VERSION 5.8 ;
BUSBITCHARS "[]" ;
DIVIDERCHAR "/" ;
UNITS
    DATABASE MICRONS 1000 ;
END UNITS

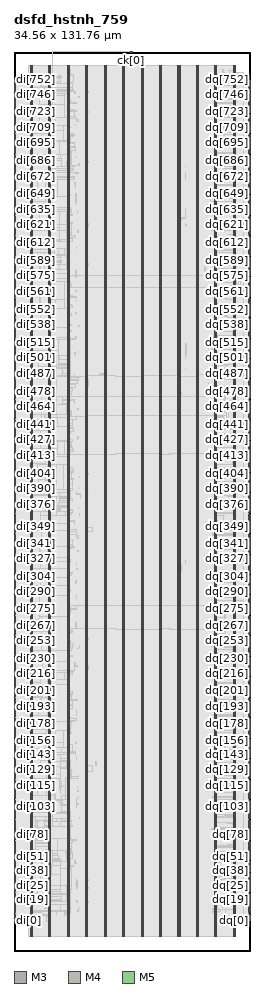
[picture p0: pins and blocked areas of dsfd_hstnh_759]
MACRO dsfd_hstnh_759
  FOREIGN dsfd_hstnh_759 0 0 ;
  CLASS BLOCK ;
  SIZE 34.56 BY 131.76 ;
  PIN ck[0]
    DIRECTION INPUT ;
    USE SIGNAL ;
    PORT
      LAYER M3 ;
        RECT  17.28 131.616 17.298 131.76 ;
    END
    PORT
      LAYER M3 ;
        RECT  17.1 131.515 17.298 131.628 ;
    END
  END ck[0]
  PIN di[0]
    DIRECTION INPUT ;
    USE SIGNAL ;
    PORT
      LAYER M4 ;
        RECT  0 4.416 0.192 4.44 ;
    END
  END di[0]
  PIN di[100]
    DIRECTION INPUT ;
    USE SIGNAL ;
    PORT
      LAYER M4 ;
        RECT  0 20.64 0.192 20.664 ;
    END
  END di[100]
  PIN di[101]
    DIRECTION INPUT ;
    USE SIGNAL ;
    PORT
      LAYER M4 ;
        RECT  0 20.784 0.192 20.808 ;
    END
  END di[101]
  PIN di[102]
    DIRECTION INPUT ;
    USE SIGNAL ;
    PORT
      LAYER M4 ;
        RECT  0 20.976 0.192 21 ;
    END
  END di[102]
  PIN di[103]
    DIRECTION INPUT ;
    USE SIGNAL ;
    PORT
      LAYER M4 ;
        RECT  0 21.12 0.192 21.144 ;
    END
  END di[103]
  PIN di[104]
    DIRECTION INPUT ;
    USE SIGNAL ;
    PORT
      LAYER M4 ;
        RECT  0 21.264 0.192 21.288 ;
    END
  END di[104]
  PIN di[105]
    DIRECTION INPUT ;
    USE SIGNAL ;
    PORT
      LAYER M4 ;
        RECT  0 21.456 0.192 21.48 ;
    END
  END di[105]
  PIN di[106]
    DIRECTION INPUT ;
    USE SIGNAL ;
    PORT
      LAYER M4 ;
        RECT  0 21.6 0.192 21.624 ;
    END
  END di[106]
  PIN di[107]
    DIRECTION INPUT ;
    USE SIGNAL ;
    PORT
      LAYER M4 ;
        RECT  0 21.792 0.192 21.816 ;
    END
  END di[107]
  PIN di[108]
    DIRECTION INPUT ;
    USE SIGNAL ;
    PORT
      LAYER M4 ;
        RECT  0 21.936 0.192 21.96 ;
    END
  END di[108]
  PIN di[109]
    DIRECTION INPUT ;
    USE SIGNAL ;
    PORT
      LAYER M4 ;
        RECT  0 22.08 0.192 22.104 ;
    END
  END di[109]
  PIN di[10]
    DIRECTION INPUT ;
    USE SIGNAL ;
    PORT
      LAYER M4 ;
        RECT  0 6.048 0.192 6.072 ;
    END
  END di[10]
  PIN di[110]
    DIRECTION INPUT ;
    USE SIGNAL ;
    PORT
      LAYER M4 ;
        RECT  0 22.272 0.192 22.296 ;
    END
  END di[110]
  PIN di[111]
    DIRECTION INPUT ;
    USE SIGNAL ;
    PORT
      LAYER M4 ;
        RECT  0 22.416 0.192 22.44 ;
    END
  END di[111]
  PIN di[112]
    DIRECTION INPUT ;
    USE SIGNAL ;
    PORT
      LAYER M4 ;
        RECT  0 22.56 0.192 22.584 ;
    END
  END di[112]
  PIN di[113]
    DIRECTION INPUT ;
    USE SIGNAL ;
    PORT
      LAYER M4 ;
        RECT  0 22.752 0.192 22.776 ;
    END
  END di[113]
  PIN di[114]
    DIRECTION INPUT ;
    USE SIGNAL ;
    PORT
      LAYER M4 ;
        RECT  0 22.896 0.192 22.92 ;
    END
  END di[114]
  PIN di[115]
    DIRECTION INPUT ;
    USE SIGNAL ;
    PORT
      LAYER M4 ;
        RECT  0 23.088 0.192 23.112 ;
    END
  END di[115]
  PIN di[116]
    DIRECTION INPUT ;
    USE SIGNAL ;
    PORT
      LAYER M4 ;
        RECT  0 23.232 0.192 23.256 ;
    END
  END di[116]
  PIN di[117]
    DIRECTION INPUT ;
    USE SIGNAL ;
    PORT
      LAYER M4 ;
        RECT  0 23.376 0.192 23.4 ;
    END
  END di[117]
  PIN di[118]
    DIRECTION INPUT ;
    USE SIGNAL ;
    PORT
      LAYER M4 ;
        RECT  0 23.568 0.192 23.592 ;
    END
  END di[118]
  PIN di[119]
    DIRECTION INPUT ;
    USE SIGNAL ;
    PORT
      LAYER M4 ;
        RECT  0 23.712 0.192 23.736 ;
    END
  END di[119]
  PIN di[11]
    DIRECTION INPUT ;
    USE SIGNAL ;
    PORT
      LAYER M4 ;
        RECT  0 6.192 0.192 6.216 ;
    END
  END di[11]
  PIN di[120]
    DIRECTION INPUT ;
    USE SIGNAL ;
    PORT
      LAYER M4 ;
        RECT  0 23.856 0.192 23.88 ;
    END
  END di[120]
  PIN di[121]
    DIRECTION INPUT ;
    USE SIGNAL ;
    PORT
      LAYER M4 ;
        RECT  0 24.048 0.192 24.072 ;
    END
  END di[121]
  PIN di[122]
    DIRECTION INPUT ;
    USE SIGNAL ;
    PORT
      LAYER M4 ;
        RECT  0 24.192 0.192 24.216 ;
    END
  END di[122]
  PIN di[123]
    DIRECTION INPUT ;
    USE SIGNAL ;
    PORT
      LAYER M4 ;
        RECT  0 24.384 0.192 24.408 ;
    END
  END di[123]
  PIN di[124]
    DIRECTION INPUT ;
    USE SIGNAL ;
    PORT
      LAYER M4 ;
        RECT  0 24.528 0.192 24.552 ;
    END
  END di[124]
  PIN di[125]
    DIRECTION INPUT ;
    USE SIGNAL ;
    PORT
      LAYER M4 ;
        RECT  0 24.672 0.192 24.696 ;
    END
  END di[125]
  PIN di[126]
    DIRECTION INPUT ;
    USE SIGNAL ;
    PORT
      LAYER M4 ;
        RECT  0 24.864 0.192 24.888 ;
    END
  END di[126]
  PIN di[127]
    DIRECTION INPUT ;
    USE SIGNAL ;
    PORT
      LAYER M4 ;
        RECT  0 25.008 0.192 25.032 ;
    END
  END di[127]
  PIN di[128]
    DIRECTION INPUT ;
    USE SIGNAL ;
    PORT
      LAYER M4 ;
        RECT  0 25.2 0.192 25.224 ;
    END
  END di[128]
  PIN di[129]
    DIRECTION INPUT ;
    USE SIGNAL ;
    PORT
      LAYER M4 ;
        RECT  0 25.344 0.192 25.368 ;
    END
  END di[129]
  PIN di[12]
    DIRECTION INPUT ;
    USE SIGNAL ;
    PORT
      LAYER M4 ;
        RECT  0 6.336 0.192 6.36 ;
    END
  END di[12]
  PIN di[130]
    DIRECTION INPUT ;
    USE SIGNAL ;
    PORT
      LAYER M4 ;
        RECT  0 25.488 0.192 25.512 ;
    END
  END di[130]
  PIN di[131]
    DIRECTION INPUT ;
    USE SIGNAL ;
    PORT
      LAYER M4 ;
        RECT  0 25.68 0.192 25.704 ;
    END
  END di[131]
  PIN di[132]
    DIRECTION INPUT ;
    USE SIGNAL ;
    PORT
      LAYER M4 ;
        RECT  0 25.824 0.192 25.848 ;
    END
  END di[132]
  PIN di[133]
    DIRECTION INPUT ;
    USE SIGNAL ;
    PORT
      LAYER M4 ;
        RECT  0 25.968 0.192 25.992 ;
    END
  END di[133]
  PIN di[134]
    DIRECTION INPUT ;
    USE SIGNAL ;
    PORT
      LAYER M4 ;
        RECT  0 26.16 0.192 26.184 ;
    END
  END di[134]
  PIN di[135]
    DIRECTION INPUT ;
    USE SIGNAL ;
    PORT
      LAYER M4 ;
        RECT  0 26.304 0.192 26.328 ;
    END
  END di[135]
  PIN di[136]
    DIRECTION INPUT ;
    USE SIGNAL ;
    PORT
      LAYER M4 ;
        RECT  0 26.496 0.192 26.52 ;
    END
  END di[136]
  PIN di[137]
    DIRECTION INPUT ;
    USE SIGNAL ;
    PORT
      LAYER M4 ;
        RECT  0 26.64 0.192 26.664 ;
    END
  END di[137]
  PIN di[138]
    DIRECTION INPUT ;
    USE SIGNAL ;
    PORT
      LAYER M4 ;
        RECT  0 26.784 0.192 26.808 ;
    END
  END di[138]
  PIN di[139]
    DIRECTION INPUT ;
    USE SIGNAL ;
    PORT
      LAYER M4 ;
        RECT  0 26.976 0.192 27 ;
    END
  END di[139]
  PIN di[13]
    DIRECTION INPUT ;
    USE SIGNAL ;
    PORT
      LAYER M4 ;
        RECT  0 6.528 0.192 6.552 ;
    END
  END di[13]
  PIN di[140]
    DIRECTION INPUT ;
    USE SIGNAL ;
    PORT
      LAYER M4 ;
        RECT  0 27.12 0.192 27.144 ;
    END
  END di[140]
  PIN di[141]
    DIRECTION INPUT ;
    USE SIGNAL ;
    PORT
      LAYER M4 ;
        RECT  0 27.264 0.192 27.288 ;
    END
  END di[141]
  PIN di[142]
    DIRECTION INPUT ;
    USE SIGNAL ;
    PORT
      LAYER M4 ;
        RECT  0 27.456 0.192 27.48 ;
    END
  END di[142]
  PIN di[143]
    DIRECTION INPUT ;
    USE SIGNAL ;
    PORT
      LAYER M4 ;
        RECT  0 27.6 0.192 27.624 ;
    END
  END di[143]
  PIN di[144]
    DIRECTION INPUT ;
    USE SIGNAL ;
    PORT
      LAYER M4 ;
        RECT  0 27.792 0.192 27.816 ;
    END
  END di[144]
  PIN di[145]
    DIRECTION INPUT ;
    USE SIGNAL ;
    PORT
      LAYER M4 ;
        RECT  0 27.936 0.192 27.96 ;
    END
  END di[145]
  PIN di[146]
    DIRECTION INPUT ;
    USE SIGNAL ;
    PORT
      LAYER M4 ;
        RECT  0 28.08 0.192 28.104 ;
    END
  END di[146]
  PIN di[147]
    DIRECTION INPUT ;
    USE SIGNAL ;
    PORT
      LAYER M4 ;
        RECT  0 28.272 0.192 28.296 ;
    END
  END di[147]
  PIN di[148]
    DIRECTION INPUT ;
    USE SIGNAL ;
    PORT
      LAYER M4 ;
        RECT  0 28.416 0.192 28.44 ;
    END
  END di[148]
  PIN di[149]
    DIRECTION INPUT ;
    USE SIGNAL ;
    PORT
      LAYER M4 ;
        RECT  0 28.56 0.192 28.584 ;
    END
  END di[149]
  PIN di[14]
    DIRECTION INPUT ;
    USE SIGNAL ;
    PORT
      LAYER M4 ;
        RECT  0 6.672 0.192 6.696 ;
    END
  END di[14]
  PIN di[150]
    DIRECTION INPUT ;
    USE SIGNAL ;
    PORT
      LAYER M4 ;
        RECT  0 28.752 0.192 28.776 ;
    END
  END di[150]
  PIN di[151]
    DIRECTION INPUT ;
    USE SIGNAL ;
    PORT
      LAYER M4 ;
        RECT  0 28.896 0.192 28.92 ;
    END
  END di[151]
  PIN di[152]
    DIRECTION INPUT ;
    USE SIGNAL ;
    PORT
      LAYER M4 ;
        RECT  0 29.088 0.192 29.112 ;
    END
  END di[152]
  PIN di[153]
    DIRECTION INPUT ;
    USE SIGNAL ;
    PORT
      LAYER M4 ;
        RECT  0 29.232 0.192 29.256 ;
    END
  END di[153]
  PIN di[154]
    DIRECTION INPUT ;
    USE SIGNAL ;
    PORT
      LAYER M4 ;
        RECT  0 29.376 0.192 29.4 ;
    END
  END di[154]
  PIN di[155]
    DIRECTION INPUT ;
    USE SIGNAL ;
    PORT
      LAYER M4 ;
        RECT  0 29.568 0.192 29.592 ;
    END
  END di[155]
  PIN di[156]
    DIRECTION INPUT ;
    USE SIGNAL ;
    PORT
      LAYER M4 ;
        RECT  0 29.712 0.192 29.736 ;
    END
  END di[156]
  PIN di[157]
    DIRECTION INPUT ;
    USE SIGNAL ;
    PORT
      LAYER M4 ;
        RECT  0 29.904 0.192 29.928 ;
    END
  END di[157]
  PIN di[158]
    DIRECTION INPUT ;
    USE SIGNAL ;
    PORT
      LAYER M4 ;
        RECT  0 30.048 0.192 30.072 ;
    END
  END di[158]
  PIN di[159]
    DIRECTION INPUT ;
    USE SIGNAL ;
    PORT
      LAYER M4 ;
        RECT  0 30.192 0.192 30.216 ;
    END
  END di[159]
  PIN di[15]
    DIRECTION INPUT ;
    USE SIGNAL ;
    PORT
      LAYER M4 ;
        RECT  0 6.864 0.192 6.888 ;
    END
  END di[15]
  PIN di[160]
    DIRECTION INPUT ;
    USE SIGNAL ;
    PORT
      LAYER M4 ;
        RECT  0 30.384 0.192 30.408 ;
    END
  END di[160]
  PIN di[161]
    DIRECTION INPUT ;
    USE SIGNAL ;
    PORT
      LAYER M4 ;
        RECT  0 30.528 0.192 30.552 ;
    END
  END di[161]
  PIN di[162]
    DIRECTION INPUT ;
    USE SIGNAL ;
    PORT
      LAYER M4 ;
        RECT  0 30.672 0.192 30.696 ;
    END
  END di[162]
  PIN di[163]
    DIRECTION INPUT ;
    USE SIGNAL ;
    PORT
      LAYER M4 ;
        RECT  0 30.864 0.192 30.888 ;
    END
  END di[163]
  PIN di[164]
    DIRECTION INPUT ;
    USE SIGNAL ;
    PORT
      LAYER M4 ;
        RECT  0 31.008 0.192 31.032 ;
    END
  END di[164]
  PIN di[165]
    DIRECTION INPUT ;
    USE SIGNAL ;
    PORT
      LAYER M4 ;
        RECT  0 31.2 0.192 31.224 ;
    END
  END di[165]
  PIN di[166]
    DIRECTION INPUT ;
    USE SIGNAL ;
    PORT
      LAYER M4 ;
        RECT  0 31.344 0.192 31.368 ;
    END
  END di[166]
  PIN di[167]
    DIRECTION INPUT ;
    USE SIGNAL ;
    PORT
      LAYER M4 ;
        RECT  0 31.488 0.192 31.512 ;
    END
  END di[167]
  PIN di[168]
    DIRECTION INPUT ;
    USE SIGNAL ;
    PORT
      LAYER M4 ;
        RECT  0 31.68 0.192 31.704 ;
    END
  END di[168]
  PIN di[169]
    DIRECTION INPUT ;
    USE SIGNAL ;
    PORT
      LAYER M4 ;
        RECT  0 31.824 0.192 31.848 ;
    END
  END di[169]
  PIN di[16]
    DIRECTION INPUT ;
    USE SIGNAL ;
    PORT
      LAYER M4 ;
        RECT  0 7.008 0.192 7.032 ;
    END
  END di[16]
  PIN di[170]
    DIRECTION INPUT ;
    USE SIGNAL ;
    PORT
      LAYER M4 ;
        RECT  0 31.968 0.192 31.992 ;
    END
  END di[170]
  PIN di[171]
    DIRECTION INPUT ;
    USE SIGNAL ;
    PORT
      LAYER M4 ;
        RECT  0 32.16 0.192 32.184 ;
    END
  END di[171]
  PIN di[172]
    DIRECTION INPUT ;
    USE SIGNAL ;
    PORT
      LAYER M4 ;
        RECT  0 32.304 0.192 32.328 ;
    END
  END di[172]
  PIN di[173]
    DIRECTION INPUT ;
    USE SIGNAL ;
    PORT
      LAYER M4 ;
        RECT  0 32.496 0.192 32.52 ;
    END
  END di[173]
  PIN di[174]
    DIRECTION INPUT ;
    USE SIGNAL ;
    PORT
      LAYER M4 ;
        RECT  0 32.64 0.192 32.664 ;
    END
  END di[174]
  PIN di[175]
    DIRECTION INPUT ;
    USE SIGNAL ;
    PORT
      LAYER M4 ;
        RECT  0 32.784 0.192 32.808 ;
    END
  END di[175]
  PIN di[176]
    DIRECTION INPUT ;
    USE SIGNAL ;
    PORT
      LAYER M4 ;
        RECT  0 32.976 0.192 33 ;
    END
  END di[176]
  PIN di[177]
    DIRECTION INPUT ;
    USE SIGNAL ;
    PORT
      LAYER M4 ;
        RECT  0 33.12 0.192 33.144 ;
    END
  END di[177]
  PIN di[178]
    DIRECTION INPUT ;
    USE SIGNAL ;
    PORT
      LAYER M4 ;
        RECT  0 33.264 0.192 33.288 ;
    END
  END di[178]
  PIN di[179]
    DIRECTION INPUT ;
    USE SIGNAL ;
    PORT
      LAYER M4 ;
        RECT  0 33.456 0.192 33.48 ;
    END
  END di[179]
  PIN di[17]
    DIRECTION INPUT ;
    USE SIGNAL ;
    PORT
      LAYER M4 ;
        RECT  0 7.152 0.192 7.176 ;
    END
  END di[17]
  PIN di[180]
    DIRECTION INPUT ;
    USE SIGNAL ;
    PORT
      LAYER M4 ;
        RECT  0 33.6 0.192 33.624 ;
    END
  END di[180]
  PIN di[181]
    DIRECTION INPUT ;
    USE SIGNAL ;
    PORT
      LAYER M4 ;
        RECT  0 33.792 0.192 33.816 ;
    END
  END di[181]
  PIN di[182]
    DIRECTION INPUT ;
    USE SIGNAL ;
    PORT
      LAYER M4 ;
        RECT  0 33.936 0.192 33.96 ;
    END
  END di[182]
  PIN di[183]
    DIRECTION INPUT ;
    USE SIGNAL ;
    PORT
      LAYER M4 ;
        RECT  0 34.08 0.192 34.104 ;
    END
  END di[183]
  PIN di[184]
    DIRECTION INPUT ;
    USE SIGNAL ;
    PORT
      LAYER M4 ;
        RECT  0 34.272 0.192 34.296 ;
    END
  END di[184]
  PIN di[185]
    DIRECTION INPUT ;
    USE SIGNAL ;
    PORT
      LAYER M4 ;
        RECT  0 34.416 0.192 34.44 ;
    END
  END di[185]
  PIN di[186]
    DIRECTION INPUT ;
    USE SIGNAL ;
    PORT
      LAYER M4 ;
        RECT  0 34.608 0.192 34.632 ;
    END
  END di[186]
  PIN di[187]
    DIRECTION INPUT ;
    USE SIGNAL ;
    PORT
      LAYER M4 ;
        RECT  0 34.752 0.192 34.776 ;
    END
  END di[187]
  PIN di[188]
    DIRECTION INPUT ;
    USE SIGNAL ;
    PORT
      LAYER M4 ;
        RECT  0 34.896 0.192 34.92 ;
    END
  END di[188]
  PIN di[189]
    DIRECTION INPUT ;
    USE SIGNAL ;
    PORT
      LAYER M4 ;
        RECT  0 35.088 0.192 35.112 ;
    END
  END di[189]
  PIN di[18]
    DIRECTION INPUT ;
    USE SIGNAL ;
    PORT
      LAYER M4 ;
        RECT  0 7.344 0.192 7.368 ;
    END
  END di[18]
  PIN di[190]
    DIRECTION INPUT ;
    USE SIGNAL ;
    PORT
      LAYER M4 ;
        RECT  0 35.232 0.192 35.256 ;
    END
  END di[190]
  PIN di[191]
    DIRECTION INPUT ;
    USE SIGNAL ;
    PORT
      LAYER M4 ;
        RECT  0 35.376 0.192 35.4 ;
    END
  END di[191]
  PIN di[192]
    DIRECTION INPUT ;
    USE SIGNAL ;
    PORT
      LAYER M4 ;
        RECT  0 35.568 0.192 35.592 ;
    END
  END di[192]
  PIN di[193]
    DIRECTION INPUT ;
    USE SIGNAL ;
    PORT
      LAYER M4 ;
        RECT  0 35.712 0.192 35.736 ;
    END
  END di[193]
  PIN di[194]
    DIRECTION INPUT ;
    USE SIGNAL ;
    PORT
      LAYER M4 ;
        RECT  0 35.904 0.192 35.928 ;
    END
  END di[194]
  PIN di[195]
    DIRECTION INPUT ;
    USE SIGNAL ;
    PORT
      LAYER M4 ;
        RECT  0 36.048 0.192 36.072 ;
    END
  END di[195]
  PIN di[196]
    DIRECTION INPUT ;
    USE SIGNAL ;
    PORT
      LAYER M4 ;
        RECT  0 36.192 0.192 36.216 ;
    END
  END di[196]
  PIN di[197]
    DIRECTION INPUT ;
    USE SIGNAL ;
    PORT
      LAYER M4 ;
        RECT  0 36.384 0.192 36.408 ;
    END
  END di[197]
  PIN di[198]
    DIRECTION INPUT ;
    USE SIGNAL ;
    PORT
      LAYER M4 ;
        RECT  0 36.528 0.192 36.552 ;
    END
  END di[198]
  PIN di[199]
    DIRECTION INPUT ;
    USE SIGNAL ;
    PORT
      LAYER M4 ;
        RECT  0 36.672 0.192 36.696 ;
    END
  END di[199]
  PIN di[19]
    DIRECTION INPUT ;
    USE SIGNAL ;
    PORT
      LAYER M4 ;
        RECT  0 7.488 0.192 7.512 ;
    END
  END di[19]
  PIN di[1]
    DIRECTION INPUT ;
    USE SIGNAL ;
    PORT
      LAYER M4 ;
        RECT  0 4.56 0.192 4.584 ;
    END
  END di[1]
  PIN di[200]
    DIRECTION INPUT ;
    USE SIGNAL ;
    PORT
      LAYER M4 ;
        RECT  0 36.864 0.192 36.888 ;
    END
  END di[200]
  PIN di[201]
    DIRECTION INPUT ;
    USE SIGNAL ;
    PORT
      LAYER M4 ;
        RECT  0 37.008 0.192 37.032 ;
    END
  END di[201]
  PIN di[202]
    DIRECTION INPUT ;
    USE SIGNAL ;
    PORT
      LAYER M4 ;
        RECT  0 37.2 0.192 37.224 ;
    END
  END di[202]
  PIN di[203]
    DIRECTION INPUT ;
    USE SIGNAL ;
    PORT
      LAYER M4 ;
        RECT  0 37.344 0.192 37.368 ;
    END
  END di[203]
  PIN di[204]
    DIRECTION INPUT ;
    USE SIGNAL ;
    PORT
      LAYER M4 ;
        RECT  0 37.488 0.192 37.512 ;
    END
  END di[204]
  PIN di[205]
    DIRECTION INPUT ;
    USE SIGNAL ;
    PORT
      LAYER M4 ;
        RECT  0 37.68 0.192 37.704 ;
    END
  END di[205]
  PIN di[206]
    DIRECTION INPUT ;
    USE SIGNAL ;
    PORT
      LAYER M4 ;
        RECT  0 37.824 0.192 37.848 ;
    END
  END di[206]
  PIN di[207]
    DIRECTION INPUT ;
    USE SIGNAL ;
    PORT
      LAYER M4 ;
        RECT  0 37.968 0.192 37.992 ;
    END
  END di[207]
  PIN di[208]
    DIRECTION INPUT ;
    USE SIGNAL ;
    PORT
      LAYER M4 ;
        RECT  0 38.16 0.192 38.184 ;
    END
  END di[208]
  PIN di[209]
    DIRECTION INPUT ;
    USE SIGNAL ;
    PORT
      LAYER M4 ;
        RECT  0 38.304 0.192 38.328 ;
    END
  END di[209]
  PIN di[20]
    DIRECTION INPUT ;
    USE SIGNAL ;
    PORT
      LAYER M4 ;
        RECT  0 7.68 0.192 7.704 ;
    END
  END di[20]
  PIN di[210]
    DIRECTION INPUT ;
    USE SIGNAL ;
    PORT
      LAYER M4 ;
        RECT  0 38.496 0.192 38.52 ;
    END
  END di[210]
  PIN di[211]
    DIRECTION INPUT ;
    USE SIGNAL ;
    PORT
      LAYER M4 ;
        RECT  0 38.64 0.192 38.664 ;
    END
  END di[211]
  PIN di[212]
    DIRECTION INPUT ;
    USE SIGNAL ;
    PORT
      LAYER M4 ;
        RECT  0 38.784 0.192 38.808 ;
    END
  END di[212]
  PIN di[213]
    DIRECTION INPUT ;
    USE SIGNAL ;
    PORT
      LAYER M4 ;
        RECT  0 38.976 0.192 39 ;
    END
  END di[213]
  PIN di[214]
    DIRECTION INPUT ;
    USE SIGNAL ;
    PORT
      LAYER M4 ;
        RECT  0 39.12 0.192 39.144 ;
    END
  END di[214]
  PIN di[215]
    DIRECTION INPUT ;
    USE SIGNAL ;
    PORT
      LAYER M4 ;
        RECT  0 39.312 0.192 39.336 ;
    END
  END di[215]
  PIN di[216]
    DIRECTION INPUT ;
    USE SIGNAL ;
    PORT
      LAYER M4 ;
        RECT  0 39.456 0.192 39.48 ;
    END
  END di[216]
  PIN di[217]
    DIRECTION INPUT ;
    USE SIGNAL ;
    PORT
      LAYER M4 ;
        RECT  0 39.6 0.192 39.624 ;
    END
  END di[217]
  PIN di[218]
    DIRECTION INPUT ;
    USE SIGNAL ;
    PORT
      LAYER M4 ;
        RECT  0 39.792 0.192 39.816 ;
    END
  END di[218]
  PIN di[219]
    DIRECTION INPUT ;
    USE SIGNAL ;
    PORT
      LAYER M4 ;
        RECT  0 39.936 0.192 39.96 ;
    END
  END di[219]
  PIN di[21]
    DIRECTION INPUT ;
    USE SIGNAL ;
    PORT
      LAYER M4 ;
        RECT  0 7.824 0.192 7.848 ;
    END
  END di[21]
  PIN di[220]
    DIRECTION INPUT ;
    USE SIGNAL ;
    PORT
      LAYER M4 ;
        RECT  0 40.08 0.192 40.104 ;
    END
  END di[220]
  PIN di[221]
    DIRECTION INPUT ;
    USE SIGNAL ;
    PORT
      LAYER M4 ;
        RECT  0 40.272 0.192 40.296 ;
    END
  END di[221]
  PIN di[222]
    DIRECTION INPUT ;
    USE SIGNAL ;
    PORT
      LAYER M4 ;
        RECT  0 40.416 0.192 40.44 ;
    END
  END di[222]
  PIN di[223]
    DIRECTION INPUT ;
    USE SIGNAL ;
    PORT
      LAYER M4 ;
        RECT  0 40.608 0.192 40.632 ;
    END
  END di[223]
  PIN di[224]
    DIRECTION INPUT ;
    USE SIGNAL ;
    PORT
      LAYER M4 ;
        RECT  0 40.752 0.192 40.776 ;
    END
  END di[224]
  PIN di[225]
    DIRECTION INPUT ;
    USE SIGNAL ;
    PORT
      LAYER M4 ;
        RECT  0 40.896 0.192 40.92 ;
    END
  END di[225]
  PIN di[226]
    DIRECTION INPUT ;
    USE SIGNAL ;
    PORT
      LAYER M4 ;
        RECT  0 41.088 0.192 41.112 ;
    END
  END di[226]
  PIN di[227]
    DIRECTION INPUT ;
    USE SIGNAL ;
    PORT
      LAYER M4 ;
        RECT  0 41.232 0.192 41.256 ;
    END
  END di[227]
  PIN di[228]
    DIRECTION INPUT ;
    USE SIGNAL ;
    PORT
      LAYER M4 ;
        RECT  0 41.376 0.192 41.4 ;
    END
  END di[228]
  PIN di[229]
    DIRECTION INPUT ;
    USE SIGNAL ;
    PORT
      LAYER M4 ;
        RECT  0 41.568 0.192 41.592 ;
    END
  END di[229]
  PIN di[22]
    DIRECTION INPUT ;
    USE SIGNAL ;
    PORT
      LAYER M4 ;
        RECT  0 7.968 0.192 7.992 ;
    END
  END di[22]
  PIN di[230]
    DIRECTION INPUT ;
    USE SIGNAL ;
    PORT
      LAYER M4 ;
        RECT  0 41.712 0.192 41.736 ;
    END
  END di[230]
  PIN di[231]
    DIRECTION INPUT ;
    USE SIGNAL ;
    PORT
      LAYER M4 ;
        RECT  0 41.904 0.192 41.928 ;
    END
  END di[231]
  PIN di[232]
    DIRECTION INPUT ;
    USE SIGNAL ;
    PORT
      LAYER M4 ;
        RECT  0 42.048 0.192 42.072 ;
    END
  END di[232]
  PIN di[233]
    DIRECTION INPUT ;
    USE SIGNAL ;
    PORT
      LAYER M4 ;
        RECT  0 42.192 0.192 42.216 ;
    END
  END di[233]
  PIN di[234]
    DIRECTION INPUT ;
    USE SIGNAL ;
    PORT
      LAYER M4 ;
        RECT  0 42.384 0.192 42.408 ;
    END
  END di[234]
  PIN di[235]
    DIRECTION INPUT ;
    USE SIGNAL ;
    PORT
      LAYER M4 ;
        RECT  0 42.528 0.192 42.552 ;
    END
  END di[235]
  PIN di[236]
    DIRECTION INPUT ;
    USE SIGNAL ;
    PORT
      LAYER M4 ;
        RECT  0 42.672 0.192 42.696 ;
    END
  END di[236]
  PIN di[237]
    DIRECTION INPUT ;
    USE SIGNAL ;
    PORT
      LAYER M4 ;
        RECT  0 42.864 0.192 42.888 ;
    END
  END di[237]
  PIN di[238]
    DIRECTION INPUT ;
    USE SIGNAL ;
    PORT
      LAYER M4 ;
        RECT  0 43.008 0.192 43.032 ;
    END
  END di[238]
  PIN di[239]
    DIRECTION INPUT ;
    USE SIGNAL ;
    PORT
      LAYER M4 ;
        RECT  0 43.2 0.192 43.224 ;
    END
  END di[239]
  PIN di[23]
    DIRECTION INPUT ;
    USE SIGNAL ;
    PORT
      LAYER M4 ;
        RECT  0 8.16 0.192 8.184 ;
    END
  END di[23]
  PIN di[240]
    DIRECTION INPUT ;
    USE SIGNAL ;
    PORT
      LAYER M4 ;
        RECT  0 43.344 0.192 43.368 ;
    END
  END di[240]
  PIN di[241]
    DIRECTION INPUT ;
    USE SIGNAL ;
    PORT
      LAYER M4 ;
        RECT  0 43.488 0.192 43.512 ;
    END
  END di[241]
  PIN di[242]
    DIRECTION INPUT ;
    USE SIGNAL ;
    PORT
      LAYER M4 ;
        RECT  0 43.68 0.192 43.704 ;
    END
  END di[242]
  PIN di[243]
    DIRECTION INPUT ;
    USE SIGNAL ;
    PORT
      LAYER M4 ;
        RECT  0 43.824 0.192 43.848 ;
    END
  END di[243]
  PIN di[244]
    DIRECTION INPUT ;
    USE SIGNAL ;
    PORT
      LAYER M4 ;
        RECT  0 44.016 0.192 44.04 ;
    END
  END di[244]
  PIN di[245]
    DIRECTION INPUT ;
    USE SIGNAL ;
    PORT
      LAYER M4 ;
        RECT  0 44.16 0.192 44.184 ;
    END
  END di[245]
  PIN di[246]
    DIRECTION INPUT ;
    USE SIGNAL ;
    PORT
      LAYER M4 ;
        RECT  0 44.304 0.192 44.328 ;
    END
  END di[246]
  PIN di[247]
    DIRECTION INPUT ;
    USE SIGNAL ;
    PORT
      LAYER M4 ;
        RECT  0 44.496 0.192 44.52 ;
    END
  END di[247]
  PIN di[248]
    DIRECTION INPUT ;
    USE SIGNAL ;
    PORT
      LAYER M4 ;
        RECT  0 44.64 0.192 44.664 ;
    END
  END di[248]
  PIN di[249]
    DIRECTION INPUT ;
    USE SIGNAL ;
    PORT
      LAYER M4 ;
        RECT  0 44.784 0.192 44.808 ;
    END
  END di[249]
  PIN di[24]
    DIRECTION INPUT ;
    USE SIGNAL ;
    PORT
      LAYER M4 ;
        RECT  0 8.304 0.192 8.328 ;
    END
  END di[24]
  PIN di[250]
    DIRECTION INPUT ;
    USE SIGNAL ;
    PORT
      LAYER M4 ;
        RECT  0 44.976 0.192 45 ;
    END
  END di[250]
  PIN di[251]
    DIRECTION INPUT ;
    USE SIGNAL ;
    PORT
      LAYER M4 ;
        RECT  0 45.12 0.192 45.144 ;
    END
  END di[251]
  PIN di[252]
    DIRECTION INPUT ;
    USE SIGNAL ;
    PORT
      LAYER M4 ;
        RECT  0 45.312 0.192 45.336 ;
    END
  END di[252]
  PIN di[253]
    DIRECTION INPUT ;
    USE SIGNAL ;
    PORT
      LAYER M4 ;
        RECT  0 45.456 0.192 45.48 ;
    END
  END di[253]
  PIN di[254]
    DIRECTION INPUT ;
    USE SIGNAL ;
    PORT
      LAYER M4 ;
        RECT  0 45.6 0.192 45.624 ;
    END
  END di[254]
  PIN di[255]
    DIRECTION INPUT ;
    USE SIGNAL ;
    PORT
      LAYER M4 ;
        RECT  0 45.792 0.192 45.816 ;
    END
  END di[255]
  PIN di[256]
    DIRECTION INPUT ;
    USE SIGNAL ;
    PORT
      LAYER M4 ;
        RECT  0 45.936 0.192 45.96 ;
    END
  END di[256]
  PIN di[257]
    DIRECTION INPUT ;
    USE SIGNAL ;
    PORT
      LAYER M4 ;
        RECT  0 46.08 0.192 46.104 ;
    END
  END di[257]
  PIN di[258]
    DIRECTION INPUT ;
    USE SIGNAL ;
    PORT
      LAYER M4 ;
        RECT  0 46.272 0.192 46.296 ;
    END
  END di[258]
  PIN di[259]
    DIRECTION INPUT ;
    USE SIGNAL ;
    PORT
      LAYER M4 ;
        RECT  0 46.416 0.192 46.44 ;
    END
  END di[259]
  PIN di[25]
    DIRECTION INPUT ;
    USE SIGNAL ;
    PORT
      LAYER M4 ;
        RECT  0 8.448 0.192 8.472 ;
    END
  END di[25]
  PIN di[260]
    DIRECTION INPUT ;
    USE SIGNAL ;
    PORT
      LAYER M4 ;
        RECT  0 46.608 0.192 46.632 ;
    END
  END di[260]
  PIN di[261]
    DIRECTION INPUT ;
    USE SIGNAL ;
    PORT
      LAYER M4 ;
        RECT  0 46.752 0.192 46.776 ;
    END
  END di[261]
  PIN di[262]
    DIRECTION INPUT ;
    USE SIGNAL ;
    PORT
      LAYER M4 ;
        RECT  0 46.896 0.192 46.92 ;
    END
  END di[262]
  PIN di[263]
    DIRECTION INPUT ;
    USE SIGNAL ;
    PORT
      LAYER M4 ;
        RECT  0 47.088 0.192 47.112 ;
    END
  END di[263]
  PIN di[264]
    DIRECTION INPUT ;
    USE SIGNAL ;
    PORT
      LAYER M4 ;
        RECT  0 47.232 0.192 47.256 ;
    END
  END di[264]
  PIN di[265]
    DIRECTION INPUT ;
    USE SIGNAL ;
    PORT
      LAYER M4 ;
        RECT  0 47.376 0.192 47.4 ;
    END
  END di[265]
  PIN di[266]
    DIRECTION INPUT ;
    USE SIGNAL ;
    PORT
      LAYER M4 ;
        RECT  0 47.568 0.192 47.592 ;
    END
  END di[266]
  PIN di[267]
    DIRECTION INPUT ;
    USE SIGNAL ;
    PORT
      LAYER M4 ;
        RECT  0 47.712 0.192 47.736 ;
    END
  END di[267]
  PIN di[268]
    DIRECTION INPUT ;
    USE SIGNAL ;
    PORT
      LAYER M4 ;
        RECT  0 47.904 0.192 47.928 ;
    END
  END di[268]
  PIN di[269]
    DIRECTION INPUT ;
    USE SIGNAL ;
    PORT
      LAYER M4 ;
        RECT  0 48.048 0.192 48.072 ;
    END
  END di[269]
  PIN di[26]
    DIRECTION INPUT ;
    USE SIGNAL ;
    PORT
      LAYER M4 ;
        RECT  0 8.64 0.192 8.664 ;
    END
  END di[26]
  PIN di[270]
    DIRECTION INPUT ;
    USE SIGNAL ;
    PORT
      LAYER M4 ;
        RECT  0 48.192 0.192 48.216 ;
    END
  END di[270]
  PIN di[271]
    DIRECTION INPUT ;
    USE SIGNAL ;
    PORT
      LAYER M4 ;
        RECT  0 48.384 0.192 48.408 ;
    END
  END di[271]
  PIN di[272]
    DIRECTION INPUT ;
    USE SIGNAL ;
    PORT
      LAYER M4 ;
        RECT  0 48.528 0.192 48.552 ;
    END
  END di[272]
  PIN di[273]
    DIRECTION INPUT ;
    USE SIGNAL ;
    PORT
      LAYER M4 ;
        RECT  0 48.72 0.192 48.744 ;
    END
  END di[273]
  PIN di[274]
    DIRECTION INPUT ;
    USE SIGNAL ;
    PORT
      LAYER M4 ;
        RECT  0 48.864 0.192 48.888 ;
    END
  END di[274]
  PIN di[275]
    DIRECTION INPUT ;
    USE SIGNAL ;
    PORT
      LAYER M4 ;
        RECT  0 49.008 0.192 49.032 ;
    END
  END di[275]
  PIN di[276]
    DIRECTION INPUT ;
    USE SIGNAL ;
    PORT
      LAYER M4 ;
        RECT  0 49.2 0.192 49.224 ;
    END
  END di[276]
  PIN di[277]
    DIRECTION INPUT ;
    USE SIGNAL ;
    PORT
      LAYER M4 ;
        RECT  0 49.344 0.192 49.368 ;
    END
  END di[277]
  PIN di[278]
    DIRECTION INPUT ;
    USE SIGNAL ;
    PORT
      LAYER M4 ;
        RECT  0 49.488 0.192 49.512 ;
    END
  END di[278]
  PIN di[279]
    DIRECTION INPUT ;
    USE SIGNAL ;
    PORT
      LAYER M4 ;
        RECT  0 49.68 0.192 49.704 ;
    END
  END di[279]
  PIN di[27]
    DIRECTION INPUT ;
    USE SIGNAL ;
    PORT
      LAYER M4 ;
        RECT  0 8.784 0.192 8.808 ;
    END
  END di[27]
  PIN di[280]
    DIRECTION INPUT ;
    USE SIGNAL ;
    PORT
      LAYER M4 ;
        RECT  0 49.824 0.192 49.848 ;
    END
  END di[280]
  PIN di[281]
    DIRECTION INPUT ;
    USE SIGNAL ;
    PORT
      LAYER M4 ;
        RECT  0 50.016 0.192 50.04 ;
    END
  END di[281]
  PIN di[282]
    DIRECTION INPUT ;
    USE SIGNAL ;
    PORT
      LAYER M4 ;
        RECT  0 50.16 0.192 50.184 ;
    END
  END di[282]
  PIN di[283]
    DIRECTION INPUT ;
    USE SIGNAL ;
    PORT
      LAYER M4 ;
        RECT  0 50.304 0.192 50.328 ;
    END
  END di[283]
  PIN di[284]
    DIRECTION INPUT ;
    USE SIGNAL ;
    PORT
      LAYER M4 ;
        RECT  0 50.496 0.192 50.52 ;
    END
  END di[284]
  PIN di[285]
    DIRECTION INPUT ;
    USE SIGNAL ;
    PORT
      LAYER M4 ;
        RECT  0 50.64 0.192 50.664 ;
    END
  END di[285]
  PIN di[286]
    DIRECTION INPUT ;
    USE SIGNAL ;
    PORT
      LAYER M4 ;
        RECT  0 50.784 0.192 50.808 ;
    END
  END di[286]
  PIN di[287]
    DIRECTION INPUT ;
    USE SIGNAL ;
    PORT
      LAYER M4 ;
        RECT  0 50.976 0.192 51 ;
    END
  END di[287]
  PIN di[288]
    DIRECTION INPUT ;
    USE SIGNAL ;
    PORT
      LAYER M4 ;
        RECT  0 51.12 0.192 51.144 ;
    END
  END di[288]
  PIN di[289]
    DIRECTION INPUT ;
    USE SIGNAL ;
    PORT
      LAYER M4 ;
        RECT  0 51.312 0.192 51.336 ;
    END
  END di[289]
  PIN di[28]
    DIRECTION INPUT ;
    USE SIGNAL ;
    PORT
      LAYER M4 ;
        RECT  0 8.976 0.192 9 ;
    END
  END di[28]
  PIN di[290]
    DIRECTION INPUT ;
    USE SIGNAL ;
    PORT
      LAYER M4 ;
        RECT  0 51.456 0.192 51.48 ;
    END
  END di[290]
  PIN di[291]
    DIRECTION INPUT ;
    USE SIGNAL ;
    PORT
      LAYER M4 ;
        RECT  0 51.6 0.192 51.624 ;
    END
  END di[291]
  PIN di[292]
    DIRECTION INPUT ;
    USE SIGNAL ;
    PORT
      LAYER M4 ;
        RECT  0 51.792 0.192 51.816 ;
    END
  END di[292]
  PIN di[293]
    DIRECTION INPUT ;
    USE SIGNAL ;
    PORT
      LAYER M4 ;
        RECT  0 51.936 0.192 51.96 ;
    END
  END di[293]
  PIN di[294]
    DIRECTION INPUT ;
    USE SIGNAL ;
    PORT
      LAYER M4 ;
        RECT  0 52.08 0.192 52.104 ;
    END
  END di[294]
  PIN di[295]
    DIRECTION INPUT ;
    USE SIGNAL ;
    PORT
      LAYER M4 ;
        RECT  0 52.272 0.192 52.296 ;
    END
  END di[295]
  PIN di[296]
    DIRECTION INPUT ;
    USE SIGNAL ;
    PORT
      LAYER M4 ;
        RECT  0 52.416 0.192 52.44 ;
    END
  END di[296]
  PIN di[297]
    DIRECTION INPUT ;
    USE SIGNAL ;
    PORT
      LAYER M4 ;
        RECT  0 52.608 0.192 52.632 ;
    END
  END di[297]
  PIN di[298]
    DIRECTION INPUT ;
    USE SIGNAL ;
    PORT
      LAYER M4 ;
        RECT  0 52.752 0.192 52.776 ;
    END
  END di[298]
  PIN di[299]
    DIRECTION INPUT ;
    USE SIGNAL ;
    PORT
      LAYER M4 ;
        RECT  0 52.896 0.192 52.92 ;
    END
  END di[299]
  PIN di[29]
    DIRECTION INPUT ;
    USE SIGNAL ;
    PORT
      LAYER M4 ;
        RECT  0 9.12 0.192 9.144 ;
    END
  END di[29]
  PIN di[2]
    DIRECTION INPUT ;
    USE SIGNAL ;
    PORT
      LAYER M4 ;
        RECT  0 4.752 0.192 4.776 ;
    END
  END di[2]
  PIN di[300]
    DIRECTION INPUT ;
    USE SIGNAL ;
    PORT
      LAYER M4 ;
        RECT  0 53.088 0.192 53.112 ;
    END
  END di[300]
  PIN di[301]
    DIRECTION INPUT ;
    USE SIGNAL ;
    PORT
      LAYER M4 ;
        RECT  0 53.232 0.192 53.256 ;
    END
  END di[301]
  PIN di[302]
    DIRECTION INPUT ;
    USE SIGNAL ;
    PORT
      LAYER M4 ;
        RECT  0 53.424 0.192 53.448 ;
    END
  END di[302]
  PIN di[303]
    DIRECTION INPUT ;
    USE SIGNAL ;
    PORT
      LAYER M4 ;
        RECT  0 53.568 0.192 53.592 ;
    END
  END di[303]
  PIN di[304]
    DIRECTION INPUT ;
    USE SIGNAL ;
    PORT
      LAYER M4 ;
        RECT  0 53.712 0.192 53.736 ;
    END
  END di[304]
  PIN di[305]
    DIRECTION INPUT ;
    USE SIGNAL ;
    PORT
      LAYER M4 ;
        RECT  0 53.904 0.192 53.928 ;
    END
  END di[305]
  PIN di[306]
    DIRECTION INPUT ;
    USE SIGNAL ;
    PORT
      LAYER M4 ;
        RECT  0 54.048 0.192 54.072 ;
    END
  END di[306]
  PIN di[307]
    DIRECTION INPUT ;
    USE SIGNAL ;
    PORT
      LAYER M4 ;
        RECT  0 54.192 0.192 54.216 ;
    END
  END di[307]
  PIN di[308]
    DIRECTION INPUT ;
    USE SIGNAL ;
    PORT
      LAYER M4 ;
        RECT  0 54.384 0.192 54.408 ;
    END
  END di[308]
  PIN di[309]
    DIRECTION INPUT ;
    USE SIGNAL ;
    PORT
      LAYER M4 ;
        RECT  0 54.528 0.192 54.552 ;
    END
  END di[309]
  PIN di[30]
    DIRECTION INPUT ;
    USE SIGNAL ;
    PORT
      LAYER M4 ;
        RECT  0 9.264 0.192 9.288 ;
    END
  END di[30]
  PIN di[310]
    DIRECTION INPUT ;
    USE SIGNAL ;
    PORT
      LAYER M4 ;
        RECT  0 54.72 0.192 54.744 ;
    END
  END di[310]
  PIN di[311]
    DIRECTION INPUT ;
    USE SIGNAL ;
    PORT
      LAYER M4 ;
        RECT  0 54.864 0.192 54.888 ;
    END
  END di[311]
  PIN di[312]
    DIRECTION INPUT ;
    USE SIGNAL ;
    PORT
      LAYER M4 ;
        RECT  0 55.008 0.192 55.032 ;
    END
  END di[312]
  PIN di[313]
    DIRECTION INPUT ;
    USE SIGNAL ;
    PORT
      LAYER M4 ;
        RECT  0 55.2 0.192 55.224 ;
    END
  END di[313]
  PIN di[314]
    DIRECTION INPUT ;
    USE SIGNAL ;
    PORT
      LAYER M4 ;
        RECT  0 55.344 0.192 55.368 ;
    END
  END di[314]
  PIN di[315]
    DIRECTION INPUT ;
    USE SIGNAL ;
    PORT
      LAYER M4 ;
        RECT  0 55.488 0.192 55.512 ;
    END
  END di[315]
  PIN di[316]
    DIRECTION INPUT ;
    USE SIGNAL ;
    PORT
      LAYER M4 ;
        RECT  0 55.68 0.192 55.704 ;
    END
  END di[316]
  PIN di[317]
    DIRECTION INPUT ;
    USE SIGNAL ;
    PORT
      LAYER M4 ;
        RECT  0 55.824 0.192 55.848 ;
    END
  END di[317]
  PIN di[318]
    DIRECTION INPUT ;
    USE SIGNAL ;
    PORT
      LAYER M4 ;
        RECT  0 56.016 0.192 56.04 ;
    END
  END di[318]
  PIN di[319]
    DIRECTION INPUT ;
    USE SIGNAL ;
    PORT
      LAYER M4 ;
        RECT  0 56.16 0.192 56.184 ;
    END
  END di[319]
  PIN di[31]
    DIRECTION INPUT ;
    USE SIGNAL ;
    PORT
      LAYER M4 ;
        RECT  0 9.456 0.192 9.48 ;
    END
  END di[31]
  PIN di[320]
    DIRECTION INPUT ;
    USE SIGNAL ;
    PORT
      LAYER M4 ;
        RECT  0 56.304 0.192 56.328 ;
    END
  END di[320]
  PIN di[321]
    DIRECTION INPUT ;
    USE SIGNAL ;
    PORT
      LAYER M4 ;
        RECT  0 56.496 0.192 56.52 ;
    END
  END di[321]
  PIN di[322]
    DIRECTION INPUT ;
    USE SIGNAL ;
    PORT
      LAYER M4 ;
        RECT  0 56.64 0.192 56.664 ;
    END
  END di[322]
  PIN di[323]
    DIRECTION INPUT ;
    USE SIGNAL ;
    PORT
      LAYER M4 ;
        RECT  0 56.832 0.192 56.856 ;
    END
  END di[323]
  PIN di[324]
    DIRECTION INPUT ;
    USE SIGNAL ;
    PORT
      LAYER M4 ;
        RECT  0 56.976 0.192 57 ;
    END
  END di[324]
  PIN di[325]
    DIRECTION INPUT ;
    USE SIGNAL ;
    PORT
      LAYER M4 ;
        RECT  0 57.12 0.192 57.144 ;
    END
  END di[325]
  PIN di[326]
    DIRECTION INPUT ;
    USE SIGNAL ;
    PORT
      LAYER M4 ;
        RECT  0 57.312 0.192 57.336 ;
    END
  END di[326]
  PIN di[327]
    DIRECTION INPUT ;
    USE SIGNAL ;
    PORT
      LAYER M4 ;
        RECT  0 57.456 0.192 57.48 ;
    END
  END di[327]
  PIN di[328]
    DIRECTION INPUT ;
    USE SIGNAL ;
    PORT
      LAYER M4 ;
        RECT  0 57.6 0.192 57.624 ;
    END
  END di[328]
  PIN di[329]
    DIRECTION INPUT ;
    USE SIGNAL ;
    PORT
      LAYER M4 ;
        RECT  0 57.792 0.192 57.816 ;
    END
  END di[329]
  PIN di[32]
    DIRECTION INPUT ;
    USE SIGNAL ;
    PORT
      LAYER M4 ;
        RECT  0 9.6 0.192 9.624 ;
    END
  END di[32]
  PIN di[330]
    DIRECTION INPUT ;
    USE SIGNAL ;
    PORT
      LAYER M4 ;
        RECT  0 57.936 0.192 57.96 ;
    END
  END di[330]
  PIN di[331]
    DIRECTION INPUT ;
    USE SIGNAL ;
    PORT
      LAYER M4 ;
        RECT  0 58.128 0.192 58.152 ;
    END
  END di[331]
  PIN di[332]
    DIRECTION INPUT ;
    USE SIGNAL ;
    PORT
      LAYER M4 ;
        RECT  0 58.272 0.192 58.296 ;
    END
  END di[332]
  PIN di[333]
    DIRECTION INPUT ;
    USE SIGNAL ;
    PORT
      LAYER M4 ;
        RECT  0 58.416 0.192 58.44 ;
    END
  END di[333]
  PIN di[334]
    DIRECTION INPUT ;
    USE SIGNAL ;
    PORT
      LAYER M4 ;
        RECT  0 58.608 0.192 58.632 ;
    END
  END di[334]
  PIN di[335]
    DIRECTION INPUT ;
    USE SIGNAL ;
    PORT
      LAYER M4 ;
        RECT  0 58.752 0.192 58.776 ;
    END
  END di[335]
  PIN di[336]
    DIRECTION INPUT ;
    USE SIGNAL ;
    PORT
      LAYER M4 ;
        RECT  0 58.896 0.192 58.92 ;
    END
  END di[336]
  PIN di[337]
    DIRECTION INPUT ;
    USE SIGNAL ;
    PORT
      LAYER M4 ;
        RECT  0 59.088 0.192 59.112 ;
    END
  END di[337]
  PIN di[338]
    DIRECTION INPUT ;
    USE SIGNAL ;
    PORT
      LAYER M4 ;
        RECT  0 59.232 0.192 59.256 ;
    END
  END di[338]
  PIN di[339]
    DIRECTION INPUT ;
    USE SIGNAL ;
    PORT
      LAYER M4 ;
        RECT  0 59.424 0.192 59.448 ;
    END
  END di[339]
  PIN di[33]
    DIRECTION INPUT ;
    USE SIGNAL ;
    PORT
      LAYER M4 ;
        RECT  0 9.744 0.192 9.768 ;
    END
  END di[33]
  PIN di[340]
    DIRECTION INPUT ;
    USE SIGNAL ;
    PORT
      LAYER M4 ;
        RECT  0 59.568 0.192 59.592 ;
    END
  END di[340]
  PIN di[341]
    DIRECTION INPUT ;
    USE SIGNAL ;
    PORT
      LAYER M4 ;
        RECT  0 59.712 0.192 59.736 ;
    END
  END di[341]
  PIN di[342]
    DIRECTION INPUT ;
    USE SIGNAL ;
    PORT
      LAYER M4 ;
        RECT  0 59.904 0.192 59.928 ;
    END
  END di[342]
  PIN di[343]
    DIRECTION INPUT ;
    USE SIGNAL ;
    PORT
      LAYER M4 ;
        RECT  0 60.048 0.192 60.072 ;
    END
  END di[343]
  PIN di[344]
    DIRECTION INPUT ;
    USE SIGNAL ;
    PORT
      LAYER M4 ;
        RECT  0 60.192 0.192 60.216 ;
    END
  END di[344]
  PIN di[345]
    DIRECTION INPUT ;
    USE SIGNAL ;
    PORT
      LAYER M4 ;
        RECT  0 60.384 0.192 60.408 ;
    END
  END di[345]
  PIN di[346]
    DIRECTION INPUT ;
    USE SIGNAL ;
    PORT
      LAYER M4 ;
        RECT  0 60.528 0.192 60.552 ;
    END
  END di[346]
  PIN di[347]
    DIRECTION INPUT ;
    USE SIGNAL ;
    PORT
      LAYER M4 ;
        RECT  0 60.72 0.192 60.744 ;
    END
  END di[347]
  PIN di[348]
    DIRECTION INPUT ;
    USE SIGNAL ;
    PORT
      LAYER M4 ;
        RECT  0 60.864 0.192 60.888 ;
    END
  END di[348]
  PIN di[349]
    DIRECTION INPUT ;
    USE SIGNAL ;
    PORT
      LAYER M4 ;
        RECT  0 61.008 0.192 61.032 ;
    END
  END di[349]
  PIN di[34]
    DIRECTION INPUT ;
    USE SIGNAL ;
    PORT
      LAYER M4 ;
        RECT  0 9.936 0.192 9.96 ;
    END
  END di[34]
  PIN di[350]
    DIRECTION INPUT ;
    USE SIGNAL ;
    PORT
      LAYER M4 ;
        RECT  0 61.2 0.192 61.224 ;
    END
  END di[350]
  PIN di[351]
    DIRECTION INPUT ;
    USE SIGNAL ;
    PORT
      LAYER M4 ;
        RECT  0 61.344 0.192 61.368 ;
    END
  END di[351]
  PIN di[352]
    DIRECTION INPUT ;
    USE SIGNAL ;
    PORT
      LAYER M4 ;
        RECT  0 61.536 0.192 61.56 ;
    END
  END di[352]
  PIN di[353]
    DIRECTION INPUT ;
    USE SIGNAL ;
    PORT
      LAYER M4 ;
        RECT  0 61.68 0.192 61.704 ;
    END
  END di[353]
  PIN di[354]
    DIRECTION INPUT ;
    USE SIGNAL ;
    PORT
      LAYER M4 ;
        RECT  0 61.824 0.192 61.848 ;
    END
  END di[354]
  PIN di[355]
    DIRECTION INPUT ;
    USE SIGNAL ;
    PORT
      LAYER M4 ;
        RECT  0 62.016 0.192 62.04 ;
    END
  END di[355]
  PIN di[356]
    DIRECTION INPUT ;
    USE SIGNAL ;
    PORT
      LAYER M4 ;
        RECT  0 62.16 0.192 62.184 ;
    END
  END di[356]
  PIN di[357]
    DIRECTION INPUT ;
    USE SIGNAL ;
    PORT
      LAYER M4 ;
        RECT  0 62.304 0.192 62.328 ;
    END
  END di[357]
  PIN di[358]
    DIRECTION INPUT ;
    USE SIGNAL ;
    PORT
      LAYER M4 ;
        RECT  0 62.496 0.192 62.52 ;
    END
  END di[358]
  PIN di[359]
    DIRECTION INPUT ;
    USE SIGNAL ;
    PORT
      LAYER M4 ;
        RECT  0 62.64 0.192 62.664 ;
    END
  END di[359]
  PIN di[35]
    DIRECTION INPUT ;
    USE SIGNAL ;
    PORT
      LAYER M4 ;
        RECT  0 10.08 0.192 10.104 ;
    END
  END di[35]
  PIN di[360]
    DIRECTION INPUT ;
    USE SIGNAL ;
    PORT
      LAYER M4 ;
        RECT  0 62.832 0.192 62.856 ;
    END
  END di[360]
  PIN di[361]
    DIRECTION INPUT ;
    USE SIGNAL ;
    PORT
      LAYER M4 ;
        RECT  0 62.976 0.192 63 ;
    END
  END di[361]
  PIN di[362]
    DIRECTION INPUT ;
    USE SIGNAL ;
    PORT
      LAYER M4 ;
        RECT  0 63.12 0.192 63.144 ;
    END
  END di[362]
  PIN di[363]
    DIRECTION INPUT ;
    USE SIGNAL ;
    PORT
      LAYER M4 ;
        RECT  0 63.312 0.192 63.336 ;
    END
  END di[363]
  PIN di[364]
    DIRECTION INPUT ;
    USE SIGNAL ;
    PORT
      LAYER M4 ;
        RECT  0 63.456 0.192 63.48 ;
    END
  END di[364]
  PIN di[365]
    DIRECTION INPUT ;
    USE SIGNAL ;
    PORT
      LAYER M4 ;
        RECT  0 63.6 0.192 63.624 ;
    END
  END di[365]
  PIN di[366]
    DIRECTION INPUT ;
    USE SIGNAL ;
    PORT
      LAYER M4 ;
        RECT  0 63.792 0.192 63.816 ;
    END
  END di[366]
  PIN di[367]
    DIRECTION INPUT ;
    USE SIGNAL ;
    PORT
      LAYER M4 ;
        RECT  0 63.936 0.192 63.96 ;
    END
  END di[367]
  PIN di[368]
    DIRECTION INPUT ;
    USE SIGNAL ;
    PORT
      LAYER M4 ;
        RECT  0 64.128 0.192 64.152 ;
    END
  END di[368]
  PIN di[369]
    DIRECTION INPUT ;
    USE SIGNAL ;
    PORT
      LAYER M4 ;
        RECT  0 64.272 0.192 64.296 ;
    END
  END di[369]
  PIN di[36]
    DIRECTION INPUT ;
    USE SIGNAL ;
    PORT
      LAYER M4 ;
        RECT  0 10.272 0.192 10.296 ;
    END
  END di[36]
  PIN di[370]
    DIRECTION INPUT ;
    USE SIGNAL ;
    PORT
      LAYER M4 ;
        RECT  0 64.416 0.192 64.44 ;
    END
  END di[370]
  PIN di[371]
    DIRECTION INPUT ;
    USE SIGNAL ;
    PORT
      LAYER M4 ;
        RECT  0 64.608 0.192 64.632 ;
    END
  END di[371]
  PIN di[372]
    DIRECTION INPUT ;
    USE SIGNAL ;
    PORT
      LAYER M4 ;
        RECT  0 64.752 0.192 64.776 ;
    END
  END di[372]
  PIN di[373]
    DIRECTION INPUT ;
    USE SIGNAL ;
    PORT
      LAYER M4 ;
        RECT  0 64.896 0.192 64.92 ;
    END
  END di[373]
  PIN di[374]
    DIRECTION INPUT ;
    USE SIGNAL ;
    PORT
      LAYER M4 ;
        RECT  0 65.088 0.192 65.112 ;
    END
  END di[374]
  PIN di[375]
    DIRECTION INPUT ;
    USE SIGNAL ;
    PORT
      LAYER M4 ;
        RECT  0 65.232 0.192 65.256 ;
    END
  END di[375]
  PIN di[376]
    DIRECTION INPUT ;
    USE SIGNAL ;
    PORT
      LAYER M4 ;
        RECT  0 65.424 0.192 65.448 ;
    END
  END di[376]
  PIN di[377]
    DIRECTION INPUT ;
    USE SIGNAL ;
    PORT
      LAYER M4 ;
        RECT  0 65.568 0.192 65.592 ;
    END
  END di[377]
  PIN di[378]
    DIRECTION INPUT ;
    USE SIGNAL ;
    PORT
      LAYER M4 ;
        RECT  0 65.712 0.192 65.736 ;
    END
  END di[378]
  PIN di[379]
    DIRECTION INPUT ;
    USE SIGNAL ;
    PORT
      LAYER M4 ;
        RECT  0 65.904 0.192 65.928 ;
    END
  END di[379]
  PIN di[37]
    DIRECTION INPUT ;
    USE SIGNAL ;
    PORT
      LAYER M4 ;
        RECT  0 10.416 0.192 10.44 ;
    END
  END di[37]
  PIN di[380]
    DIRECTION INPUT ;
    USE SIGNAL ;
    PORT
      LAYER M4 ;
        RECT  0 66.048 0.192 66.072 ;
    END
  END di[380]
  PIN di[381]
    DIRECTION INPUT ;
    USE SIGNAL ;
    PORT
      LAYER M4 ;
        RECT  0 66.24 0.192 66.264 ;
    END
  END di[381]
  PIN di[382]
    DIRECTION INPUT ;
    USE SIGNAL ;
    PORT
      LAYER M4 ;
        RECT  0 66.384 0.192 66.408 ;
    END
  END di[382]
  PIN di[383]
    DIRECTION INPUT ;
    USE SIGNAL ;
    PORT
      LAYER M4 ;
        RECT  0 66.528 0.192 66.552 ;
    END
  END di[383]
  PIN di[384]
    DIRECTION INPUT ;
    USE SIGNAL ;
    PORT
      LAYER M4 ;
        RECT  0 66.72 0.192 66.744 ;
    END
  END di[384]
  PIN di[385]
    DIRECTION INPUT ;
    USE SIGNAL ;
    PORT
      LAYER M4 ;
        RECT  0 66.864 0.192 66.888 ;
    END
  END di[385]
  PIN di[386]
    DIRECTION INPUT ;
    USE SIGNAL ;
    PORT
      LAYER M4 ;
        RECT  0 67.008 0.192 67.032 ;
    END
  END di[386]
  PIN di[387]
    DIRECTION INPUT ;
    USE SIGNAL ;
    PORT
      LAYER M4 ;
        RECT  0 67.2 0.192 67.224 ;
    END
  END di[387]
  PIN di[388]
    DIRECTION INPUT ;
    USE SIGNAL ;
    PORT
      LAYER M4 ;
        RECT  0 67.344 0.192 67.368 ;
    END
  END di[388]
  PIN di[389]
    DIRECTION INPUT ;
    USE SIGNAL ;
    PORT
      LAYER M4 ;
        RECT  0 67.536 0.192 67.56 ;
    END
  END di[389]
  PIN di[38]
    DIRECTION INPUT ;
    USE SIGNAL ;
    PORT
      LAYER M4 ;
        RECT  0 10.56 0.192 10.584 ;
    END
  END di[38]
  PIN di[390]
    DIRECTION INPUT ;
    USE SIGNAL ;
    PORT
      LAYER M4 ;
        RECT  0 67.68 0.192 67.704 ;
    END
  END di[390]
  PIN di[391]
    DIRECTION INPUT ;
    USE SIGNAL ;
    PORT
      LAYER M4 ;
        RECT  0 67.824 0.192 67.848 ;
    END
  END di[391]
  PIN di[392]
    DIRECTION INPUT ;
    USE SIGNAL ;
    PORT
      LAYER M4 ;
        RECT  0 68.016 0.192 68.04 ;
    END
  END di[392]
  PIN di[393]
    DIRECTION INPUT ;
    USE SIGNAL ;
    PORT
      LAYER M4 ;
        RECT  0 68.16 0.192 68.184 ;
    END
  END di[393]
  PIN di[394]
    DIRECTION INPUT ;
    USE SIGNAL ;
    PORT
      LAYER M4 ;
        RECT  0 68.304 0.192 68.328 ;
    END
  END di[394]
  PIN di[395]
    DIRECTION INPUT ;
    USE SIGNAL ;
    PORT
      LAYER M4 ;
        RECT  0 68.496 0.192 68.52 ;
    END
  END di[395]
  PIN di[396]
    DIRECTION INPUT ;
    USE SIGNAL ;
    PORT
      LAYER M4 ;
        RECT  0 68.64 0.192 68.664 ;
    END
  END di[396]
  PIN di[397]
    DIRECTION INPUT ;
    USE SIGNAL ;
    PORT
      LAYER M4 ;
        RECT  0 68.832 0.192 68.856 ;
    END
  END di[397]
  PIN di[398]
    DIRECTION INPUT ;
    USE SIGNAL ;
    PORT
      LAYER M4 ;
        RECT  0 68.976 0.192 69 ;
    END
  END di[398]
  PIN di[399]
    DIRECTION INPUT ;
    USE SIGNAL ;
    PORT
      LAYER M4 ;
        RECT  0 69.12 0.192 69.144 ;
    END
  END di[399]
  PIN di[39]
    DIRECTION INPUT ;
    USE SIGNAL ;
    PORT
      LAYER M4 ;
        RECT  0 10.752 0.192 10.776 ;
    END
  END di[39]
  PIN di[3]
    DIRECTION INPUT ;
    USE SIGNAL ;
    PORT
      LAYER M4 ;
        RECT  0 4.896 0.192 4.92 ;
    END
  END di[3]
  PIN di[400]
    DIRECTION INPUT ;
    USE SIGNAL ;
    PORT
      LAYER M4 ;
        RECT  0 69.312 0.192 69.336 ;
    END
  END di[400]
  PIN di[401]
    DIRECTION INPUT ;
    USE SIGNAL ;
    PORT
      LAYER M4 ;
        RECT  0 69.456 0.192 69.48 ;
    END
  END di[401]
  PIN di[402]
    DIRECTION INPUT ;
    USE SIGNAL ;
    PORT
      LAYER M4 ;
        RECT  0 69.6 0.192 69.624 ;
    END
  END di[402]
  PIN di[403]
    DIRECTION INPUT ;
    USE SIGNAL ;
    PORT
      LAYER M4 ;
        RECT  0 69.792 0.192 69.816 ;
    END
  END di[403]
  PIN di[404]
    DIRECTION INPUT ;
    USE SIGNAL ;
    PORT
      LAYER M4 ;
        RECT  0 69.936 0.192 69.96 ;
    END
  END di[404]
  PIN di[405]
    DIRECTION INPUT ;
    USE SIGNAL ;
    PORT
      LAYER M4 ;
        RECT  0 70.128 0.192 70.152 ;
    END
  END di[405]
  PIN di[406]
    DIRECTION INPUT ;
    USE SIGNAL ;
    PORT
      LAYER M4 ;
        RECT  0 70.272 0.192 70.296 ;
    END
  END di[406]
  PIN di[407]
    DIRECTION INPUT ;
    USE SIGNAL ;
    PORT
      LAYER M4 ;
        RECT  0 70.416 0.192 70.44 ;
    END
  END di[407]
  PIN di[408]
    DIRECTION INPUT ;
    USE SIGNAL ;
    PORT
      LAYER M4 ;
        RECT  0 70.608 0.192 70.632 ;
    END
  END di[408]
  PIN di[409]
    DIRECTION INPUT ;
    USE SIGNAL ;
    PORT
      LAYER M4 ;
        RECT  0 70.752 0.192 70.776 ;
    END
  END di[409]
  PIN di[40]
    DIRECTION INPUT ;
    USE SIGNAL ;
    PORT
      LAYER M4 ;
        RECT  0 10.896 0.192 10.92 ;
    END
  END di[40]
  PIN di[410]
    DIRECTION INPUT ;
    USE SIGNAL ;
    PORT
      LAYER M4 ;
        RECT  0 70.944 0.192 70.968 ;
    END
  END di[410]
  PIN di[411]
    DIRECTION INPUT ;
    USE SIGNAL ;
    PORT
      LAYER M4 ;
        RECT  0 71.088 0.192 71.112 ;
    END
  END di[411]
  PIN di[412]
    DIRECTION INPUT ;
    USE SIGNAL ;
    PORT
      LAYER M4 ;
        RECT  0 71.232 0.192 71.256 ;
    END
  END di[412]
  PIN di[413]
    DIRECTION INPUT ;
    USE SIGNAL ;
    PORT
      LAYER M4 ;
        RECT  0 71.424 0.192 71.448 ;
    END
  END di[413]
  PIN di[414]
    DIRECTION INPUT ;
    USE SIGNAL ;
    PORT
      LAYER M4 ;
        RECT  0 71.568 0.192 71.592 ;
    END
  END di[414]
  PIN di[415]
    DIRECTION INPUT ;
    USE SIGNAL ;
    PORT
      LAYER M4 ;
        RECT  0 71.712 0.192 71.736 ;
    END
  END di[415]
  PIN di[416]
    DIRECTION INPUT ;
    USE SIGNAL ;
    PORT
      LAYER M4 ;
        RECT  0 71.904 0.192 71.928 ;
    END
  END di[416]
  PIN di[417]
    DIRECTION INPUT ;
    USE SIGNAL ;
    PORT
      LAYER M4 ;
        RECT  0 72.048 0.192 72.072 ;
    END
  END di[417]
  PIN di[418]
    DIRECTION INPUT ;
    USE SIGNAL ;
    PORT
      LAYER M4 ;
        RECT  0 72.24 0.192 72.264 ;
    END
  END di[418]
  PIN di[419]
    DIRECTION INPUT ;
    USE SIGNAL ;
    PORT
      LAYER M4 ;
        RECT  0 72.384 0.192 72.408 ;
    END
  END di[419]
  PIN di[41]
    DIRECTION INPUT ;
    USE SIGNAL ;
    PORT
      LAYER M4 ;
        RECT  0 11.04 0.192 11.064 ;
    END
  END di[41]
  PIN di[420]
    DIRECTION INPUT ;
    USE SIGNAL ;
    PORT
      LAYER M4 ;
        RECT  0 72.528 0.192 72.552 ;
    END
  END di[420]
  PIN di[421]
    DIRECTION INPUT ;
    USE SIGNAL ;
    PORT
      LAYER M4 ;
        RECT  0 72.72 0.192 72.744 ;
    END
  END di[421]
  PIN di[422]
    DIRECTION INPUT ;
    USE SIGNAL ;
    PORT
      LAYER M4 ;
        RECT  0 72.864 0.192 72.888 ;
    END
  END di[422]
  PIN di[423]
    DIRECTION INPUT ;
    USE SIGNAL ;
    PORT
      LAYER M4 ;
        RECT  0 73.008 0.192 73.032 ;
    END
  END di[423]
  PIN di[424]
    DIRECTION INPUT ;
    USE SIGNAL ;
    PORT
      LAYER M4 ;
        RECT  0 73.2 0.192 73.224 ;
    END
  END di[424]
  PIN di[425]
    DIRECTION INPUT ;
    USE SIGNAL ;
    PORT
      LAYER M4 ;
        RECT  0 73.344 0.192 73.368 ;
    END
  END di[425]
  PIN di[426]
    DIRECTION INPUT ;
    USE SIGNAL ;
    PORT
      LAYER M4 ;
        RECT  0 73.536 0.192 73.56 ;
    END
  END di[426]
  PIN di[427]
    DIRECTION INPUT ;
    USE SIGNAL ;
    PORT
      LAYER M4 ;
        RECT  0 73.68 0.192 73.704 ;
    END
  END di[427]
  PIN di[428]
    DIRECTION INPUT ;
    USE SIGNAL ;
    PORT
      LAYER M4 ;
        RECT  0 73.824 0.192 73.848 ;
    END
  END di[428]
  PIN di[429]
    DIRECTION INPUT ;
    USE SIGNAL ;
    PORT
      LAYER M4 ;
        RECT  0 74.016 0.192 74.04 ;
    END
  END di[429]
  PIN di[42]
    DIRECTION INPUT ;
    USE SIGNAL ;
    PORT
      LAYER M4 ;
        RECT  0 11.232 0.192 11.256 ;
    END
  END di[42]
  PIN di[430]
    DIRECTION INPUT ;
    USE SIGNAL ;
    PORT
      LAYER M4 ;
        RECT  0 74.16 0.192 74.184 ;
    END
  END di[430]
  PIN di[431]
    DIRECTION INPUT ;
    USE SIGNAL ;
    PORT
      LAYER M4 ;
        RECT  0 74.304 0.192 74.328 ;
    END
  END di[431]
  PIN di[432]
    DIRECTION INPUT ;
    USE SIGNAL ;
    PORT
      LAYER M4 ;
        RECT  0 74.496 0.192 74.52 ;
    END
  END di[432]
  PIN di[433]
    DIRECTION INPUT ;
    USE SIGNAL ;
    PORT
      LAYER M4 ;
        RECT  0 74.64 0.192 74.664 ;
    END
  END di[433]
  PIN di[434]
    DIRECTION INPUT ;
    USE SIGNAL ;
    PORT
      LAYER M4 ;
        RECT  0 74.832 0.192 74.856 ;
    END
  END di[434]
  PIN di[435]
    DIRECTION INPUT ;
    USE SIGNAL ;
    PORT
      LAYER M4 ;
        RECT  0 74.976 0.192 75 ;
    END
  END di[435]
  PIN di[436]
    DIRECTION INPUT ;
    USE SIGNAL ;
    PORT
      LAYER M4 ;
        RECT  0 75.12 0.192 75.144 ;
    END
  END di[436]
  PIN di[437]
    DIRECTION INPUT ;
    USE SIGNAL ;
    PORT
      LAYER M4 ;
        RECT  0 75.312 0.192 75.336 ;
    END
  END di[437]
  PIN di[438]
    DIRECTION INPUT ;
    USE SIGNAL ;
    PORT
      LAYER M4 ;
        RECT  0 75.456 0.192 75.48 ;
    END
  END di[438]
  PIN di[439]
    DIRECTION INPUT ;
    USE SIGNAL ;
    PORT
      LAYER M4 ;
        RECT  0 75.648 0.192 75.672 ;
    END
  END di[439]
  PIN di[43]
    DIRECTION INPUT ;
    USE SIGNAL ;
    PORT
      LAYER M4 ;
        RECT  0 11.376 0.192 11.4 ;
    END
  END di[43]
  PIN di[440]
    DIRECTION INPUT ;
    USE SIGNAL ;
    PORT
      LAYER M4 ;
        RECT  0 75.792 0.192 75.816 ;
    END
  END di[440]
  PIN di[441]
    DIRECTION INPUT ;
    USE SIGNAL ;
    PORT
      LAYER M4 ;
        RECT  0 75.936 0.192 75.96 ;
    END
  END di[441]
  PIN di[442]
    DIRECTION INPUT ;
    USE SIGNAL ;
    PORT
      LAYER M4 ;
        RECT  0 76.128 0.192 76.152 ;
    END
  END di[442]
  PIN di[443]
    DIRECTION INPUT ;
    USE SIGNAL ;
    PORT
      LAYER M4 ;
        RECT  0 76.272 0.192 76.296 ;
    END
  END di[443]
  PIN di[444]
    DIRECTION INPUT ;
    USE SIGNAL ;
    PORT
      LAYER M4 ;
        RECT  0 76.416 0.192 76.44 ;
    END
  END di[444]
  PIN di[445]
    DIRECTION INPUT ;
    USE SIGNAL ;
    PORT
      LAYER M4 ;
        RECT  0 76.608 0.192 76.632 ;
    END
  END di[445]
  PIN di[446]
    DIRECTION INPUT ;
    USE SIGNAL ;
    PORT
      LAYER M4 ;
        RECT  0 76.752 0.192 76.776 ;
    END
  END di[446]
  PIN di[447]
    DIRECTION INPUT ;
    USE SIGNAL ;
    PORT
      LAYER M4 ;
        RECT  0 76.944 0.192 76.968 ;
    END
  END di[447]
  PIN di[448]
    DIRECTION INPUT ;
    USE SIGNAL ;
    PORT
      LAYER M4 ;
        RECT  0 77.088 0.192 77.112 ;
    END
  END di[448]
  PIN di[449]
    DIRECTION INPUT ;
    USE SIGNAL ;
    PORT
      LAYER M4 ;
        RECT  0 77.232 0.192 77.256 ;
    END
  END di[449]
  PIN di[44]
    DIRECTION INPUT ;
    USE SIGNAL ;
    PORT
      LAYER M4 ;
        RECT  0 11.568 0.192 11.592 ;
    END
  END di[44]
  PIN di[450]
    DIRECTION INPUT ;
    USE SIGNAL ;
    PORT
      LAYER M4 ;
        RECT  0 77.424 0.192 77.448 ;
    END
  END di[450]
  PIN di[451]
    DIRECTION INPUT ;
    USE SIGNAL ;
    PORT
      LAYER M4 ;
        RECT  0 77.568 0.192 77.592 ;
    END
  END di[451]
  PIN di[452]
    DIRECTION INPUT ;
    USE SIGNAL ;
    PORT
      LAYER M4 ;
        RECT  0 77.712 0.192 77.736 ;
    END
  END di[452]
  PIN di[453]
    DIRECTION INPUT ;
    USE SIGNAL ;
    PORT
      LAYER M4 ;
        RECT  0 77.904 0.192 77.928 ;
    END
  END di[453]
  PIN di[454]
    DIRECTION INPUT ;
    USE SIGNAL ;
    PORT
      LAYER M4 ;
        RECT  0 78.048 0.192 78.072 ;
    END
  END di[454]
  PIN di[455]
    DIRECTION INPUT ;
    USE SIGNAL ;
    PORT
      LAYER M4 ;
        RECT  0 78.24 0.192 78.264 ;
    END
  END di[455]
  PIN di[456]
    DIRECTION INPUT ;
    USE SIGNAL ;
    PORT
      LAYER M4 ;
        RECT  0 78.384 0.192 78.408 ;
    END
  END di[456]
  PIN di[457]
    DIRECTION INPUT ;
    USE SIGNAL ;
    PORT
      LAYER M4 ;
        RECT  0 78.528 0.192 78.552 ;
    END
  END di[457]
  PIN di[458]
    DIRECTION INPUT ;
    USE SIGNAL ;
    PORT
      LAYER M4 ;
        RECT  0 78.72 0.192 78.744 ;
    END
  END di[458]
  PIN di[459]
    DIRECTION INPUT ;
    USE SIGNAL ;
    PORT
      LAYER M4 ;
        RECT  0 78.864 0.192 78.888 ;
    END
  END di[459]
  PIN di[45]
    DIRECTION INPUT ;
    USE SIGNAL ;
    PORT
      LAYER M4 ;
        RECT  0 11.712 0.192 11.736 ;
    END
  END di[45]
  PIN di[460]
    DIRECTION INPUT ;
    USE SIGNAL ;
    PORT
      LAYER M4 ;
        RECT  0 79.008 0.192 79.032 ;
    END
  END di[460]
  PIN di[461]
    DIRECTION INPUT ;
    USE SIGNAL ;
    PORT
      LAYER M4 ;
        RECT  0 79.2 0.192 79.224 ;
    END
  END di[461]
  PIN di[462]
    DIRECTION INPUT ;
    USE SIGNAL ;
    PORT
      LAYER M4 ;
        RECT  0 79.344 0.192 79.368 ;
    END
  END di[462]
  PIN di[463]
    DIRECTION INPUT ;
    USE SIGNAL ;
    PORT
      LAYER M4 ;
        RECT  0 79.536 0.192 79.56 ;
    END
  END di[463]
  PIN di[464]
    DIRECTION INPUT ;
    USE SIGNAL ;
    PORT
      LAYER M4 ;
        RECT  0 79.68 0.192 79.704 ;
    END
  END di[464]
  PIN di[465]
    DIRECTION INPUT ;
    USE SIGNAL ;
    PORT
      LAYER M4 ;
        RECT  0 79.824 0.192 79.848 ;
    END
  END di[465]
  PIN di[466]
    DIRECTION INPUT ;
    USE SIGNAL ;
    PORT
      LAYER M4 ;
        RECT  0 80.016 0.192 80.04 ;
    END
  END di[466]
  PIN di[467]
    DIRECTION INPUT ;
    USE SIGNAL ;
    PORT
      LAYER M4 ;
        RECT  0 80.16 0.192 80.184 ;
    END
  END di[467]
  PIN di[468]
    DIRECTION INPUT ;
    USE SIGNAL ;
    PORT
      LAYER M4 ;
        RECT  0 80.352 0.192 80.376 ;
    END
  END di[468]
  PIN di[469]
    DIRECTION INPUT ;
    USE SIGNAL ;
    PORT
      LAYER M4 ;
        RECT  0 80.496 0.192 80.52 ;
    END
  END di[469]
  PIN di[46]
    DIRECTION INPUT ;
    USE SIGNAL ;
    PORT
      LAYER M4 ;
        RECT  0 11.856 0.192 11.88 ;
    END
  END di[46]
  PIN di[470]
    DIRECTION INPUT ;
    USE SIGNAL ;
    PORT
      LAYER M4 ;
        RECT  0 80.64 0.192 80.664 ;
    END
  END di[470]
  PIN di[471]
    DIRECTION INPUT ;
    USE SIGNAL ;
    PORT
      LAYER M4 ;
        RECT  0 80.832 0.192 80.856 ;
    END
  END di[471]
  PIN di[472]
    DIRECTION INPUT ;
    USE SIGNAL ;
    PORT
      LAYER M4 ;
        RECT  0 80.976 0.192 81 ;
    END
  END di[472]
  PIN di[473]
    DIRECTION INPUT ;
    USE SIGNAL ;
    PORT
      LAYER M4 ;
        RECT  0 81.12 0.192 81.144 ;
    END
  END di[473]
  PIN di[474]
    DIRECTION INPUT ;
    USE SIGNAL ;
    PORT
      LAYER M4 ;
        RECT  0 81.312 0.192 81.336 ;
    END
  END di[474]
  PIN di[475]
    DIRECTION INPUT ;
    USE SIGNAL ;
    PORT
      LAYER M4 ;
        RECT  0 81.456 0.192 81.48 ;
    END
  END di[475]
  PIN di[476]
    DIRECTION INPUT ;
    USE SIGNAL ;
    PORT
      LAYER M4 ;
        RECT  0 81.648 0.192 81.672 ;
    END
  END di[476]
  PIN di[477]
    DIRECTION INPUT ;
    USE SIGNAL ;
    PORT
      LAYER M4 ;
        RECT  0 81.792 0.192 81.816 ;
    END
  END di[477]
  PIN di[478]
    DIRECTION INPUT ;
    USE SIGNAL ;
    PORT
      LAYER M4 ;
        RECT  0 81.936 0.192 81.96 ;
    END
  END di[478]
  PIN di[479]
    DIRECTION INPUT ;
    USE SIGNAL ;
    PORT
      LAYER M4 ;
        RECT  0 82.128 0.192 82.152 ;
    END
  END di[479]
  PIN di[47]
    DIRECTION INPUT ;
    USE SIGNAL ;
    PORT
      LAYER M4 ;
        RECT  0 12.048 0.192 12.072 ;
    END
  END di[47]
  PIN di[480]
    DIRECTION INPUT ;
    USE SIGNAL ;
    PORT
      LAYER M4 ;
        RECT  0 82.272 0.192 82.296 ;
    END
  END di[480]
  PIN di[481]
    DIRECTION INPUT ;
    USE SIGNAL ;
    PORT
      LAYER M4 ;
        RECT  0 82.416 0.192 82.44 ;
    END
  END di[481]
  PIN di[482]
    DIRECTION INPUT ;
    USE SIGNAL ;
    PORT
      LAYER M4 ;
        RECT  0 82.608 0.192 82.632 ;
    END
  END di[482]
  PIN di[483]
    DIRECTION INPUT ;
    USE SIGNAL ;
    PORT
      LAYER M4 ;
        RECT  0 82.752 0.192 82.776 ;
    END
  END di[483]
  PIN di[484]
    DIRECTION INPUT ;
    USE SIGNAL ;
    PORT
      LAYER M4 ;
        RECT  0 82.944 0.192 82.968 ;
    END
  END di[484]
  PIN di[485]
    DIRECTION INPUT ;
    USE SIGNAL ;
    PORT
      LAYER M4 ;
        RECT  0 83.088 0.192 83.112 ;
    END
  END di[485]
  PIN di[486]
    DIRECTION INPUT ;
    USE SIGNAL ;
    PORT
      LAYER M4 ;
        RECT  0 83.232 0.192 83.256 ;
    END
  END di[486]
  PIN di[487]
    DIRECTION INPUT ;
    USE SIGNAL ;
    PORT
      LAYER M4 ;
        RECT  0 83.424 0.192 83.448 ;
    END
  END di[487]
  PIN di[488]
    DIRECTION INPUT ;
    USE SIGNAL ;
    PORT
      LAYER M4 ;
        RECT  0 83.568 0.192 83.592 ;
    END
  END di[488]
  PIN di[489]
    DIRECTION INPUT ;
    USE SIGNAL ;
    PORT
      LAYER M4 ;
        RECT  0 83.712 0.192 83.736 ;
    END
  END di[489]
  PIN di[48]
    DIRECTION INPUT ;
    USE SIGNAL ;
    PORT
      LAYER M4 ;
        RECT  0 12.192 0.192 12.216 ;
    END
  END di[48]
  PIN di[490]
    DIRECTION INPUT ;
    USE SIGNAL ;
    PORT
      LAYER M4 ;
        RECT  0 83.904 0.192 83.928 ;
    END
  END di[490]
  PIN di[491]
    DIRECTION INPUT ;
    USE SIGNAL ;
    PORT
      LAYER M4 ;
        RECT  0 84.048 0.192 84.072 ;
    END
  END di[491]
  PIN di[492]
    DIRECTION INPUT ;
    USE SIGNAL ;
    PORT
      LAYER M4 ;
        RECT  0 84.24 0.192 84.264 ;
    END
  END di[492]
  PIN di[493]
    DIRECTION INPUT ;
    USE SIGNAL ;
    PORT
      LAYER M4 ;
        RECT  0 84.384 0.192 84.408 ;
    END
  END di[493]
  PIN di[494]
    DIRECTION INPUT ;
    USE SIGNAL ;
    PORT
      LAYER M4 ;
        RECT  0 84.528 0.192 84.552 ;
    END
  END di[494]
  PIN di[495]
    DIRECTION INPUT ;
    USE SIGNAL ;
    PORT
      LAYER M4 ;
        RECT  0 84.72 0.192 84.744 ;
    END
  END di[495]
  PIN di[496]
    DIRECTION INPUT ;
    USE SIGNAL ;
    PORT
      LAYER M4 ;
        RECT  0 84.864 0.192 84.888 ;
    END
  END di[496]
  PIN di[497]
    DIRECTION INPUT ;
    USE SIGNAL ;
    PORT
      LAYER M4 ;
        RECT  0 85.056 0.192 85.08 ;
    END
  END di[497]
  PIN di[498]
    DIRECTION INPUT ;
    USE SIGNAL ;
    PORT
      LAYER M4 ;
        RECT  0 85.2 0.192 85.224 ;
    END
  END di[498]
  PIN di[499]
    DIRECTION INPUT ;
    USE SIGNAL ;
    PORT
      LAYER M4 ;
        RECT  0 85.344 0.192 85.368 ;
    END
  END di[499]
  PIN di[49]
    DIRECTION INPUT ;
    USE SIGNAL ;
    PORT
      LAYER M4 ;
        RECT  0 12.384 0.192 12.408 ;
    END
  END di[49]
  PIN di[4]
    DIRECTION INPUT ;
    USE SIGNAL ;
    PORT
      LAYER M4 ;
        RECT  0 5.04 0.192 5.064 ;
    END
  END di[4]
  PIN di[500]
    DIRECTION INPUT ;
    USE SIGNAL ;
    PORT
      LAYER M4 ;
        RECT  0 85.536 0.192 85.56 ;
    END
  END di[500]
  PIN di[501]
    DIRECTION INPUT ;
    USE SIGNAL ;
    PORT
      LAYER M4 ;
        RECT  0 85.68 0.192 85.704 ;
    END
  END di[501]
  PIN di[502]
    DIRECTION INPUT ;
    USE SIGNAL ;
    PORT
      LAYER M4 ;
        RECT  0 85.824 0.192 85.848 ;
    END
  END di[502]
  PIN di[503]
    DIRECTION INPUT ;
    USE SIGNAL ;
    PORT
      LAYER M4 ;
        RECT  0 86.016 0.192 86.04 ;
    END
  END di[503]
  PIN di[504]
    DIRECTION INPUT ;
    USE SIGNAL ;
    PORT
      LAYER M4 ;
        RECT  0 86.16 0.192 86.184 ;
    END
  END di[504]
  PIN di[505]
    DIRECTION INPUT ;
    USE SIGNAL ;
    PORT
      LAYER M4 ;
        RECT  0 86.352 0.192 86.376 ;
    END
  END di[505]
  PIN di[506]
    DIRECTION INPUT ;
    USE SIGNAL ;
    PORT
      LAYER M4 ;
        RECT  0 86.496 0.192 86.52 ;
    END
  END di[506]
  PIN di[507]
    DIRECTION INPUT ;
    USE SIGNAL ;
    PORT
      LAYER M4 ;
        RECT  0 86.64 0.192 86.664 ;
    END
  END di[507]
  PIN di[508]
    DIRECTION INPUT ;
    USE SIGNAL ;
    PORT
      LAYER M4 ;
        RECT  0 86.832 0.192 86.856 ;
    END
  END di[508]
  PIN di[509]
    DIRECTION INPUT ;
    USE SIGNAL ;
    PORT
      LAYER M4 ;
        RECT  0 86.976 0.192 87 ;
    END
  END di[509]
  PIN di[50]
    DIRECTION INPUT ;
    USE SIGNAL ;
    PORT
      LAYER M4 ;
        RECT  0 12.528 0.192 12.552 ;
    END
  END di[50]
  PIN di[510]
    DIRECTION INPUT ;
    USE SIGNAL ;
    PORT
      LAYER M4 ;
        RECT  0 87.12 0.192 87.144 ;
    END
  END di[510]
  PIN di[511]
    DIRECTION INPUT ;
    USE SIGNAL ;
    PORT
      LAYER M4 ;
        RECT  0 87.312 0.192 87.336 ;
    END
  END di[511]
  PIN di[512]
    DIRECTION INPUT ;
    USE SIGNAL ;
    PORT
      LAYER M4 ;
        RECT  0 87.456 0.192 87.48 ;
    END
  END di[512]
  PIN di[513]
    DIRECTION INPUT ;
    USE SIGNAL ;
    PORT
      LAYER M4 ;
        RECT  0 87.648 0.192 87.672 ;
    END
  END di[513]
  PIN di[514]
    DIRECTION INPUT ;
    USE SIGNAL ;
    PORT
      LAYER M4 ;
        RECT  0 87.792 0.192 87.816 ;
    END
  END di[514]
  PIN di[515]
    DIRECTION INPUT ;
    USE SIGNAL ;
    PORT
      LAYER M4 ;
        RECT  0 87.936 0.192 87.96 ;
    END
  END di[515]
  PIN di[516]
    DIRECTION INPUT ;
    USE SIGNAL ;
    PORT
      LAYER M4 ;
        RECT  0 88.128 0.192 88.152 ;
    END
  END di[516]
  PIN di[517]
    DIRECTION INPUT ;
    USE SIGNAL ;
    PORT
      LAYER M4 ;
        RECT  0 88.272 0.192 88.296 ;
    END
  END di[517]
  PIN di[518]
    DIRECTION INPUT ;
    USE SIGNAL ;
    PORT
      LAYER M4 ;
        RECT  0 88.416 0.192 88.44 ;
    END
  END di[518]
  PIN di[519]
    DIRECTION INPUT ;
    USE SIGNAL ;
    PORT
      LAYER M4 ;
        RECT  0 88.608 0.192 88.632 ;
    END
  END di[519]
  PIN di[51]
    DIRECTION INPUT ;
    USE SIGNAL ;
    PORT
      LAYER M4 ;
        RECT  0 12.672 0.192 12.696 ;
    END
  END di[51]
  PIN di[520]
    DIRECTION INPUT ;
    USE SIGNAL ;
    PORT
      LAYER M4 ;
        RECT  0 88.752 0.192 88.776 ;
    END
  END di[520]
  PIN di[521]
    DIRECTION INPUT ;
    USE SIGNAL ;
    PORT
      LAYER M4 ;
        RECT  0 88.944 0.192 88.968 ;
    END
  END di[521]
  PIN di[522]
    DIRECTION INPUT ;
    USE SIGNAL ;
    PORT
      LAYER M4 ;
        RECT  0 89.088 0.192 89.112 ;
    END
  END di[522]
  PIN di[523]
    DIRECTION INPUT ;
    USE SIGNAL ;
    PORT
      LAYER M4 ;
        RECT  0 89.232 0.192 89.256 ;
    END
  END di[523]
  PIN di[524]
    DIRECTION INPUT ;
    USE SIGNAL ;
    PORT
      LAYER M4 ;
        RECT  0 89.424 0.192 89.448 ;
    END
  END di[524]
  PIN di[525]
    DIRECTION INPUT ;
    USE SIGNAL ;
    PORT
      LAYER M4 ;
        RECT  0 89.568 0.192 89.592 ;
    END
  END di[525]
  PIN di[526]
    DIRECTION INPUT ;
    USE SIGNAL ;
    PORT
      LAYER M4 ;
        RECT  0 89.76 0.192 89.784 ;
    END
  END di[526]
  PIN di[527]
    DIRECTION INPUT ;
    USE SIGNAL ;
    PORT
      LAYER M4 ;
        RECT  0 89.904 0.192 89.928 ;
    END
  END di[527]
  PIN di[528]
    DIRECTION INPUT ;
    USE SIGNAL ;
    PORT
      LAYER M4 ;
        RECT  0 90.048 0.192 90.072 ;
    END
  END di[528]
  PIN di[529]
    DIRECTION INPUT ;
    USE SIGNAL ;
    PORT
      LAYER M4 ;
        RECT  0 90.24 0.192 90.264 ;
    END
  END di[529]
  PIN di[52]
    DIRECTION INPUT ;
    USE SIGNAL ;
    PORT
      LAYER M4 ;
        RECT  0 12.864 0.192 12.888 ;
    END
  END di[52]
  PIN di[530]
    DIRECTION INPUT ;
    USE SIGNAL ;
    PORT
      LAYER M4 ;
        RECT  0 90.384 0.192 90.408 ;
    END
  END di[530]
  PIN di[531]
    DIRECTION INPUT ;
    USE SIGNAL ;
    PORT
      LAYER M4 ;
        RECT  0 90.528 0.192 90.552 ;
    END
  END di[531]
  PIN di[532]
    DIRECTION INPUT ;
    USE SIGNAL ;
    PORT
      LAYER M4 ;
        RECT  0 90.72 0.192 90.744 ;
    END
  END di[532]
  PIN di[533]
    DIRECTION INPUT ;
    USE SIGNAL ;
    PORT
      LAYER M4 ;
        RECT  0 90.864 0.192 90.888 ;
    END
  END di[533]
  PIN di[534]
    DIRECTION INPUT ;
    USE SIGNAL ;
    PORT
      LAYER M4 ;
        RECT  0 91.056 0.192 91.08 ;
    END
  END di[534]
  PIN di[535]
    DIRECTION INPUT ;
    USE SIGNAL ;
    PORT
      LAYER M4 ;
        RECT  0 91.2 0.192 91.224 ;
    END
  END di[535]
  PIN di[536]
    DIRECTION INPUT ;
    USE SIGNAL ;
    PORT
      LAYER M4 ;
        RECT  0 91.344 0.192 91.368 ;
    END
  END di[536]
  PIN di[537]
    DIRECTION INPUT ;
    USE SIGNAL ;
    PORT
      LAYER M4 ;
        RECT  0 91.536 0.192 91.56 ;
    END
  END di[537]
  PIN di[538]
    DIRECTION INPUT ;
    USE SIGNAL ;
    PORT
      LAYER M4 ;
        RECT  0 91.68 0.192 91.704 ;
    END
  END di[538]
  PIN di[539]
    DIRECTION INPUT ;
    USE SIGNAL ;
    PORT
      LAYER M4 ;
        RECT  0 91.824 0.192 91.848 ;
    END
  END di[539]
  PIN di[53]
    DIRECTION INPUT ;
    USE SIGNAL ;
    PORT
      LAYER M4 ;
        RECT  0 13.008 0.192 13.032 ;
    END
  END di[53]
  PIN di[540]
    DIRECTION INPUT ;
    USE SIGNAL ;
    PORT
      LAYER M4 ;
        RECT  0 92.016 0.192 92.04 ;
    END
  END di[540]
  PIN di[541]
    DIRECTION INPUT ;
    USE SIGNAL ;
    PORT
      LAYER M4 ;
        RECT  0 92.16 0.192 92.184 ;
    END
  END di[541]
  PIN di[542]
    DIRECTION INPUT ;
    USE SIGNAL ;
    PORT
      LAYER M4 ;
        RECT  0 92.352 0.192 92.376 ;
    END
  END di[542]
  PIN di[543]
    DIRECTION INPUT ;
    USE SIGNAL ;
    PORT
      LAYER M4 ;
        RECT  0 92.496 0.192 92.52 ;
    END
  END di[543]
  PIN di[544]
    DIRECTION INPUT ;
    USE SIGNAL ;
    PORT
      LAYER M4 ;
        RECT  0 92.64 0.192 92.664 ;
    END
  END di[544]
  PIN di[545]
    DIRECTION INPUT ;
    USE SIGNAL ;
    PORT
      LAYER M4 ;
        RECT  0 92.832 0.192 92.856 ;
    END
  END di[545]
  PIN di[546]
    DIRECTION INPUT ;
    USE SIGNAL ;
    PORT
      LAYER M4 ;
        RECT  0 92.976 0.192 93 ;
    END
  END di[546]
  PIN di[547]
    DIRECTION INPUT ;
    USE SIGNAL ;
    PORT
      LAYER M4 ;
        RECT  0 93.12 0.192 93.144 ;
    END
  END di[547]
  PIN di[548]
    DIRECTION INPUT ;
    USE SIGNAL ;
    PORT
      LAYER M4 ;
        RECT  0 93.312 0.192 93.336 ;
    END
  END di[548]
  PIN di[549]
    DIRECTION INPUT ;
    USE SIGNAL ;
    PORT
      LAYER M4 ;
        RECT  0 93.456 0.192 93.48 ;
    END
  END di[549]
  PIN di[54]
    DIRECTION INPUT ;
    USE SIGNAL ;
    PORT
      LAYER M4 ;
        RECT  0 13.152 0.192 13.176 ;
    END
  END di[54]
  PIN di[550]
    DIRECTION INPUT ;
    USE SIGNAL ;
    PORT
      LAYER M4 ;
        RECT  0 93.648 0.192 93.672 ;
    END
  END di[550]
  PIN di[551]
    DIRECTION INPUT ;
    USE SIGNAL ;
    PORT
      LAYER M4 ;
        RECT  0 93.792 0.192 93.816 ;
    END
  END di[551]
  PIN di[552]
    DIRECTION INPUT ;
    USE SIGNAL ;
    PORT
      LAYER M4 ;
        RECT  0 93.936 0.192 93.96 ;
    END
  END di[552]
  PIN di[553]
    DIRECTION INPUT ;
    USE SIGNAL ;
    PORT
      LAYER M4 ;
        RECT  0 94.128 0.192 94.152 ;
    END
  END di[553]
  PIN di[554]
    DIRECTION INPUT ;
    USE SIGNAL ;
    PORT
      LAYER M4 ;
        RECT  0 94.272 0.192 94.296 ;
    END
  END di[554]
  PIN di[555]
    DIRECTION INPUT ;
    USE SIGNAL ;
    PORT
      LAYER M4 ;
        RECT  0 94.464 0.192 94.488 ;
    END
  END di[555]
  PIN di[556]
    DIRECTION INPUT ;
    USE SIGNAL ;
    PORT
      LAYER M4 ;
        RECT  0 94.608 0.192 94.632 ;
    END
  END di[556]
  PIN di[557]
    DIRECTION INPUT ;
    USE SIGNAL ;
    PORT
      LAYER M4 ;
        RECT  0 94.752 0.192 94.776 ;
    END
  END di[557]
  PIN di[558]
    DIRECTION INPUT ;
    USE SIGNAL ;
    PORT
      LAYER M4 ;
        RECT  0 94.944 0.192 94.968 ;
    END
  END di[558]
  PIN di[559]
    DIRECTION INPUT ;
    USE SIGNAL ;
    PORT
      LAYER M4 ;
        RECT  0 95.088 0.192 95.112 ;
    END
  END di[559]
  PIN di[55]
    DIRECTION INPUT ;
    USE SIGNAL ;
    PORT
      LAYER M4 ;
        RECT  0 13.344 0.192 13.368 ;
    END
  END di[55]
  PIN di[560]
    DIRECTION INPUT ;
    USE SIGNAL ;
    PORT
      LAYER M4 ;
        RECT  0 95.232 0.192 95.256 ;
    END
  END di[560]
  PIN di[561]
    DIRECTION INPUT ;
    USE SIGNAL ;
    PORT
      LAYER M4 ;
        RECT  0 95.424 0.192 95.448 ;
    END
  END di[561]
  PIN di[562]
    DIRECTION INPUT ;
    USE SIGNAL ;
    PORT
      LAYER M4 ;
        RECT  0 95.568 0.192 95.592 ;
    END
  END di[562]
  PIN di[563]
    DIRECTION INPUT ;
    USE SIGNAL ;
    PORT
      LAYER M4 ;
        RECT  0 95.76 0.192 95.784 ;
    END
  END di[563]
  PIN di[564]
    DIRECTION INPUT ;
    USE SIGNAL ;
    PORT
      LAYER M4 ;
        RECT  0 95.904 0.192 95.928 ;
    END
  END di[564]
  PIN di[565]
    DIRECTION INPUT ;
    USE SIGNAL ;
    PORT
      LAYER M4 ;
        RECT  0 96.048 0.192 96.072 ;
    END
  END di[565]
  PIN di[566]
    DIRECTION INPUT ;
    USE SIGNAL ;
    PORT
      LAYER M4 ;
        RECT  0 96.24 0.192 96.264 ;
    END
  END di[566]
  PIN di[567]
    DIRECTION INPUT ;
    USE SIGNAL ;
    PORT
      LAYER M4 ;
        RECT  0 96.384 0.192 96.408 ;
    END
  END di[567]
  PIN di[568]
    DIRECTION INPUT ;
    USE SIGNAL ;
    PORT
      LAYER M4 ;
        RECT  0 96.528 0.192 96.552 ;
    END
  END di[568]
  PIN di[569]
    DIRECTION INPUT ;
    USE SIGNAL ;
    PORT
      LAYER M4 ;
        RECT  0 96.72 0.192 96.744 ;
    END
  END di[569]
  PIN di[56]
    DIRECTION INPUT ;
    USE SIGNAL ;
    PORT
      LAYER M4 ;
        RECT  0 13.488 0.192 13.512 ;
    END
  END di[56]
  PIN di[570]
    DIRECTION INPUT ;
    USE SIGNAL ;
    PORT
      LAYER M4 ;
        RECT  0 96.864 0.192 96.888 ;
    END
  END di[570]
  PIN di[571]
    DIRECTION INPUT ;
    USE SIGNAL ;
    PORT
      LAYER M4 ;
        RECT  0 97.056 0.192 97.08 ;
    END
  END di[571]
  PIN di[572]
    DIRECTION INPUT ;
    USE SIGNAL ;
    PORT
      LAYER M4 ;
        RECT  0 97.2 0.192 97.224 ;
    END
  END di[572]
  PIN di[573]
    DIRECTION INPUT ;
    USE SIGNAL ;
    PORT
      LAYER M4 ;
        RECT  0 97.344 0.192 97.368 ;
    END
  END di[573]
  PIN di[574]
    DIRECTION INPUT ;
    USE SIGNAL ;
    PORT
      LAYER M4 ;
        RECT  0 97.536 0.192 97.56 ;
    END
  END di[574]
  PIN di[575]
    DIRECTION INPUT ;
    USE SIGNAL ;
    PORT
      LAYER M4 ;
        RECT  0 97.68 0.192 97.704 ;
    END
  END di[575]
  PIN di[576]
    DIRECTION INPUT ;
    USE SIGNAL ;
    PORT
      LAYER M4 ;
        RECT  0 97.872 0.192 97.896 ;
    END
  END di[576]
  PIN di[577]
    DIRECTION INPUT ;
    USE SIGNAL ;
    PORT
      LAYER M4 ;
        RECT  0 98.016 0.192 98.04 ;
    END
  END di[577]
  PIN di[578]
    DIRECTION INPUT ;
    USE SIGNAL ;
    PORT
      LAYER M4 ;
        RECT  0 98.16 0.192 98.184 ;
    END
  END di[578]
  PIN di[579]
    DIRECTION INPUT ;
    USE SIGNAL ;
    PORT
      LAYER M4 ;
        RECT  0 98.352 0.192 98.376 ;
    END
  END di[579]
  PIN di[57]
    DIRECTION INPUT ;
    USE SIGNAL ;
    PORT
      LAYER M4 ;
        RECT  0 13.68 0.192 13.704 ;
    END
  END di[57]
  PIN di[580]
    DIRECTION INPUT ;
    USE SIGNAL ;
    PORT
      LAYER M4 ;
        RECT  0 98.496 0.192 98.52 ;
    END
  END di[580]
  PIN di[581]
    DIRECTION INPUT ;
    USE SIGNAL ;
    PORT
      LAYER M4 ;
        RECT  0 98.64 0.192 98.664 ;
    END
  END di[581]
  PIN di[582]
    DIRECTION INPUT ;
    USE SIGNAL ;
    PORT
      LAYER M4 ;
        RECT  0 98.832 0.192 98.856 ;
    END
  END di[582]
  PIN di[583]
    DIRECTION INPUT ;
    USE SIGNAL ;
    PORT
      LAYER M4 ;
        RECT  0 98.976 0.192 99 ;
    END
  END di[583]
  PIN di[584]
    DIRECTION INPUT ;
    USE SIGNAL ;
    PORT
      LAYER M4 ;
        RECT  0 99.168 0.192 99.192 ;
    END
  END di[584]
  PIN di[585]
    DIRECTION INPUT ;
    USE SIGNAL ;
    PORT
      LAYER M4 ;
        RECT  0 99.312 0.192 99.336 ;
    END
  END di[585]
  PIN di[586]
    DIRECTION INPUT ;
    USE SIGNAL ;
    PORT
      LAYER M4 ;
        RECT  0 99.456 0.192 99.48 ;
    END
  END di[586]
  PIN di[587]
    DIRECTION INPUT ;
    USE SIGNAL ;
    PORT
      LAYER M4 ;
        RECT  0 99.648 0.192 99.672 ;
    END
  END di[587]
  PIN di[588]
    DIRECTION INPUT ;
    USE SIGNAL ;
    PORT
      LAYER M4 ;
        RECT  0 99.792 0.192 99.816 ;
    END
  END di[588]
  PIN di[589]
    DIRECTION INPUT ;
    USE SIGNAL ;
    PORT
      LAYER M4 ;
        RECT  0 99.936 0.192 99.96 ;
    END
  END di[589]
  PIN di[58]
    DIRECTION INPUT ;
    USE SIGNAL ;
    PORT
      LAYER M4 ;
        RECT  0 13.824 0.192 13.848 ;
    END
  END di[58]
  PIN di[590]
    DIRECTION INPUT ;
    USE SIGNAL ;
    PORT
      LAYER M4 ;
        RECT  0 100.128 0.192 100.152 ;
    END
  END di[590]
  PIN di[591]
    DIRECTION INPUT ;
    USE SIGNAL ;
    PORT
      LAYER M4 ;
        RECT  0 100.272 0.192 100.296 ;
    END
  END di[591]
  PIN di[592]
    DIRECTION INPUT ;
    USE SIGNAL ;
    PORT
      LAYER M4 ;
        RECT  0 100.464 0.192 100.488 ;
    END
  END di[592]
  PIN di[593]
    DIRECTION INPUT ;
    USE SIGNAL ;
    PORT
      LAYER M4 ;
        RECT  0 100.608 0.192 100.632 ;
    END
  END di[593]
  PIN di[594]
    DIRECTION INPUT ;
    USE SIGNAL ;
    PORT
      LAYER M4 ;
        RECT  0 100.752 0.192 100.776 ;
    END
  END di[594]
  PIN di[595]
    DIRECTION INPUT ;
    USE SIGNAL ;
    PORT
      LAYER M4 ;
        RECT  0 100.944 0.192 100.968 ;
    END
  END di[595]
  PIN di[596]
    DIRECTION INPUT ;
    USE SIGNAL ;
    PORT
      LAYER M4 ;
        RECT  0 101.088 0.192 101.112 ;
    END
  END di[596]
  PIN di[597]
    DIRECTION INPUT ;
    USE SIGNAL ;
    PORT
      LAYER M4 ;
        RECT  0 101.232 0.192 101.256 ;
    END
  END di[597]
  PIN di[598]
    DIRECTION INPUT ;
    USE SIGNAL ;
    PORT
      LAYER M4 ;
        RECT  0 101.424 0.192 101.448 ;
    END
  END di[598]
  PIN di[599]
    DIRECTION INPUT ;
    USE SIGNAL ;
    PORT
      LAYER M4 ;
        RECT  0 101.568 0.192 101.592 ;
    END
  END di[599]
  PIN di[59]
    DIRECTION INPUT ;
    USE SIGNAL ;
    PORT
      LAYER M4 ;
        RECT  0 13.968 0.192 13.992 ;
    END
  END di[59]
  PIN di[5]
    DIRECTION INPUT ;
    USE SIGNAL ;
    PORT
      LAYER M4 ;
        RECT  0 5.232 0.192 5.256 ;
    END
  END di[5]
  PIN di[600]
    DIRECTION INPUT ;
    USE SIGNAL ;
    PORT
      LAYER M4 ;
        RECT  0 101.76 0.192 101.784 ;
    END
  END di[600]
  PIN di[601]
    DIRECTION INPUT ;
    USE SIGNAL ;
    PORT
      LAYER M4 ;
        RECT  0 101.904 0.192 101.928 ;
    END
  END di[601]
  PIN di[602]
    DIRECTION INPUT ;
    USE SIGNAL ;
    PORT
      LAYER M4 ;
        RECT  0 102.048 0.192 102.072 ;
    END
  END di[602]
  PIN di[603]
    DIRECTION INPUT ;
    USE SIGNAL ;
    PORT
      LAYER M4 ;
        RECT  0 102.24 0.192 102.264 ;
    END
  END di[603]
  PIN di[604]
    DIRECTION INPUT ;
    USE SIGNAL ;
    PORT
      LAYER M4 ;
        RECT  0 102.384 0.192 102.408 ;
    END
  END di[604]
  PIN di[605]
    DIRECTION INPUT ;
    USE SIGNAL ;
    PORT
      LAYER M4 ;
        RECT  0 102.576 0.192 102.6 ;
    END
  END di[605]
  PIN di[606]
    DIRECTION INPUT ;
    USE SIGNAL ;
    PORT
      LAYER M4 ;
        RECT  0 102.72 0.192 102.744 ;
    END
  END di[606]
  PIN di[607]
    DIRECTION INPUT ;
    USE SIGNAL ;
    PORT
      LAYER M4 ;
        RECT  0 102.864 0.192 102.888 ;
    END
  END di[607]
  PIN di[608]
    DIRECTION INPUT ;
    USE SIGNAL ;
    PORT
      LAYER M4 ;
        RECT  0 103.056 0.192 103.08 ;
    END
  END di[608]
  PIN di[609]
    DIRECTION INPUT ;
    USE SIGNAL ;
    PORT
      LAYER M4 ;
        RECT  0 103.2 0.192 103.224 ;
    END
  END di[609]
  PIN di[60]
    DIRECTION INPUT ;
    USE SIGNAL ;
    PORT
      LAYER M4 ;
        RECT  0 14.16 0.192 14.184 ;
    END
  END di[60]
  PIN di[610]
    DIRECTION INPUT ;
    USE SIGNAL ;
    PORT
      LAYER M4 ;
        RECT  0 103.344 0.192 103.368 ;
    END
  END di[610]
  PIN di[611]
    DIRECTION INPUT ;
    USE SIGNAL ;
    PORT
      LAYER M4 ;
        RECT  0 103.536 0.192 103.56 ;
    END
  END di[611]
  PIN di[612]
    DIRECTION INPUT ;
    USE SIGNAL ;
    PORT
      LAYER M4 ;
        RECT  0 103.68 0.192 103.704 ;
    END
  END di[612]
  PIN di[613]
    DIRECTION INPUT ;
    USE SIGNAL ;
    PORT
      LAYER M4 ;
        RECT  0 103.872 0.192 103.896 ;
    END
  END di[613]
  PIN di[614]
    DIRECTION INPUT ;
    USE SIGNAL ;
    PORT
      LAYER M4 ;
        RECT  0 104.016 0.192 104.04 ;
    END
  END di[614]
  PIN di[615]
    DIRECTION INPUT ;
    USE SIGNAL ;
    PORT
      LAYER M4 ;
        RECT  0 104.16 0.192 104.184 ;
    END
  END di[615]
  PIN di[616]
    DIRECTION INPUT ;
    USE SIGNAL ;
    PORT
      LAYER M4 ;
        RECT  0 104.352 0.192 104.376 ;
    END
  END di[616]
  PIN di[617]
    DIRECTION INPUT ;
    USE SIGNAL ;
    PORT
      LAYER M4 ;
        RECT  0 104.496 0.192 104.52 ;
    END
  END di[617]
  PIN di[618]
    DIRECTION INPUT ;
    USE SIGNAL ;
    PORT
      LAYER M4 ;
        RECT  0 104.64 0.192 104.664 ;
    END
  END di[618]
  PIN di[619]
    DIRECTION INPUT ;
    USE SIGNAL ;
    PORT
      LAYER M4 ;
        RECT  0 104.832 0.192 104.856 ;
    END
  END di[619]
  PIN di[61]
    DIRECTION INPUT ;
    USE SIGNAL ;
    PORT
      LAYER M4 ;
        RECT  0 14.304 0.192 14.328 ;
    END
  END di[61]
  PIN di[620]
    DIRECTION INPUT ;
    USE SIGNAL ;
    PORT
      LAYER M4 ;
        RECT  0 104.976 0.192 105 ;
    END
  END di[620]
  PIN di[621]
    DIRECTION INPUT ;
    USE SIGNAL ;
    PORT
      LAYER M4 ;
        RECT  0 105.168 0.192 105.192 ;
    END
  END di[621]
  PIN di[622]
    DIRECTION INPUT ;
    USE SIGNAL ;
    PORT
      LAYER M4 ;
        RECT  0 105.312 0.192 105.336 ;
    END
  END di[622]
  PIN di[623]
    DIRECTION INPUT ;
    USE SIGNAL ;
    PORT
      LAYER M4 ;
        RECT  0 105.456 0.192 105.48 ;
    END
  END di[623]
  PIN di[624]
    DIRECTION INPUT ;
    USE SIGNAL ;
    PORT
      LAYER M4 ;
        RECT  0 105.648 0.192 105.672 ;
    END
  END di[624]
  PIN di[625]
    DIRECTION INPUT ;
    USE SIGNAL ;
    PORT
      LAYER M4 ;
        RECT  0 105.792 0.192 105.816 ;
    END
  END di[625]
  PIN di[626]
    DIRECTION INPUT ;
    USE SIGNAL ;
    PORT
      LAYER M4 ;
        RECT  0 105.936 0.192 105.96 ;
    END
  END di[626]
  PIN di[627]
    DIRECTION INPUT ;
    USE SIGNAL ;
    PORT
      LAYER M4 ;
        RECT  0 106.128 0.192 106.152 ;
    END
  END di[627]
  PIN di[628]
    DIRECTION INPUT ;
    USE SIGNAL ;
    PORT
      LAYER M4 ;
        RECT  0 106.272 0.192 106.296 ;
    END
  END di[628]
  PIN di[629]
    DIRECTION INPUT ;
    USE SIGNAL ;
    PORT
      LAYER M4 ;
        RECT  0 106.464 0.192 106.488 ;
    END
  END di[629]
  PIN di[62]
    DIRECTION INPUT ;
    USE SIGNAL ;
    PORT
      LAYER M4 ;
        RECT  0 14.448 0.192 14.472 ;
    END
  END di[62]
  PIN di[630]
    DIRECTION INPUT ;
    USE SIGNAL ;
    PORT
      LAYER M4 ;
        RECT  0 106.608 0.192 106.632 ;
    END
  END di[630]
  PIN di[631]
    DIRECTION INPUT ;
    USE SIGNAL ;
    PORT
      LAYER M4 ;
        RECT  0 106.752 0.192 106.776 ;
    END
  END di[631]
  PIN di[632]
    DIRECTION INPUT ;
    USE SIGNAL ;
    PORT
      LAYER M4 ;
        RECT  0 106.944 0.192 106.968 ;
    END
  END di[632]
  PIN di[633]
    DIRECTION INPUT ;
    USE SIGNAL ;
    PORT
      LAYER M4 ;
        RECT  0 107.088 0.192 107.112 ;
    END
  END di[633]
  PIN di[634]
    DIRECTION INPUT ;
    USE SIGNAL ;
    PORT
      LAYER M4 ;
        RECT  0 107.28 0.192 107.304 ;
    END
  END di[634]
  PIN di[635]
    DIRECTION INPUT ;
    USE SIGNAL ;
    PORT
      LAYER M4 ;
        RECT  0 107.424 0.192 107.448 ;
    END
  END di[635]
  PIN di[636]
    DIRECTION INPUT ;
    USE SIGNAL ;
    PORT
      LAYER M4 ;
        RECT  0 107.568 0.192 107.592 ;
    END
  END di[636]
  PIN di[637]
    DIRECTION INPUT ;
    USE SIGNAL ;
    PORT
      LAYER M4 ;
        RECT  0 107.76 0.192 107.784 ;
    END
  END di[637]
  PIN di[638]
    DIRECTION INPUT ;
    USE SIGNAL ;
    PORT
      LAYER M4 ;
        RECT  0 107.904 0.192 107.928 ;
    END
  END di[638]
  PIN di[639]
    DIRECTION INPUT ;
    USE SIGNAL ;
    PORT
      LAYER M4 ;
        RECT  0 108.048 0.192 108.072 ;
    END
  END di[639]
  PIN di[63]
    DIRECTION INPUT ;
    USE SIGNAL ;
    PORT
      LAYER M4 ;
        RECT  0 14.64 0.192 14.664 ;
    END
  END di[63]
  PIN di[640]
    DIRECTION INPUT ;
    USE SIGNAL ;
    PORT
      LAYER M4 ;
        RECT  0 108.24 0.192 108.264 ;
    END
  END di[640]
  PIN di[641]
    DIRECTION INPUT ;
    USE SIGNAL ;
    PORT
      LAYER M4 ;
        RECT  0 108.384 0.192 108.408 ;
    END
  END di[641]
  PIN di[642]
    DIRECTION INPUT ;
    USE SIGNAL ;
    PORT
      LAYER M4 ;
        RECT  0 108.576 0.192 108.6 ;
    END
  END di[642]
  PIN di[643]
    DIRECTION INPUT ;
    USE SIGNAL ;
    PORT
      LAYER M4 ;
        RECT  0 108.72 0.192 108.744 ;
    END
  END di[643]
  PIN di[644]
    DIRECTION INPUT ;
    USE SIGNAL ;
    PORT
      LAYER M4 ;
        RECT  0 108.864 0.192 108.888 ;
    END
  END di[644]
  PIN di[645]
    DIRECTION INPUT ;
    USE SIGNAL ;
    PORT
      LAYER M4 ;
        RECT  0 109.056 0.192 109.08 ;
    END
  END di[645]
  PIN di[646]
    DIRECTION INPUT ;
    USE SIGNAL ;
    PORT
      LAYER M4 ;
        RECT  0 109.2 0.192 109.224 ;
    END
  END di[646]
  PIN di[647]
    DIRECTION INPUT ;
    USE SIGNAL ;
    PORT
      LAYER M4 ;
        RECT  0 109.344 0.192 109.368 ;
    END
  END di[647]
  PIN di[648]
    DIRECTION INPUT ;
    USE SIGNAL ;
    PORT
      LAYER M4 ;
        RECT  0 109.536 0.192 109.56 ;
    END
  END di[648]
  PIN di[649]
    DIRECTION INPUT ;
    USE SIGNAL ;
    PORT
      LAYER M4 ;
        RECT  0 109.68 0.192 109.704 ;
    END
  END di[649]
  PIN di[64]
    DIRECTION INPUT ;
    USE SIGNAL ;
    PORT
      LAYER M4 ;
        RECT  0 14.784 0.192 14.808 ;
    END
  END di[64]
  PIN di[650]
    DIRECTION INPUT ;
    USE SIGNAL ;
    PORT
      LAYER M4 ;
        RECT  0 109.872 0.192 109.896 ;
    END
  END di[650]
  PIN di[651]
    DIRECTION INPUT ;
    USE SIGNAL ;
    PORT
      LAYER M4 ;
        RECT  0 110.016 0.192 110.04 ;
    END
  END di[651]
  PIN di[652]
    DIRECTION INPUT ;
    USE SIGNAL ;
    PORT
      LAYER M4 ;
        RECT  0 110.16 0.192 110.184 ;
    END
  END di[652]
  PIN di[653]
    DIRECTION INPUT ;
    USE SIGNAL ;
    PORT
      LAYER M4 ;
        RECT  0 110.352 0.192 110.376 ;
    END
  END di[653]
  PIN di[654]
    DIRECTION INPUT ;
    USE SIGNAL ;
    PORT
      LAYER M4 ;
        RECT  0 110.496 0.192 110.52 ;
    END
  END di[654]
  PIN di[655]
    DIRECTION INPUT ;
    USE SIGNAL ;
    PORT
      LAYER M4 ;
        RECT  0 110.64 0.192 110.664 ;
    END
  END di[655]
  PIN di[656]
    DIRECTION INPUT ;
    USE SIGNAL ;
    PORT
      LAYER M4 ;
        RECT  0 110.832 0.192 110.856 ;
    END
  END di[656]
  PIN di[657]
    DIRECTION INPUT ;
    USE SIGNAL ;
    PORT
      LAYER M4 ;
        RECT  0 110.976 0.192 111 ;
    END
  END di[657]
  PIN di[658]
    DIRECTION INPUT ;
    USE SIGNAL ;
    PORT
      LAYER M4 ;
        RECT  0 111.168 0.192 111.192 ;
    END
  END di[658]
  PIN di[659]
    DIRECTION INPUT ;
    USE SIGNAL ;
    PORT
      LAYER M4 ;
        RECT  0 111.312 0.192 111.336 ;
    END
  END di[659]
  PIN di[65]
    DIRECTION INPUT ;
    USE SIGNAL ;
    PORT
      LAYER M4 ;
        RECT  0 14.976 0.192 15 ;
    END
  END di[65]
  PIN di[660]
    DIRECTION INPUT ;
    USE SIGNAL ;
    PORT
      LAYER M4 ;
        RECT  0 111.456 0.192 111.48 ;
    END
  END di[660]
  PIN di[661]
    DIRECTION INPUT ;
    USE SIGNAL ;
    PORT
      LAYER M4 ;
        RECT  0 111.648 0.192 111.672 ;
    END
  END di[661]
  PIN di[662]
    DIRECTION INPUT ;
    USE SIGNAL ;
    PORT
      LAYER M4 ;
        RECT  0 111.792 0.192 111.816 ;
    END
  END di[662]
  PIN di[663]
    DIRECTION INPUT ;
    USE SIGNAL ;
    PORT
      LAYER M4 ;
        RECT  0 111.984 0.192 112.008 ;
    END
  END di[663]
  PIN di[664]
    DIRECTION INPUT ;
    USE SIGNAL ;
    PORT
      LAYER M4 ;
        RECT  0 112.128 0.192 112.152 ;
    END
  END di[664]
  PIN di[665]
    DIRECTION INPUT ;
    USE SIGNAL ;
    PORT
      LAYER M4 ;
        RECT  0 112.272 0.192 112.296 ;
    END
  END di[665]
  PIN di[666]
    DIRECTION INPUT ;
    USE SIGNAL ;
    PORT
      LAYER M4 ;
        RECT  0 112.464 0.192 112.488 ;
    END
  END di[666]
  PIN di[667]
    DIRECTION INPUT ;
    USE SIGNAL ;
    PORT
      LAYER M4 ;
        RECT  0 112.608 0.192 112.632 ;
    END
  END di[667]
  PIN di[668]
    DIRECTION INPUT ;
    USE SIGNAL ;
    PORT
      LAYER M4 ;
        RECT  0 112.752 0.192 112.776 ;
    END
  END di[668]
  PIN di[669]
    DIRECTION INPUT ;
    USE SIGNAL ;
    PORT
      LAYER M4 ;
        RECT  0 112.944 0.192 112.968 ;
    END
  END di[669]
  PIN di[66]
    DIRECTION INPUT ;
    USE SIGNAL ;
    PORT
      LAYER M4 ;
        RECT  0 15.12 0.192 15.144 ;
    END
  END di[66]
  PIN di[670]
    DIRECTION INPUT ;
    USE SIGNAL ;
    PORT
      LAYER M4 ;
        RECT  0 113.088 0.192 113.112 ;
    END
  END di[670]
  PIN di[671]
    DIRECTION INPUT ;
    USE SIGNAL ;
    PORT
      LAYER M4 ;
        RECT  0 113.28 0.192 113.304 ;
    END
  END di[671]
  PIN di[672]
    DIRECTION INPUT ;
    USE SIGNAL ;
    PORT
      LAYER M4 ;
        RECT  0 113.424 0.192 113.448 ;
    END
  END di[672]
  PIN di[673]
    DIRECTION INPUT ;
    USE SIGNAL ;
    PORT
      LAYER M4 ;
        RECT  0 113.568 0.192 113.592 ;
    END
  END di[673]
  PIN di[674]
    DIRECTION INPUT ;
    USE SIGNAL ;
    PORT
      LAYER M4 ;
        RECT  0 113.76 0.192 113.784 ;
    END
  END di[674]
  PIN di[675]
    DIRECTION INPUT ;
    USE SIGNAL ;
    PORT
      LAYER M4 ;
        RECT  0 113.904 0.192 113.928 ;
    END
  END di[675]
  PIN di[676]
    DIRECTION INPUT ;
    USE SIGNAL ;
    PORT
      LAYER M4 ;
        RECT  0 114.048 0.192 114.072 ;
    END
  END di[676]
  PIN di[677]
    DIRECTION INPUT ;
    USE SIGNAL ;
    PORT
      LAYER M4 ;
        RECT  0 114.24 0.192 114.264 ;
    END
  END di[677]
  PIN di[678]
    DIRECTION INPUT ;
    USE SIGNAL ;
    PORT
      LAYER M4 ;
        RECT  0 114.384 0.192 114.408 ;
    END
  END di[678]
  PIN di[679]
    DIRECTION INPUT ;
    USE SIGNAL ;
    PORT
      LAYER M4 ;
        RECT  0 114.576 0.192 114.6 ;
    END
  END di[679]
  PIN di[67]
    DIRECTION INPUT ;
    USE SIGNAL ;
    PORT
      LAYER M4 ;
        RECT  0 15.264 0.192 15.288 ;
    END
  END di[67]
  PIN di[680]
    DIRECTION INPUT ;
    USE SIGNAL ;
    PORT
      LAYER M4 ;
        RECT  0 114.72 0.192 114.744 ;
    END
  END di[680]
  PIN di[681]
    DIRECTION INPUT ;
    USE SIGNAL ;
    PORT
      LAYER M4 ;
        RECT  0 114.864 0.192 114.888 ;
    END
  END di[681]
  PIN di[682]
    DIRECTION INPUT ;
    USE SIGNAL ;
    PORT
      LAYER M4 ;
        RECT  0 115.056 0.192 115.08 ;
    END
  END di[682]
  PIN di[683]
    DIRECTION INPUT ;
    USE SIGNAL ;
    PORT
      LAYER M4 ;
        RECT  0 115.2 0.192 115.224 ;
    END
  END di[683]
  PIN di[684]
    DIRECTION INPUT ;
    USE SIGNAL ;
    PORT
      LAYER M4 ;
        RECT  0 115.344 0.192 115.368 ;
    END
  END di[684]
  PIN di[685]
    DIRECTION INPUT ;
    USE SIGNAL ;
    PORT
      LAYER M4 ;
        RECT  0 115.536 0.192 115.56 ;
    END
  END di[685]
  PIN di[686]
    DIRECTION INPUT ;
    USE SIGNAL ;
    PORT
      LAYER M4 ;
        RECT  0 115.68 0.192 115.704 ;
    END
  END di[686]
  PIN di[687]
    DIRECTION INPUT ;
    USE SIGNAL ;
    PORT
      LAYER M4 ;
        RECT  0 115.872 0.192 115.896 ;
    END
  END di[687]
  PIN di[688]
    DIRECTION INPUT ;
    USE SIGNAL ;
    PORT
      LAYER M4 ;
        RECT  0 116.016 0.192 116.04 ;
    END
  END di[688]
  PIN di[689]
    DIRECTION INPUT ;
    USE SIGNAL ;
    PORT
      LAYER M4 ;
        RECT  0 116.16 0.192 116.184 ;
    END
  END di[689]
  PIN di[68]
    DIRECTION INPUT ;
    USE SIGNAL ;
    PORT
      LAYER M4 ;
        RECT  0 15.456 0.192 15.48 ;
    END
  END di[68]
  PIN di[690]
    DIRECTION INPUT ;
    USE SIGNAL ;
    PORT
      LAYER M4 ;
        RECT  0 116.352 0.192 116.376 ;
    END
  END di[690]
  PIN di[691]
    DIRECTION INPUT ;
    USE SIGNAL ;
    PORT
      LAYER M4 ;
        RECT  0 116.496 0.192 116.52 ;
    END
  END di[691]
  PIN di[692]
    DIRECTION INPUT ;
    USE SIGNAL ;
    PORT
      LAYER M4 ;
        RECT  0 116.688 0.192 116.712 ;
    END
  END di[692]
  PIN di[693]
    DIRECTION INPUT ;
    USE SIGNAL ;
    PORT
      LAYER M4 ;
        RECT  0 116.832 0.192 116.856 ;
    END
  END di[693]
  PIN di[694]
    DIRECTION INPUT ;
    USE SIGNAL ;
    PORT
      LAYER M4 ;
        RECT  0 116.976 0.192 117 ;
    END
  END di[694]
  PIN di[695]
    DIRECTION INPUT ;
    USE SIGNAL ;
    PORT
      LAYER M4 ;
        RECT  0 117.168 0.192 117.192 ;
    END
  END di[695]
  PIN di[696]
    DIRECTION INPUT ;
    USE SIGNAL ;
    PORT
      LAYER M4 ;
        RECT  0 117.312 0.192 117.336 ;
    END
  END di[696]
  PIN di[697]
    DIRECTION INPUT ;
    USE SIGNAL ;
    PORT
      LAYER M4 ;
        RECT  0 117.456 0.192 117.48 ;
    END
  END di[697]
  PIN di[698]
    DIRECTION INPUT ;
    USE SIGNAL ;
    PORT
      LAYER M4 ;
        RECT  0 117.648 0.192 117.672 ;
    END
  END di[698]
  PIN di[699]
    DIRECTION INPUT ;
    USE SIGNAL ;
    PORT
      LAYER M4 ;
        RECT  0 117.792 0.192 117.816 ;
    END
  END di[699]
  PIN di[69]
    DIRECTION INPUT ;
    USE SIGNAL ;
    PORT
      LAYER M4 ;
        RECT  0 15.6 0.192 15.624 ;
    END
  END di[69]
  PIN di[6]
    DIRECTION INPUT ;
    USE SIGNAL ;
    PORT
      LAYER M4 ;
        RECT  0 5.376 0.192 5.4 ;
    END
  END di[6]
  PIN di[700]
    DIRECTION INPUT ;
    USE SIGNAL ;
    PORT
      LAYER M4 ;
        RECT  0 117.984 0.192 118.008 ;
    END
  END di[700]
  PIN di[701]
    DIRECTION INPUT ;
    USE SIGNAL ;
    PORT
      LAYER M4 ;
        RECT  0 118.128 0.192 118.152 ;
    END
  END di[701]
  PIN di[702]
    DIRECTION INPUT ;
    USE SIGNAL ;
    PORT
      LAYER M4 ;
        RECT  0 118.272 0.192 118.296 ;
    END
  END di[702]
  PIN di[703]
    DIRECTION INPUT ;
    USE SIGNAL ;
    PORT
      LAYER M4 ;
        RECT  0 118.464 0.192 118.488 ;
    END
  END di[703]
  PIN di[704]
    DIRECTION INPUT ;
    USE SIGNAL ;
    PORT
      LAYER M4 ;
        RECT  0 118.608 0.192 118.632 ;
    END
  END di[704]
  PIN di[705]
    DIRECTION INPUT ;
    USE SIGNAL ;
    PORT
      LAYER M4 ;
        RECT  0 118.752 0.192 118.776 ;
    END
  END di[705]
  PIN di[706]
    DIRECTION INPUT ;
    USE SIGNAL ;
    PORT
      LAYER M4 ;
        RECT  0 118.944 0.192 118.968 ;
    END
  END di[706]
  PIN di[707]
    DIRECTION INPUT ;
    USE SIGNAL ;
    PORT
      LAYER M4 ;
        RECT  0 119.088 0.192 119.112 ;
    END
  END di[707]
  PIN di[708]
    DIRECTION INPUT ;
    USE SIGNAL ;
    PORT
      LAYER M4 ;
        RECT  0 119.28 0.192 119.304 ;
    END
  END di[708]
  PIN di[709]
    DIRECTION INPUT ;
    USE SIGNAL ;
    PORT
      LAYER M4 ;
        RECT  0 119.424 0.192 119.448 ;
    END
  END di[709]
  PIN di[70]
    DIRECTION INPUT ;
    USE SIGNAL ;
    PORT
      LAYER M4 ;
        RECT  0 15.792 0.192 15.816 ;
    END
  END di[70]
  PIN di[710]
    DIRECTION INPUT ;
    USE SIGNAL ;
    PORT
      LAYER M4 ;
        RECT  0 119.568 0.192 119.592 ;
    END
  END di[710]
  PIN di[711]
    DIRECTION INPUT ;
    USE SIGNAL ;
    PORT
      LAYER M4 ;
        RECT  0 119.76 0.192 119.784 ;
    END
  END di[711]
  PIN di[712]
    DIRECTION INPUT ;
    USE SIGNAL ;
    PORT
      LAYER M4 ;
        RECT  0 119.904 0.192 119.928 ;
    END
  END di[712]
  PIN di[713]
    DIRECTION INPUT ;
    USE SIGNAL ;
    PORT
      LAYER M4 ;
        RECT  0 120.048 0.192 120.072 ;
    END
  END di[713]
  PIN di[714]
    DIRECTION INPUT ;
    USE SIGNAL ;
    PORT
      LAYER M4 ;
        RECT  0 120.24 0.192 120.264 ;
    END
  END di[714]
  PIN di[715]
    DIRECTION INPUT ;
    USE SIGNAL ;
    PORT
      LAYER M4 ;
        RECT  0 120.384 0.192 120.408 ;
    END
  END di[715]
  PIN di[716]
    DIRECTION INPUT ;
    USE SIGNAL ;
    PORT
      LAYER M4 ;
        RECT  0 120.576 0.192 120.6 ;
    END
  END di[716]
  PIN di[717]
    DIRECTION INPUT ;
    USE SIGNAL ;
    PORT
      LAYER M4 ;
        RECT  0 120.72 0.192 120.744 ;
    END
  END di[717]
  PIN di[718]
    DIRECTION INPUT ;
    USE SIGNAL ;
    PORT
      LAYER M4 ;
        RECT  0 120.864 0.192 120.888 ;
    END
  END di[718]
  PIN di[719]
    DIRECTION INPUT ;
    USE SIGNAL ;
    PORT
      LAYER M4 ;
        RECT  0 121.056 0.192 121.08 ;
    END
  END di[719]
  PIN di[71]
    DIRECTION INPUT ;
    USE SIGNAL ;
    PORT
      LAYER M4 ;
        RECT  0 15.936 0.192 15.96 ;
    END
  END di[71]
  PIN di[720]
    DIRECTION INPUT ;
    USE SIGNAL ;
    PORT
      LAYER M4 ;
        RECT  0 121.2 0.192 121.224 ;
    END
  END di[720]
  PIN di[721]
    DIRECTION INPUT ;
    USE SIGNAL ;
    PORT
      LAYER M4 ;
        RECT  0 121.392 0.192 121.416 ;
    END
  END di[721]
  PIN di[722]
    DIRECTION INPUT ;
    USE SIGNAL ;
    PORT
      LAYER M4 ;
        RECT  0 121.536 0.192 121.56 ;
    END
  END di[722]
  PIN di[723]
    DIRECTION INPUT ;
    USE SIGNAL ;
    PORT
      LAYER M4 ;
        RECT  0 121.68 0.192 121.704 ;
    END
  END di[723]
  PIN di[724]
    DIRECTION INPUT ;
    USE SIGNAL ;
    PORT
      LAYER M4 ;
        RECT  0 121.872 0.192 121.896 ;
    END
  END di[724]
  PIN di[725]
    DIRECTION INPUT ;
    USE SIGNAL ;
    PORT
      LAYER M4 ;
        RECT  0 122.016 0.192 122.04 ;
    END
  END di[725]
  PIN di[726]
    DIRECTION INPUT ;
    USE SIGNAL ;
    PORT
      LAYER M4 ;
        RECT  0 122.16 0.192 122.184 ;
    END
  END di[726]
  PIN di[727]
    DIRECTION INPUT ;
    USE SIGNAL ;
    PORT
      LAYER M4 ;
        RECT  0 122.352 0.192 122.376 ;
    END
  END di[727]
  PIN di[728]
    DIRECTION INPUT ;
    USE SIGNAL ;
    PORT
      LAYER M4 ;
        RECT  0 122.496 0.192 122.52 ;
    END
  END di[728]
  PIN di[729]
    DIRECTION INPUT ;
    USE SIGNAL ;
    PORT
      LAYER M4 ;
        RECT  0 122.688 0.192 122.712 ;
    END
  END di[729]
  PIN di[72]
    DIRECTION INPUT ;
    USE SIGNAL ;
    PORT
      LAYER M4 ;
        RECT  0 16.08 0.192 16.104 ;
    END
  END di[72]
  PIN di[730]
    DIRECTION INPUT ;
    USE SIGNAL ;
    PORT
      LAYER M4 ;
        RECT  0 122.832 0.192 122.856 ;
    END
  END di[730]
  PIN di[731]
    DIRECTION INPUT ;
    USE SIGNAL ;
    PORT
      LAYER M4 ;
        RECT  0 122.976 0.192 123 ;
    END
  END di[731]
  PIN di[732]
    DIRECTION INPUT ;
    USE SIGNAL ;
    PORT
      LAYER M4 ;
        RECT  0 123.168 0.192 123.192 ;
    END
  END di[732]
  PIN di[733]
    DIRECTION INPUT ;
    USE SIGNAL ;
    PORT
      LAYER M4 ;
        RECT  0 123.312 0.192 123.336 ;
    END
  END di[733]
  PIN di[734]
    DIRECTION INPUT ;
    USE SIGNAL ;
    PORT
      LAYER M4 ;
        RECT  0 123.456 0.192 123.48 ;
    END
  END di[734]
  PIN di[735]
    DIRECTION INPUT ;
    USE SIGNAL ;
    PORT
      LAYER M4 ;
        RECT  0 123.648 0.192 123.672 ;
    END
  END di[735]
  PIN di[736]
    DIRECTION INPUT ;
    USE SIGNAL ;
    PORT
      LAYER M4 ;
        RECT  0 123.792 0.192 123.816 ;
    END
  END di[736]
  PIN di[737]
    DIRECTION INPUT ;
    USE SIGNAL ;
    PORT
      LAYER M4 ;
        RECT  0 123.984 0.192 124.008 ;
    END
  END di[737]
  PIN di[738]
    DIRECTION INPUT ;
    USE SIGNAL ;
    PORT
      LAYER M4 ;
        RECT  0 124.128 0.192 124.152 ;
    END
  END di[738]
  PIN di[739]
    DIRECTION INPUT ;
    USE SIGNAL ;
    PORT
      LAYER M4 ;
        RECT  0 124.272 0.192 124.296 ;
    END
  END di[739]
  PIN di[73]
    DIRECTION INPUT ;
    USE SIGNAL ;
    PORT
      LAYER M4 ;
        RECT  0 16.272 0.192 16.296 ;
    END
  END di[73]
  PIN di[740]
    DIRECTION INPUT ;
    USE SIGNAL ;
    PORT
      LAYER M4 ;
        RECT  0 124.464 0.192 124.488 ;
    END
  END di[740]
  PIN di[741]
    DIRECTION INPUT ;
    USE SIGNAL ;
    PORT
      LAYER M4 ;
        RECT  0 124.608 0.192 124.632 ;
    END
  END di[741]
  PIN di[742]
    DIRECTION INPUT ;
    USE SIGNAL ;
    PORT
      LAYER M4 ;
        RECT  0 124.752 0.192 124.776 ;
    END
  END di[742]
  PIN di[743]
    DIRECTION INPUT ;
    USE SIGNAL ;
    PORT
      LAYER M4 ;
        RECT  0 124.944 0.192 124.968 ;
    END
  END di[743]
  PIN di[744]
    DIRECTION INPUT ;
    USE SIGNAL ;
    PORT
      LAYER M4 ;
        RECT  0 125.088 0.192 125.112 ;
    END
  END di[744]
  PIN di[745]
    DIRECTION INPUT ;
    USE SIGNAL ;
    PORT
      LAYER M4 ;
        RECT  0 125.28 0.192 125.304 ;
    END
  END di[745]
  PIN di[746]
    DIRECTION INPUT ;
    USE SIGNAL ;
    PORT
      LAYER M4 ;
        RECT  0 125.424 0.192 125.448 ;
    END
  END di[746]
  PIN di[747]
    DIRECTION INPUT ;
    USE SIGNAL ;
    PORT
      LAYER M4 ;
        RECT  0 125.568 0.192 125.592 ;
    END
  END di[747]
  PIN di[748]
    DIRECTION INPUT ;
    USE SIGNAL ;
    PORT
      LAYER M4 ;
        RECT  0 125.76 0.192 125.784 ;
    END
  END di[748]
  PIN di[749]
    DIRECTION INPUT ;
    USE SIGNAL ;
    PORT
      LAYER M4 ;
        RECT  0 125.904 0.192 125.928 ;
    END
  END di[749]
  PIN di[74]
    DIRECTION INPUT ;
    USE SIGNAL ;
    PORT
      LAYER M4 ;
        RECT  0 16.416 0.192 16.44 ;
    END
  END di[74]
  PIN di[750]
    DIRECTION INPUT ;
    USE SIGNAL ;
    PORT
      LAYER M4 ;
        RECT  0 126.096 0.192 126.12 ;
    END
  END di[750]
  PIN di[751]
    DIRECTION INPUT ;
    USE SIGNAL ;
    PORT
      LAYER M4 ;
        RECT  0 126.24 0.192 126.264 ;
    END
  END di[751]
  PIN di[752]
    DIRECTION INPUT ;
    USE SIGNAL ;
    PORT
      LAYER M4 ;
        RECT  0 126.384 0.192 126.408 ;
    END
  END di[752]
  PIN di[753]
    DIRECTION INPUT ;
    USE SIGNAL ;
    PORT
      LAYER M4 ;
        RECT  0 126.576 0.192 126.6 ;
    END
  END di[753]
  PIN di[754]
    DIRECTION INPUT ;
    USE SIGNAL ;
    PORT
      LAYER M4 ;
        RECT  0 126.72 0.192 126.744 ;
    END
  END di[754]
  PIN di[755]
    DIRECTION INPUT ;
    USE SIGNAL ;
    PORT
      LAYER M4 ;
        RECT  0 126.864 0.192 126.888 ;
    END
  END di[755]
  PIN di[756]
    DIRECTION INPUT ;
    USE SIGNAL ;
    PORT
      LAYER M4 ;
        RECT  0 127.056 0.192 127.08 ;
    END
  END di[756]
  PIN di[757]
    DIRECTION INPUT ;
    USE SIGNAL ;
    PORT
      LAYER M4 ;
        RECT  0 127.2 0.192 127.224 ;
    END
  END di[757]
  PIN di[758]
    DIRECTION INPUT ;
    USE SIGNAL ;
    PORT
      LAYER M4 ;
        RECT  0 127.392 0.192 127.416 ;
    END
  END di[758]
  PIN di[75]
    DIRECTION INPUT ;
    USE SIGNAL ;
    PORT
      LAYER M4 ;
        RECT  0 16.56 0.192 16.584 ;
    END
  END di[75]
  PIN di[76]
    DIRECTION INPUT ;
    USE SIGNAL ;
    PORT
      LAYER M4 ;
        RECT  0 16.752 0.192 16.776 ;
    END
  END di[76]
  PIN di[77]
    DIRECTION INPUT ;
    USE SIGNAL ;
    PORT
      LAYER M4 ;
        RECT  0 16.896 0.192 16.92 ;
    END
  END di[77]
  PIN di[78]
    DIRECTION INPUT ;
    USE SIGNAL ;
    PORT
      LAYER M4 ;
        RECT  0 17.088 0.192 17.112 ;
    END
  END di[78]
  PIN di[79]
    DIRECTION INPUT ;
    USE SIGNAL ;
    PORT
      LAYER M4 ;
        RECT  0 17.232 0.192 17.256 ;
    END
  END di[79]
  PIN di[7]
    DIRECTION INPUT ;
    USE SIGNAL ;
    PORT
      LAYER M4 ;
        RECT  0 5.568 0.192 5.592 ;
    END
  END di[7]
  PIN di[80]
    DIRECTION INPUT ;
    USE SIGNAL ;
    PORT
      LAYER M4 ;
        RECT  0 17.376 0.192 17.4 ;
    END
  END di[80]
  PIN di[81]
    DIRECTION INPUT ;
    USE SIGNAL ;
    PORT
      LAYER M4 ;
        RECT  0 17.568 0.192 17.592 ;
    END
  END di[81]
  PIN di[82]
    DIRECTION INPUT ;
    USE SIGNAL ;
    PORT
      LAYER M4 ;
        RECT  0 17.712 0.192 17.736 ;
    END
  END di[82]
  PIN di[83]
    DIRECTION INPUT ;
    USE SIGNAL ;
    PORT
      LAYER M4 ;
        RECT  0 17.856 0.192 17.88 ;
    END
  END di[83]
  PIN di[84]
    DIRECTION INPUT ;
    USE SIGNAL ;
    PORT
      LAYER M4 ;
        RECT  0 18.048 0.192 18.072 ;
    END
  END di[84]
  PIN di[85]
    DIRECTION INPUT ;
    USE SIGNAL ;
    PORT
      LAYER M4 ;
        RECT  0 18.192 0.192 18.216 ;
    END
  END di[85]
  PIN di[86]
    DIRECTION INPUT ;
    USE SIGNAL ;
    PORT
      LAYER M4 ;
        RECT  0 18.384 0.192 18.408 ;
    END
  END di[86]
  PIN di[87]
    DIRECTION INPUT ;
    USE SIGNAL ;
    PORT
      LAYER M4 ;
        RECT  0 18.528 0.192 18.552 ;
    END
  END di[87]
  PIN di[88]
    DIRECTION INPUT ;
    USE SIGNAL ;
    PORT
      LAYER M4 ;
        RECT  0 18.672 0.192 18.696 ;
    END
  END di[88]
  PIN di[89]
    DIRECTION INPUT ;
    USE SIGNAL ;
    PORT
      LAYER M4 ;
        RECT  0 18.864 0.192 18.888 ;
    END
  END di[89]
  PIN di[8]
    DIRECTION INPUT ;
    USE SIGNAL ;
    PORT
      LAYER M4 ;
        RECT  0 5.712 0.192 5.736 ;
    END
  END di[8]
  PIN di[90]
    DIRECTION INPUT ;
    USE SIGNAL ;
    PORT
      LAYER M4 ;
        RECT  0 19.008 0.192 19.032 ;
    END
  END di[90]
  PIN di[91]
    DIRECTION INPUT ;
    USE SIGNAL ;
    PORT
      LAYER M4 ;
        RECT  0 19.152 0.192 19.176 ;
    END
  END di[91]
  PIN di[92]
    DIRECTION INPUT ;
    USE SIGNAL ;
    PORT
      LAYER M4 ;
        RECT  0 19.344 0.192 19.368 ;
    END
  END di[92]
  PIN di[93]
    DIRECTION INPUT ;
    USE SIGNAL ;
    PORT
      LAYER M4 ;
        RECT  0 19.488 0.192 19.512 ;
    END
  END di[93]
  PIN di[94]
    DIRECTION INPUT ;
    USE SIGNAL ;
    PORT
      LAYER M4 ;
        RECT  0 19.68 0.192 19.704 ;
    END
  END di[94]
  PIN di[95]
    DIRECTION INPUT ;
    USE SIGNAL ;
    PORT
      LAYER M4 ;
        RECT  0 19.824 0.192 19.848 ;
    END
  END di[95]
  PIN di[96]
    DIRECTION INPUT ;
    USE SIGNAL ;
    PORT
      LAYER M4 ;
        RECT  0 19.968 0.192 19.992 ;
    END
  END di[96]
  PIN di[97]
    DIRECTION INPUT ;
    USE SIGNAL ;
    PORT
      LAYER M4 ;
        RECT  0 20.16 0.192 20.184 ;
    END
  END di[97]
  PIN di[98]
    DIRECTION INPUT ;
    USE SIGNAL ;
    PORT
      LAYER M4 ;
        RECT  0 20.304 0.192 20.328 ;
    END
  END di[98]
  PIN di[99]
    DIRECTION INPUT ;
    USE SIGNAL ;
    PORT
      LAYER M4 ;
        RECT  0 20.496 0.192 20.52 ;
    END
  END di[99]
  PIN di[9]
    DIRECTION INPUT ;
    USE SIGNAL ;
    PORT
      LAYER M4 ;
        RECT  0 5.856 0.192 5.88 ;
    END
  END di[9]
  PIN dq[0]
    DIRECTION OUTPUT ;
    USE SIGNAL ;
    PORT
      LAYER M4 ;
        RECT  34.368 4.416 34.56 4.44 ;
    END
  END dq[0]
  PIN dq[100]
    DIRECTION OUTPUT ;
    USE SIGNAL ;
    PORT
      LAYER M4 ;
        RECT  34.368 20.64 34.56 20.664 ;
    END
  END dq[100]
  PIN dq[101]
    DIRECTION OUTPUT ;
    USE SIGNAL ;
    PORT
      LAYER M4 ;
        RECT  34.368 20.784 34.56 20.808 ;
    END
  END dq[101]
  PIN dq[102]
    DIRECTION OUTPUT ;
    USE SIGNAL ;
    PORT
      LAYER M4 ;
        RECT  34.368 20.976 34.56 21 ;
    END
  END dq[102]
  PIN dq[103]
    DIRECTION OUTPUT ;
    USE SIGNAL ;
    PORT
      LAYER M4 ;
        RECT  34.368 21.12 34.56 21.144 ;
    END
  END dq[103]
  PIN dq[104]
    DIRECTION OUTPUT ;
    USE SIGNAL ;
    PORT
      LAYER M4 ;
        RECT  34.368 21.264 34.56 21.288 ;
    END
  END dq[104]
  PIN dq[105]
    DIRECTION OUTPUT ;
    USE SIGNAL ;
    PORT
      LAYER M4 ;
        RECT  34.368 21.456 34.56 21.48 ;
    END
  END dq[105]
  PIN dq[106]
    DIRECTION OUTPUT ;
    USE SIGNAL ;
    PORT
      LAYER M4 ;
        RECT  34.368 21.6 34.56 21.624 ;
    END
  END dq[106]
  PIN dq[107]
    DIRECTION OUTPUT ;
    USE SIGNAL ;
    PORT
      LAYER M4 ;
        RECT  34.368 21.792 34.56 21.816 ;
    END
  END dq[107]
  PIN dq[108]
    DIRECTION OUTPUT ;
    USE SIGNAL ;
    PORT
      LAYER M4 ;
        RECT  34.368 21.936 34.56 21.96 ;
    END
  END dq[108]
  PIN dq[109]
    DIRECTION OUTPUT ;
    USE SIGNAL ;
    PORT
      LAYER M4 ;
        RECT  34.368 22.08 34.56 22.104 ;
    END
  END dq[109]
  PIN dq[10]
    DIRECTION OUTPUT ;
    USE SIGNAL ;
    PORT
      LAYER M4 ;
        RECT  34.368 6.048 34.56 6.072 ;
    END
  END dq[10]
  PIN dq[110]
    DIRECTION OUTPUT ;
    USE SIGNAL ;
    PORT
      LAYER M4 ;
        RECT  34.368 22.272 34.56 22.296 ;
    END
  END dq[110]
  PIN dq[111]
    DIRECTION OUTPUT ;
    USE SIGNAL ;
    PORT
      LAYER M4 ;
        RECT  34.368 22.416 34.56 22.44 ;
    END
  END dq[111]
  PIN dq[112]
    DIRECTION OUTPUT ;
    USE SIGNAL ;
    PORT
      LAYER M4 ;
        RECT  34.368 22.56 34.56 22.584 ;
    END
  END dq[112]
  PIN dq[113]
    DIRECTION OUTPUT ;
    USE SIGNAL ;
    PORT
      LAYER M4 ;
        RECT  34.368 22.752 34.56 22.776 ;
    END
  END dq[113]
  PIN dq[114]
    DIRECTION OUTPUT ;
    USE SIGNAL ;
    PORT
      LAYER M4 ;
        RECT  34.368 22.896 34.56 22.92 ;
    END
  END dq[114]
  PIN dq[115]
    DIRECTION OUTPUT ;
    USE SIGNAL ;
    PORT
      LAYER M4 ;
        RECT  34.368 23.088 34.56 23.112 ;
    END
  END dq[115]
  PIN dq[116]
    DIRECTION OUTPUT ;
    USE SIGNAL ;
    PORT
      LAYER M4 ;
        RECT  34.368 23.232 34.56 23.256 ;
    END
  END dq[116]
  PIN dq[117]
    DIRECTION OUTPUT ;
    USE SIGNAL ;
    PORT
      LAYER M4 ;
        RECT  34.368 23.376 34.56 23.4 ;
    END
  END dq[117]
  PIN dq[118]
    DIRECTION OUTPUT ;
    USE SIGNAL ;
    PORT
      LAYER M4 ;
        RECT  34.368 23.568 34.56 23.592 ;
    END
  END dq[118]
  PIN dq[119]
    DIRECTION OUTPUT ;
    USE SIGNAL ;
    PORT
      LAYER M4 ;
        RECT  34.368 23.712 34.56 23.736 ;
    END
  END dq[119]
  PIN dq[11]
    DIRECTION OUTPUT ;
    USE SIGNAL ;
    PORT
      LAYER M4 ;
        RECT  34.368 6.192 34.56 6.216 ;
    END
  END dq[11]
  PIN dq[120]
    DIRECTION OUTPUT ;
    USE SIGNAL ;
    PORT
      LAYER M4 ;
        RECT  34.368 23.856 34.56 23.88 ;
    END
  END dq[120]
  PIN dq[121]
    DIRECTION OUTPUT ;
    USE SIGNAL ;
    PORT
      LAYER M4 ;
        RECT  34.368 24.048 34.56 24.072 ;
    END
  END dq[121]
  PIN dq[122]
    DIRECTION OUTPUT ;
    USE SIGNAL ;
    PORT
      LAYER M4 ;
        RECT  34.368 24.192 34.56 24.216 ;
    END
  END dq[122]
  PIN dq[123]
    DIRECTION OUTPUT ;
    USE SIGNAL ;
    PORT
      LAYER M4 ;
        RECT  34.368 24.384 34.56 24.408 ;
    END
  END dq[123]
  PIN dq[124]
    DIRECTION OUTPUT ;
    USE SIGNAL ;
    PORT
      LAYER M4 ;
        RECT  34.368 24.528 34.56 24.552 ;
    END
  END dq[124]
  PIN dq[125]
    DIRECTION OUTPUT ;
    USE SIGNAL ;
    PORT
      LAYER M4 ;
        RECT  34.368 24.672 34.56 24.696 ;
    END
  END dq[125]
  PIN dq[126]
    DIRECTION OUTPUT ;
    USE SIGNAL ;
    PORT
      LAYER M4 ;
        RECT  34.368 24.864 34.56 24.888 ;
    END
  END dq[126]
  PIN dq[127]
    DIRECTION OUTPUT ;
    USE SIGNAL ;
    PORT
      LAYER M4 ;
        RECT  34.368 25.008 34.56 25.032 ;
    END
  END dq[127]
  PIN dq[128]
    DIRECTION OUTPUT ;
    USE SIGNAL ;
    PORT
      LAYER M4 ;
        RECT  34.368 25.2 34.56 25.224 ;
    END
  END dq[128]
  PIN dq[129]
    DIRECTION OUTPUT ;
    USE SIGNAL ;
    PORT
      LAYER M4 ;
        RECT  34.368 25.344 34.56 25.368 ;
    END
  END dq[129]
  PIN dq[12]
    DIRECTION OUTPUT ;
    USE SIGNAL ;
    PORT
      LAYER M4 ;
        RECT  34.368 6.336 34.56 6.36 ;
    END
  END dq[12]
  PIN dq[130]
    DIRECTION OUTPUT ;
    USE SIGNAL ;
    PORT
      LAYER M4 ;
        RECT  34.368 25.488 34.56 25.512 ;
    END
  END dq[130]
  PIN dq[131]
    DIRECTION OUTPUT ;
    USE SIGNAL ;
    PORT
      LAYER M4 ;
        RECT  34.368 25.68 34.56 25.704 ;
    END
  END dq[131]
  PIN dq[132]
    DIRECTION OUTPUT ;
    USE SIGNAL ;
    PORT
      LAYER M4 ;
        RECT  34.368 25.824 34.56 25.848 ;
    END
  END dq[132]
  PIN dq[133]
    DIRECTION OUTPUT ;
    USE SIGNAL ;
    PORT
      LAYER M4 ;
        RECT  34.368 25.968 34.56 25.992 ;
    END
  END dq[133]
  PIN dq[134]
    DIRECTION OUTPUT ;
    USE SIGNAL ;
    PORT
      LAYER M4 ;
        RECT  34.368 26.16 34.56 26.184 ;
    END
  END dq[134]
  PIN dq[135]
    DIRECTION OUTPUT ;
    USE SIGNAL ;
    PORT
      LAYER M4 ;
        RECT  34.368 26.304 34.56 26.328 ;
    END
  END dq[135]
  PIN dq[136]
    DIRECTION OUTPUT ;
    USE SIGNAL ;
    PORT
      LAYER M4 ;
        RECT  34.368 26.496 34.56 26.52 ;
    END
  END dq[136]
  PIN dq[137]
    DIRECTION OUTPUT ;
    USE SIGNAL ;
    PORT
      LAYER M4 ;
        RECT  34.368 26.64 34.56 26.664 ;
    END
  END dq[137]
  PIN dq[138]
    DIRECTION OUTPUT ;
    USE SIGNAL ;
    PORT
      LAYER M4 ;
        RECT  34.368 26.784 34.56 26.808 ;
    END
  END dq[138]
  PIN dq[139]
    DIRECTION OUTPUT ;
    USE SIGNAL ;
    PORT
      LAYER M4 ;
        RECT  34.368 26.976 34.56 27 ;
    END
  END dq[139]
  PIN dq[13]
    DIRECTION OUTPUT ;
    USE SIGNAL ;
    PORT
      LAYER M4 ;
        RECT  34.368 6.528 34.56 6.552 ;
    END
  END dq[13]
  PIN dq[140]
    DIRECTION OUTPUT ;
    USE SIGNAL ;
    PORT
      LAYER M4 ;
        RECT  34.368 27.12 34.56 27.144 ;
    END
  END dq[140]
  PIN dq[141]
    DIRECTION OUTPUT ;
    USE SIGNAL ;
    PORT
      LAYER M4 ;
        RECT  34.368 27.264 34.56 27.288 ;
    END
  END dq[141]
  PIN dq[142]
    DIRECTION OUTPUT ;
    USE SIGNAL ;
    PORT
      LAYER M4 ;
        RECT  34.368 27.456 34.56 27.48 ;
    END
  END dq[142]
  PIN dq[143]
    DIRECTION OUTPUT ;
    USE SIGNAL ;
    PORT
      LAYER M4 ;
        RECT  34.368 27.6 34.56 27.624 ;
    END
  END dq[143]
  PIN dq[144]
    DIRECTION OUTPUT ;
    USE SIGNAL ;
    PORT
      LAYER M4 ;
        RECT  34.368 27.792 34.56 27.816 ;
    END
  END dq[144]
  PIN dq[145]
    DIRECTION OUTPUT ;
    USE SIGNAL ;
    PORT
      LAYER M4 ;
        RECT  34.368 27.936 34.56 27.96 ;
    END
  END dq[145]
  PIN dq[146]
    DIRECTION OUTPUT ;
    USE SIGNAL ;
    PORT
      LAYER M4 ;
        RECT  34.368 28.08 34.56 28.104 ;
    END
  END dq[146]
  PIN dq[147]
    DIRECTION OUTPUT ;
    USE SIGNAL ;
    PORT
      LAYER M4 ;
        RECT  34.368 28.272 34.56 28.296 ;
    END
  END dq[147]
  PIN dq[148]
    DIRECTION OUTPUT ;
    USE SIGNAL ;
    PORT
      LAYER M4 ;
        RECT  34.368 28.416 34.56 28.44 ;
    END
  END dq[148]
  PIN dq[149]
    DIRECTION OUTPUT ;
    USE SIGNAL ;
    PORT
      LAYER M4 ;
        RECT  34.368 28.56 34.56 28.584 ;
    END
  END dq[149]
  PIN dq[14]
    DIRECTION OUTPUT ;
    USE SIGNAL ;
    PORT
      LAYER M4 ;
        RECT  34.368 6.672 34.56 6.696 ;
    END
  END dq[14]
  PIN dq[150]
    DIRECTION OUTPUT ;
    USE SIGNAL ;
    PORT
      LAYER M4 ;
        RECT  34.368 28.752 34.56 28.776 ;
    END
  END dq[150]
  PIN dq[151]
    DIRECTION OUTPUT ;
    USE SIGNAL ;
    PORT
      LAYER M4 ;
        RECT  34.368 28.896 34.56 28.92 ;
    END
  END dq[151]
  PIN dq[152]
    DIRECTION OUTPUT ;
    USE SIGNAL ;
    PORT
      LAYER M4 ;
        RECT  34.368 29.088 34.56 29.112 ;
    END
  END dq[152]
  PIN dq[153]
    DIRECTION OUTPUT ;
    USE SIGNAL ;
    PORT
      LAYER M4 ;
        RECT  34.368 29.232 34.56 29.256 ;
    END
  END dq[153]
  PIN dq[154]
    DIRECTION OUTPUT ;
    USE SIGNAL ;
    PORT
      LAYER M4 ;
        RECT  34.368 29.376 34.56 29.4 ;
    END
  END dq[154]
  PIN dq[155]
    DIRECTION OUTPUT ;
    USE SIGNAL ;
    PORT
      LAYER M4 ;
        RECT  34.368 29.568 34.56 29.592 ;
    END
  END dq[155]
  PIN dq[156]
    DIRECTION OUTPUT ;
    USE SIGNAL ;
    PORT
      LAYER M4 ;
        RECT  34.368 29.712 34.56 29.736 ;
    END
  END dq[156]
  PIN dq[157]
    DIRECTION OUTPUT ;
    USE SIGNAL ;
    PORT
      LAYER M4 ;
        RECT  34.368 29.904 34.56 29.928 ;
    END
  END dq[157]
  PIN dq[158]
    DIRECTION OUTPUT ;
    USE SIGNAL ;
    PORT
      LAYER M4 ;
        RECT  34.368 30.048 34.56 30.072 ;
    END
  END dq[158]
  PIN dq[159]
    DIRECTION OUTPUT ;
    USE SIGNAL ;
    PORT
      LAYER M4 ;
        RECT  34.368 30.192 34.56 30.216 ;
    END
  END dq[159]
  PIN dq[15]
    DIRECTION OUTPUT ;
    USE SIGNAL ;
    PORT
      LAYER M4 ;
        RECT  34.368 6.864 34.56 6.888 ;
    END
  END dq[15]
  PIN dq[160]
    DIRECTION OUTPUT ;
    USE SIGNAL ;
    PORT
      LAYER M4 ;
        RECT  34.368 30.384 34.56 30.408 ;
    END
  END dq[160]
  PIN dq[161]
    DIRECTION OUTPUT ;
    USE SIGNAL ;
    PORT
      LAYER M4 ;
        RECT  34.368 30.528 34.56 30.552 ;
    END
  END dq[161]
  PIN dq[162]
    DIRECTION OUTPUT ;
    USE SIGNAL ;
    PORT
      LAYER M4 ;
        RECT  34.368 30.672 34.56 30.696 ;
    END
  END dq[162]
  PIN dq[163]
    DIRECTION OUTPUT ;
    USE SIGNAL ;
    PORT
      LAYER M4 ;
        RECT  34.368 30.864 34.56 30.888 ;
    END
  END dq[163]
  PIN dq[164]
    DIRECTION OUTPUT ;
    USE SIGNAL ;
    PORT
      LAYER M4 ;
        RECT  34.368 31.008 34.56 31.032 ;
    END
  END dq[164]
  PIN dq[165]
    DIRECTION OUTPUT ;
    USE SIGNAL ;
    PORT
      LAYER M4 ;
        RECT  34.368 31.2 34.56 31.224 ;
    END
  END dq[165]
  PIN dq[166]
    DIRECTION OUTPUT ;
    USE SIGNAL ;
    PORT
      LAYER M4 ;
        RECT  34.368 31.344 34.56 31.368 ;
    END
  END dq[166]
  PIN dq[167]
    DIRECTION OUTPUT ;
    USE SIGNAL ;
    PORT
      LAYER M4 ;
        RECT  34.368 31.488 34.56 31.512 ;
    END
  END dq[167]
  PIN dq[168]
    DIRECTION OUTPUT ;
    USE SIGNAL ;
    PORT
      LAYER M4 ;
        RECT  34.368 31.68 34.56 31.704 ;
    END
  END dq[168]
  PIN dq[169]
    DIRECTION OUTPUT ;
    USE SIGNAL ;
    PORT
      LAYER M4 ;
        RECT  34.368 31.824 34.56 31.848 ;
    END
  END dq[169]
  PIN dq[16]
    DIRECTION OUTPUT ;
    USE SIGNAL ;
    PORT
      LAYER M4 ;
        RECT  34.368 7.008 34.56 7.032 ;
    END
  END dq[16]
  PIN dq[170]
    DIRECTION OUTPUT ;
    USE SIGNAL ;
    PORT
      LAYER M4 ;
        RECT  34.368 31.968 34.56 31.992 ;
    END
  END dq[170]
  PIN dq[171]
    DIRECTION OUTPUT ;
    USE SIGNAL ;
    PORT
      LAYER M4 ;
        RECT  34.368 32.16 34.56 32.184 ;
    END
  END dq[171]
  PIN dq[172]
    DIRECTION OUTPUT ;
    USE SIGNAL ;
    PORT
      LAYER M4 ;
        RECT  34.368 32.304 34.56 32.328 ;
    END
  END dq[172]
  PIN dq[173]
    DIRECTION OUTPUT ;
    USE SIGNAL ;
    PORT
      LAYER M4 ;
        RECT  34.368 32.496 34.56 32.52 ;
    END
  END dq[173]
  PIN dq[174]
    DIRECTION OUTPUT ;
    USE SIGNAL ;
    PORT
      LAYER M4 ;
        RECT  34.368 32.64 34.56 32.664 ;
    END
  END dq[174]
  PIN dq[175]
    DIRECTION OUTPUT ;
    USE SIGNAL ;
    PORT
      LAYER M4 ;
        RECT  34.368 32.784 34.56 32.808 ;
    END
  END dq[175]
  PIN dq[176]
    DIRECTION OUTPUT ;
    USE SIGNAL ;
    PORT
      LAYER M4 ;
        RECT  34.368 32.976 34.56 33 ;
    END
  END dq[176]
  PIN dq[177]
    DIRECTION OUTPUT ;
    USE SIGNAL ;
    PORT
      LAYER M4 ;
        RECT  34.368 33.12 34.56 33.144 ;
    END
  END dq[177]
  PIN dq[178]
    DIRECTION OUTPUT ;
    USE SIGNAL ;
    PORT
      LAYER M4 ;
        RECT  34.368 33.264 34.56 33.288 ;
    END
  END dq[178]
  PIN dq[179]
    DIRECTION OUTPUT ;
    USE SIGNAL ;
    PORT
      LAYER M4 ;
        RECT  34.368 33.456 34.56 33.48 ;
    END
  END dq[179]
  PIN dq[17]
    DIRECTION OUTPUT ;
    USE SIGNAL ;
    PORT
      LAYER M4 ;
        RECT  34.368 7.152 34.56 7.176 ;
    END
  END dq[17]
  PIN dq[180]
    DIRECTION OUTPUT ;
    USE SIGNAL ;
    PORT
      LAYER M4 ;
        RECT  34.368 33.6 34.56 33.624 ;
    END
  END dq[180]
  PIN dq[181]
    DIRECTION OUTPUT ;
    USE SIGNAL ;
    PORT
      LAYER M4 ;
        RECT  34.368 33.792 34.56 33.816 ;
    END
  END dq[181]
  PIN dq[182]
    DIRECTION OUTPUT ;
    USE SIGNAL ;
    PORT
      LAYER M4 ;
        RECT  34.368 33.936 34.56 33.96 ;
    END
  END dq[182]
  PIN dq[183]
    DIRECTION OUTPUT ;
    USE SIGNAL ;
    PORT
      LAYER M4 ;
        RECT  34.368 34.08 34.56 34.104 ;
    END
  END dq[183]
  PIN dq[184]
    DIRECTION OUTPUT ;
    USE SIGNAL ;
    PORT
      LAYER M4 ;
        RECT  34.368 34.272 34.56 34.296 ;
    END
  END dq[184]
  PIN dq[185]
    DIRECTION OUTPUT ;
    USE SIGNAL ;
    PORT
      LAYER M4 ;
        RECT  34.368 34.416 34.56 34.44 ;
    END
  END dq[185]
  PIN dq[186]
    DIRECTION OUTPUT ;
    USE SIGNAL ;
    PORT
      LAYER M4 ;
        RECT  34.368 34.608 34.56 34.632 ;
    END
  END dq[186]
  PIN dq[187]
    DIRECTION OUTPUT ;
    USE SIGNAL ;
    PORT
      LAYER M4 ;
        RECT  34.368 34.752 34.56 34.776 ;
    END
  END dq[187]
  PIN dq[188]
    DIRECTION OUTPUT ;
    USE SIGNAL ;
    PORT
      LAYER M4 ;
        RECT  34.368 34.896 34.56 34.92 ;
    END
  END dq[188]
  PIN dq[189]
    DIRECTION OUTPUT ;
    USE SIGNAL ;
    PORT
      LAYER M4 ;
        RECT  34.368 35.088 34.56 35.112 ;
    END
  END dq[189]
  PIN dq[18]
    DIRECTION OUTPUT ;
    USE SIGNAL ;
    PORT
      LAYER M4 ;
        RECT  34.368 7.344 34.56 7.368 ;
    END
  END dq[18]
  PIN dq[190]
    DIRECTION OUTPUT ;
    USE SIGNAL ;
    PORT
      LAYER M4 ;
        RECT  34.368 35.232 34.56 35.256 ;
    END
  END dq[190]
  PIN dq[191]
    DIRECTION OUTPUT ;
    USE SIGNAL ;
    PORT
      LAYER M4 ;
        RECT  34.368 35.376 34.56 35.4 ;
    END
  END dq[191]
  PIN dq[192]
    DIRECTION OUTPUT ;
    USE SIGNAL ;
    PORT
      LAYER M4 ;
        RECT  34.368 35.568 34.56 35.592 ;
    END
  END dq[192]
  PIN dq[193]
    DIRECTION OUTPUT ;
    USE SIGNAL ;
    PORT
      LAYER M4 ;
        RECT  34.368 35.712 34.56 35.736 ;
    END
  END dq[193]
  PIN dq[194]
    DIRECTION OUTPUT ;
    USE SIGNAL ;
    PORT
      LAYER M4 ;
        RECT  34.368 35.904 34.56 35.928 ;
    END
  END dq[194]
  PIN dq[195]
    DIRECTION OUTPUT ;
    USE SIGNAL ;
    PORT
      LAYER M4 ;
        RECT  34.368 36.048 34.56 36.072 ;
    END
  END dq[195]
  PIN dq[196]
    DIRECTION OUTPUT ;
    USE SIGNAL ;
    PORT
      LAYER M4 ;
        RECT  34.368 36.192 34.56 36.216 ;
    END
  END dq[196]
  PIN dq[197]
    DIRECTION OUTPUT ;
    USE SIGNAL ;
    PORT
      LAYER M4 ;
        RECT  34.368 36.384 34.56 36.408 ;
    END
  END dq[197]
  PIN dq[198]
    DIRECTION OUTPUT ;
    USE SIGNAL ;
    PORT
      LAYER M4 ;
        RECT  34.368 36.528 34.56 36.552 ;
    END
  END dq[198]
  PIN dq[199]
    DIRECTION OUTPUT ;
    USE SIGNAL ;
    PORT
      LAYER M4 ;
        RECT  34.368 36.672 34.56 36.696 ;
    END
  END dq[199]
  PIN dq[19]
    DIRECTION OUTPUT ;
    USE SIGNAL ;
    PORT
      LAYER M4 ;
        RECT  34.368 7.488 34.56 7.512 ;
    END
  END dq[19]
  PIN dq[1]
    DIRECTION OUTPUT ;
    USE SIGNAL ;
    PORT
      LAYER M4 ;
        RECT  34.368 4.56 34.56 4.584 ;
    END
  END dq[1]
  PIN dq[200]
    DIRECTION OUTPUT ;
    USE SIGNAL ;
    PORT
      LAYER M4 ;
        RECT  34.368 36.864 34.56 36.888 ;
    END
  END dq[200]
  PIN dq[201]
    DIRECTION OUTPUT ;
    USE SIGNAL ;
    PORT
      LAYER M4 ;
        RECT  34.368 37.008 34.56 37.032 ;
    END
  END dq[201]
  PIN dq[202]
    DIRECTION OUTPUT ;
    USE SIGNAL ;
    PORT
      LAYER M4 ;
        RECT  34.368 37.2 34.56 37.224 ;
    END
  END dq[202]
  PIN dq[203]
    DIRECTION OUTPUT ;
    USE SIGNAL ;
    PORT
      LAYER M4 ;
        RECT  34.368 37.344 34.56 37.368 ;
    END
  END dq[203]
  PIN dq[204]
    DIRECTION OUTPUT ;
    USE SIGNAL ;
    PORT
      LAYER M4 ;
        RECT  34.368 37.488 34.56 37.512 ;
    END
  END dq[204]
  PIN dq[205]
    DIRECTION OUTPUT ;
    USE SIGNAL ;
    PORT
      LAYER M4 ;
        RECT  34.368 37.68 34.56 37.704 ;
    END
  END dq[205]
  PIN dq[206]
    DIRECTION OUTPUT ;
    USE SIGNAL ;
    PORT
      LAYER M4 ;
        RECT  34.368 37.824 34.56 37.848 ;
    END
  END dq[206]
  PIN dq[207]
    DIRECTION OUTPUT ;
    USE SIGNAL ;
    PORT
      LAYER M4 ;
        RECT  34.368 37.968 34.56 37.992 ;
    END
  END dq[207]
  PIN dq[208]
    DIRECTION OUTPUT ;
    USE SIGNAL ;
    PORT
      LAYER M4 ;
        RECT  34.368 38.16 34.56 38.184 ;
    END
  END dq[208]
  PIN dq[209]
    DIRECTION OUTPUT ;
    USE SIGNAL ;
    PORT
      LAYER M4 ;
        RECT  34.368 38.304 34.56 38.328 ;
    END
  END dq[209]
  PIN dq[20]
    DIRECTION OUTPUT ;
    USE SIGNAL ;
    PORT
      LAYER M4 ;
        RECT  34.368 7.68 34.56 7.704 ;
    END
  END dq[20]
  PIN dq[210]
    DIRECTION OUTPUT ;
    USE SIGNAL ;
    PORT
      LAYER M4 ;
        RECT  34.368 38.496 34.56 38.52 ;
    END
  END dq[210]
  PIN dq[211]
    DIRECTION OUTPUT ;
    USE SIGNAL ;
    PORT
      LAYER M4 ;
        RECT  34.368 38.64 34.56 38.664 ;
    END
  END dq[211]
  PIN dq[212]
    DIRECTION OUTPUT ;
    USE SIGNAL ;
    PORT
      LAYER M4 ;
        RECT  34.368 38.784 34.56 38.808 ;
    END
  END dq[212]
  PIN dq[213]
    DIRECTION OUTPUT ;
    USE SIGNAL ;
    PORT
      LAYER M4 ;
        RECT  34.368 38.976 34.56 39 ;
    END
  END dq[213]
  PIN dq[214]
    DIRECTION OUTPUT ;
    USE SIGNAL ;
    PORT
      LAYER M4 ;
        RECT  34.368 39.12 34.56 39.144 ;
    END
  END dq[214]
  PIN dq[215]
    DIRECTION OUTPUT ;
    USE SIGNAL ;
    PORT
      LAYER M4 ;
        RECT  34.368 39.312 34.56 39.336 ;
    END
  END dq[215]
  PIN dq[216]
    DIRECTION OUTPUT ;
    USE SIGNAL ;
    PORT
      LAYER M4 ;
        RECT  34.368 39.456 34.56 39.48 ;
    END
  END dq[216]
  PIN dq[217]
    DIRECTION OUTPUT ;
    USE SIGNAL ;
    PORT
      LAYER M4 ;
        RECT  34.368 39.6 34.56 39.624 ;
    END
  END dq[217]
  PIN dq[218]
    DIRECTION OUTPUT ;
    USE SIGNAL ;
    PORT
      LAYER M4 ;
        RECT  34.368 39.792 34.56 39.816 ;
    END
  END dq[218]
  PIN dq[219]
    DIRECTION OUTPUT ;
    USE SIGNAL ;
    PORT
      LAYER M4 ;
        RECT  34.368 39.936 34.56 39.96 ;
    END
  END dq[219]
  PIN dq[21]
    DIRECTION OUTPUT ;
    USE SIGNAL ;
    PORT
      LAYER M4 ;
        RECT  34.368 7.824 34.56 7.848 ;
    END
  END dq[21]
  PIN dq[220]
    DIRECTION OUTPUT ;
    USE SIGNAL ;
    PORT
      LAYER M4 ;
        RECT  34.368 40.08 34.56 40.104 ;
    END
  END dq[220]
  PIN dq[221]
    DIRECTION OUTPUT ;
    USE SIGNAL ;
    PORT
      LAYER M4 ;
        RECT  34.368 40.272 34.56 40.296 ;
    END
  END dq[221]
  PIN dq[222]
    DIRECTION OUTPUT ;
    USE SIGNAL ;
    PORT
      LAYER M4 ;
        RECT  34.368 40.416 34.56 40.44 ;
    END
  END dq[222]
  PIN dq[223]
    DIRECTION OUTPUT ;
    USE SIGNAL ;
    PORT
      LAYER M4 ;
        RECT  34.368 40.608 34.56 40.632 ;
    END
  END dq[223]
  PIN dq[224]
    DIRECTION OUTPUT ;
    USE SIGNAL ;
    PORT
      LAYER M4 ;
        RECT  34.368 40.752 34.56 40.776 ;
    END
  END dq[224]
  PIN dq[225]
    DIRECTION OUTPUT ;
    USE SIGNAL ;
    PORT
      LAYER M4 ;
        RECT  34.368 40.896 34.56 40.92 ;
    END
  END dq[225]
  PIN dq[226]
    DIRECTION OUTPUT ;
    USE SIGNAL ;
    PORT
      LAYER M4 ;
        RECT  34.368 41.088 34.56 41.112 ;
    END
  END dq[226]
  PIN dq[227]
    DIRECTION OUTPUT ;
    USE SIGNAL ;
    PORT
      LAYER M4 ;
        RECT  34.368 41.232 34.56 41.256 ;
    END
  END dq[227]
  PIN dq[228]
    DIRECTION OUTPUT ;
    USE SIGNAL ;
    PORT
      LAYER M4 ;
        RECT  34.368 41.376 34.56 41.4 ;
    END
  END dq[228]
  PIN dq[229]
    DIRECTION OUTPUT ;
    USE SIGNAL ;
    PORT
      LAYER M4 ;
        RECT  34.368 41.568 34.56 41.592 ;
    END
  END dq[229]
  PIN dq[22]
    DIRECTION OUTPUT ;
    USE SIGNAL ;
    PORT
      LAYER M4 ;
        RECT  34.368 7.968 34.56 7.992 ;
    END
  END dq[22]
  PIN dq[230]
    DIRECTION OUTPUT ;
    USE SIGNAL ;
    PORT
      LAYER M4 ;
        RECT  34.368 41.712 34.56 41.736 ;
    END
  END dq[230]
  PIN dq[231]
    DIRECTION OUTPUT ;
    USE SIGNAL ;
    PORT
      LAYER M4 ;
        RECT  34.368 41.904 34.56 41.928 ;
    END
  END dq[231]
  PIN dq[232]
    DIRECTION OUTPUT ;
    USE SIGNAL ;
    PORT
      LAYER M4 ;
        RECT  34.368 42.048 34.56 42.072 ;
    END
  END dq[232]
  PIN dq[233]
    DIRECTION OUTPUT ;
    USE SIGNAL ;
    PORT
      LAYER M4 ;
        RECT  34.368 42.192 34.56 42.216 ;
    END
  END dq[233]
  PIN dq[234]
    DIRECTION OUTPUT ;
    USE SIGNAL ;
    PORT
      LAYER M4 ;
        RECT  34.368 42.384 34.56 42.408 ;
    END
  END dq[234]
  PIN dq[235]
    DIRECTION OUTPUT ;
    USE SIGNAL ;
    PORT
      LAYER M4 ;
        RECT  34.368 42.528 34.56 42.552 ;
    END
  END dq[235]
  PIN dq[236]
    DIRECTION OUTPUT ;
    USE SIGNAL ;
    PORT
      LAYER M4 ;
        RECT  34.368 42.672 34.56 42.696 ;
    END
  END dq[236]
  PIN dq[237]
    DIRECTION OUTPUT ;
    USE SIGNAL ;
    PORT
      LAYER M4 ;
        RECT  34.368 42.864 34.56 42.888 ;
    END
  END dq[237]
  PIN dq[238]
    DIRECTION OUTPUT ;
    USE SIGNAL ;
    PORT
      LAYER M4 ;
        RECT  34.368 43.008 34.56 43.032 ;
    END
  END dq[238]
  PIN dq[239]
    DIRECTION OUTPUT ;
    USE SIGNAL ;
    PORT
      LAYER M4 ;
        RECT  34.368 43.2 34.56 43.224 ;
    END
  END dq[239]
  PIN dq[23]
    DIRECTION OUTPUT ;
    USE SIGNAL ;
    PORT
      LAYER M4 ;
        RECT  34.368 8.16 34.56 8.184 ;
    END
  END dq[23]
  PIN dq[240]
    DIRECTION OUTPUT ;
    USE SIGNAL ;
    PORT
      LAYER M4 ;
        RECT  34.368 43.344 34.56 43.368 ;
    END
  END dq[240]
  PIN dq[241]
    DIRECTION OUTPUT ;
    USE SIGNAL ;
    PORT
      LAYER M4 ;
        RECT  34.368 43.488 34.56 43.512 ;
    END
  END dq[241]
  PIN dq[242]
    DIRECTION OUTPUT ;
    USE SIGNAL ;
    PORT
      LAYER M4 ;
        RECT  34.368 43.68 34.56 43.704 ;
    END
  END dq[242]
  PIN dq[243]
    DIRECTION OUTPUT ;
    USE SIGNAL ;
    PORT
      LAYER M4 ;
        RECT  34.368 43.824 34.56 43.848 ;
    END
  END dq[243]
  PIN dq[244]
    DIRECTION OUTPUT ;
    USE SIGNAL ;
    PORT
      LAYER M4 ;
        RECT  34.368 44.016 34.56 44.04 ;
    END
  END dq[244]
  PIN dq[245]
    DIRECTION OUTPUT ;
    USE SIGNAL ;
    PORT
      LAYER M4 ;
        RECT  34.368 44.16 34.56 44.184 ;
    END
  END dq[245]
  PIN dq[246]
    DIRECTION OUTPUT ;
    USE SIGNAL ;
    PORT
      LAYER M4 ;
        RECT  34.368 44.304 34.56 44.328 ;
    END
  END dq[246]
  PIN dq[247]
    DIRECTION OUTPUT ;
    USE SIGNAL ;
    PORT
      LAYER M4 ;
        RECT  34.368 44.496 34.56 44.52 ;
    END
  END dq[247]
  PIN dq[248]
    DIRECTION OUTPUT ;
    USE SIGNAL ;
    PORT
      LAYER M4 ;
        RECT  34.368 44.64 34.56 44.664 ;
    END
  END dq[248]
  PIN dq[249]
    DIRECTION OUTPUT ;
    USE SIGNAL ;
    PORT
      LAYER M4 ;
        RECT  34.368 44.784 34.56 44.808 ;
    END
  END dq[249]
  PIN dq[24]
    DIRECTION OUTPUT ;
    USE SIGNAL ;
    PORT
      LAYER M4 ;
        RECT  34.368 8.304 34.56 8.328 ;
    END
  END dq[24]
  PIN dq[250]
    DIRECTION OUTPUT ;
    USE SIGNAL ;
    PORT
      LAYER M4 ;
        RECT  34.368 44.976 34.56 45 ;
    END
  END dq[250]
  PIN dq[251]
    DIRECTION OUTPUT ;
    USE SIGNAL ;
    PORT
      LAYER M4 ;
        RECT  34.368 45.12 34.56 45.144 ;
    END
  END dq[251]
  PIN dq[252]
    DIRECTION OUTPUT ;
    USE SIGNAL ;
    PORT
      LAYER M4 ;
        RECT  34.368 45.312 34.56 45.336 ;
    END
  END dq[252]
  PIN dq[253]
    DIRECTION OUTPUT ;
    USE SIGNAL ;
    PORT
      LAYER M4 ;
        RECT  34.368 45.456 34.56 45.48 ;
    END
  END dq[253]
  PIN dq[254]
    DIRECTION OUTPUT ;
    USE SIGNAL ;
    PORT
      LAYER M4 ;
        RECT  34.368 45.6 34.56 45.624 ;
    END
  END dq[254]
  PIN dq[255]
    DIRECTION OUTPUT ;
    USE SIGNAL ;
    PORT
      LAYER M4 ;
        RECT  34.368 45.792 34.56 45.816 ;
    END
  END dq[255]
  PIN dq[256]
    DIRECTION OUTPUT ;
    USE SIGNAL ;
    PORT
      LAYER M4 ;
        RECT  34.368 45.936 34.56 45.96 ;
    END
  END dq[256]
  PIN dq[257]
    DIRECTION OUTPUT ;
    USE SIGNAL ;
    PORT
      LAYER M4 ;
        RECT  34.368 46.08 34.56 46.104 ;
    END
  END dq[257]
  PIN dq[258]
    DIRECTION OUTPUT ;
    USE SIGNAL ;
    PORT
      LAYER M4 ;
        RECT  34.368 46.272 34.56 46.296 ;
    END
  END dq[258]
  PIN dq[259]
    DIRECTION OUTPUT ;
    USE SIGNAL ;
    PORT
      LAYER M4 ;
        RECT  34.368 46.416 34.56 46.44 ;
    END
  END dq[259]
  PIN dq[25]
    DIRECTION OUTPUT ;
    USE SIGNAL ;
    PORT
      LAYER M4 ;
        RECT  34.368 8.448 34.56 8.472 ;
    END
  END dq[25]
  PIN dq[260]
    DIRECTION OUTPUT ;
    USE SIGNAL ;
    PORT
      LAYER M4 ;
        RECT  34.368 46.608 34.56 46.632 ;
    END
  END dq[260]
  PIN dq[261]
    DIRECTION OUTPUT ;
    USE SIGNAL ;
    PORT
      LAYER M4 ;
        RECT  34.368 46.752 34.56 46.776 ;
    END
  END dq[261]
  PIN dq[262]
    DIRECTION OUTPUT ;
    USE SIGNAL ;
    PORT
      LAYER M4 ;
        RECT  34.368 46.896 34.56 46.92 ;
    END
  END dq[262]
  PIN dq[263]
    DIRECTION OUTPUT ;
    USE SIGNAL ;
    PORT
      LAYER M4 ;
        RECT  34.368 47.088 34.56 47.112 ;
    END
  END dq[263]
  PIN dq[264]
    DIRECTION OUTPUT ;
    USE SIGNAL ;
    PORT
      LAYER M4 ;
        RECT  34.368 47.232 34.56 47.256 ;
    END
  END dq[264]
  PIN dq[265]
    DIRECTION OUTPUT ;
    USE SIGNAL ;
    PORT
      LAYER M4 ;
        RECT  34.368 47.376 34.56 47.4 ;
    END
  END dq[265]
  PIN dq[266]
    DIRECTION OUTPUT ;
    USE SIGNAL ;
    PORT
      LAYER M4 ;
        RECT  34.368 47.568 34.56 47.592 ;
    END
  END dq[266]
  PIN dq[267]
    DIRECTION OUTPUT ;
    USE SIGNAL ;
    PORT
      LAYER M4 ;
        RECT  34.368 47.712 34.56 47.736 ;
    END
  END dq[267]
  PIN dq[268]
    DIRECTION OUTPUT ;
    USE SIGNAL ;
    PORT
      LAYER M4 ;
        RECT  34.368 47.904 34.56 47.928 ;
    END
  END dq[268]
  PIN dq[269]
    DIRECTION OUTPUT ;
    USE SIGNAL ;
    PORT
      LAYER M4 ;
        RECT  34.368 48.048 34.56 48.072 ;
    END
  END dq[269]
  PIN dq[26]
    DIRECTION OUTPUT ;
    USE SIGNAL ;
    PORT
      LAYER M4 ;
        RECT  34.368 8.64 34.56 8.664 ;
    END
  END dq[26]
  PIN dq[270]
    DIRECTION OUTPUT ;
    USE SIGNAL ;
    PORT
      LAYER M4 ;
        RECT  34.368 48.192 34.56 48.216 ;
    END
  END dq[270]
  PIN dq[271]
    DIRECTION OUTPUT ;
    USE SIGNAL ;
    PORT
      LAYER M4 ;
        RECT  34.368 48.384 34.56 48.408 ;
    END
  END dq[271]
  PIN dq[272]
    DIRECTION OUTPUT ;
    USE SIGNAL ;
    PORT
      LAYER M4 ;
        RECT  34.368 48.528 34.56 48.552 ;
    END
  END dq[272]
  PIN dq[273]
    DIRECTION OUTPUT ;
    USE SIGNAL ;
    PORT
      LAYER M4 ;
        RECT  34.368 48.72 34.56 48.744 ;
    END
  END dq[273]
  PIN dq[274]
    DIRECTION OUTPUT ;
    USE SIGNAL ;
    PORT
      LAYER M4 ;
        RECT  34.368 48.864 34.56 48.888 ;
    END
  END dq[274]
  PIN dq[275]
    DIRECTION OUTPUT ;
    USE SIGNAL ;
    PORT
      LAYER M4 ;
        RECT  34.368 49.008 34.56 49.032 ;
    END
  END dq[275]
  PIN dq[276]
    DIRECTION OUTPUT ;
    USE SIGNAL ;
    PORT
      LAYER M4 ;
        RECT  34.368 49.2 34.56 49.224 ;
    END
  END dq[276]
  PIN dq[277]
    DIRECTION OUTPUT ;
    USE SIGNAL ;
    PORT
      LAYER M4 ;
        RECT  34.368 49.344 34.56 49.368 ;
    END
  END dq[277]
  PIN dq[278]
    DIRECTION OUTPUT ;
    USE SIGNAL ;
    PORT
      LAYER M4 ;
        RECT  34.368 49.488 34.56 49.512 ;
    END
  END dq[278]
  PIN dq[279]
    DIRECTION OUTPUT ;
    USE SIGNAL ;
    PORT
      LAYER M4 ;
        RECT  34.368 49.68 34.56 49.704 ;
    END
  END dq[279]
  PIN dq[27]
    DIRECTION OUTPUT ;
    USE SIGNAL ;
    PORT
      LAYER M4 ;
        RECT  34.368 8.784 34.56 8.808 ;
    END
  END dq[27]
  PIN dq[280]
    DIRECTION OUTPUT ;
    USE SIGNAL ;
    PORT
      LAYER M4 ;
        RECT  34.368 49.824 34.56 49.848 ;
    END
  END dq[280]
  PIN dq[281]
    DIRECTION OUTPUT ;
    USE SIGNAL ;
    PORT
      LAYER M4 ;
        RECT  34.368 50.016 34.56 50.04 ;
    END
  END dq[281]
  PIN dq[282]
    DIRECTION OUTPUT ;
    USE SIGNAL ;
    PORT
      LAYER M4 ;
        RECT  34.368 50.16 34.56 50.184 ;
    END
  END dq[282]
  PIN dq[283]
    DIRECTION OUTPUT ;
    USE SIGNAL ;
    PORT
      LAYER M4 ;
        RECT  34.368 50.304 34.56 50.328 ;
    END
  END dq[283]
  PIN dq[284]
    DIRECTION OUTPUT ;
    USE SIGNAL ;
    PORT
      LAYER M4 ;
        RECT  34.368 50.496 34.56 50.52 ;
    END
  END dq[284]
  PIN dq[285]
    DIRECTION OUTPUT ;
    USE SIGNAL ;
    PORT
      LAYER M4 ;
        RECT  34.368 50.64 34.56 50.664 ;
    END
  END dq[285]
  PIN dq[286]
    DIRECTION OUTPUT ;
    USE SIGNAL ;
    PORT
      LAYER M4 ;
        RECT  34.368 50.784 34.56 50.808 ;
    END
  END dq[286]
  PIN dq[287]
    DIRECTION OUTPUT ;
    USE SIGNAL ;
    PORT
      LAYER M4 ;
        RECT  34.368 50.976 34.56 51 ;
    END
  END dq[287]
  PIN dq[288]
    DIRECTION OUTPUT ;
    USE SIGNAL ;
    PORT
      LAYER M4 ;
        RECT  34.368 51.12 34.56 51.144 ;
    END
  END dq[288]
  PIN dq[289]
    DIRECTION OUTPUT ;
    USE SIGNAL ;
    PORT
      LAYER M4 ;
        RECT  34.368 51.312 34.56 51.336 ;
    END
  END dq[289]
  PIN dq[28]
    DIRECTION OUTPUT ;
    USE SIGNAL ;
    PORT
      LAYER M4 ;
        RECT  34.368 8.976 34.56 9 ;
    END
  END dq[28]
  PIN dq[290]
    DIRECTION OUTPUT ;
    USE SIGNAL ;
    PORT
      LAYER M4 ;
        RECT  34.368 51.456 34.56 51.48 ;
    END
  END dq[290]
  PIN dq[291]
    DIRECTION OUTPUT ;
    USE SIGNAL ;
    PORT
      LAYER M4 ;
        RECT  34.368 51.6 34.56 51.624 ;
    END
  END dq[291]
  PIN dq[292]
    DIRECTION OUTPUT ;
    USE SIGNAL ;
    PORT
      LAYER M4 ;
        RECT  34.368 51.792 34.56 51.816 ;
    END
  END dq[292]
  PIN dq[293]
    DIRECTION OUTPUT ;
    USE SIGNAL ;
    PORT
      LAYER M4 ;
        RECT  34.368 51.936 34.56 51.96 ;
    END
  END dq[293]
  PIN dq[294]
    DIRECTION OUTPUT ;
    USE SIGNAL ;
    PORT
      LAYER M4 ;
        RECT  34.368 52.08 34.56 52.104 ;
    END
  END dq[294]
  PIN dq[295]
    DIRECTION OUTPUT ;
    USE SIGNAL ;
    PORT
      LAYER M4 ;
        RECT  34.368 52.272 34.56 52.296 ;
    END
  END dq[295]
  PIN dq[296]
    DIRECTION OUTPUT ;
    USE SIGNAL ;
    PORT
      LAYER M4 ;
        RECT  34.368 52.416 34.56 52.44 ;
    END
  END dq[296]
  PIN dq[297]
    DIRECTION OUTPUT ;
    USE SIGNAL ;
    PORT
      LAYER M4 ;
        RECT  34.368 52.608 34.56 52.632 ;
    END
  END dq[297]
  PIN dq[298]
    DIRECTION OUTPUT ;
    USE SIGNAL ;
    PORT
      LAYER M4 ;
        RECT  34.368 52.752 34.56 52.776 ;
    END
  END dq[298]
  PIN dq[299]
    DIRECTION OUTPUT ;
    USE SIGNAL ;
    PORT
      LAYER M4 ;
        RECT  34.368 52.896 34.56 52.92 ;
    END
  END dq[299]
  PIN dq[29]
    DIRECTION OUTPUT ;
    USE SIGNAL ;
    PORT
      LAYER M4 ;
        RECT  34.368 9.12 34.56 9.144 ;
    END
  END dq[29]
  PIN dq[2]
    DIRECTION OUTPUT ;
    USE SIGNAL ;
    PORT
      LAYER M4 ;
        RECT  34.368 4.752 34.56 4.776 ;
    END
  END dq[2]
  PIN dq[300]
    DIRECTION OUTPUT ;
    USE SIGNAL ;
    PORT
      LAYER M4 ;
        RECT  34.368 53.088 34.56 53.112 ;
    END
  END dq[300]
  PIN dq[301]
    DIRECTION OUTPUT ;
    USE SIGNAL ;
    PORT
      LAYER M4 ;
        RECT  34.368 53.232 34.56 53.256 ;
    END
  END dq[301]
  PIN dq[302]
    DIRECTION OUTPUT ;
    USE SIGNAL ;
    PORT
      LAYER M4 ;
        RECT  34.368 53.424 34.56 53.448 ;
    END
  END dq[302]
  PIN dq[303]
    DIRECTION OUTPUT ;
    USE SIGNAL ;
    PORT
      LAYER M4 ;
        RECT  34.368 53.568 34.56 53.592 ;
    END
  END dq[303]
  PIN dq[304]
    DIRECTION OUTPUT ;
    USE SIGNAL ;
    PORT
      LAYER M4 ;
        RECT  34.368 53.712 34.56 53.736 ;
    END
  END dq[304]
  PIN dq[305]
    DIRECTION OUTPUT ;
    USE SIGNAL ;
    PORT
      LAYER M4 ;
        RECT  34.368 53.904 34.56 53.928 ;
    END
  END dq[305]
  PIN dq[306]
    DIRECTION OUTPUT ;
    USE SIGNAL ;
    PORT
      LAYER M4 ;
        RECT  34.368 54.048 34.56 54.072 ;
    END
  END dq[306]
  PIN dq[307]
    DIRECTION OUTPUT ;
    USE SIGNAL ;
    PORT
      LAYER M4 ;
        RECT  34.368 54.192 34.56 54.216 ;
    END
  END dq[307]
  PIN dq[308]
    DIRECTION OUTPUT ;
    USE SIGNAL ;
    PORT
      LAYER M4 ;
        RECT  34.368 54.384 34.56 54.408 ;
    END
  END dq[308]
  PIN dq[309]
    DIRECTION OUTPUT ;
    USE SIGNAL ;
    PORT
      LAYER M4 ;
        RECT  34.368 54.528 34.56 54.552 ;
    END
  END dq[309]
  PIN dq[30]
    DIRECTION OUTPUT ;
    USE SIGNAL ;
    PORT
      LAYER M4 ;
        RECT  34.368 9.264 34.56 9.288 ;
    END
  END dq[30]
  PIN dq[310]
    DIRECTION OUTPUT ;
    USE SIGNAL ;
    PORT
      LAYER M4 ;
        RECT  34.368 54.72 34.56 54.744 ;
    END
  END dq[310]
  PIN dq[311]
    DIRECTION OUTPUT ;
    USE SIGNAL ;
    PORT
      LAYER M4 ;
        RECT  34.368 54.864 34.56 54.888 ;
    END
  END dq[311]
  PIN dq[312]
    DIRECTION OUTPUT ;
    USE SIGNAL ;
    PORT
      LAYER M4 ;
        RECT  34.368 55.008 34.56 55.032 ;
    END
  END dq[312]
  PIN dq[313]
    DIRECTION OUTPUT ;
    USE SIGNAL ;
    PORT
      LAYER M4 ;
        RECT  34.368 55.2 34.56 55.224 ;
    END
  END dq[313]
  PIN dq[314]
    DIRECTION OUTPUT ;
    USE SIGNAL ;
    PORT
      LAYER M4 ;
        RECT  34.368 55.344 34.56 55.368 ;
    END
  END dq[314]
  PIN dq[315]
    DIRECTION OUTPUT ;
    USE SIGNAL ;
    PORT
      LAYER M4 ;
        RECT  34.368 55.488 34.56 55.512 ;
    END
  END dq[315]
  PIN dq[316]
    DIRECTION OUTPUT ;
    USE SIGNAL ;
    PORT
      LAYER M4 ;
        RECT  34.368 55.68 34.56 55.704 ;
    END
  END dq[316]
  PIN dq[317]
    DIRECTION OUTPUT ;
    USE SIGNAL ;
    PORT
      LAYER M4 ;
        RECT  34.368 55.824 34.56 55.848 ;
    END
  END dq[317]
  PIN dq[318]
    DIRECTION OUTPUT ;
    USE SIGNAL ;
    PORT
      LAYER M4 ;
        RECT  34.368 56.016 34.56 56.04 ;
    END
  END dq[318]
  PIN dq[319]
    DIRECTION OUTPUT ;
    USE SIGNAL ;
    PORT
      LAYER M4 ;
        RECT  34.368 56.16 34.56 56.184 ;
    END
  END dq[319]
  PIN dq[31]
    DIRECTION OUTPUT ;
    USE SIGNAL ;
    PORT
      LAYER M4 ;
        RECT  34.368 9.456 34.56 9.48 ;
    END
  END dq[31]
  PIN dq[320]
    DIRECTION OUTPUT ;
    USE SIGNAL ;
    PORT
      LAYER M4 ;
        RECT  34.368 56.304 34.56 56.328 ;
    END
  END dq[320]
  PIN dq[321]
    DIRECTION OUTPUT ;
    USE SIGNAL ;
    PORT
      LAYER M4 ;
        RECT  34.368 56.496 34.56 56.52 ;
    END
  END dq[321]
  PIN dq[322]
    DIRECTION OUTPUT ;
    USE SIGNAL ;
    PORT
      LAYER M4 ;
        RECT  34.368 56.64 34.56 56.664 ;
    END
  END dq[322]
  PIN dq[323]
    DIRECTION OUTPUT ;
    USE SIGNAL ;
    PORT
      LAYER M4 ;
        RECT  34.368 56.832 34.56 56.856 ;
    END
  END dq[323]
  PIN dq[324]
    DIRECTION OUTPUT ;
    USE SIGNAL ;
    PORT
      LAYER M4 ;
        RECT  34.368 56.976 34.56 57 ;
    END
  END dq[324]
  PIN dq[325]
    DIRECTION OUTPUT ;
    USE SIGNAL ;
    PORT
      LAYER M4 ;
        RECT  34.368 57.12 34.56 57.144 ;
    END
  END dq[325]
  PIN dq[326]
    DIRECTION OUTPUT ;
    USE SIGNAL ;
    PORT
      LAYER M4 ;
        RECT  34.368 57.312 34.56 57.336 ;
    END
  END dq[326]
  PIN dq[327]
    DIRECTION OUTPUT ;
    USE SIGNAL ;
    PORT
      LAYER M4 ;
        RECT  34.368 57.456 34.56 57.48 ;
    END
  END dq[327]
  PIN dq[328]
    DIRECTION OUTPUT ;
    USE SIGNAL ;
    PORT
      LAYER M4 ;
        RECT  34.368 57.6 34.56 57.624 ;
    END
  END dq[328]
  PIN dq[329]
    DIRECTION OUTPUT ;
    USE SIGNAL ;
    PORT
      LAYER M4 ;
        RECT  34.368 57.792 34.56 57.816 ;
    END
  END dq[329]
  PIN dq[32]
    DIRECTION OUTPUT ;
    USE SIGNAL ;
    PORT
      LAYER M4 ;
        RECT  34.368 9.6 34.56 9.624 ;
    END
  END dq[32]
  PIN dq[330]
    DIRECTION OUTPUT ;
    USE SIGNAL ;
    PORT
      LAYER M4 ;
        RECT  34.368 57.936 34.56 57.96 ;
    END
  END dq[330]
  PIN dq[331]
    DIRECTION OUTPUT ;
    USE SIGNAL ;
    PORT
      LAYER M4 ;
        RECT  34.368 58.128 34.56 58.152 ;
    END
  END dq[331]
  PIN dq[332]
    DIRECTION OUTPUT ;
    USE SIGNAL ;
    PORT
      LAYER M4 ;
        RECT  34.368 58.272 34.56 58.296 ;
    END
  END dq[332]
  PIN dq[333]
    DIRECTION OUTPUT ;
    USE SIGNAL ;
    PORT
      LAYER M4 ;
        RECT  34.368 58.416 34.56 58.44 ;
    END
  END dq[333]
  PIN dq[334]
    DIRECTION OUTPUT ;
    USE SIGNAL ;
    PORT
      LAYER M4 ;
        RECT  34.368 58.608 34.56 58.632 ;
    END
  END dq[334]
  PIN dq[335]
    DIRECTION OUTPUT ;
    USE SIGNAL ;
    PORT
      LAYER M4 ;
        RECT  34.368 58.752 34.56 58.776 ;
    END
  END dq[335]
  PIN dq[336]
    DIRECTION OUTPUT ;
    USE SIGNAL ;
    PORT
      LAYER M4 ;
        RECT  34.368 58.896 34.56 58.92 ;
    END
  END dq[336]
  PIN dq[337]
    DIRECTION OUTPUT ;
    USE SIGNAL ;
    PORT
      LAYER M4 ;
        RECT  34.368 59.088 34.56 59.112 ;
    END
  END dq[337]
  PIN dq[338]
    DIRECTION OUTPUT ;
    USE SIGNAL ;
    PORT
      LAYER M4 ;
        RECT  34.368 59.232 34.56 59.256 ;
    END
  END dq[338]
  PIN dq[339]
    DIRECTION OUTPUT ;
    USE SIGNAL ;
    PORT
      LAYER M4 ;
        RECT  34.368 59.424 34.56 59.448 ;
    END
  END dq[339]
  PIN dq[33]
    DIRECTION OUTPUT ;
    USE SIGNAL ;
    PORT
      LAYER M4 ;
        RECT  34.368 9.744 34.56 9.768 ;
    END
  END dq[33]
  PIN dq[340]
    DIRECTION OUTPUT ;
    USE SIGNAL ;
    PORT
      LAYER M4 ;
        RECT  34.368 59.568 34.56 59.592 ;
    END
  END dq[340]
  PIN dq[341]
    DIRECTION OUTPUT ;
    USE SIGNAL ;
    PORT
      LAYER M4 ;
        RECT  34.368 59.712 34.56 59.736 ;
    END
  END dq[341]
  PIN dq[342]
    DIRECTION OUTPUT ;
    USE SIGNAL ;
    PORT
      LAYER M4 ;
        RECT  34.368 59.904 34.56 59.928 ;
    END
  END dq[342]
  PIN dq[343]
    DIRECTION OUTPUT ;
    USE SIGNAL ;
    PORT
      LAYER M4 ;
        RECT  34.368 60.048 34.56 60.072 ;
    END
  END dq[343]
  PIN dq[344]
    DIRECTION OUTPUT ;
    USE SIGNAL ;
    PORT
      LAYER M4 ;
        RECT  34.368 60.192 34.56 60.216 ;
    END
  END dq[344]
  PIN dq[345]
    DIRECTION OUTPUT ;
    USE SIGNAL ;
    PORT
      LAYER M4 ;
        RECT  34.368 60.384 34.56 60.408 ;
    END
  END dq[345]
  PIN dq[346]
    DIRECTION OUTPUT ;
    USE SIGNAL ;
    PORT
      LAYER M4 ;
        RECT  34.368 60.528 34.56 60.552 ;
    END
  END dq[346]
  PIN dq[347]
    DIRECTION OUTPUT ;
    USE SIGNAL ;
    PORT
      LAYER M4 ;
        RECT  34.368 60.72 34.56 60.744 ;
    END
  END dq[347]
  PIN dq[348]
    DIRECTION OUTPUT ;
    USE SIGNAL ;
    PORT
      LAYER M4 ;
        RECT  34.368 60.864 34.56 60.888 ;
    END
  END dq[348]
  PIN dq[349]
    DIRECTION OUTPUT ;
    USE SIGNAL ;
    PORT
      LAYER M4 ;
        RECT  34.368 61.008 34.56 61.032 ;
    END
  END dq[349]
  PIN dq[34]
    DIRECTION OUTPUT ;
    USE SIGNAL ;
    PORT
      LAYER M4 ;
        RECT  34.368 9.936 34.56 9.96 ;
    END
  END dq[34]
  PIN dq[350]
    DIRECTION OUTPUT ;
    USE SIGNAL ;
    PORT
      LAYER M4 ;
        RECT  34.368 61.2 34.56 61.224 ;
    END
  END dq[350]
  PIN dq[351]
    DIRECTION OUTPUT ;
    USE SIGNAL ;
    PORT
      LAYER M4 ;
        RECT  34.368 61.344 34.56 61.368 ;
    END
  END dq[351]
  PIN dq[352]
    DIRECTION OUTPUT ;
    USE SIGNAL ;
    PORT
      LAYER M4 ;
        RECT  34.368 61.536 34.56 61.56 ;
    END
  END dq[352]
  PIN dq[353]
    DIRECTION OUTPUT ;
    USE SIGNAL ;
    PORT
      LAYER M4 ;
        RECT  34.368 61.68 34.56 61.704 ;
    END
  END dq[353]
  PIN dq[354]
    DIRECTION OUTPUT ;
    USE SIGNAL ;
    PORT
      LAYER M4 ;
        RECT  34.368 61.824 34.56 61.848 ;
    END
  END dq[354]
  PIN dq[355]
    DIRECTION OUTPUT ;
    USE SIGNAL ;
    PORT
      LAYER M4 ;
        RECT  34.368 62.016 34.56 62.04 ;
    END
  END dq[355]
  PIN dq[356]
    DIRECTION OUTPUT ;
    USE SIGNAL ;
    PORT
      LAYER M4 ;
        RECT  34.368 62.16 34.56 62.184 ;
    END
  END dq[356]
  PIN dq[357]
    DIRECTION OUTPUT ;
    USE SIGNAL ;
    PORT
      LAYER M4 ;
        RECT  34.368 62.304 34.56 62.328 ;
    END
  END dq[357]
  PIN dq[358]
    DIRECTION OUTPUT ;
    USE SIGNAL ;
    PORT
      LAYER M4 ;
        RECT  34.368 62.496 34.56 62.52 ;
    END
  END dq[358]
  PIN dq[359]
    DIRECTION OUTPUT ;
    USE SIGNAL ;
    PORT
      LAYER M4 ;
        RECT  34.368 62.64 34.56 62.664 ;
    END
  END dq[359]
  PIN dq[35]
    DIRECTION OUTPUT ;
    USE SIGNAL ;
    PORT
      LAYER M4 ;
        RECT  34.368 10.08 34.56 10.104 ;
    END
  END dq[35]
  PIN dq[360]
    DIRECTION OUTPUT ;
    USE SIGNAL ;
    PORT
      LAYER M4 ;
        RECT  34.368 62.832 34.56 62.856 ;
    END
  END dq[360]
  PIN dq[361]
    DIRECTION OUTPUT ;
    USE SIGNAL ;
    PORT
      LAYER M4 ;
        RECT  34.368 62.976 34.56 63 ;
    END
  END dq[361]
  PIN dq[362]
    DIRECTION OUTPUT ;
    USE SIGNAL ;
    PORT
      LAYER M4 ;
        RECT  34.368 63.12 34.56 63.144 ;
    END
  END dq[362]
  PIN dq[363]
    DIRECTION OUTPUT ;
    USE SIGNAL ;
    PORT
      LAYER M4 ;
        RECT  34.368 63.312 34.56 63.336 ;
    END
  END dq[363]
  PIN dq[364]
    DIRECTION OUTPUT ;
    USE SIGNAL ;
    PORT
      LAYER M4 ;
        RECT  34.368 63.456 34.56 63.48 ;
    END
  END dq[364]
  PIN dq[365]
    DIRECTION OUTPUT ;
    USE SIGNAL ;
    PORT
      LAYER M4 ;
        RECT  34.368 63.6 34.56 63.624 ;
    END
  END dq[365]
  PIN dq[366]
    DIRECTION OUTPUT ;
    USE SIGNAL ;
    PORT
      LAYER M4 ;
        RECT  34.368 63.792 34.56 63.816 ;
    END
  END dq[366]
  PIN dq[367]
    DIRECTION OUTPUT ;
    USE SIGNAL ;
    PORT
      LAYER M4 ;
        RECT  34.368 63.936 34.56 63.96 ;
    END
  END dq[367]
  PIN dq[368]
    DIRECTION OUTPUT ;
    USE SIGNAL ;
    PORT
      LAYER M4 ;
        RECT  34.368 64.128 34.56 64.152 ;
    END
  END dq[368]
  PIN dq[369]
    DIRECTION OUTPUT ;
    USE SIGNAL ;
    PORT
      LAYER M4 ;
        RECT  34.368 64.272 34.56 64.296 ;
    END
  END dq[369]
  PIN dq[36]
    DIRECTION OUTPUT ;
    USE SIGNAL ;
    PORT
      LAYER M4 ;
        RECT  34.368 10.272 34.56 10.296 ;
    END
  END dq[36]
  PIN dq[370]
    DIRECTION OUTPUT ;
    USE SIGNAL ;
    PORT
      LAYER M4 ;
        RECT  34.368 64.416 34.56 64.44 ;
    END
  END dq[370]
  PIN dq[371]
    DIRECTION OUTPUT ;
    USE SIGNAL ;
    PORT
      LAYER M4 ;
        RECT  34.368 64.608 34.56 64.632 ;
    END
  END dq[371]
  PIN dq[372]
    DIRECTION OUTPUT ;
    USE SIGNAL ;
    PORT
      LAYER M4 ;
        RECT  34.368 64.752 34.56 64.776 ;
    END
  END dq[372]
  PIN dq[373]
    DIRECTION OUTPUT ;
    USE SIGNAL ;
    PORT
      LAYER M4 ;
        RECT  34.368 64.896 34.56 64.92 ;
    END
  END dq[373]
  PIN dq[374]
    DIRECTION OUTPUT ;
    USE SIGNAL ;
    PORT
      LAYER M4 ;
        RECT  34.368 65.088 34.56 65.112 ;
    END
  END dq[374]
  PIN dq[375]
    DIRECTION OUTPUT ;
    USE SIGNAL ;
    PORT
      LAYER M4 ;
        RECT  34.368 65.232 34.56 65.256 ;
    END
  END dq[375]
  PIN dq[376]
    DIRECTION OUTPUT ;
    USE SIGNAL ;
    PORT
      LAYER M4 ;
        RECT  34.368 65.424 34.56 65.448 ;
    END
  END dq[376]
  PIN dq[377]
    DIRECTION OUTPUT ;
    USE SIGNAL ;
    PORT
      LAYER M4 ;
        RECT  34.368 65.568 34.56 65.592 ;
    END
  END dq[377]
  PIN dq[378]
    DIRECTION OUTPUT ;
    USE SIGNAL ;
    PORT
      LAYER M4 ;
        RECT  34.368 65.712 34.56 65.736 ;
    END
  END dq[378]
  PIN dq[379]
    DIRECTION OUTPUT ;
    USE SIGNAL ;
    PORT
      LAYER M4 ;
        RECT  34.368 65.904 34.56 65.928 ;
    END
  END dq[379]
  PIN dq[37]
    DIRECTION OUTPUT ;
    USE SIGNAL ;
    PORT
      LAYER M4 ;
        RECT  34.368 10.416 34.56 10.44 ;
    END
  END dq[37]
  PIN dq[380]
    DIRECTION OUTPUT ;
    USE SIGNAL ;
    PORT
      LAYER M4 ;
        RECT  34.368 66.048 34.56 66.072 ;
    END
  END dq[380]
  PIN dq[381]
    DIRECTION OUTPUT ;
    USE SIGNAL ;
    PORT
      LAYER M4 ;
        RECT  34.368 66.24 34.56 66.264 ;
    END
  END dq[381]
  PIN dq[382]
    DIRECTION OUTPUT ;
    USE SIGNAL ;
    PORT
      LAYER M4 ;
        RECT  34.368 66.384 34.56 66.408 ;
    END
  END dq[382]
  PIN dq[383]
    DIRECTION OUTPUT ;
    USE SIGNAL ;
    PORT
      LAYER M4 ;
        RECT  34.368 66.528 34.56 66.552 ;
    END
  END dq[383]
  PIN dq[384]
    DIRECTION OUTPUT ;
    USE SIGNAL ;
    PORT
      LAYER M4 ;
        RECT  34.368 66.72 34.56 66.744 ;
    END
  END dq[384]
  PIN dq[385]
    DIRECTION OUTPUT ;
    USE SIGNAL ;
    PORT
      LAYER M4 ;
        RECT  34.368 66.864 34.56 66.888 ;
    END
  END dq[385]
  PIN dq[386]
    DIRECTION OUTPUT ;
    USE SIGNAL ;
    PORT
      LAYER M4 ;
        RECT  34.368 67.008 34.56 67.032 ;
    END
  END dq[386]
  PIN dq[387]
    DIRECTION OUTPUT ;
    USE SIGNAL ;
    PORT
      LAYER M4 ;
        RECT  34.368 67.2 34.56 67.224 ;
    END
  END dq[387]
  PIN dq[388]
    DIRECTION OUTPUT ;
    USE SIGNAL ;
    PORT
      LAYER M4 ;
        RECT  34.368 67.344 34.56 67.368 ;
    END
  END dq[388]
  PIN dq[389]
    DIRECTION OUTPUT ;
    USE SIGNAL ;
    PORT
      LAYER M4 ;
        RECT  34.368 67.536 34.56 67.56 ;
    END
  END dq[389]
  PIN dq[38]
    DIRECTION OUTPUT ;
    USE SIGNAL ;
    PORT
      LAYER M4 ;
        RECT  34.368 10.56 34.56 10.584 ;
    END
  END dq[38]
  PIN dq[390]
    DIRECTION OUTPUT ;
    USE SIGNAL ;
    PORT
      LAYER M4 ;
        RECT  34.368 67.68 34.56 67.704 ;
    END
  END dq[390]
  PIN dq[391]
    DIRECTION OUTPUT ;
    USE SIGNAL ;
    PORT
      LAYER M4 ;
        RECT  34.368 67.824 34.56 67.848 ;
    END
  END dq[391]
  PIN dq[392]
    DIRECTION OUTPUT ;
    USE SIGNAL ;
    PORT
      LAYER M4 ;
        RECT  34.368 68.016 34.56 68.04 ;
    END
  END dq[392]
  PIN dq[393]
    DIRECTION OUTPUT ;
    USE SIGNAL ;
    PORT
      LAYER M4 ;
        RECT  34.368 68.16 34.56 68.184 ;
    END
  END dq[393]
  PIN dq[394]
    DIRECTION OUTPUT ;
    USE SIGNAL ;
    PORT
      LAYER M4 ;
        RECT  34.368 68.304 34.56 68.328 ;
    END
  END dq[394]
  PIN dq[395]
    DIRECTION OUTPUT ;
    USE SIGNAL ;
    PORT
      LAYER M4 ;
        RECT  34.368 68.496 34.56 68.52 ;
    END
  END dq[395]
  PIN dq[396]
    DIRECTION OUTPUT ;
    USE SIGNAL ;
    PORT
      LAYER M4 ;
        RECT  34.368 68.64 34.56 68.664 ;
    END
  END dq[396]
  PIN dq[397]
    DIRECTION OUTPUT ;
    USE SIGNAL ;
    PORT
      LAYER M4 ;
        RECT  34.368 68.832 34.56 68.856 ;
    END
  END dq[397]
  PIN dq[398]
    DIRECTION OUTPUT ;
    USE SIGNAL ;
    PORT
      LAYER M4 ;
        RECT  34.368 68.976 34.56 69 ;
    END
  END dq[398]
  PIN dq[399]
    DIRECTION OUTPUT ;
    USE SIGNAL ;
    PORT
      LAYER M4 ;
        RECT  34.368 69.12 34.56 69.144 ;
    END
  END dq[399]
  PIN dq[39]
    DIRECTION OUTPUT ;
    USE SIGNAL ;
    PORT
      LAYER M4 ;
        RECT  34.368 10.752 34.56 10.776 ;
    END
  END dq[39]
  PIN dq[3]
    DIRECTION OUTPUT ;
    USE SIGNAL ;
    PORT
      LAYER M4 ;
        RECT  34.368 4.896 34.56 4.92 ;
    END
  END dq[3]
  PIN dq[400]
    DIRECTION OUTPUT ;
    USE SIGNAL ;
    PORT
      LAYER M4 ;
        RECT  34.368 69.312 34.56 69.336 ;
    END
  END dq[400]
  PIN dq[401]
    DIRECTION OUTPUT ;
    USE SIGNAL ;
    PORT
      LAYER M4 ;
        RECT  34.368 69.456 34.56 69.48 ;
    END
  END dq[401]
  PIN dq[402]
    DIRECTION OUTPUT ;
    USE SIGNAL ;
    PORT
      LAYER M4 ;
        RECT  34.368 69.6 34.56 69.624 ;
    END
  END dq[402]
  PIN dq[403]
    DIRECTION OUTPUT ;
    USE SIGNAL ;
    PORT
      LAYER M4 ;
        RECT  34.368 69.792 34.56 69.816 ;
    END
  END dq[403]
  PIN dq[404]
    DIRECTION OUTPUT ;
    USE SIGNAL ;
    PORT
      LAYER M4 ;
        RECT  34.368 69.936 34.56 69.96 ;
    END
  END dq[404]
  PIN dq[405]
    DIRECTION OUTPUT ;
    USE SIGNAL ;
    PORT
      LAYER M4 ;
        RECT  34.368 70.128 34.56 70.152 ;
    END
  END dq[405]
  PIN dq[406]
    DIRECTION OUTPUT ;
    USE SIGNAL ;
    PORT
      LAYER M4 ;
        RECT  34.368 70.272 34.56 70.296 ;
    END
  END dq[406]
  PIN dq[407]
    DIRECTION OUTPUT ;
    USE SIGNAL ;
    PORT
      LAYER M4 ;
        RECT  34.368 70.416 34.56 70.44 ;
    END
  END dq[407]
  PIN dq[408]
    DIRECTION OUTPUT ;
    USE SIGNAL ;
    PORT
      LAYER M4 ;
        RECT  34.368 70.608 34.56 70.632 ;
    END
  END dq[408]
  PIN dq[409]
    DIRECTION OUTPUT ;
    USE SIGNAL ;
    PORT
      LAYER M4 ;
        RECT  34.368 70.752 34.56 70.776 ;
    END
  END dq[409]
  PIN dq[40]
    DIRECTION OUTPUT ;
    USE SIGNAL ;
    PORT
      LAYER M4 ;
        RECT  34.368 10.896 34.56 10.92 ;
    END
  END dq[40]
  PIN dq[410]
    DIRECTION OUTPUT ;
    USE SIGNAL ;
    PORT
      LAYER M4 ;
        RECT  34.368 70.944 34.56 70.968 ;
    END
  END dq[410]
  PIN dq[411]
    DIRECTION OUTPUT ;
    USE SIGNAL ;
    PORT
      LAYER M4 ;
        RECT  34.368 71.088 34.56 71.112 ;
    END
  END dq[411]
  PIN dq[412]
    DIRECTION OUTPUT ;
    USE SIGNAL ;
    PORT
      LAYER M4 ;
        RECT  34.368 71.232 34.56 71.256 ;
    END
  END dq[412]
  PIN dq[413]
    DIRECTION OUTPUT ;
    USE SIGNAL ;
    PORT
      LAYER M4 ;
        RECT  34.368 71.424 34.56 71.448 ;
    END
  END dq[413]
  PIN dq[414]
    DIRECTION OUTPUT ;
    USE SIGNAL ;
    PORT
      LAYER M4 ;
        RECT  34.368 71.568 34.56 71.592 ;
    END
  END dq[414]
  PIN dq[415]
    DIRECTION OUTPUT ;
    USE SIGNAL ;
    PORT
      LAYER M4 ;
        RECT  34.368 71.712 34.56 71.736 ;
    END
  END dq[415]
  PIN dq[416]
    DIRECTION OUTPUT ;
    USE SIGNAL ;
    PORT
      LAYER M4 ;
        RECT  34.368 71.904 34.56 71.928 ;
    END
  END dq[416]
  PIN dq[417]
    DIRECTION OUTPUT ;
    USE SIGNAL ;
    PORT
      LAYER M4 ;
        RECT  34.368 72.048 34.56 72.072 ;
    END
  END dq[417]
  PIN dq[418]
    DIRECTION OUTPUT ;
    USE SIGNAL ;
    PORT
      LAYER M4 ;
        RECT  34.368 72.24 34.56 72.264 ;
    END
  END dq[418]
  PIN dq[419]
    DIRECTION OUTPUT ;
    USE SIGNAL ;
    PORT
      LAYER M4 ;
        RECT  34.368 72.384 34.56 72.408 ;
    END
  END dq[419]
  PIN dq[41]
    DIRECTION OUTPUT ;
    USE SIGNAL ;
    PORT
      LAYER M4 ;
        RECT  34.368 11.04 34.56 11.064 ;
    END
  END dq[41]
  PIN dq[420]
    DIRECTION OUTPUT ;
    USE SIGNAL ;
    PORT
      LAYER M4 ;
        RECT  34.368 72.528 34.56 72.552 ;
    END
  END dq[420]
  PIN dq[421]
    DIRECTION OUTPUT ;
    USE SIGNAL ;
    PORT
      LAYER M4 ;
        RECT  34.368 72.72 34.56 72.744 ;
    END
  END dq[421]
  PIN dq[422]
    DIRECTION OUTPUT ;
    USE SIGNAL ;
    PORT
      LAYER M4 ;
        RECT  34.368 72.864 34.56 72.888 ;
    END
  END dq[422]
  PIN dq[423]
    DIRECTION OUTPUT ;
    USE SIGNAL ;
    PORT
      LAYER M4 ;
        RECT  34.368 73.008 34.56 73.032 ;
    END
  END dq[423]
  PIN dq[424]
    DIRECTION OUTPUT ;
    USE SIGNAL ;
    PORT
      LAYER M4 ;
        RECT  34.368 73.2 34.56 73.224 ;
    END
  END dq[424]
  PIN dq[425]
    DIRECTION OUTPUT ;
    USE SIGNAL ;
    PORT
      LAYER M4 ;
        RECT  34.368 73.344 34.56 73.368 ;
    END
  END dq[425]
  PIN dq[426]
    DIRECTION OUTPUT ;
    USE SIGNAL ;
    PORT
      LAYER M4 ;
        RECT  34.368 73.536 34.56 73.56 ;
    END
  END dq[426]
  PIN dq[427]
    DIRECTION OUTPUT ;
    USE SIGNAL ;
    PORT
      LAYER M4 ;
        RECT  34.368 73.68 34.56 73.704 ;
    END
  END dq[427]
  PIN dq[428]
    DIRECTION OUTPUT ;
    USE SIGNAL ;
    PORT
      LAYER M4 ;
        RECT  34.368 73.824 34.56 73.848 ;
    END
  END dq[428]
  PIN dq[429]
    DIRECTION OUTPUT ;
    USE SIGNAL ;
    PORT
      LAYER M4 ;
        RECT  34.368 74.016 34.56 74.04 ;
    END
  END dq[429]
  PIN dq[42]
    DIRECTION OUTPUT ;
    USE SIGNAL ;
    PORT
      LAYER M4 ;
        RECT  34.368 11.232 34.56 11.256 ;
    END
  END dq[42]
  PIN dq[430]
    DIRECTION OUTPUT ;
    USE SIGNAL ;
    PORT
      LAYER M4 ;
        RECT  34.368 74.16 34.56 74.184 ;
    END
  END dq[430]
  PIN dq[431]
    DIRECTION OUTPUT ;
    USE SIGNAL ;
    PORT
      LAYER M4 ;
        RECT  34.368 74.304 34.56 74.328 ;
    END
  END dq[431]
  PIN dq[432]
    DIRECTION OUTPUT ;
    USE SIGNAL ;
    PORT
      LAYER M4 ;
        RECT  34.368 74.496 34.56 74.52 ;
    END
  END dq[432]
  PIN dq[433]
    DIRECTION OUTPUT ;
    USE SIGNAL ;
    PORT
      LAYER M4 ;
        RECT  34.368 74.64 34.56 74.664 ;
    END
  END dq[433]
  PIN dq[434]
    DIRECTION OUTPUT ;
    USE SIGNAL ;
    PORT
      LAYER M4 ;
        RECT  34.368 74.832 34.56 74.856 ;
    END
  END dq[434]
  PIN dq[435]
    DIRECTION OUTPUT ;
    USE SIGNAL ;
    PORT
      LAYER M4 ;
        RECT  34.368 74.976 34.56 75 ;
    END
  END dq[435]
  PIN dq[436]
    DIRECTION OUTPUT ;
    USE SIGNAL ;
    PORT
      LAYER M4 ;
        RECT  34.368 75.12 34.56 75.144 ;
    END
  END dq[436]
  PIN dq[437]
    DIRECTION OUTPUT ;
    USE SIGNAL ;
    PORT
      LAYER M4 ;
        RECT  34.368 75.312 34.56 75.336 ;
    END
  END dq[437]
  PIN dq[438]
    DIRECTION OUTPUT ;
    USE SIGNAL ;
    PORT
      LAYER M4 ;
        RECT  34.368 75.456 34.56 75.48 ;
    END
  END dq[438]
  PIN dq[439]
    DIRECTION OUTPUT ;
    USE SIGNAL ;
    PORT
      LAYER M4 ;
        RECT  34.368 75.648 34.56 75.672 ;
    END
  END dq[439]
  PIN dq[43]
    DIRECTION OUTPUT ;
    USE SIGNAL ;
    PORT
      LAYER M4 ;
        RECT  34.368 11.376 34.56 11.4 ;
    END
  END dq[43]
  PIN dq[440]
    DIRECTION OUTPUT ;
    USE SIGNAL ;
    PORT
      LAYER M4 ;
        RECT  34.368 75.792 34.56 75.816 ;
    END
  END dq[440]
  PIN dq[441]
    DIRECTION OUTPUT ;
    USE SIGNAL ;
    PORT
      LAYER M4 ;
        RECT  34.368 75.936 34.56 75.96 ;
    END
  END dq[441]
  PIN dq[442]
    DIRECTION OUTPUT ;
    USE SIGNAL ;
    PORT
      LAYER M4 ;
        RECT  34.368 76.128 34.56 76.152 ;
    END
  END dq[442]
  PIN dq[443]
    DIRECTION OUTPUT ;
    USE SIGNAL ;
    PORT
      LAYER M4 ;
        RECT  34.368 76.272 34.56 76.296 ;
    END
  END dq[443]
  PIN dq[444]
    DIRECTION OUTPUT ;
    USE SIGNAL ;
    PORT
      LAYER M4 ;
        RECT  34.368 76.416 34.56 76.44 ;
    END
  END dq[444]
  PIN dq[445]
    DIRECTION OUTPUT ;
    USE SIGNAL ;
    PORT
      LAYER M4 ;
        RECT  34.368 76.608 34.56 76.632 ;
    END
  END dq[445]
  PIN dq[446]
    DIRECTION OUTPUT ;
    USE SIGNAL ;
    PORT
      LAYER M4 ;
        RECT  34.368 76.752 34.56 76.776 ;
    END
  END dq[446]
  PIN dq[447]
    DIRECTION OUTPUT ;
    USE SIGNAL ;
    PORT
      LAYER M4 ;
        RECT  34.368 76.944 34.56 76.968 ;
    END
  END dq[447]
  PIN dq[448]
    DIRECTION OUTPUT ;
    USE SIGNAL ;
    PORT
      LAYER M4 ;
        RECT  34.368 77.088 34.56 77.112 ;
    END
  END dq[448]
  PIN dq[449]
    DIRECTION OUTPUT ;
    USE SIGNAL ;
    PORT
      LAYER M4 ;
        RECT  34.368 77.232 34.56 77.256 ;
    END
  END dq[449]
  PIN dq[44]
    DIRECTION OUTPUT ;
    USE SIGNAL ;
    PORT
      LAYER M4 ;
        RECT  34.368 11.568 34.56 11.592 ;
    END
  END dq[44]
  PIN dq[450]
    DIRECTION OUTPUT ;
    USE SIGNAL ;
    PORT
      LAYER M4 ;
        RECT  34.368 77.424 34.56 77.448 ;
    END
  END dq[450]
  PIN dq[451]
    DIRECTION OUTPUT ;
    USE SIGNAL ;
    PORT
      LAYER M4 ;
        RECT  34.368 77.568 34.56 77.592 ;
    END
  END dq[451]
  PIN dq[452]
    DIRECTION OUTPUT ;
    USE SIGNAL ;
    PORT
      LAYER M4 ;
        RECT  34.368 77.712 34.56 77.736 ;
    END
  END dq[452]
  PIN dq[453]
    DIRECTION OUTPUT ;
    USE SIGNAL ;
    PORT
      LAYER M4 ;
        RECT  34.368 77.904 34.56 77.928 ;
    END
  END dq[453]
  PIN dq[454]
    DIRECTION OUTPUT ;
    USE SIGNAL ;
    PORT
      LAYER M4 ;
        RECT  34.368 78.048 34.56 78.072 ;
    END
  END dq[454]
  PIN dq[455]
    DIRECTION OUTPUT ;
    USE SIGNAL ;
    PORT
      LAYER M4 ;
        RECT  34.368 78.24 34.56 78.264 ;
    END
  END dq[455]
  PIN dq[456]
    DIRECTION OUTPUT ;
    USE SIGNAL ;
    PORT
      LAYER M4 ;
        RECT  34.368 78.384 34.56 78.408 ;
    END
  END dq[456]
  PIN dq[457]
    DIRECTION OUTPUT ;
    USE SIGNAL ;
    PORT
      LAYER M4 ;
        RECT  34.368 78.528 34.56 78.552 ;
    END
  END dq[457]
  PIN dq[458]
    DIRECTION OUTPUT ;
    USE SIGNAL ;
    PORT
      LAYER M4 ;
        RECT  34.368 78.72 34.56 78.744 ;
    END
  END dq[458]
  PIN dq[459]
    DIRECTION OUTPUT ;
    USE SIGNAL ;
    PORT
      LAYER M4 ;
        RECT  34.368 78.864 34.56 78.888 ;
    END
  END dq[459]
  PIN dq[45]
    DIRECTION OUTPUT ;
    USE SIGNAL ;
    PORT
      LAYER M4 ;
        RECT  34.368 11.712 34.56 11.736 ;
    END
  END dq[45]
  PIN dq[460]
    DIRECTION OUTPUT ;
    USE SIGNAL ;
    PORT
      LAYER M4 ;
        RECT  34.368 79.008 34.56 79.032 ;
    END
  END dq[460]
  PIN dq[461]
    DIRECTION OUTPUT ;
    USE SIGNAL ;
    PORT
      LAYER M4 ;
        RECT  34.368 79.2 34.56 79.224 ;
    END
  END dq[461]
  PIN dq[462]
    DIRECTION OUTPUT ;
    USE SIGNAL ;
    PORT
      LAYER M4 ;
        RECT  34.368 79.344 34.56 79.368 ;
    END
  END dq[462]
  PIN dq[463]
    DIRECTION OUTPUT ;
    USE SIGNAL ;
    PORT
      LAYER M4 ;
        RECT  34.368 79.536 34.56 79.56 ;
    END
  END dq[463]
  PIN dq[464]
    DIRECTION OUTPUT ;
    USE SIGNAL ;
    PORT
      LAYER M4 ;
        RECT  34.368 79.68 34.56 79.704 ;
    END
  END dq[464]
  PIN dq[465]
    DIRECTION OUTPUT ;
    USE SIGNAL ;
    PORT
      LAYER M4 ;
        RECT  34.368 79.824 34.56 79.848 ;
    END
  END dq[465]
  PIN dq[466]
    DIRECTION OUTPUT ;
    USE SIGNAL ;
    PORT
      LAYER M4 ;
        RECT  34.368 80.016 34.56 80.04 ;
    END
  END dq[466]
  PIN dq[467]
    DIRECTION OUTPUT ;
    USE SIGNAL ;
    PORT
      LAYER M4 ;
        RECT  34.368 80.16 34.56 80.184 ;
    END
  END dq[467]
  PIN dq[468]
    DIRECTION OUTPUT ;
    USE SIGNAL ;
    PORT
      LAYER M4 ;
        RECT  34.368 80.352 34.56 80.376 ;
    END
  END dq[468]
  PIN dq[469]
    DIRECTION OUTPUT ;
    USE SIGNAL ;
    PORT
      LAYER M4 ;
        RECT  34.368 80.496 34.56 80.52 ;
    END
  END dq[469]
  PIN dq[46]
    DIRECTION OUTPUT ;
    USE SIGNAL ;
    PORT
      LAYER M4 ;
        RECT  34.368 11.856 34.56 11.88 ;
    END
  END dq[46]
  PIN dq[470]
    DIRECTION OUTPUT ;
    USE SIGNAL ;
    PORT
      LAYER M4 ;
        RECT  34.368 80.64 34.56 80.664 ;
    END
  END dq[470]
  PIN dq[471]
    DIRECTION OUTPUT ;
    USE SIGNAL ;
    PORT
      LAYER M4 ;
        RECT  34.368 80.832 34.56 80.856 ;
    END
  END dq[471]
  PIN dq[472]
    DIRECTION OUTPUT ;
    USE SIGNAL ;
    PORT
      LAYER M4 ;
        RECT  34.368 80.976 34.56 81 ;
    END
  END dq[472]
  PIN dq[473]
    DIRECTION OUTPUT ;
    USE SIGNAL ;
    PORT
      LAYER M4 ;
        RECT  34.368 81.12 34.56 81.144 ;
    END
  END dq[473]
  PIN dq[474]
    DIRECTION OUTPUT ;
    USE SIGNAL ;
    PORT
      LAYER M4 ;
        RECT  34.368 81.312 34.56 81.336 ;
    END
  END dq[474]
  PIN dq[475]
    DIRECTION OUTPUT ;
    USE SIGNAL ;
    PORT
      LAYER M4 ;
        RECT  34.368 81.456 34.56 81.48 ;
    END
  END dq[475]
  PIN dq[476]
    DIRECTION OUTPUT ;
    USE SIGNAL ;
    PORT
      LAYER M4 ;
        RECT  34.368 81.648 34.56 81.672 ;
    END
  END dq[476]
  PIN dq[477]
    DIRECTION OUTPUT ;
    USE SIGNAL ;
    PORT
      LAYER M4 ;
        RECT  34.368 81.792 34.56 81.816 ;
    END
  END dq[477]
  PIN dq[478]
    DIRECTION OUTPUT ;
    USE SIGNAL ;
    PORT
      LAYER M4 ;
        RECT  34.368 81.936 34.56 81.96 ;
    END
  END dq[478]
  PIN dq[479]
    DIRECTION OUTPUT ;
    USE SIGNAL ;
    PORT
      LAYER M4 ;
        RECT  34.368 82.128 34.56 82.152 ;
    END
  END dq[479]
  PIN dq[47]
    DIRECTION OUTPUT ;
    USE SIGNAL ;
    PORT
      LAYER M4 ;
        RECT  34.368 12.048 34.56 12.072 ;
    END
  END dq[47]
  PIN dq[480]
    DIRECTION OUTPUT ;
    USE SIGNAL ;
    PORT
      LAYER M4 ;
        RECT  34.368 82.272 34.56 82.296 ;
    END
  END dq[480]
  PIN dq[481]
    DIRECTION OUTPUT ;
    USE SIGNAL ;
    PORT
      LAYER M4 ;
        RECT  34.368 82.416 34.56 82.44 ;
    END
  END dq[481]
  PIN dq[482]
    DIRECTION OUTPUT ;
    USE SIGNAL ;
    PORT
      LAYER M4 ;
        RECT  34.368 82.608 34.56 82.632 ;
    END
  END dq[482]
  PIN dq[483]
    DIRECTION OUTPUT ;
    USE SIGNAL ;
    PORT
      LAYER M4 ;
        RECT  34.368 82.752 34.56 82.776 ;
    END
  END dq[483]
  PIN dq[484]
    DIRECTION OUTPUT ;
    USE SIGNAL ;
    PORT
      LAYER M4 ;
        RECT  34.368 82.944 34.56 82.968 ;
    END
  END dq[484]
  PIN dq[485]
    DIRECTION OUTPUT ;
    USE SIGNAL ;
    PORT
      LAYER M4 ;
        RECT  34.368 83.088 34.56 83.112 ;
    END
  END dq[485]
  PIN dq[486]
    DIRECTION OUTPUT ;
    USE SIGNAL ;
    PORT
      LAYER M4 ;
        RECT  34.368 83.232 34.56 83.256 ;
    END
  END dq[486]
  PIN dq[487]
    DIRECTION OUTPUT ;
    USE SIGNAL ;
    PORT
      LAYER M4 ;
        RECT  34.368 83.424 34.56 83.448 ;
    END
  END dq[487]
  PIN dq[488]
    DIRECTION OUTPUT ;
    USE SIGNAL ;
    PORT
      LAYER M4 ;
        RECT  34.368 83.568 34.56 83.592 ;
    END
  END dq[488]
  PIN dq[489]
    DIRECTION OUTPUT ;
    USE SIGNAL ;
    PORT
      LAYER M4 ;
        RECT  34.368 83.712 34.56 83.736 ;
    END
  END dq[489]
  PIN dq[48]
    DIRECTION OUTPUT ;
    USE SIGNAL ;
    PORT
      LAYER M4 ;
        RECT  34.368 12.192 34.56 12.216 ;
    END
  END dq[48]
  PIN dq[490]
    DIRECTION OUTPUT ;
    USE SIGNAL ;
    PORT
      LAYER M4 ;
        RECT  34.368 83.904 34.56 83.928 ;
    END
  END dq[490]
  PIN dq[491]
    DIRECTION OUTPUT ;
    USE SIGNAL ;
    PORT
      LAYER M4 ;
        RECT  34.368 84.048 34.56 84.072 ;
    END
  END dq[491]
  PIN dq[492]
    DIRECTION OUTPUT ;
    USE SIGNAL ;
    PORT
      LAYER M4 ;
        RECT  34.368 84.24 34.56 84.264 ;
    END
  END dq[492]
  PIN dq[493]
    DIRECTION OUTPUT ;
    USE SIGNAL ;
    PORT
      LAYER M4 ;
        RECT  34.368 84.384 34.56 84.408 ;
    END
  END dq[493]
  PIN dq[494]
    DIRECTION OUTPUT ;
    USE SIGNAL ;
    PORT
      LAYER M4 ;
        RECT  34.368 84.528 34.56 84.552 ;
    END
  END dq[494]
  PIN dq[495]
    DIRECTION OUTPUT ;
    USE SIGNAL ;
    PORT
      LAYER M4 ;
        RECT  34.368 84.72 34.56 84.744 ;
    END
  END dq[495]
  PIN dq[496]
    DIRECTION OUTPUT ;
    USE SIGNAL ;
    PORT
      LAYER M4 ;
        RECT  34.368 84.864 34.56 84.888 ;
    END
  END dq[496]
  PIN dq[497]
    DIRECTION OUTPUT ;
    USE SIGNAL ;
    PORT
      LAYER M4 ;
        RECT  34.368 85.056 34.56 85.08 ;
    END
  END dq[497]
  PIN dq[498]
    DIRECTION OUTPUT ;
    USE SIGNAL ;
    PORT
      LAYER M4 ;
        RECT  34.368 85.2 34.56 85.224 ;
    END
  END dq[498]
  PIN dq[499]
    DIRECTION OUTPUT ;
    USE SIGNAL ;
    PORT
      LAYER M4 ;
        RECT  34.368 85.344 34.56 85.368 ;
    END
  END dq[499]
  PIN dq[49]
    DIRECTION OUTPUT ;
    USE SIGNAL ;
    PORT
      LAYER M4 ;
        RECT  34.368 12.384 34.56 12.408 ;
    END
  END dq[49]
  PIN dq[4]
    DIRECTION OUTPUT ;
    USE SIGNAL ;
    PORT
      LAYER M4 ;
        RECT  34.368 5.04 34.56 5.064 ;
    END
  END dq[4]
  PIN dq[500]
    DIRECTION OUTPUT ;
    USE SIGNAL ;
    PORT
      LAYER M4 ;
        RECT  34.368 85.536 34.56 85.56 ;
    END
  END dq[500]
  PIN dq[501]
    DIRECTION OUTPUT ;
    USE SIGNAL ;
    PORT
      LAYER M4 ;
        RECT  34.368 85.68 34.56 85.704 ;
    END
  END dq[501]
  PIN dq[502]
    DIRECTION OUTPUT ;
    USE SIGNAL ;
    PORT
      LAYER M4 ;
        RECT  34.368 85.824 34.56 85.848 ;
    END
  END dq[502]
  PIN dq[503]
    DIRECTION OUTPUT ;
    USE SIGNAL ;
    PORT
      LAYER M4 ;
        RECT  34.368 86.016 34.56 86.04 ;
    END
  END dq[503]
  PIN dq[504]
    DIRECTION OUTPUT ;
    USE SIGNAL ;
    PORT
      LAYER M4 ;
        RECT  34.368 86.16 34.56 86.184 ;
    END
  END dq[504]
  PIN dq[505]
    DIRECTION OUTPUT ;
    USE SIGNAL ;
    PORT
      LAYER M4 ;
        RECT  34.368 86.352 34.56 86.376 ;
    END
  END dq[505]
  PIN dq[506]
    DIRECTION OUTPUT ;
    USE SIGNAL ;
    PORT
      LAYER M4 ;
        RECT  34.368 86.496 34.56 86.52 ;
    END
  END dq[506]
  PIN dq[507]
    DIRECTION OUTPUT ;
    USE SIGNAL ;
    PORT
      LAYER M4 ;
        RECT  34.368 86.64 34.56 86.664 ;
    END
  END dq[507]
  PIN dq[508]
    DIRECTION OUTPUT ;
    USE SIGNAL ;
    PORT
      LAYER M4 ;
        RECT  34.368 86.832 34.56 86.856 ;
    END
  END dq[508]
  PIN dq[509]
    DIRECTION OUTPUT ;
    USE SIGNAL ;
    PORT
      LAYER M4 ;
        RECT  34.368 86.976 34.56 87 ;
    END
  END dq[509]
  PIN dq[50]
    DIRECTION OUTPUT ;
    USE SIGNAL ;
    PORT
      LAYER M4 ;
        RECT  34.368 12.528 34.56 12.552 ;
    END
  END dq[50]
  PIN dq[510]
    DIRECTION OUTPUT ;
    USE SIGNAL ;
    PORT
      LAYER M4 ;
        RECT  34.368 87.12 34.56 87.144 ;
    END
  END dq[510]
  PIN dq[511]
    DIRECTION OUTPUT ;
    USE SIGNAL ;
    PORT
      LAYER M4 ;
        RECT  34.368 87.312 34.56 87.336 ;
    END
  END dq[511]
  PIN dq[512]
    DIRECTION OUTPUT ;
    USE SIGNAL ;
    PORT
      LAYER M4 ;
        RECT  34.368 87.456 34.56 87.48 ;
    END
  END dq[512]
  PIN dq[513]
    DIRECTION OUTPUT ;
    USE SIGNAL ;
    PORT
      LAYER M4 ;
        RECT  34.368 87.648 34.56 87.672 ;
    END
  END dq[513]
  PIN dq[514]
    DIRECTION OUTPUT ;
    USE SIGNAL ;
    PORT
      LAYER M4 ;
        RECT  34.368 87.792 34.56 87.816 ;
    END
  END dq[514]
  PIN dq[515]
    DIRECTION OUTPUT ;
    USE SIGNAL ;
    PORT
      LAYER M4 ;
        RECT  34.368 87.936 34.56 87.96 ;
    END
  END dq[515]
  PIN dq[516]
    DIRECTION OUTPUT ;
    USE SIGNAL ;
    PORT
      LAYER M4 ;
        RECT  34.368 88.128 34.56 88.152 ;
    END
  END dq[516]
  PIN dq[517]
    DIRECTION OUTPUT ;
    USE SIGNAL ;
    PORT
      LAYER M4 ;
        RECT  34.368 88.272 34.56 88.296 ;
    END
  END dq[517]
  PIN dq[518]
    DIRECTION OUTPUT ;
    USE SIGNAL ;
    PORT
      LAYER M4 ;
        RECT  34.368 88.416 34.56 88.44 ;
    END
  END dq[518]
  PIN dq[519]
    DIRECTION OUTPUT ;
    USE SIGNAL ;
    PORT
      LAYER M4 ;
        RECT  34.368 88.608 34.56 88.632 ;
    END
  END dq[519]
  PIN dq[51]
    DIRECTION OUTPUT ;
    USE SIGNAL ;
    PORT
      LAYER M4 ;
        RECT  34.368 12.672 34.56 12.696 ;
    END
  END dq[51]
  PIN dq[520]
    DIRECTION OUTPUT ;
    USE SIGNAL ;
    PORT
      LAYER M4 ;
        RECT  34.368 88.752 34.56 88.776 ;
    END
  END dq[520]
  PIN dq[521]
    DIRECTION OUTPUT ;
    USE SIGNAL ;
    PORT
      LAYER M4 ;
        RECT  34.368 88.944 34.56 88.968 ;
    END
  END dq[521]
  PIN dq[522]
    DIRECTION OUTPUT ;
    USE SIGNAL ;
    PORT
      LAYER M4 ;
        RECT  34.368 89.088 34.56 89.112 ;
    END
  END dq[522]
  PIN dq[523]
    DIRECTION OUTPUT ;
    USE SIGNAL ;
    PORT
      LAYER M4 ;
        RECT  34.368 89.232 34.56 89.256 ;
    END
  END dq[523]
  PIN dq[524]
    DIRECTION OUTPUT ;
    USE SIGNAL ;
    PORT
      LAYER M4 ;
        RECT  34.368 89.424 34.56 89.448 ;
    END
  END dq[524]
  PIN dq[525]
    DIRECTION OUTPUT ;
    USE SIGNAL ;
    PORT
      LAYER M4 ;
        RECT  34.368 89.568 34.56 89.592 ;
    END
  END dq[525]
  PIN dq[526]
    DIRECTION OUTPUT ;
    USE SIGNAL ;
    PORT
      LAYER M4 ;
        RECT  34.368 89.76 34.56 89.784 ;
    END
  END dq[526]
  PIN dq[527]
    DIRECTION OUTPUT ;
    USE SIGNAL ;
    PORT
      LAYER M4 ;
        RECT  34.368 89.904 34.56 89.928 ;
    END
  END dq[527]
  PIN dq[528]
    DIRECTION OUTPUT ;
    USE SIGNAL ;
    PORT
      LAYER M4 ;
        RECT  34.368 90.048 34.56 90.072 ;
    END
  END dq[528]
  PIN dq[529]
    DIRECTION OUTPUT ;
    USE SIGNAL ;
    PORT
      LAYER M4 ;
        RECT  34.368 90.24 34.56 90.264 ;
    END
  END dq[529]
  PIN dq[52]
    DIRECTION OUTPUT ;
    USE SIGNAL ;
    PORT
      LAYER M4 ;
        RECT  34.368 12.864 34.56 12.888 ;
    END
  END dq[52]
  PIN dq[530]
    DIRECTION OUTPUT ;
    USE SIGNAL ;
    PORT
      LAYER M4 ;
        RECT  34.368 90.384 34.56 90.408 ;
    END
  END dq[530]
  PIN dq[531]
    DIRECTION OUTPUT ;
    USE SIGNAL ;
    PORT
      LAYER M4 ;
        RECT  34.368 90.528 34.56 90.552 ;
    END
  END dq[531]
  PIN dq[532]
    DIRECTION OUTPUT ;
    USE SIGNAL ;
    PORT
      LAYER M4 ;
        RECT  34.368 90.72 34.56 90.744 ;
    END
  END dq[532]
  PIN dq[533]
    DIRECTION OUTPUT ;
    USE SIGNAL ;
    PORT
      LAYER M4 ;
        RECT  34.368 90.864 34.56 90.888 ;
    END
  END dq[533]
  PIN dq[534]
    DIRECTION OUTPUT ;
    USE SIGNAL ;
    PORT
      LAYER M4 ;
        RECT  34.368 91.056 34.56 91.08 ;
    END
  END dq[534]
  PIN dq[535]
    DIRECTION OUTPUT ;
    USE SIGNAL ;
    PORT
      LAYER M4 ;
        RECT  34.368 91.2 34.56 91.224 ;
    END
  END dq[535]
  PIN dq[536]
    DIRECTION OUTPUT ;
    USE SIGNAL ;
    PORT
      LAYER M4 ;
        RECT  34.368 91.344 34.56 91.368 ;
    END
  END dq[536]
  PIN dq[537]
    DIRECTION OUTPUT ;
    USE SIGNAL ;
    PORT
      LAYER M4 ;
        RECT  34.368 91.536 34.56 91.56 ;
    END
  END dq[537]
  PIN dq[538]
    DIRECTION OUTPUT ;
    USE SIGNAL ;
    PORT
      LAYER M4 ;
        RECT  34.368 91.68 34.56 91.704 ;
    END
  END dq[538]
  PIN dq[539]
    DIRECTION OUTPUT ;
    USE SIGNAL ;
    PORT
      LAYER M4 ;
        RECT  34.368 91.824 34.56 91.848 ;
    END
  END dq[539]
  PIN dq[53]
    DIRECTION OUTPUT ;
    USE SIGNAL ;
    PORT
      LAYER M4 ;
        RECT  34.368 13.008 34.56 13.032 ;
    END
  END dq[53]
  PIN dq[540]
    DIRECTION OUTPUT ;
    USE SIGNAL ;
    PORT
      LAYER M4 ;
        RECT  34.368 92.016 34.56 92.04 ;
    END
  END dq[540]
  PIN dq[541]
    DIRECTION OUTPUT ;
    USE SIGNAL ;
    PORT
      LAYER M4 ;
        RECT  34.368 92.16 34.56 92.184 ;
    END
  END dq[541]
  PIN dq[542]
    DIRECTION OUTPUT ;
    USE SIGNAL ;
    PORT
      LAYER M4 ;
        RECT  34.368 92.352 34.56 92.376 ;
    END
  END dq[542]
  PIN dq[543]
    DIRECTION OUTPUT ;
    USE SIGNAL ;
    PORT
      LAYER M4 ;
        RECT  34.368 92.496 34.56 92.52 ;
    END
  END dq[543]
  PIN dq[544]
    DIRECTION OUTPUT ;
    USE SIGNAL ;
    PORT
      LAYER M4 ;
        RECT  34.368 92.64 34.56 92.664 ;
    END
  END dq[544]
  PIN dq[545]
    DIRECTION OUTPUT ;
    USE SIGNAL ;
    PORT
      LAYER M4 ;
        RECT  34.368 92.832 34.56 92.856 ;
    END
  END dq[545]
  PIN dq[546]
    DIRECTION OUTPUT ;
    USE SIGNAL ;
    PORT
      LAYER M4 ;
        RECT  34.368 92.976 34.56 93 ;
    END
  END dq[546]
  PIN dq[547]
    DIRECTION OUTPUT ;
    USE SIGNAL ;
    PORT
      LAYER M4 ;
        RECT  34.368 93.12 34.56 93.144 ;
    END
  END dq[547]
  PIN dq[548]
    DIRECTION OUTPUT ;
    USE SIGNAL ;
    PORT
      LAYER M4 ;
        RECT  34.368 93.312 34.56 93.336 ;
    END
  END dq[548]
  PIN dq[549]
    DIRECTION OUTPUT ;
    USE SIGNAL ;
    PORT
      LAYER M4 ;
        RECT  34.368 93.456 34.56 93.48 ;
    END
  END dq[549]
  PIN dq[54]
    DIRECTION OUTPUT ;
    USE SIGNAL ;
    PORT
      LAYER M4 ;
        RECT  34.368 13.152 34.56 13.176 ;
    END
  END dq[54]
  PIN dq[550]
    DIRECTION OUTPUT ;
    USE SIGNAL ;
    PORT
      LAYER M4 ;
        RECT  34.368 93.648 34.56 93.672 ;
    END
  END dq[550]
  PIN dq[551]
    DIRECTION OUTPUT ;
    USE SIGNAL ;
    PORT
      LAYER M4 ;
        RECT  34.368 93.792 34.56 93.816 ;
    END
  END dq[551]
  PIN dq[552]
    DIRECTION OUTPUT ;
    USE SIGNAL ;
    PORT
      LAYER M4 ;
        RECT  34.368 93.936 34.56 93.96 ;
    END
  END dq[552]
  PIN dq[553]
    DIRECTION OUTPUT ;
    USE SIGNAL ;
    PORT
      LAYER M4 ;
        RECT  34.368 94.128 34.56 94.152 ;
    END
  END dq[553]
  PIN dq[554]
    DIRECTION OUTPUT ;
    USE SIGNAL ;
    PORT
      LAYER M4 ;
        RECT  34.368 94.272 34.56 94.296 ;
    END
  END dq[554]
  PIN dq[555]
    DIRECTION OUTPUT ;
    USE SIGNAL ;
    PORT
      LAYER M4 ;
        RECT  34.368 94.464 34.56 94.488 ;
    END
  END dq[555]
  PIN dq[556]
    DIRECTION OUTPUT ;
    USE SIGNAL ;
    PORT
      LAYER M4 ;
        RECT  34.368 94.608 34.56 94.632 ;
    END
  END dq[556]
  PIN dq[557]
    DIRECTION OUTPUT ;
    USE SIGNAL ;
    PORT
      LAYER M4 ;
        RECT  34.368 94.752 34.56 94.776 ;
    END
  END dq[557]
  PIN dq[558]
    DIRECTION OUTPUT ;
    USE SIGNAL ;
    PORT
      LAYER M4 ;
        RECT  34.368 94.944 34.56 94.968 ;
    END
  END dq[558]
  PIN dq[559]
    DIRECTION OUTPUT ;
    USE SIGNAL ;
    PORT
      LAYER M4 ;
        RECT  34.368 95.088 34.56 95.112 ;
    END
  END dq[559]
  PIN dq[55]
    DIRECTION OUTPUT ;
    USE SIGNAL ;
    PORT
      LAYER M4 ;
        RECT  34.368 13.344 34.56 13.368 ;
    END
  END dq[55]
  PIN dq[560]
    DIRECTION OUTPUT ;
    USE SIGNAL ;
    PORT
      LAYER M4 ;
        RECT  34.368 95.232 34.56 95.256 ;
    END
  END dq[560]
  PIN dq[561]
    DIRECTION OUTPUT ;
    USE SIGNAL ;
    PORT
      LAYER M4 ;
        RECT  34.368 95.424 34.56 95.448 ;
    END
  END dq[561]
  PIN dq[562]
    DIRECTION OUTPUT ;
    USE SIGNAL ;
    PORT
      LAYER M4 ;
        RECT  34.368 95.568 34.56 95.592 ;
    END
  END dq[562]
  PIN dq[563]
    DIRECTION OUTPUT ;
    USE SIGNAL ;
    PORT
      LAYER M4 ;
        RECT  34.368 95.76 34.56 95.784 ;
    END
  END dq[563]
  PIN dq[564]
    DIRECTION OUTPUT ;
    USE SIGNAL ;
    PORT
      LAYER M4 ;
        RECT  34.368 95.904 34.56 95.928 ;
    END
  END dq[564]
  PIN dq[565]
    DIRECTION OUTPUT ;
    USE SIGNAL ;
    PORT
      LAYER M4 ;
        RECT  34.368 96.048 34.56 96.072 ;
    END
  END dq[565]
  PIN dq[566]
    DIRECTION OUTPUT ;
    USE SIGNAL ;
    PORT
      LAYER M4 ;
        RECT  34.368 96.24 34.56 96.264 ;
    END
  END dq[566]
  PIN dq[567]
    DIRECTION OUTPUT ;
    USE SIGNAL ;
    PORT
      LAYER M4 ;
        RECT  34.368 96.384 34.56 96.408 ;
    END
  END dq[567]
  PIN dq[568]
    DIRECTION OUTPUT ;
    USE SIGNAL ;
    PORT
      LAYER M4 ;
        RECT  34.368 96.528 34.56 96.552 ;
    END
  END dq[568]
  PIN dq[569]
    DIRECTION OUTPUT ;
    USE SIGNAL ;
    PORT
      LAYER M4 ;
        RECT  34.368 96.72 34.56 96.744 ;
    END
  END dq[569]
  PIN dq[56]
    DIRECTION OUTPUT ;
    USE SIGNAL ;
    PORT
      LAYER M4 ;
        RECT  34.368 13.488 34.56 13.512 ;
    END
  END dq[56]
  PIN dq[570]
    DIRECTION OUTPUT ;
    USE SIGNAL ;
    PORT
      LAYER M4 ;
        RECT  34.368 96.864 34.56 96.888 ;
    END
  END dq[570]
  PIN dq[571]
    DIRECTION OUTPUT ;
    USE SIGNAL ;
    PORT
      LAYER M4 ;
        RECT  34.368 97.056 34.56 97.08 ;
    END
  END dq[571]
  PIN dq[572]
    DIRECTION OUTPUT ;
    USE SIGNAL ;
    PORT
      LAYER M4 ;
        RECT  34.368 97.2 34.56 97.224 ;
    END
  END dq[572]
  PIN dq[573]
    DIRECTION OUTPUT ;
    USE SIGNAL ;
    PORT
      LAYER M4 ;
        RECT  34.368 97.344 34.56 97.368 ;
    END
  END dq[573]
  PIN dq[574]
    DIRECTION OUTPUT ;
    USE SIGNAL ;
    PORT
      LAYER M4 ;
        RECT  34.368 97.536 34.56 97.56 ;
    END
  END dq[574]
  PIN dq[575]
    DIRECTION OUTPUT ;
    USE SIGNAL ;
    PORT
      LAYER M4 ;
        RECT  34.368 97.68 34.56 97.704 ;
    END
  END dq[575]
  PIN dq[576]
    DIRECTION OUTPUT ;
    USE SIGNAL ;
    PORT
      LAYER M4 ;
        RECT  34.368 97.872 34.56 97.896 ;
    END
  END dq[576]
  PIN dq[577]
    DIRECTION OUTPUT ;
    USE SIGNAL ;
    PORT
      LAYER M4 ;
        RECT  34.368 98.016 34.56 98.04 ;
    END
  END dq[577]
  PIN dq[578]
    DIRECTION OUTPUT ;
    USE SIGNAL ;
    PORT
      LAYER M4 ;
        RECT  34.368 98.16 34.56 98.184 ;
    END
  END dq[578]
  PIN dq[579]
    DIRECTION OUTPUT ;
    USE SIGNAL ;
    PORT
      LAYER M4 ;
        RECT  34.368 98.352 34.56 98.376 ;
    END
  END dq[579]
  PIN dq[57]
    DIRECTION OUTPUT ;
    USE SIGNAL ;
    PORT
      LAYER M4 ;
        RECT  34.368 13.68 34.56 13.704 ;
    END
  END dq[57]
  PIN dq[580]
    DIRECTION OUTPUT ;
    USE SIGNAL ;
    PORT
      LAYER M4 ;
        RECT  34.368 98.496 34.56 98.52 ;
    END
  END dq[580]
  PIN dq[581]
    DIRECTION OUTPUT ;
    USE SIGNAL ;
    PORT
      LAYER M4 ;
        RECT  34.368 98.64 34.56 98.664 ;
    END
  END dq[581]
  PIN dq[582]
    DIRECTION OUTPUT ;
    USE SIGNAL ;
    PORT
      LAYER M4 ;
        RECT  34.368 98.832 34.56 98.856 ;
    END
  END dq[582]
  PIN dq[583]
    DIRECTION OUTPUT ;
    USE SIGNAL ;
    PORT
      LAYER M4 ;
        RECT  34.368 98.976 34.56 99 ;
    END
  END dq[583]
  PIN dq[584]
    DIRECTION OUTPUT ;
    USE SIGNAL ;
    PORT
      LAYER M4 ;
        RECT  34.368 99.168 34.56 99.192 ;
    END
  END dq[584]
  PIN dq[585]
    DIRECTION OUTPUT ;
    USE SIGNAL ;
    PORT
      LAYER M4 ;
        RECT  34.368 99.312 34.56 99.336 ;
    END
  END dq[585]
  PIN dq[586]
    DIRECTION OUTPUT ;
    USE SIGNAL ;
    PORT
      LAYER M4 ;
        RECT  34.368 99.456 34.56 99.48 ;
    END
  END dq[586]
  PIN dq[587]
    DIRECTION OUTPUT ;
    USE SIGNAL ;
    PORT
      LAYER M4 ;
        RECT  34.368 99.648 34.56 99.672 ;
    END
  END dq[587]
  PIN dq[588]
    DIRECTION OUTPUT ;
    USE SIGNAL ;
    PORT
      LAYER M4 ;
        RECT  34.368 99.792 34.56 99.816 ;
    END
  END dq[588]
  PIN dq[589]
    DIRECTION OUTPUT ;
    USE SIGNAL ;
    PORT
      LAYER M4 ;
        RECT  34.368 99.936 34.56 99.96 ;
    END
  END dq[589]
  PIN dq[58]
    DIRECTION OUTPUT ;
    USE SIGNAL ;
    PORT
      LAYER M4 ;
        RECT  34.368 13.824 34.56 13.848 ;
    END
  END dq[58]
  PIN dq[590]
    DIRECTION OUTPUT ;
    USE SIGNAL ;
    PORT
      LAYER M4 ;
        RECT  34.368 100.128 34.56 100.152 ;
    END
  END dq[590]
  PIN dq[591]
    DIRECTION OUTPUT ;
    USE SIGNAL ;
    PORT
      LAYER M4 ;
        RECT  34.368 100.272 34.56 100.296 ;
    END
  END dq[591]
  PIN dq[592]
    DIRECTION OUTPUT ;
    USE SIGNAL ;
    PORT
      LAYER M4 ;
        RECT  34.368 100.464 34.56 100.488 ;
    END
  END dq[592]
  PIN dq[593]
    DIRECTION OUTPUT ;
    USE SIGNAL ;
    PORT
      LAYER M4 ;
        RECT  34.368 100.608 34.56 100.632 ;
    END
  END dq[593]
  PIN dq[594]
    DIRECTION OUTPUT ;
    USE SIGNAL ;
    PORT
      LAYER M4 ;
        RECT  34.368 100.752 34.56 100.776 ;
    END
  END dq[594]
  PIN dq[595]
    DIRECTION OUTPUT ;
    USE SIGNAL ;
    PORT
      LAYER M4 ;
        RECT  34.368 100.944 34.56 100.968 ;
    END
  END dq[595]
  PIN dq[596]
    DIRECTION OUTPUT ;
    USE SIGNAL ;
    PORT
      LAYER M4 ;
        RECT  34.368 101.088 34.56 101.112 ;
    END
  END dq[596]
  PIN dq[597]
    DIRECTION OUTPUT ;
    USE SIGNAL ;
    PORT
      LAYER M4 ;
        RECT  34.368 101.232 34.56 101.256 ;
    END
  END dq[597]
  PIN dq[598]
    DIRECTION OUTPUT ;
    USE SIGNAL ;
    PORT
      LAYER M4 ;
        RECT  34.368 101.424 34.56 101.448 ;
    END
  END dq[598]
  PIN dq[599]
    DIRECTION OUTPUT ;
    USE SIGNAL ;
    PORT
      LAYER M4 ;
        RECT  34.368 101.568 34.56 101.592 ;
    END
  END dq[599]
  PIN dq[59]
    DIRECTION OUTPUT ;
    USE SIGNAL ;
    PORT
      LAYER M4 ;
        RECT  34.368 13.968 34.56 13.992 ;
    END
  END dq[59]
  PIN dq[5]
    DIRECTION OUTPUT ;
    USE SIGNAL ;
    PORT
      LAYER M4 ;
        RECT  34.368 5.232 34.56 5.256 ;
    END
  END dq[5]
  PIN dq[600]
    DIRECTION OUTPUT ;
    USE SIGNAL ;
    PORT
      LAYER M4 ;
        RECT  34.368 101.76 34.56 101.784 ;
    END
  END dq[600]
  PIN dq[601]
    DIRECTION OUTPUT ;
    USE SIGNAL ;
    PORT
      LAYER M4 ;
        RECT  34.368 101.904 34.56 101.928 ;
    END
  END dq[601]
  PIN dq[602]
    DIRECTION OUTPUT ;
    USE SIGNAL ;
    PORT
      LAYER M4 ;
        RECT  34.368 102.048 34.56 102.072 ;
    END
  END dq[602]
  PIN dq[603]
    DIRECTION OUTPUT ;
    USE SIGNAL ;
    PORT
      LAYER M4 ;
        RECT  34.368 102.24 34.56 102.264 ;
    END
  END dq[603]
  PIN dq[604]
    DIRECTION OUTPUT ;
    USE SIGNAL ;
    PORT
      LAYER M4 ;
        RECT  34.368 102.384 34.56 102.408 ;
    END
  END dq[604]
  PIN dq[605]
    DIRECTION OUTPUT ;
    USE SIGNAL ;
    PORT
      LAYER M4 ;
        RECT  34.368 102.576 34.56 102.6 ;
    END
  END dq[605]
  PIN dq[606]
    DIRECTION OUTPUT ;
    USE SIGNAL ;
    PORT
      LAYER M4 ;
        RECT  34.368 102.72 34.56 102.744 ;
    END
  END dq[606]
  PIN dq[607]
    DIRECTION OUTPUT ;
    USE SIGNAL ;
    PORT
      LAYER M4 ;
        RECT  34.368 102.864 34.56 102.888 ;
    END
  END dq[607]
  PIN dq[608]
    DIRECTION OUTPUT ;
    USE SIGNAL ;
    PORT
      LAYER M4 ;
        RECT  34.368 103.056 34.56 103.08 ;
    END
  END dq[608]
  PIN dq[609]
    DIRECTION OUTPUT ;
    USE SIGNAL ;
    PORT
      LAYER M4 ;
        RECT  34.368 103.2 34.56 103.224 ;
    END
  END dq[609]
  PIN dq[60]
    DIRECTION OUTPUT ;
    USE SIGNAL ;
    PORT
      LAYER M4 ;
        RECT  34.368 14.16 34.56 14.184 ;
    END
  END dq[60]
  PIN dq[610]
    DIRECTION OUTPUT ;
    USE SIGNAL ;
    PORT
      LAYER M4 ;
        RECT  34.368 103.344 34.56 103.368 ;
    END
  END dq[610]
  PIN dq[611]
    DIRECTION OUTPUT ;
    USE SIGNAL ;
    PORT
      LAYER M4 ;
        RECT  34.368 103.536 34.56 103.56 ;
    END
  END dq[611]
  PIN dq[612]
    DIRECTION OUTPUT ;
    USE SIGNAL ;
    PORT
      LAYER M4 ;
        RECT  34.368 103.68 34.56 103.704 ;
    END
  END dq[612]
  PIN dq[613]
    DIRECTION OUTPUT ;
    USE SIGNAL ;
    PORT
      LAYER M4 ;
        RECT  34.368 103.872 34.56 103.896 ;
    END
  END dq[613]
  PIN dq[614]
    DIRECTION OUTPUT ;
    USE SIGNAL ;
    PORT
      LAYER M4 ;
        RECT  34.368 104.016 34.56 104.04 ;
    END
  END dq[614]
  PIN dq[615]
    DIRECTION OUTPUT ;
    USE SIGNAL ;
    PORT
      LAYER M4 ;
        RECT  34.368 104.16 34.56 104.184 ;
    END
  END dq[615]
  PIN dq[616]
    DIRECTION OUTPUT ;
    USE SIGNAL ;
    PORT
      LAYER M4 ;
        RECT  34.368 104.352 34.56 104.376 ;
    END
  END dq[616]
  PIN dq[617]
    DIRECTION OUTPUT ;
    USE SIGNAL ;
    PORT
      LAYER M4 ;
        RECT  34.368 104.496 34.56 104.52 ;
    END
  END dq[617]
  PIN dq[618]
    DIRECTION OUTPUT ;
    USE SIGNAL ;
    PORT
      LAYER M4 ;
        RECT  34.368 104.64 34.56 104.664 ;
    END
  END dq[618]
  PIN dq[619]
    DIRECTION OUTPUT ;
    USE SIGNAL ;
    PORT
      LAYER M4 ;
        RECT  34.368 104.832 34.56 104.856 ;
    END
  END dq[619]
  PIN dq[61]
    DIRECTION OUTPUT ;
    USE SIGNAL ;
    PORT
      LAYER M4 ;
        RECT  34.368 14.304 34.56 14.328 ;
    END
  END dq[61]
  PIN dq[620]
    DIRECTION OUTPUT ;
    USE SIGNAL ;
    PORT
      LAYER M4 ;
        RECT  34.368 104.976 34.56 105 ;
    END
  END dq[620]
  PIN dq[621]
    DIRECTION OUTPUT ;
    USE SIGNAL ;
    PORT
      LAYER M4 ;
        RECT  34.368 105.168 34.56 105.192 ;
    END
  END dq[621]
  PIN dq[622]
    DIRECTION OUTPUT ;
    USE SIGNAL ;
    PORT
      LAYER M4 ;
        RECT  34.368 105.312 34.56 105.336 ;
    END
  END dq[622]
  PIN dq[623]
    DIRECTION OUTPUT ;
    USE SIGNAL ;
    PORT
      LAYER M4 ;
        RECT  34.368 105.456 34.56 105.48 ;
    END
  END dq[623]
  PIN dq[624]
    DIRECTION OUTPUT ;
    USE SIGNAL ;
    PORT
      LAYER M4 ;
        RECT  34.368 105.648 34.56 105.672 ;
    END
  END dq[624]
  PIN dq[625]
    DIRECTION OUTPUT ;
    USE SIGNAL ;
    PORT
      LAYER M4 ;
        RECT  34.368 105.792 34.56 105.816 ;
    END
  END dq[625]
  PIN dq[626]
    DIRECTION OUTPUT ;
    USE SIGNAL ;
    PORT
      LAYER M4 ;
        RECT  34.368 105.936 34.56 105.96 ;
    END
  END dq[626]
  PIN dq[627]
    DIRECTION OUTPUT ;
    USE SIGNAL ;
    PORT
      LAYER M4 ;
        RECT  34.368 106.128 34.56 106.152 ;
    END
  END dq[627]
  PIN dq[628]
    DIRECTION OUTPUT ;
    USE SIGNAL ;
    PORT
      LAYER M4 ;
        RECT  34.368 106.272 34.56 106.296 ;
    END
  END dq[628]
  PIN dq[629]
    DIRECTION OUTPUT ;
    USE SIGNAL ;
    PORT
      LAYER M4 ;
        RECT  34.368 106.464 34.56 106.488 ;
    END
  END dq[629]
  PIN dq[62]
    DIRECTION OUTPUT ;
    USE SIGNAL ;
    PORT
      LAYER M4 ;
        RECT  34.368 14.448 34.56 14.472 ;
    END
  END dq[62]
  PIN dq[630]
    DIRECTION OUTPUT ;
    USE SIGNAL ;
    PORT
      LAYER M4 ;
        RECT  34.368 106.608 34.56 106.632 ;
    END
  END dq[630]
  PIN dq[631]
    DIRECTION OUTPUT ;
    USE SIGNAL ;
    PORT
      LAYER M4 ;
        RECT  34.368 106.752 34.56 106.776 ;
    END
  END dq[631]
  PIN dq[632]
    DIRECTION OUTPUT ;
    USE SIGNAL ;
    PORT
      LAYER M4 ;
        RECT  34.368 106.944 34.56 106.968 ;
    END
  END dq[632]
  PIN dq[633]
    DIRECTION OUTPUT ;
    USE SIGNAL ;
    PORT
      LAYER M4 ;
        RECT  34.368 107.088 34.56 107.112 ;
    END
  END dq[633]
  PIN dq[634]
    DIRECTION OUTPUT ;
    USE SIGNAL ;
    PORT
      LAYER M4 ;
        RECT  34.368 107.28 34.56 107.304 ;
    END
  END dq[634]
  PIN dq[635]
    DIRECTION OUTPUT ;
    USE SIGNAL ;
    PORT
      LAYER M4 ;
        RECT  34.368 107.424 34.56 107.448 ;
    END
  END dq[635]
  PIN dq[636]
    DIRECTION OUTPUT ;
    USE SIGNAL ;
    PORT
      LAYER M4 ;
        RECT  34.368 107.568 34.56 107.592 ;
    END
  END dq[636]
  PIN dq[637]
    DIRECTION OUTPUT ;
    USE SIGNAL ;
    PORT
      LAYER M4 ;
        RECT  34.368 107.76 34.56 107.784 ;
    END
  END dq[637]
  PIN dq[638]
    DIRECTION OUTPUT ;
    USE SIGNAL ;
    PORT
      LAYER M4 ;
        RECT  34.368 107.904 34.56 107.928 ;
    END
  END dq[638]
  PIN dq[639]
    DIRECTION OUTPUT ;
    USE SIGNAL ;
    PORT
      LAYER M4 ;
        RECT  34.368 108.048 34.56 108.072 ;
    END
  END dq[639]
  PIN dq[63]
    DIRECTION OUTPUT ;
    USE SIGNAL ;
    PORT
      LAYER M4 ;
        RECT  34.368 14.64 34.56 14.664 ;
    END
  END dq[63]
  PIN dq[640]
    DIRECTION OUTPUT ;
    USE SIGNAL ;
    PORT
      LAYER M4 ;
        RECT  34.368 108.24 34.56 108.264 ;
    END
  END dq[640]
  PIN dq[641]
    DIRECTION OUTPUT ;
    USE SIGNAL ;
    PORT
      LAYER M4 ;
        RECT  34.368 108.384 34.56 108.408 ;
    END
  END dq[641]
  PIN dq[642]
    DIRECTION OUTPUT ;
    USE SIGNAL ;
    PORT
      LAYER M4 ;
        RECT  34.368 108.576 34.56 108.6 ;
    END
  END dq[642]
  PIN dq[643]
    DIRECTION OUTPUT ;
    USE SIGNAL ;
    PORT
      LAYER M4 ;
        RECT  34.368 108.72 34.56 108.744 ;
    END
  END dq[643]
  PIN dq[644]
    DIRECTION OUTPUT ;
    USE SIGNAL ;
    PORT
      LAYER M4 ;
        RECT  34.368 108.864 34.56 108.888 ;
    END
  END dq[644]
  PIN dq[645]
    DIRECTION OUTPUT ;
    USE SIGNAL ;
    PORT
      LAYER M4 ;
        RECT  34.368 109.056 34.56 109.08 ;
    END
  END dq[645]
  PIN dq[646]
    DIRECTION OUTPUT ;
    USE SIGNAL ;
    PORT
      LAYER M4 ;
        RECT  34.368 109.2 34.56 109.224 ;
    END
  END dq[646]
  PIN dq[647]
    DIRECTION OUTPUT ;
    USE SIGNAL ;
    PORT
      LAYER M4 ;
        RECT  34.368 109.344 34.56 109.368 ;
    END
  END dq[647]
  PIN dq[648]
    DIRECTION OUTPUT ;
    USE SIGNAL ;
    PORT
      LAYER M4 ;
        RECT  34.368 109.536 34.56 109.56 ;
    END
  END dq[648]
  PIN dq[649]
    DIRECTION OUTPUT ;
    USE SIGNAL ;
    PORT
      LAYER M4 ;
        RECT  34.368 109.68 34.56 109.704 ;
    END
  END dq[649]
  PIN dq[64]
    DIRECTION OUTPUT ;
    USE SIGNAL ;
    PORT
      LAYER M4 ;
        RECT  34.368 14.784 34.56 14.808 ;
    END
  END dq[64]
  PIN dq[650]
    DIRECTION OUTPUT ;
    USE SIGNAL ;
    PORT
      LAYER M4 ;
        RECT  34.368 109.872 34.56 109.896 ;
    END
  END dq[650]
  PIN dq[651]
    DIRECTION OUTPUT ;
    USE SIGNAL ;
    PORT
      LAYER M4 ;
        RECT  34.368 110.016 34.56 110.04 ;
    END
  END dq[651]
  PIN dq[652]
    DIRECTION OUTPUT ;
    USE SIGNAL ;
    PORT
      LAYER M4 ;
        RECT  34.368 110.16 34.56 110.184 ;
    END
  END dq[652]
  PIN dq[653]
    DIRECTION OUTPUT ;
    USE SIGNAL ;
    PORT
      LAYER M4 ;
        RECT  34.368 110.352 34.56 110.376 ;
    END
  END dq[653]
  PIN dq[654]
    DIRECTION OUTPUT ;
    USE SIGNAL ;
    PORT
      LAYER M4 ;
        RECT  34.368 110.496 34.56 110.52 ;
    END
  END dq[654]
  PIN dq[655]
    DIRECTION OUTPUT ;
    USE SIGNAL ;
    PORT
      LAYER M4 ;
        RECT  34.368 110.64 34.56 110.664 ;
    END
  END dq[655]
  PIN dq[656]
    DIRECTION OUTPUT ;
    USE SIGNAL ;
    PORT
      LAYER M4 ;
        RECT  34.368 110.832 34.56 110.856 ;
    END
  END dq[656]
  PIN dq[657]
    DIRECTION OUTPUT ;
    USE SIGNAL ;
    PORT
      LAYER M4 ;
        RECT  34.368 110.976 34.56 111 ;
    END
  END dq[657]
  PIN dq[658]
    DIRECTION OUTPUT ;
    USE SIGNAL ;
    PORT
      LAYER M4 ;
        RECT  34.368 111.168 34.56 111.192 ;
    END
  END dq[658]
  PIN dq[659]
    DIRECTION OUTPUT ;
    USE SIGNAL ;
    PORT
      LAYER M4 ;
        RECT  34.368 111.312 34.56 111.336 ;
    END
  END dq[659]
  PIN dq[65]
    DIRECTION OUTPUT ;
    USE SIGNAL ;
    PORT
      LAYER M4 ;
        RECT  34.368 14.976 34.56 15 ;
    END
  END dq[65]
  PIN dq[660]
    DIRECTION OUTPUT ;
    USE SIGNAL ;
    PORT
      LAYER M4 ;
        RECT  34.368 111.456 34.56 111.48 ;
    END
  END dq[660]
  PIN dq[661]
    DIRECTION OUTPUT ;
    USE SIGNAL ;
    PORT
      LAYER M4 ;
        RECT  34.368 111.648 34.56 111.672 ;
    END
  END dq[661]
  PIN dq[662]
    DIRECTION OUTPUT ;
    USE SIGNAL ;
    PORT
      LAYER M4 ;
        RECT  34.368 111.792 34.56 111.816 ;
    END
  END dq[662]
  PIN dq[663]
    DIRECTION OUTPUT ;
    USE SIGNAL ;
    PORT
      LAYER M4 ;
        RECT  34.368 111.984 34.56 112.008 ;
    END
  END dq[663]
  PIN dq[664]
    DIRECTION OUTPUT ;
    USE SIGNAL ;
    PORT
      LAYER M4 ;
        RECT  34.368 112.128 34.56 112.152 ;
    END
  END dq[664]
  PIN dq[665]
    DIRECTION OUTPUT ;
    USE SIGNAL ;
    PORT
      LAYER M4 ;
        RECT  34.368 112.272 34.56 112.296 ;
    END
  END dq[665]
  PIN dq[666]
    DIRECTION OUTPUT ;
    USE SIGNAL ;
    PORT
      LAYER M4 ;
        RECT  34.368 112.464 34.56 112.488 ;
    END
  END dq[666]
  PIN dq[667]
    DIRECTION OUTPUT ;
    USE SIGNAL ;
    PORT
      LAYER M4 ;
        RECT  34.368 112.608 34.56 112.632 ;
    END
  END dq[667]
  PIN dq[668]
    DIRECTION OUTPUT ;
    USE SIGNAL ;
    PORT
      LAYER M4 ;
        RECT  34.368 112.752 34.56 112.776 ;
    END
  END dq[668]
  PIN dq[669]
    DIRECTION OUTPUT ;
    USE SIGNAL ;
    PORT
      LAYER M4 ;
        RECT  34.368 112.944 34.56 112.968 ;
    END
  END dq[669]
  PIN dq[66]
    DIRECTION OUTPUT ;
    USE SIGNAL ;
    PORT
      LAYER M4 ;
        RECT  34.368 15.12 34.56 15.144 ;
    END
  END dq[66]
  PIN dq[670]
    DIRECTION OUTPUT ;
    USE SIGNAL ;
    PORT
      LAYER M4 ;
        RECT  34.368 113.088 34.56 113.112 ;
    END
  END dq[670]
  PIN dq[671]
    DIRECTION OUTPUT ;
    USE SIGNAL ;
    PORT
      LAYER M4 ;
        RECT  34.368 113.28 34.56 113.304 ;
    END
  END dq[671]
  PIN dq[672]
    DIRECTION OUTPUT ;
    USE SIGNAL ;
    PORT
      LAYER M4 ;
        RECT  34.368 113.424 34.56 113.448 ;
    END
  END dq[672]
  PIN dq[673]
    DIRECTION OUTPUT ;
    USE SIGNAL ;
    PORT
      LAYER M4 ;
        RECT  34.368 113.568 34.56 113.592 ;
    END
  END dq[673]
  PIN dq[674]
    DIRECTION OUTPUT ;
    USE SIGNAL ;
    PORT
      LAYER M4 ;
        RECT  34.368 113.76 34.56 113.784 ;
    END
  END dq[674]
  PIN dq[675]
    DIRECTION OUTPUT ;
    USE SIGNAL ;
    PORT
      LAYER M4 ;
        RECT  34.368 113.904 34.56 113.928 ;
    END
  END dq[675]
  PIN dq[676]
    DIRECTION OUTPUT ;
    USE SIGNAL ;
    PORT
      LAYER M4 ;
        RECT  34.368 114.048 34.56 114.072 ;
    END
  END dq[676]
  PIN dq[677]
    DIRECTION OUTPUT ;
    USE SIGNAL ;
    PORT
      LAYER M4 ;
        RECT  34.368 114.24 34.56 114.264 ;
    END
  END dq[677]
  PIN dq[678]
    DIRECTION OUTPUT ;
    USE SIGNAL ;
    PORT
      LAYER M4 ;
        RECT  34.368 114.384 34.56 114.408 ;
    END
  END dq[678]
  PIN dq[679]
    DIRECTION OUTPUT ;
    USE SIGNAL ;
    PORT
      LAYER M4 ;
        RECT  34.368 114.576 34.56 114.6 ;
    END
  END dq[679]
  PIN dq[67]
    DIRECTION OUTPUT ;
    USE SIGNAL ;
    PORT
      LAYER M4 ;
        RECT  34.368 15.264 34.56 15.288 ;
    END
  END dq[67]
  PIN dq[680]
    DIRECTION OUTPUT ;
    USE SIGNAL ;
    PORT
      LAYER M4 ;
        RECT  34.368 114.72 34.56 114.744 ;
    END
  END dq[680]
  PIN dq[681]
    DIRECTION OUTPUT ;
    USE SIGNAL ;
    PORT
      LAYER M4 ;
        RECT  34.368 114.864 34.56 114.888 ;
    END
  END dq[681]
  PIN dq[682]
    DIRECTION OUTPUT ;
    USE SIGNAL ;
    PORT
      LAYER M4 ;
        RECT  34.368 115.056 34.56 115.08 ;
    END
  END dq[682]
  PIN dq[683]
    DIRECTION OUTPUT ;
    USE SIGNAL ;
    PORT
      LAYER M4 ;
        RECT  34.368 115.2 34.56 115.224 ;
    END
  END dq[683]
  PIN dq[684]
    DIRECTION OUTPUT ;
    USE SIGNAL ;
    PORT
      LAYER M4 ;
        RECT  34.368 115.344 34.56 115.368 ;
    END
  END dq[684]
  PIN dq[685]
    DIRECTION OUTPUT ;
    USE SIGNAL ;
    PORT
      LAYER M4 ;
        RECT  34.368 115.536 34.56 115.56 ;
    END
  END dq[685]
  PIN dq[686]
    DIRECTION OUTPUT ;
    USE SIGNAL ;
    PORT
      LAYER M4 ;
        RECT  34.368 115.68 34.56 115.704 ;
    END
  END dq[686]
  PIN dq[687]
    DIRECTION OUTPUT ;
    USE SIGNAL ;
    PORT
      LAYER M4 ;
        RECT  34.368 115.872 34.56 115.896 ;
    END
  END dq[687]
  PIN dq[688]
    DIRECTION OUTPUT ;
    USE SIGNAL ;
    PORT
      LAYER M4 ;
        RECT  34.368 116.016 34.56 116.04 ;
    END
  END dq[688]
  PIN dq[689]
    DIRECTION OUTPUT ;
    USE SIGNAL ;
    PORT
      LAYER M4 ;
        RECT  34.368 116.16 34.56 116.184 ;
    END
  END dq[689]
  PIN dq[68]
    DIRECTION OUTPUT ;
    USE SIGNAL ;
    PORT
      LAYER M4 ;
        RECT  34.368 15.456 34.56 15.48 ;
    END
  END dq[68]
  PIN dq[690]
    DIRECTION OUTPUT ;
    USE SIGNAL ;
    PORT
      LAYER M4 ;
        RECT  34.368 116.352 34.56 116.376 ;
    END
  END dq[690]
  PIN dq[691]
    DIRECTION OUTPUT ;
    USE SIGNAL ;
    PORT
      LAYER M4 ;
        RECT  34.368 116.496 34.56 116.52 ;
    END
  END dq[691]
  PIN dq[692]
    DIRECTION OUTPUT ;
    USE SIGNAL ;
    PORT
      LAYER M4 ;
        RECT  34.368 116.688 34.56 116.712 ;
    END
  END dq[692]
  PIN dq[693]
    DIRECTION OUTPUT ;
    USE SIGNAL ;
    PORT
      LAYER M4 ;
        RECT  34.368 116.832 34.56 116.856 ;
    END
  END dq[693]
  PIN dq[694]
    DIRECTION OUTPUT ;
    USE SIGNAL ;
    PORT
      LAYER M4 ;
        RECT  34.368 116.976 34.56 117 ;
    END
  END dq[694]
  PIN dq[695]
    DIRECTION OUTPUT ;
    USE SIGNAL ;
    PORT
      LAYER M4 ;
        RECT  34.368 117.168 34.56 117.192 ;
    END
  END dq[695]
  PIN dq[696]
    DIRECTION OUTPUT ;
    USE SIGNAL ;
    PORT
      LAYER M4 ;
        RECT  34.368 117.312 34.56 117.336 ;
    END
  END dq[696]
  PIN dq[697]
    DIRECTION OUTPUT ;
    USE SIGNAL ;
    PORT
      LAYER M4 ;
        RECT  34.368 117.456 34.56 117.48 ;
    END
  END dq[697]
  PIN dq[698]
    DIRECTION OUTPUT ;
    USE SIGNAL ;
    PORT
      LAYER M4 ;
        RECT  34.368 117.648 34.56 117.672 ;
    END
  END dq[698]
  PIN dq[699]
    DIRECTION OUTPUT ;
    USE SIGNAL ;
    PORT
      LAYER M4 ;
        RECT  34.368 117.792 34.56 117.816 ;
    END
  END dq[699]
  PIN dq[69]
    DIRECTION OUTPUT ;
    USE SIGNAL ;
    PORT
      LAYER M4 ;
        RECT  34.368 15.6 34.56 15.624 ;
    END
  END dq[69]
  PIN dq[6]
    DIRECTION OUTPUT ;
    USE SIGNAL ;
    PORT
      LAYER M4 ;
        RECT  34.368 5.376 34.56 5.4 ;
    END
  END dq[6]
  PIN dq[700]
    DIRECTION OUTPUT ;
    USE SIGNAL ;
    PORT
      LAYER M4 ;
        RECT  34.368 117.984 34.56 118.008 ;
    END
  END dq[700]
  PIN dq[701]
    DIRECTION OUTPUT ;
    USE SIGNAL ;
    PORT
      LAYER M4 ;
        RECT  34.368 118.128 34.56 118.152 ;
    END
  END dq[701]
  PIN dq[702]
    DIRECTION OUTPUT ;
    USE SIGNAL ;
    PORT
      LAYER M4 ;
        RECT  34.368 118.272 34.56 118.296 ;
    END
  END dq[702]
  PIN dq[703]
    DIRECTION OUTPUT ;
    USE SIGNAL ;
    PORT
      LAYER M4 ;
        RECT  34.368 118.464 34.56 118.488 ;
    END
  END dq[703]
  PIN dq[704]
    DIRECTION OUTPUT ;
    USE SIGNAL ;
    PORT
      LAYER M4 ;
        RECT  34.368 118.608 34.56 118.632 ;
    END
  END dq[704]
  PIN dq[705]
    DIRECTION OUTPUT ;
    USE SIGNAL ;
    PORT
      LAYER M4 ;
        RECT  34.368 118.752 34.56 118.776 ;
    END
  END dq[705]
  PIN dq[706]
    DIRECTION OUTPUT ;
    USE SIGNAL ;
    PORT
      LAYER M4 ;
        RECT  34.368 118.944 34.56 118.968 ;
    END
  END dq[706]
  PIN dq[707]
    DIRECTION OUTPUT ;
    USE SIGNAL ;
    PORT
      LAYER M4 ;
        RECT  34.368 119.088 34.56 119.112 ;
    END
  END dq[707]
  PIN dq[708]
    DIRECTION OUTPUT ;
    USE SIGNAL ;
    PORT
      LAYER M4 ;
        RECT  34.368 119.28 34.56 119.304 ;
    END
  END dq[708]
  PIN dq[709]
    DIRECTION OUTPUT ;
    USE SIGNAL ;
    PORT
      LAYER M4 ;
        RECT  34.368 119.424 34.56 119.448 ;
    END
  END dq[709]
  PIN dq[70]
    DIRECTION OUTPUT ;
    USE SIGNAL ;
    PORT
      LAYER M4 ;
        RECT  34.368 15.792 34.56 15.816 ;
    END
  END dq[70]
  PIN dq[710]
    DIRECTION OUTPUT ;
    USE SIGNAL ;
    PORT
      LAYER M4 ;
        RECT  34.368 119.568 34.56 119.592 ;
    END
  END dq[710]
  PIN dq[711]
    DIRECTION OUTPUT ;
    USE SIGNAL ;
    PORT
      LAYER M4 ;
        RECT  34.368 119.76 34.56 119.784 ;
    END
  END dq[711]
  PIN dq[712]
    DIRECTION OUTPUT ;
    USE SIGNAL ;
    PORT
      LAYER M4 ;
        RECT  34.368 119.904 34.56 119.928 ;
    END
  END dq[712]
  PIN dq[713]
    DIRECTION OUTPUT ;
    USE SIGNAL ;
    PORT
      LAYER M4 ;
        RECT  34.368 120.048 34.56 120.072 ;
    END
  END dq[713]
  PIN dq[714]
    DIRECTION OUTPUT ;
    USE SIGNAL ;
    PORT
      LAYER M4 ;
        RECT  34.368 120.24 34.56 120.264 ;
    END
  END dq[714]
  PIN dq[715]
    DIRECTION OUTPUT ;
    USE SIGNAL ;
    PORT
      LAYER M4 ;
        RECT  34.368 120.384 34.56 120.408 ;
    END
  END dq[715]
  PIN dq[716]
    DIRECTION OUTPUT ;
    USE SIGNAL ;
    PORT
      LAYER M4 ;
        RECT  34.368 120.576 34.56 120.6 ;
    END
  END dq[716]
  PIN dq[717]
    DIRECTION OUTPUT ;
    USE SIGNAL ;
    PORT
      LAYER M4 ;
        RECT  34.368 120.72 34.56 120.744 ;
    END
  END dq[717]
  PIN dq[718]
    DIRECTION OUTPUT ;
    USE SIGNAL ;
    PORT
      LAYER M4 ;
        RECT  34.368 120.864 34.56 120.888 ;
    END
  END dq[718]
  PIN dq[719]
    DIRECTION OUTPUT ;
    USE SIGNAL ;
    PORT
      LAYER M4 ;
        RECT  34.368 121.056 34.56 121.08 ;
    END
  END dq[719]
  PIN dq[71]
    DIRECTION OUTPUT ;
    USE SIGNAL ;
    PORT
      LAYER M4 ;
        RECT  34.368 15.936 34.56 15.96 ;
    END
  END dq[71]
  PIN dq[720]
    DIRECTION OUTPUT ;
    USE SIGNAL ;
    PORT
      LAYER M4 ;
        RECT  34.368 121.2 34.56 121.224 ;
    END
  END dq[720]
  PIN dq[721]
    DIRECTION OUTPUT ;
    USE SIGNAL ;
    PORT
      LAYER M4 ;
        RECT  34.368 121.392 34.56 121.416 ;
    END
  END dq[721]
  PIN dq[722]
    DIRECTION OUTPUT ;
    USE SIGNAL ;
    PORT
      LAYER M4 ;
        RECT  34.368 121.536 34.56 121.56 ;
    END
  END dq[722]
  PIN dq[723]
    DIRECTION OUTPUT ;
    USE SIGNAL ;
    PORT
      LAYER M4 ;
        RECT  34.368 121.68 34.56 121.704 ;
    END
  END dq[723]
  PIN dq[724]
    DIRECTION OUTPUT ;
    USE SIGNAL ;
    PORT
      LAYER M4 ;
        RECT  34.368 121.872 34.56 121.896 ;
    END
  END dq[724]
  PIN dq[725]
    DIRECTION OUTPUT ;
    USE SIGNAL ;
    PORT
      LAYER M4 ;
        RECT  34.368 122.016 34.56 122.04 ;
    END
  END dq[725]
  PIN dq[726]
    DIRECTION OUTPUT ;
    USE SIGNAL ;
    PORT
      LAYER M4 ;
        RECT  34.368 122.16 34.56 122.184 ;
    END
  END dq[726]
  PIN dq[727]
    DIRECTION OUTPUT ;
    USE SIGNAL ;
    PORT
      LAYER M4 ;
        RECT  34.368 122.352 34.56 122.376 ;
    END
  END dq[727]
  PIN dq[728]
    DIRECTION OUTPUT ;
    USE SIGNAL ;
    PORT
      LAYER M4 ;
        RECT  34.368 122.496 34.56 122.52 ;
    END
  END dq[728]
  PIN dq[729]
    DIRECTION OUTPUT ;
    USE SIGNAL ;
    PORT
      LAYER M4 ;
        RECT  34.368 122.688 34.56 122.712 ;
    END
  END dq[729]
  PIN dq[72]
    DIRECTION OUTPUT ;
    USE SIGNAL ;
    PORT
      LAYER M4 ;
        RECT  34.368 16.08 34.56 16.104 ;
    END
  END dq[72]
  PIN dq[730]
    DIRECTION OUTPUT ;
    USE SIGNAL ;
    PORT
      LAYER M4 ;
        RECT  34.368 122.832 34.56 122.856 ;
    END
  END dq[730]
  PIN dq[731]
    DIRECTION OUTPUT ;
    USE SIGNAL ;
    PORT
      LAYER M4 ;
        RECT  34.368 122.976 34.56 123 ;
    END
  END dq[731]
  PIN dq[732]
    DIRECTION OUTPUT ;
    USE SIGNAL ;
    PORT
      LAYER M4 ;
        RECT  34.368 123.168 34.56 123.192 ;
    END
  END dq[732]
  PIN dq[733]
    DIRECTION OUTPUT ;
    USE SIGNAL ;
    PORT
      LAYER M4 ;
        RECT  34.368 123.312 34.56 123.336 ;
    END
  END dq[733]
  PIN dq[734]
    DIRECTION OUTPUT ;
    USE SIGNAL ;
    PORT
      LAYER M4 ;
        RECT  34.368 123.456 34.56 123.48 ;
    END
  END dq[734]
  PIN dq[735]
    DIRECTION OUTPUT ;
    USE SIGNAL ;
    PORT
      LAYER M4 ;
        RECT  34.368 123.648 34.56 123.672 ;
    END
  END dq[735]
  PIN dq[736]
    DIRECTION OUTPUT ;
    USE SIGNAL ;
    PORT
      LAYER M4 ;
        RECT  34.368 123.792 34.56 123.816 ;
    END
  END dq[736]
  PIN dq[737]
    DIRECTION OUTPUT ;
    USE SIGNAL ;
    PORT
      LAYER M4 ;
        RECT  34.368 123.984 34.56 124.008 ;
    END
  END dq[737]
  PIN dq[738]
    DIRECTION OUTPUT ;
    USE SIGNAL ;
    PORT
      LAYER M4 ;
        RECT  34.368 124.128 34.56 124.152 ;
    END
  END dq[738]
  PIN dq[739]
    DIRECTION OUTPUT ;
    USE SIGNAL ;
    PORT
      LAYER M4 ;
        RECT  34.368 124.272 34.56 124.296 ;
    END
  END dq[739]
  PIN dq[73]
    DIRECTION OUTPUT ;
    USE SIGNAL ;
    PORT
      LAYER M4 ;
        RECT  34.368 16.272 34.56 16.296 ;
    END
  END dq[73]
  PIN dq[740]
    DIRECTION OUTPUT ;
    USE SIGNAL ;
    PORT
      LAYER M4 ;
        RECT  34.368 124.464 34.56 124.488 ;
    END
  END dq[740]
  PIN dq[741]
    DIRECTION OUTPUT ;
    USE SIGNAL ;
    PORT
      LAYER M4 ;
        RECT  34.368 124.608 34.56 124.632 ;
    END
  END dq[741]
  PIN dq[742]
    DIRECTION OUTPUT ;
    USE SIGNAL ;
    PORT
      LAYER M4 ;
        RECT  34.368 124.752 34.56 124.776 ;
    END
  END dq[742]
  PIN dq[743]
    DIRECTION OUTPUT ;
    USE SIGNAL ;
    PORT
      LAYER M4 ;
        RECT  34.368 124.944 34.56 124.968 ;
    END
  END dq[743]
  PIN dq[744]
    DIRECTION OUTPUT ;
    USE SIGNAL ;
    PORT
      LAYER M4 ;
        RECT  34.368 125.088 34.56 125.112 ;
    END
  END dq[744]
  PIN dq[745]
    DIRECTION OUTPUT ;
    USE SIGNAL ;
    PORT
      LAYER M4 ;
        RECT  34.368 125.28 34.56 125.304 ;
    END
  END dq[745]
  PIN dq[746]
    DIRECTION OUTPUT ;
    USE SIGNAL ;
    PORT
      LAYER M4 ;
        RECT  34.368 125.424 34.56 125.448 ;
    END
  END dq[746]
  PIN dq[747]
    DIRECTION OUTPUT ;
    USE SIGNAL ;
    PORT
      LAYER M4 ;
        RECT  34.368 125.568 34.56 125.592 ;
    END
  END dq[747]
  PIN dq[748]
    DIRECTION OUTPUT ;
    USE SIGNAL ;
    PORT
      LAYER M4 ;
        RECT  34.368 125.76 34.56 125.784 ;
    END
  END dq[748]
  PIN dq[749]
    DIRECTION OUTPUT ;
    USE SIGNAL ;
    PORT
      LAYER M4 ;
        RECT  34.368 125.904 34.56 125.928 ;
    END
  END dq[749]
  PIN dq[74]
    DIRECTION OUTPUT ;
    USE SIGNAL ;
    PORT
      LAYER M4 ;
        RECT  34.368 16.416 34.56 16.44 ;
    END
  END dq[74]
  PIN dq[750]
    DIRECTION OUTPUT ;
    USE SIGNAL ;
    PORT
      LAYER M4 ;
        RECT  34.368 126.096 34.56 126.12 ;
    END
  END dq[750]
  PIN dq[751]
    DIRECTION OUTPUT ;
    USE SIGNAL ;
    PORT
      LAYER M4 ;
        RECT  34.368 126.24 34.56 126.264 ;
    END
  END dq[751]
  PIN dq[752]
    DIRECTION OUTPUT ;
    USE SIGNAL ;
    PORT
      LAYER M4 ;
        RECT  34.368 126.384 34.56 126.408 ;
    END
  END dq[752]
  PIN dq[753]
    DIRECTION OUTPUT ;
    USE SIGNAL ;
    PORT
      LAYER M4 ;
        RECT  34.368 126.576 34.56 126.6 ;
    END
  END dq[753]
  PIN dq[754]
    DIRECTION OUTPUT ;
    USE SIGNAL ;
    PORT
      LAYER M4 ;
        RECT  34.368 126.72 34.56 126.744 ;
    END
  END dq[754]
  PIN dq[755]
    DIRECTION OUTPUT ;
    USE SIGNAL ;
    PORT
      LAYER M4 ;
        RECT  34.368 126.864 34.56 126.888 ;
    END
  END dq[755]
  PIN dq[756]
    DIRECTION OUTPUT ;
    USE SIGNAL ;
    PORT
      LAYER M4 ;
        RECT  34.368 127.056 34.56 127.08 ;
    END
  END dq[756]
  PIN dq[757]
    DIRECTION OUTPUT ;
    USE SIGNAL ;
    PORT
      LAYER M4 ;
        RECT  34.368 127.2 34.56 127.224 ;
    END
  END dq[757]
  PIN dq[758]
    DIRECTION OUTPUT ;
    USE SIGNAL ;
    PORT
      LAYER M4 ;
        RECT  34.368 127.392 34.56 127.416 ;
    END
  END dq[758]
  PIN dq[75]
    DIRECTION OUTPUT ;
    USE SIGNAL ;
    PORT
      LAYER M4 ;
        RECT  34.368 16.56 34.56 16.584 ;
    END
  END dq[75]
  PIN dq[76]
    DIRECTION OUTPUT ;
    USE SIGNAL ;
    PORT
      LAYER M4 ;
        RECT  34.368 16.752 34.56 16.776 ;
    END
  END dq[76]
  PIN dq[77]
    DIRECTION OUTPUT ;
    USE SIGNAL ;
    PORT
      LAYER M4 ;
        RECT  34.368 16.896 34.56 16.92 ;
    END
  END dq[77]
  PIN dq[78]
    DIRECTION OUTPUT ;
    USE SIGNAL ;
    PORT
      LAYER M4 ;
        RECT  34.368 17.088 34.56 17.112 ;
    END
  END dq[78]
  PIN dq[79]
    DIRECTION OUTPUT ;
    USE SIGNAL ;
    PORT
      LAYER M4 ;
        RECT  34.368 17.232 34.56 17.256 ;
    END
  END dq[79]
  PIN dq[7]
    DIRECTION OUTPUT ;
    USE SIGNAL ;
    PORT
      LAYER M4 ;
        RECT  34.368 5.568 34.56 5.592 ;
    END
  END dq[7]
  PIN dq[80]
    DIRECTION OUTPUT ;
    USE SIGNAL ;
    PORT
      LAYER M4 ;
        RECT  34.368 17.376 34.56 17.4 ;
    END
  END dq[80]
  PIN dq[81]
    DIRECTION OUTPUT ;
    USE SIGNAL ;
    PORT
      LAYER M4 ;
        RECT  34.368 17.568 34.56 17.592 ;
    END
  END dq[81]
  PIN dq[82]
    DIRECTION OUTPUT ;
    USE SIGNAL ;
    PORT
      LAYER M4 ;
        RECT  34.368 17.712 34.56 17.736 ;
    END
  END dq[82]
  PIN dq[83]
    DIRECTION OUTPUT ;
    USE SIGNAL ;
    PORT
      LAYER M4 ;
        RECT  34.368 17.856 34.56 17.88 ;
    END
  END dq[83]
  PIN dq[84]
    DIRECTION OUTPUT ;
    USE SIGNAL ;
    PORT
      LAYER M4 ;
        RECT  34.368 18.048 34.56 18.072 ;
    END
  END dq[84]
  PIN dq[85]
    DIRECTION OUTPUT ;
    USE SIGNAL ;
    PORT
      LAYER M4 ;
        RECT  34.368 18.192 34.56 18.216 ;
    END
  END dq[85]
  PIN dq[86]
    DIRECTION OUTPUT ;
    USE SIGNAL ;
    PORT
      LAYER M4 ;
        RECT  34.368 18.384 34.56 18.408 ;
    END
  END dq[86]
  PIN dq[87]
    DIRECTION OUTPUT ;
    USE SIGNAL ;
    PORT
      LAYER M4 ;
        RECT  34.368 18.528 34.56 18.552 ;
    END
  END dq[87]
  PIN dq[88]
    DIRECTION OUTPUT ;
    USE SIGNAL ;
    PORT
      LAYER M4 ;
        RECT  34.368 18.672 34.56 18.696 ;
    END
  END dq[88]
  PIN dq[89]
    DIRECTION OUTPUT ;
    USE SIGNAL ;
    PORT
      LAYER M4 ;
        RECT  34.368 18.864 34.56 18.888 ;
    END
  END dq[89]
  PIN dq[8]
    DIRECTION OUTPUT ;
    USE SIGNAL ;
    PORT
      LAYER M4 ;
        RECT  34.368 5.712 34.56 5.736 ;
    END
  END dq[8]
  PIN dq[90]
    DIRECTION OUTPUT ;
    USE SIGNAL ;
    PORT
      LAYER M4 ;
        RECT  34.368 19.008 34.56 19.032 ;
    END
  END dq[90]
  PIN dq[91]
    DIRECTION OUTPUT ;
    USE SIGNAL ;
    PORT
      LAYER M4 ;
        RECT  34.368 19.152 34.56 19.176 ;
    END
  END dq[91]
  PIN dq[92]
    DIRECTION OUTPUT ;
    USE SIGNAL ;
    PORT
      LAYER M4 ;
        RECT  34.368 19.344 34.56 19.368 ;
    END
  END dq[92]
  PIN dq[93]
    DIRECTION OUTPUT ;
    USE SIGNAL ;
    PORT
      LAYER M4 ;
        RECT  34.368 19.488 34.56 19.512 ;
    END
  END dq[93]
  PIN dq[94]
    DIRECTION OUTPUT ;
    USE SIGNAL ;
    PORT
      LAYER M4 ;
        RECT  34.368 19.68 34.56 19.704 ;
    END
  END dq[94]
  PIN dq[95]
    DIRECTION OUTPUT ;
    USE SIGNAL ;
    PORT
      LAYER M4 ;
        RECT  34.368 19.824 34.56 19.848 ;
    END
  END dq[95]
  PIN dq[96]
    DIRECTION OUTPUT ;
    USE SIGNAL ;
    PORT
      LAYER M4 ;
        RECT  34.368 19.968 34.56 19.992 ;
    END
  END dq[96]
  PIN dq[97]
    DIRECTION OUTPUT ;
    USE SIGNAL ;
    PORT
      LAYER M4 ;
        RECT  34.368 20.16 34.56 20.184 ;
    END
  END dq[97]
  PIN dq[98]
    DIRECTION OUTPUT ;
    USE SIGNAL ;
    PORT
      LAYER M4 ;
        RECT  34.368 20.304 34.56 20.328 ;
    END
  END dq[98]
  PIN dq[99]
    DIRECTION OUTPUT ;
    USE SIGNAL ;
    PORT
      LAYER M4 ;
        RECT  34.368 20.496 34.56 20.52 ;
    END
  END dq[99]
  PIN dq[9]
    DIRECTION OUTPUT ;
    USE SIGNAL ;
    PORT
      LAYER M4 ;
        RECT  34.368 5.856 34.56 5.88 ;
    END
  END dq[9]
  PIN VDD
    DIRECTION INOUT ;
    USE POWER ;
    PORT
      LAYER M5 ;
        RECT  32.292 2.151 32.412 129.609 ;
        RECT  29.592 2.151 29.712 129.609 ;
        RECT  26.892 2.151 27.012 129.609 ;
        RECT  24.192 2.151 24.312 129.609 ;
        RECT  21.492 2.151 21.612 129.609 ;
        RECT  18.792 2.151 18.912 129.609 ;
        RECT  16.092 2.151 16.212 129.609 ;
        RECT  13.392 2.151 13.512 129.609 ;
        RECT  10.692 2.151 10.812 129.609 ;
        RECT  7.992 2.151 8.112 129.609 ;
        RECT  5.292 2.151 5.412 129.609 ;
        RECT  2.592 2.151 2.712 129.609 ;
    END
  END VDD
  PIN VSS
    DIRECTION INOUT ;
    USE GROUND ;
    PORT
      LAYER M5 ;
        RECT  32.1 2.137 32.22 129.623 ;
        RECT  29.4 2.137 29.52 129.623 ;
        RECT  26.7 2.137 26.82 129.623 ;
        RECT  24 2.137 24.12 129.623 ;
        RECT  21.3 2.137 21.42 129.623 ;
        RECT  18.6 2.137 18.72 129.623 ;
        RECT  15.9 2.137 16.02 129.623 ;
        RECT  13.2 2.137 13.32 129.623 ;
        RECT  10.5 2.137 10.62 129.623 ;
        RECT  7.8 2.137 7.92 129.623 ;
        RECT  5.1 2.137 5.22 129.623 ;
        RECT  2.4 2.137 2.52 129.623 ;
    END
  END VSS
  # OT_OBS_CLOSED layer=M5 d_um=1.536 added=116
  OBS
    LAYER RVTN ;
     RECT  2.16 2.16 32.4 2.295 ;
     RECT  2.16 2.565 32.4 2.835 ;
     RECT  2.16 3.105 32.4 3.375 ;
     RECT  2.16 3.645 32.4 3.915 ;
     RECT  2.16 4.185 32.4 4.455 ;
     RECT  2.16 4.725 32.4 4.995 ;
     RECT  2.16 5.265 32.4 5.535 ;
     RECT  2.16 5.805 32.4 6.075 ;
     RECT  2.16 6.345 32.4 6.615 ;
     RECT  2.16 6.885 32.4 7.155 ;
     RECT  2.16 7.425 32.4 7.695 ;
     RECT  2.16 7.965 32.4 8.235 ;
     RECT  2.16 8.505 32.4 8.775 ;
     RECT  2.16 9.045 32.4 9.315 ;
     RECT  2.16 9.585 32.4 9.855 ;
     RECT  2.16 10.125 32.4 10.395 ;
     RECT  2.16 10.665 32.4 10.935 ;
     RECT  2.16 11.205 32.4 11.475 ;
     RECT  2.16 11.745 32.4 12.015 ;
     RECT  2.16 12.285 32.4 12.555 ;
     RECT  2.16 12.825 32.4 13.095 ;
     RECT  2.16 13.365 32.4 13.635 ;
     RECT  2.16 13.905 32.4 14.175 ;
     RECT  2.16 14.445 32.4 14.715 ;
     RECT  2.16 14.985 32.4 15.255 ;
     RECT  2.16 15.525 32.4 15.795 ;
     RECT  2.16 16.065 32.4 16.335 ;
     RECT  2.16 16.605 32.4 16.875 ;
     RECT  2.16 17.145 32.4 17.415 ;
     RECT  2.16 17.685 32.4 17.955 ;
     RECT  2.16 18.225 32.4 18.495 ;
     RECT  2.16 18.765 32.4 19.035 ;
     RECT  2.16 19.305 32.4 19.575 ;
     RECT  2.16 19.845 32.4 20.115 ;
     RECT  2.16 20.385 32.4 20.655 ;
     RECT  2.16 20.925 32.4 21.195 ;
     RECT  2.16 21.465 32.4 21.735 ;
     RECT  2.16 22.005 32.4 22.275 ;
     RECT  2.16 22.545 32.4 22.815 ;
     RECT  2.16 23.085 32.4 23.355 ;
     RECT  2.16 23.625 32.4 23.895 ;
     RECT  2.16 24.165 32.4 24.435 ;
     RECT  2.16 24.705 32.4 24.975 ;
     RECT  2.16 25.245 32.4 25.515 ;
     RECT  2.16 25.785 32.4 26.055 ;
     RECT  2.16 26.325 32.4 26.595 ;
     RECT  2.16 26.865 32.4 27.135 ;
     RECT  2.16 27.405 32.4 27.675 ;
     RECT  2.16 27.945 32.4 28.215 ;
     RECT  2.16 28.485 32.4 28.755 ;
     RECT  2.16 29.025 32.4 29.295 ;
     RECT  2.16 29.565 32.4 29.835 ;
     RECT  2.16 30.105 32.4 30.375 ;
     RECT  2.16 30.645 32.4 30.915 ;
     RECT  2.16 31.185 32.4 31.455 ;
     RECT  2.16 31.725 32.4 31.995 ;
     RECT  2.16 32.265 32.4 32.535 ;
     RECT  2.16 32.805 32.4 33.075 ;
     RECT  2.16 33.345 32.4 33.615 ;
     RECT  2.16 33.885 32.4 34.155 ;
     RECT  2.16 34.425 32.4 34.695 ;
     RECT  2.16 34.965 32.4 35.235 ;
     RECT  2.16 35.505 32.4 35.775 ;
     RECT  2.16 36.045 32.4 36.315 ;
     RECT  2.16 36.585 32.4 36.855 ;
     RECT  2.16 37.125 32.4 37.395 ;
     RECT  2.16 37.665 32.4 37.935 ;
     RECT  2.16 38.205 32.4 38.475 ;
     RECT  2.16 38.745 32.4 39.015 ;
     RECT  2.16 39.285 32.4 39.555 ;
     RECT  2.16 39.825 32.4 40.095 ;
     RECT  2.16 40.365 32.4 40.635 ;
     RECT  2.16 40.905 32.4 41.175 ;
     RECT  2.16 41.445 32.4 41.715 ;
     RECT  2.16 41.985 32.4 42.255 ;
     RECT  2.16 42.525 32.4 42.795 ;
     RECT  2.16 43.065 32.4 43.335 ;
     RECT  2.16 43.605 32.4 43.875 ;
     RECT  2.16 44.145 32.4 44.415 ;
     RECT  2.16 44.685 32.4 44.955 ;
     RECT  2.16 45.225 32.4 45.495 ;
     RECT  2.16 45.765 32.4 46.035 ;
     RECT  2.16 46.305 32.4 46.575 ;
     RECT  2.16 46.845 32.4 47.115 ;
     RECT  2.16 47.385 32.4 47.655 ;
     RECT  2.16 47.925 32.4 48.195 ;
     RECT  2.16 48.465 32.4 48.735 ;
     RECT  2.16 49.005 32.4 49.275 ;
     RECT  2.16 49.545 32.4 49.815 ;
     RECT  2.16 50.085 32.4 50.355 ;
     RECT  2.16 50.625 32.4 50.895 ;
     RECT  2.16 51.165 32.4 51.435 ;
     RECT  2.16 51.705 32.4 51.975 ;
     RECT  2.16 52.245 32.4 52.515 ;
     RECT  2.16 52.785 32.4 53.055 ;
     RECT  2.16 53.325 32.4 53.595 ;
     RECT  2.16 53.865 32.4 54.135 ;
     RECT  2.16 54.405 32.4 54.675 ;
     RECT  2.16 54.945 32.4 55.215 ;
     RECT  2.16 55.485 32.4 55.755 ;
     RECT  2.16 56.025 32.4 56.295 ;
     RECT  2.16 56.565 32.4 56.835 ;
     RECT  2.16 57.105 32.4 57.375 ;
     RECT  2.16 57.645 32.4 57.915 ;
     RECT  2.16 58.185 32.4 58.455 ;
     RECT  2.16 58.725 32.4 58.995 ;
     RECT  2.16 59.265 32.4 59.535 ;
     RECT  2.16 59.805 32.4 60.075 ;
     RECT  2.16 60.345 32.4 60.615 ;
     RECT  2.16 60.885 32.4 61.155 ;
     RECT  2.16 61.425 32.4 61.695 ;
     RECT  2.16 61.965 32.4 62.235 ;
     RECT  2.16 62.505 32.4 62.775 ;
     RECT  2.16 63.045 32.4 63.315 ;
     RECT  2.16 63.585 32.4 63.855 ;
     RECT  2.16 64.125 32.4 64.395 ;
     RECT  2.16 64.665 32.4 64.935 ;
     RECT  2.16 65.205 32.4 65.475 ;
     RECT  2.16 65.745 32.4 66.015 ;
     RECT  2.16 66.285 32.4 66.555 ;
     RECT  2.16 66.825 32.4 67.095 ;
     RECT  2.16 67.365 32.4 67.635 ;
     RECT  2.16 67.905 32.4 68.175 ;
     RECT  2.16 68.445 32.4 68.715 ;
     RECT  2.16 68.985 32.4 69.255 ;
     RECT  2.16 69.525 32.4 69.795 ;
     RECT  2.16 70.065 32.4 70.335 ;
     RECT  2.16 70.605 32.4 70.875 ;
     RECT  2.16 71.145 32.4 71.415 ;
     RECT  2.16 71.685 32.4 71.955 ;
     RECT  2.16 72.225 32.4 72.495 ;
     RECT  2.16 72.765 32.4 73.035 ;
     RECT  2.16 73.305 32.4 73.575 ;
     RECT  2.16 73.845 32.4 74.115 ;
     RECT  2.16 74.385 32.4 74.655 ;
     RECT  2.16 74.925 32.4 75.195 ;
     RECT  2.16 75.465 32.4 75.735 ;
     RECT  2.16 76.005 32.4 76.275 ;
     RECT  2.16 76.545 32.4 76.815 ;
     RECT  2.16 77.085 32.4 77.355 ;
     RECT  2.16 77.625 32.4 77.895 ;
     RECT  2.16 78.165 32.4 78.435 ;
     RECT  2.16 78.705 32.4 78.975 ;
     RECT  2.16 79.245 32.4 79.515 ;
     RECT  2.16 79.785 32.4 80.055 ;
     RECT  2.16 80.325 32.4 80.595 ;
     RECT  2.16 80.865 32.4 81.135 ;
     RECT  2.16 81.405 32.4 81.675 ;
     RECT  2.16 81.945 32.4 82.215 ;
     RECT  2.16 82.485 32.4 82.755 ;
     RECT  2.16 83.025 32.4 83.295 ;
     RECT  2.16 83.565 32.4 83.835 ;
     RECT  2.16 84.105 32.4 84.375 ;
     RECT  2.16 84.645 32.4 84.915 ;
     RECT  2.16 85.185 32.4 85.455 ;
     RECT  2.16 85.725 32.4 85.995 ;
     RECT  2.16 86.265 32.4 86.535 ;
     RECT  2.16 86.805 32.4 87.075 ;
     RECT  2.16 87.345 32.4 87.615 ;
     RECT  2.16 87.885 32.4 88.155 ;
     RECT  2.16 88.425 32.4 88.695 ;
     RECT  2.16 88.965 32.4 89.235 ;
     RECT  2.16 89.505 32.4 89.775 ;
     RECT  2.16 90.045 32.4 90.315 ;
     RECT  2.16 90.585 32.4 90.855 ;
     RECT  2.16 91.125 32.4 91.395 ;
     RECT  2.16 91.665 32.4 91.935 ;
     RECT  2.16 92.205 32.4 92.475 ;
     RECT  2.16 92.745 32.4 93.015 ;
     RECT  2.16 93.285 32.4 93.555 ;
     RECT  2.16 93.825 32.4 94.095 ;
     RECT  2.16 94.365 32.4 94.635 ;
     RECT  2.16 94.905 32.4 95.175 ;
     RECT  2.16 95.445 32.4 95.715 ;
     RECT  2.16 95.985 32.4 96.255 ;
     RECT  2.16 96.525 32.4 96.795 ;
     RECT  2.16 97.065 32.4 97.335 ;
     RECT  2.16 97.605 32.4 97.875 ;
     RECT  2.16 98.145 32.4 98.415 ;
     RECT  2.16 98.685 32.4 98.955 ;
     RECT  2.16 99.225 32.4 99.495 ;
     RECT  2.16 99.765 32.4 100.035 ;
     RECT  2.16 100.305 32.4 100.575 ;
     RECT  2.16 100.845 32.4 101.115 ;
     RECT  2.16 101.385 32.4 101.655 ;
     RECT  2.16 101.925 32.4 102.195 ;
     RECT  2.16 102.465 32.4 102.735 ;
     RECT  2.16 103.005 32.4 103.275 ;
     RECT  2.16 103.545 32.4 103.815 ;
     RECT  2.16 104.085 32.4 104.355 ;
     RECT  2.16 104.625 32.4 104.895 ;
     RECT  2.16 105.165 32.4 105.435 ;
     RECT  2.16 105.705 32.4 105.975 ;
     RECT  2.16 106.245 32.4 106.515 ;
     RECT  2.16 106.785 32.4 107.055 ;
     RECT  2.16 107.325 32.4 107.595 ;
     RECT  2.16 107.865 32.4 108.135 ;
     RECT  2.16 108.405 32.4 108.675 ;
     RECT  2.16 108.945 32.4 109.215 ;
     RECT  2.16 109.485 32.4 109.755 ;
     RECT  2.16 110.025 32.4 110.295 ;
     RECT  2.16 110.565 32.4 110.835 ;
     RECT  2.16 111.105 32.4 111.375 ;
     RECT  2.16 111.645 32.4 111.915 ;
     RECT  2.16 112.185 32.4 112.455 ;
     RECT  2.16 112.725 32.4 112.995 ;
     RECT  2.16 113.265 32.4 113.535 ;
     RECT  2.16 113.805 32.4 114.075 ;
     RECT  2.16 114.345 32.4 114.615 ;
     RECT  2.16 114.885 32.4 115.155 ;
     RECT  2.16 115.425 32.4 115.695 ;
     RECT  2.16 115.965 32.4 116.235 ;
     RECT  2.16 116.505 32.4 116.775 ;
     RECT  2.16 117.045 32.4 117.315 ;
     RECT  2.16 117.585 32.4 117.855 ;
     RECT  2.16 118.125 32.4 118.395 ;
     RECT  2.16 118.665 32.4 118.935 ;
     RECT  2.16 119.205 32.4 119.475 ;
     RECT  2.16 119.745 32.4 120.015 ;
     RECT  2.16 120.285 32.4 120.555 ;
     RECT  2.16 120.825 32.4 121.095 ;
     RECT  2.16 121.365 32.4 121.635 ;
     RECT  2.16 121.905 32.4 122.175 ;
     RECT  2.16 122.445 32.4 122.715 ;
     RECT  2.16 122.985 32.4 123.255 ;
     RECT  2.16 123.525 32.4 123.795 ;
     RECT  2.16 124.065 32.4 124.335 ;
     RECT  2.16 124.605 32.4 124.875 ;
     RECT  2.16 125.145 32.4 125.415 ;
     RECT  2.16 125.685 32.4 125.955 ;
     RECT  2.16 126.225 32.4 126.495 ;
     RECT  2.16 126.765 32.4 127.035 ;
     RECT  2.16 127.305 32.4 127.575 ;
     RECT  2.16 127.845 32.4 128.115 ;
     RECT  2.16 128.385 32.4 128.655 ;
     RECT  2.16 128.925 32.4 129.195 ;
     RECT  2.16 129.465 32.4 129.6 ;
    LAYER RVTP ;
     RECT  2.16 2.295 32.4 2.565 ;
     RECT  2.16 2.835 32.4 3.105 ;
     RECT  2.16 3.375 32.4 3.645 ;
     RECT  2.16 3.915 32.4 4.185 ;
     RECT  2.16 4.455 32.4 4.725 ;
     RECT  2.16 4.995 32.4 5.265 ;
     RECT  2.16 5.535 32.4 5.805 ;
     RECT  2.16 6.075 32.4 6.345 ;
     RECT  2.16 6.615 32.4 6.885 ;
     RECT  2.16 7.155 32.4 7.425 ;
     RECT  2.16 7.695 32.4 7.965 ;
     RECT  2.16 8.235 32.4 8.505 ;
     RECT  2.16 8.775 32.4 9.045 ;
     RECT  2.16 9.315 32.4 9.585 ;
     RECT  2.16 9.855 32.4 10.125 ;
     RECT  2.16 10.395 32.4 10.665 ;
     RECT  2.16 10.935 32.4 11.205 ;
     RECT  2.16 11.475 32.4 11.745 ;
     RECT  2.16 12.015 32.4 12.285 ;
     RECT  2.16 12.555 32.4 12.825 ;
     RECT  2.16 13.095 32.4 13.365 ;
     RECT  2.16 13.635 32.4 13.905 ;
     RECT  2.16 14.175 32.4 14.445 ;
     RECT  2.16 14.715 32.4 14.985 ;
     RECT  2.16 15.255 32.4 15.525 ;
     RECT  2.16 15.795 32.4 16.065 ;
     RECT  2.16 16.335 32.4 16.605 ;
     RECT  2.16 16.875 32.4 17.145 ;
     RECT  2.16 17.415 32.4 17.685 ;
     RECT  2.16 17.955 32.4 18.225 ;
     RECT  2.16 18.495 32.4 18.765 ;
     RECT  2.16 19.035 32.4 19.305 ;
     RECT  2.16 19.575 32.4 19.845 ;
     RECT  2.16 20.115 32.4 20.385 ;
     RECT  2.16 20.655 32.4 20.925 ;
     RECT  2.16 21.195 32.4 21.465 ;
     RECT  2.16 21.735 32.4 22.005 ;
     RECT  2.16 22.275 32.4 22.545 ;
     RECT  2.16 22.815 32.4 23.085 ;
     RECT  2.16 23.355 32.4 23.625 ;
     RECT  2.16 23.895 32.4 24.165 ;
     RECT  2.16 24.435 32.4 24.705 ;
     RECT  2.16 24.975 32.4 25.245 ;
     RECT  2.16 25.515 32.4 25.785 ;
     RECT  2.16 26.055 32.4 26.325 ;
     RECT  2.16 26.595 32.4 26.865 ;
     RECT  2.16 27.135 32.4 27.405 ;
     RECT  2.16 27.675 32.4 27.945 ;
     RECT  2.16 28.215 32.4 28.485 ;
     RECT  2.16 28.755 32.4 29.025 ;
     RECT  2.16 29.295 32.4 29.565 ;
     RECT  2.16 29.835 32.4 30.105 ;
     RECT  2.16 30.375 32.4 30.645 ;
     RECT  2.16 30.915 32.4 31.185 ;
     RECT  2.16 31.455 32.4 31.725 ;
     RECT  2.16 31.995 32.4 32.265 ;
     RECT  2.16 32.535 32.4 32.805 ;
     RECT  2.16 33.075 32.4 33.345 ;
     RECT  2.16 33.615 32.4 33.885 ;
     RECT  2.16 34.155 32.4 34.425 ;
     RECT  2.16 34.695 32.4 34.965 ;
     RECT  2.16 35.235 32.4 35.505 ;
     RECT  2.16 35.775 32.4 36.045 ;
     RECT  2.16 36.315 32.4 36.585 ;
     RECT  2.16 36.855 32.4 37.125 ;
     RECT  2.16 37.395 32.4 37.665 ;
     RECT  2.16 37.935 32.4 38.205 ;
     RECT  2.16 38.475 32.4 38.745 ;
     RECT  2.16 39.015 32.4 39.285 ;
     RECT  2.16 39.555 32.4 39.825 ;
     RECT  2.16 40.095 32.4 40.365 ;
     RECT  2.16 40.635 32.4 40.905 ;
     RECT  2.16 41.175 32.4 41.445 ;
     RECT  2.16 41.715 32.4 41.985 ;
     RECT  2.16 42.255 32.4 42.525 ;
     RECT  2.16 42.795 32.4 43.065 ;
     RECT  2.16 43.335 32.4 43.605 ;
     RECT  2.16 43.875 32.4 44.145 ;
     RECT  2.16 44.415 32.4 44.685 ;
     RECT  2.16 44.955 32.4 45.225 ;
     RECT  2.16 45.495 32.4 45.765 ;
     RECT  2.16 46.035 32.4 46.305 ;
     RECT  2.16 46.575 32.4 46.845 ;
     RECT  2.16 47.115 32.4 47.385 ;
     RECT  2.16 47.655 32.4 47.925 ;
     RECT  2.16 48.195 32.4 48.465 ;
     RECT  2.16 48.735 32.4 49.005 ;
     RECT  2.16 49.275 32.4 49.545 ;
     RECT  2.16 49.815 32.4 50.085 ;
     RECT  2.16 50.355 32.4 50.625 ;
     RECT  2.16 50.895 32.4 51.165 ;
     RECT  2.16 51.435 32.4 51.705 ;
     RECT  2.16 51.975 32.4 52.245 ;
     RECT  2.16 52.515 32.4 52.785 ;
     RECT  2.16 53.055 32.4 53.325 ;
     RECT  2.16 53.595 32.4 53.865 ;
     RECT  2.16 54.135 32.4 54.405 ;
     RECT  2.16 54.675 32.4 54.945 ;
     RECT  2.16 55.215 32.4 55.485 ;
     RECT  2.16 55.755 32.4 56.025 ;
     RECT  2.16 56.295 32.4 56.565 ;
     RECT  2.16 56.835 32.4 57.105 ;
     RECT  2.16 57.375 32.4 57.645 ;
     RECT  2.16 57.915 32.4 58.185 ;
     RECT  2.16 58.455 32.4 58.725 ;
     RECT  2.16 58.995 32.4 59.265 ;
     RECT  2.16 59.535 32.4 59.805 ;
     RECT  2.16 60.075 32.4 60.345 ;
     RECT  2.16 60.615 32.4 60.885 ;
     RECT  2.16 61.155 32.4 61.425 ;
     RECT  2.16 61.695 32.4 61.965 ;
     RECT  2.16 62.235 32.4 62.505 ;
     RECT  2.16 62.775 32.4 63.045 ;
     RECT  2.16 63.315 32.4 63.585 ;
     RECT  2.16 63.855 32.4 64.125 ;
     RECT  2.16 64.395 32.4 64.665 ;
     RECT  2.16 64.935 32.4 65.205 ;
     RECT  2.16 65.475 32.4 65.745 ;
     RECT  2.16 66.015 32.4 66.285 ;
     RECT  2.16 66.555 32.4 66.825 ;
     RECT  2.16 67.095 32.4 67.365 ;
     RECT  2.16 67.635 32.4 67.905 ;
     RECT  2.16 68.175 32.4 68.445 ;
     RECT  2.16 68.715 32.4 68.985 ;
     RECT  2.16 69.255 32.4 69.525 ;
     RECT  2.16 69.795 32.4 70.065 ;
     RECT  2.16 70.335 32.4 70.605 ;
     RECT  2.16 70.875 32.4 71.145 ;
     RECT  2.16 71.415 32.4 71.685 ;
     RECT  2.16 71.955 32.4 72.225 ;
     RECT  2.16 72.495 32.4 72.765 ;
     RECT  2.16 73.035 32.4 73.305 ;
     RECT  2.16 73.575 32.4 73.845 ;
     RECT  2.16 74.115 32.4 74.385 ;
     RECT  2.16 74.655 32.4 74.925 ;
     RECT  2.16 75.195 32.4 75.465 ;
     RECT  2.16 75.735 32.4 76.005 ;
     RECT  2.16 76.275 32.4 76.545 ;
     RECT  2.16 76.815 32.4 77.085 ;
     RECT  2.16 77.355 32.4 77.625 ;
     RECT  2.16 77.895 32.4 78.165 ;
     RECT  2.16 78.435 32.4 78.705 ;
     RECT  2.16 78.975 32.4 79.245 ;
     RECT  2.16 79.515 32.4 79.785 ;
     RECT  2.16 80.055 32.4 80.325 ;
     RECT  2.16 80.595 32.4 80.865 ;
     RECT  2.16 81.135 32.4 81.405 ;
     RECT  2.16 81.675 32.4 81.945 ;
     RECT  2.16 82.215 32.4 82.485 ;
     RECT  2.16 82.755 32.4 83.025 ;
     RECT  2.16 83.295 32.4 83.565 ;
     RECT  2.16 83.835 32.4 84.105 ;
     RECT  2.16 84.375 32.4 84.645 ;
     RECT  2.16 84.915 32.4 85.185 ;
     RECT  2.16 85.455 32.4 85.725 ;
     RECT  2.16 85.995 32.4 86.265 ;
     RECT  2.16 86.535 32.4 86.805 ;
     RECT  2.16 87.075 32.4 87.345 ;
     RECT  2.16 87.615 32.4 87.885 ;
     RECT  2.16 88.155 32.4 88.425 ;
     RECT  2.16 88.695 32.4 88.965 ;
     RECT  2.16 89.235 32.4 89.505 ;
     RECT  2.16 89.775 32.4 90.045 ;
     RECT  2.16 90.315 32.4 90.585 ;
     RECT  2.16 90.855 32.4 91.125 ;
     RECT  2.16 91.395 32.4 91.665 ;
     RECT  2.16 91.935 32.4 92.205 ;
     RECT  2.16 92.475 32.4 92.745 ;
     RECT  2.16 93.015 32.4 93.285 ;
     RECT  2.16 93.555 32.4 93.825 ;
     RECT  2.16 94.095 32.4 94.365 ;
     RECT  2.16 94.635 32.4 94.905 ;
     RECT  2.16 95.175 32.4 95.445 ;
     RECT  2.16 95.715 32.4 95.985 ;
     RECT  2.16 96.255 32.4 96.525 ;
     RECT  2.16 96.795 32.4 97.065 ;
     RECT  2.16 97.335 32.4 97.605 ;
     RECT  2.16 97.875 32.4 98.145 ;
     RECT  2.16 98.415 32.4 98.685 ;
     RECT  2.16 98.955 32.4 99.225 ;
     RECT  2.16 99.495 32.4 99.765 ;
     RECT  2.16 100.035 32.4 100.305 ;
     RECT  2.16 100.575 32.4 100.845 ;
     RECT  2.16 101.115 32.4 101.385 ;
     RECT  2.16 101.655 32.4 101.925 ;
     RECT  2.16 102.195 32.4 102.465 ;
     RECT  2.16 102.735 32.4 103.005 ;
     RECT  2.16 103.275 32.4 103.545 ;
     RECT  2.16 103.815 32.4 104.085 ;
     RECT  2.16 104.355 32.4 104.625 ;
     RECT  2.16 104.895 32.4 105.165 ;
     RECT  2.16 105.435 32.4 105.705 ;
     RECT  2.16 105.975 32.4 106.245 ;
     RECT  2.16 106.515 32.4 106.785 ;
     RECT  2.16 107.055 32.4 107.325 ;
     RECT  2.16 107.595 32.4 107.865 ;
     RECT  2.16 108.135 32.4 108.405 ;
     RECT  2.16 108.675 32.4 108.945 ;
     RECT  2.16 109.215 32.4 109.485 ;
     RECT  2.16 109.755 32.4 110.025 ;
     RECT  2.16 110.295 32.4 110.565 ;
     RECT  2.16 110.835 32.4 111.105 ;
     RECT  2.16 111.375 32.4 111.645 ;
     RECT  2.16 111.915 32.4 112.185 ;
     RECT  2.16 112.455 32.4 112.725 ;
     RECT  2.16 112.995 32.4 113.265 ;
     RECT  2.16 113.535 32.4 113.805 ;
     RECT  2.16 114.075 32.4 114.345 ;
     RECT  2.16 114.615 32.4 114.885 ;
     RECT  2.16 115.155 32.4 115.425 ;
     RECT  2.16 115.695 32.4 115.965 ;
     RECT  2.16 116.235 32.4 116.505 ;
     RECT  2.16 116.775 32.4 117.045 ;
     RECT  2.16 117.315 32.4 117.585 ;
     RECT  2.16 117.855 32.4 118.125 ;
     RECT  2.16 118.395 32.4 118.665 ;
     RECT  2.16 118.935 32.4 119.205 ;
     RECT  2.16 119.475 32.4 119.745 ;
     RECT  2.16 120.015 32.4 120.285 ;
     RECT  2.16 120.555 32.4 120.825 ;
     RECT  2.16 121.095 32.4 121.365 ;
     RECT  2.16 121.635 32.4 121.905 ;
     RECT  2.16 122.175 32.4 122.445 ;
     RECT  2.16 122.715 32.4 122.985 ;
     RECT  2.16 123.255 32.4 123.525 ;
     RECT  2.16 123.795 32.4 124.065 ;
     RECT  2.16 124.335 32.4 124.605 ;
     RECT  2.16 124.875 32.4 125.145 ;
     RECT  2.16 125.415 32.4 125.685 ;
     RECT  2.16 125.955 32.4 126.225 ;
     RECT  2.16 126.495 32.4 126.765 ;
     RECT  2.16 127.035 32.4 127.305 ;
     RECT  2.16 127.575 32.4 127.845 ;
     RECT  2.16 128.115 32.4 128.385 ;
     RECT  2.16 128.655 32.4 128.925 ;
     RECT  2.16 129.195 32.4 129.465 ;
    LAYER M1 ;
     RECT  2.16 2.151 32.4 129.609 ;
    LAYER M2 ;
     RECT  0.535 12.906 2.16 12.924 ;
     RECT  0.535 16.956 2.16 16.974 ;
     RECT  0.247 52.992 2.16 53.01 ;
     RECT  0.535 54.99 2.16 55.008 ;
     RECT  0.535 70.074 2.16 70.092 ;
     RECT  0.211 94.032 2.16 94.05 ;
     RECT  0.535 109.836 2.16 109.854 ;
     RECT  0.211 114.12 2.16 114.138 ;
     RECT  2.16 2.151 32.4 129.609 ;
     RECT  32.4 2.421 32.412 129.339 ;
     RECT  32.412 54.756 32.459 128.844 ;
     RECT  32.412 3.816 32.495 53.964 ;
     RECT  32.459 110.844 32.495 128.574 ;
     RECT  32.459 54.756 32.531 110.016 ;
     RECT  32.495 110.916 32.531 117.918 ;
     RECT  32.531 73.656 32.567 81.432 ;
     RECT  32.495 118.674 32.567 128.574 ;
     RECT  32.567 127.278 32.783 128.574 ;
     RECT  32.531 82.224 32.891 110.016 ;
     RECT  32.567 118.674 32.891 126.252 ;
     RECT  32.891 125.766 32.927 126.054 ;
     RECT  32.495 23.094 33.035 47.574 ;
     RECT  32.495 4.266 33.071 22.104 ;
     RECT  33.035 23.166 33.071 47.574 ;
     RECT  32.531 67.716 33.071 72.864 ;
     RECT  32.891 82.224 33.071 91.224 ;
     RECT  32.783 127.278 33.071 127.494 ;
     RECT  33.071 4.266 33.107 5.634 ;
     RECT  33.071 6.426 33.107 22.104 ;
     RECT  33.071 23.526 33.107 47.574 ;
     RECT  32.495 48.546 33.107 49.734 ;
     RECT  32.495 50.706 33.107 53.964 ;
     RECT  32.531 54.756 33.107 66.888 ;
     RECT  33.071 70.344 33.107 72.558 ;
     RECT  32.567 73.656 33.107 81.324 ;
     RECT  33.071 89.28 33.107 91.224 ;
     RECT  32.891 92.016 33.107 96.246 ;
     RECT  32.891 97.074 33.107 110.016 ;
     RECT  32.891 120.186 33.107 124.794 ;
     RECT  33.107 4.428 33.143 5.634 ;
     RECT  33.107 23.526 33.143 27.324 ;
     RECT  33.107 40.716 33.143 47.574 ;
     RECT  33.107 97.074 33.143 107.424 ;
     RECT  33.107 28.224 33.179 39.744 ;
     RECT  33.107 15.3 33.575 21.294 ;
     RECT  33.143 47.16 33.575 47.574 ;
     RECT  33.071 82.224 33.575 88.524 ;
     RECT  32.531 111.384 33.575 117.918 ;
     RECT  33.107 121.644 33.575 124.794 ;
     RECT  32.783 128.286 33.575 128.574 ;
     RECT  33.107 7.632 33.611 8.964 ;
     RECT  33.107 10.296 33.611 14.436 ;
     RECT  33.143 23.526 33.611 24.534 ;
     RECT  33.143 25.416 33.611 27.324 ;
     RECT  33.179 28.224 33.611 38.736 ;
     RECT  33.179 39.528 33.611 39.744 ;
     RECT  33.143 40.716 33.611 46.224 ;
     RECT  33.575 47.196 33.611 47.574 ;
     RECT  33.107 49.284 33.611 49.734 ;
     RECT  33.107 53.766 33.611 53.964 ;
     RECT  33.107 58.266 33.611 66.888 ;
     RECT  33.071 67.716 33.611 69.444 ;
     RECT  33.107 76.554 33.611 76.734 ;
     RECT  33.107 79.056 33.611 81.324 ;
     RECT  33.575 82.224 33.611 87.444 ;
     RECT  33.107 89.28 33.611 91.044 ;
     RECT  33.107 92.016 33.611 94.122 ;
     RECT  33.143 97.074 33.611 105.804 ;
     RECT  33.143 106.956 33.611 107.424 ;
     RECT  33.107 108.306 33.611 110.016 ;
     RECT  33.107 120.186 33.611 120.816 ;
     RECT  32.927 125.856 33.611 126.054 ;
     RECT  33.071 127.476 33.611 127.494 ;
     RECT  33.143 5.004 33.647 5.634 ;
     RECT  33.107 6.426 33.647 6.444 ;
     RECT  33.611 7.938 33.647 8.964 ;
     RECT  33.611 10.476 33.647 11.772 ;
     RECT  33.611 12.564 33.647 12.852 ;
     RECT  33.611 13.716 33.647 14.436 ;
     RECT  33.575 17.766 33.647 21.294 ;
     RECT  33.107 22.086 33.647 22.104 ;
     RECT  33.611 23.634 33.647 24.534 ;
     RECT  33.611 25.866 33.647 26.586 ;
     RECT  33.611 28.224 33.647 30.744 ;
     RECT  33.611 31.536 33.647 32.904 ;
     RECT  33.611 33.696 33.647 34.686 ;
     RECT  33.611 35.586 33.647 38.736 ;
     RECT  33.611 39.528 33.647 39.546 ;
     RECT  33.611 40.716 33.647 44.172 ;
     RECT  33.611 45.036 33.647 46.224 ;
     RECT  33.611 47.196 33.647 47.484 ;
     RECT  33.611 49.284 33.647 49.302 ;
     RECT  33.107 50.706 33.647 52.614 ;
     RECT  33.611 53.91 33.647 53.928 ;
     RECT  33.107 54.756 33.647 57.168 ;
     RECT  33.611 58.266 33.647 58.518 ;
     RECT  33.611 59.346 33.647 66.888 ;
     RECT  33.611 67.716 33.647 69.246 ;
     RECT  33.107 70.344 33.647 70.398 ;
     RECT  33.107 71.226 33.647 72.558 ;
     RECT  33.107 73.926 33.647 75.762 ;
     RECT  33.611 76.554 33.647 76.572 ;
     RECT  33.107 77.598 33.647 77.994 ;
     RECT  33.611 79.056 33.647 81.198 ;
     RECT  33.611 82.224 33.647 83.358 ;
     RECT  33.611 84.186 33.647 86.292 ;
     RECT  33.611 87.426 33.647 87.444 ;
     RECT  33.575 88.506 33.647 88.524 ;
     RECT  33.611 89.28 33.647 89.298 ;
     RECT  33.611 90.126 33.647 90.954 ;
     RECT  33.611 92.016 33.647 93.078 ;
     RECT  33.611 94.104 33.647 94.122 ;
     RECT  33.107 94.914 33.647 95.814 ;
     RECT  33.611 97.074 33.647 103.266 ;
     RECT  33.611 104.058 33.647 104.616 ;
     RECT  33.611 105.75 33.647 105.804 ;
     RECT  33.611 107.406 33.647 107.424 ;
     RECT  33.611 108.486 33.647 109.782 ;
     RECT  33.575 111.384 33.647 116.874 ;
     RECT  33.575 117.828 33.647 117.918 ;
     RECT  32.891 118.674 33.647 119.304 ;
     RECT  33.611 120.636 33.647 120.816 ;
     RECT  33.575 121.644 33.647 124.704 ;
     RECT  33.647 10.908 33.683 11.034 ;
     RECT  33.647 12.564 33.683 12.582 ;
     RECT  33.647 13.716 33.683 14.274 ;
     RECT  33.575 15.3 33.683 16.938 ;
     RECT  33.647 19.548 33.683 19.566 ;
     RECT  33.647 20.664 33.683 21.186 ;
     RECT  33.647 26.334 33.683 26.352 ;
     RECT  33.647 29.376 33.683 30.744 ;
     RECT  33.647 31.536 33.683 31.554 ;
     RECT  33.647 32.886 33.683 32.904 ;
     RECT  33.647 33.696 33.683 33.714 ;
     RECT  33.647 35.586 33.683 36.882 ;
     RECT  33.647 41.454 33.683 43.632 ;
     RECT  33.647 45.036 33.683 45.324 ;
     RECT  33.647 47.466 33.683 47.484 ;
     RECT  33.647 50.706 33.683 52.272 ;
     RECT  33.647 55.566 33.683 55.584 ;
     RECT  33.647 56.844 33.683 57.168 ;
     RECT  33.647 59.346 33.683 59.904 ;
     RECT  33.647 62.316 33.683 62.604 ;
     RECT  33.647 64.206 33.683 64.494 ;
     RECT  33.647 65.484 33.683 65.502 ;
     RECT  33.647 66.294 33.683 66.312 ;
     RECT  33.647 71.766 33.683 71.784 ;
     RECT  33.647 72.54 33.683 72.558 ;
     RECT  33.647 75.204 33.683 75.492 ;
     RECT  33.647 77.634 33.683 77.688 ;
     RECT  33.647 79.056 33.683 79.074 ;
     RECT  33.647 79.866 33.683 80.964 ;
     RECT  33.647 82.494 33.683 82.512 ;
     RECT  33.647 84.186 33.683 86.094 ;
     RECT  33.647 90.666 33.683 90.954 ;
     RECT  33.647 92.556 33.683 93.078 ;
     RECT  33.647 95.526 33.683 95.814 ;
     RECT  33.647 97.686 33.683 98.514 ;
     RECT  33.647 99.504 33.683 102.222 ;
     RECT  33.647 104.058 33.683 104.076 ;
     RECT  33.647 111.996 33.683 114.408 ;
     RECT  33.647 116.856 33.683 116.874 ;
     RECT  33.647 117.9 33.683 117.918 ;
     RECT  33.647 118.674 33.683 119.034 ;
     RECT  33.647 120.798 33.683 120.816 ;
     RECT  33.647 121.986 33.683 122.004 ;
     RECT  33.647 123.534 33.683 124.704 ;
     RECT  33.683 10.908 33.719 10.926 ;
     RECT  33.683 16.92 33.719 16.938 ;
     RECT  33.683 20.664 33.719 20.682 ;
     RECT  33.683 30.726 33.719 30.744 ;
     RECT  33.683 42.066 33.719 42.084 ;
     RECT  33.683 45.306 33.719 45.324 ;
     RECT  33.683 50.976 33.719 52.074 ;
     RECT  33.647 54.756 33.719 54.774 ;
     RECT  33.683 56.916 33.719 57.168 ;
     RECT  33.647 60.894 33.719 61.146 ;
     RECT  33.683 62.586 33.719 62.604 ;
     RECT  33.647 70.38 33.719 70.398 ;
     RECT  33.683 75.474 33.719 75.492 ;
     RECT  33.683 77.634 33.719 77.652 ;
     RECT  33.683 80.568 33.719 80.586 ;
     RECT  33.683 85.194 33.719 85.212 ;
     RECT  33.683 90.666 33.719 90.684 ;
     RECT  33.683 95.796 33.719 95.814 ;
     RECT  33.683 98.226 33.719 98.514 ;
     RECT  33.647 105.75 33.719 105.768 ;
     RECT  33.683 112.158 33.719 112.212 ;
     RECT  33.683 112.968 33.719 112.986 ;
     RECT  33.683 118.674 33.719 118.692 ;
     RECT  33.683 123.606 33.719 124.704 ;
     RECT  33.719 50.976 33.755 50.994 ;
     RECT  33.719 60.894 33.755 60.912 ;
     RECT  33.719 98.424 33.755 98.514 ;
     RECT  33.755 98.496 33.791 98.514 ;
     RECT  33.719 112.194 33.791 112.212 ;
     RECT  33.683 15.462 34.259 15.48 ;
     RECT  33.719 124.074 34.331 124.704 ;
     RECT  33.683 14.256 34.367 14.274 ;
     RECT  33.647 17.766 34.367 17.784 ;
     RECT  33.647 28.224 34.367 28.242 ;
     RECT  33.647 38.286 34.367 38.304 ;
     RECT  33.647 46.206 34.367 46.224 ;
     RECT  33.719 52.056 34.367 52.074 ;
     RECT  33.683 64.206 34.367 64.224 ;
     RECT  33.683 84.186 34.367 84.204 ;
     RECT  33.683 86.076 34.367 86.094 ;
     RECT  33.683 93.06 34.367 93.078 ;
     RECT  33.647 109.026 34.367 109.044 ;
     RECT  33.647 115.506 34.367 115.524 ;
     RECT  34.331 124.074 34.367 124.092 ;
     RECT  33.611 126.036 34.367 126.054 ;
     RECT  33.575 128.286 34.403 128.304 ;
    LAYER M3 ;
     RECT  2.415 2.143 2.505 2.413 ;
     RECT  5.115 2.143 5.205 2.413 ;
     RECT  7.815 2.143 7.905 2.413 ;
     RECT  10.515 2.143 10.605 2.413 ;
     RECT  13.215 2.143 13.305 2.413 ;
     RECT  15.915 2.143 16.005 2.413 ;
     RECT  18.615 2.143 18.705 2.413 ;
     RECT  21.315 2.143 21.405 2.413 ;
     RECT  24.015 2.143 24.105 2.413 ;
     RECT  26.715 2.143 26.805 2.413 ;
     RECT  29.415 2.143 29.505 2.413 ;
     RECT  32.115 2.143 32.205 2.413 ;
     RECT  32.115 2.413 32.397 3.811 ;
     RECT  32.115 3.811 32.49 3.847 ;
     RECT  31.716 3.847 32.49 3.955 ;
     RECT  2.415 2.413 2.697 4.261 ;
     RECT  3.816 4.225 3.834 4.261 ;
     RECT  5.115 2.413 5.397 4.261 ;
     RECT  30.996 3.955 32.49 4.261 ;
     RECT  3.816 4.261 3.978 4.379 ;
     RECT  30.996 4.261 33.102 4.423 ;
     RECT  30.996 4.423 33.138 4.495 ;
     RECT  30.816 4.495 33.138 4.649 ;
     RECT  2.415 4.261 2.79 4.747 ;
     RECT  3.816 4.379 3.87 4.765 ;
     RECT  2.304 4.747 2.79 4.801 ;
     RECT  3.528 4.765 3.87 4.801 ;
     RECT  2.304 4.801 3.87 4.891 ;
     RECT  30.996 4.649 33.138 4.999 ;
     RECT  4.788 4.261 5.397 5.071 ;
     RECT  2.268 4.891 3.87 5.197 ;
     RECT  4.752 5.071 5.397 5.197 ;
     RECT  7.815 2.413 8.097 5.197 ;
     RECT  2.268 5.197 5.397 5.405 ;
     RECT  7.38 5.197 8.097 5.563 ;
     RECT  29.415 2.413 29.697 5.575 ;
     RECT  29.415 5.575 29.79 5.611 ;
     RECT  6.156 5.341 6.174 5.701 ;
     RECT  29.088 5.611 29.79 5.773 ;
     RECT  2.304 5.405 5.397 5.845 ;
     RECT  6.156 5.701 6.246 5.845 ;
     RECT  7.38 5.563 8.226 5.845 ;
     RECT  9.36 5.845 9.378 5.971 ;
     RECT  2.304 5.845 8.226 5.999 ;
     RECT  9.36 5.971 9.486 5.999 ;
     RECT  29.088 5.773 30.186 6.035 ;
     RECT  9.468 5.999 9.486 6.071 ;
     RECT  30.996 4.999 33.642 6.115 ;
     RECT  7.815 5.999 8.226 6.151 ;
     RECT  29.088 6.035 29.79 6.179 ;
     RECT  7.815 6.151 8.37 6.269 ;
     RECT  9.504 6.151 9.522 6.269 ;
     RECT  2.304 5.999 6.822 6.817 ;
     RECT  7.815 6.269 8.097 6.817 ;
     RECT  2.304 6.817 8.097 6.845 ;
     RECT  29.415 6.179 29.79 6.961 ;
     RECT  30.564 6.115 33.642 6.961 ;
     RECT  2.304 6.845 4.302 7.003 ;
     RECT  29.415 6.961 33.642 7.037 ;
     RECT  10.515 2.413 10.797 7.123 ;
     RECT  10.515 7.123 10.854 7.223 ;
     RECT  5.076 6.845 8.097 7.259 ;
     RECT  5.076 7.259 6.93 7.349 ;
     RECT  7.668 7.259 8.097 7.349 ;
     RECT  9.216 7.087 9.234 7.349 ;
     RECT  2.268 7.003 4.302 7.421 ;
     RECT  2.268 7.421 3.402 7.529 ;
     RECT  5.076 7.349 6.894 7.579 ;
     RECT  29.415 7.037 33.606 7.819 ;
     RECT  4.356 7.579 6.894 7.925 ;
     RECT  7.704 7.349 8.097 8.005 ;
     RECT  4.5 7.925 6.894 8.275 ;
     RECT  7.704 8.005 8.118 8.275 ;
     RECT  4.5 8.275 8.118 8.429 ;
     RECT  2.304 7.529 3.402 8.581 ;
     RECT  7.704 8.429 8.118 8.581 ;
     RECT  2.304 8.581 3.474 8.635 ;
     RECT  7.704 8.581 8.298 8.699 ;
     RECT  4.5 8.429 6.858 8.743 ;
     RECT  2.268 8.635 3.474 8.851 ;
     RECT  4.284 8.743 6.858 8.969 ;
     RECT  4.356 8.969 6.858 9.005 ;
     RECT  29.415 7.819 33.642 9.149 ;
     RECT  10.515 7.223 10.797 9.211 ;
     RECT  9.216 9.121 9.234 9.247 ;
     RECT  10.515 9.211 10.926 9.311 ;
     RECT  4.536 9.005 6.858 9.545 ;
     RECT  0.252 9.451 0.27 9.581 ;
     RECT  5.076 9.545 6.858 9.625 ;
     RECT  5.076 9.625 6.966 9.661 ;
     RECT  7.704 8.699 8.19 9.661 ;
     RECT  9.108 9.247 9.234 9.751 ;
     RECT  5.076 9.661 8.334 9.779 ;
     RECT  2.268 8.851 3.546 9.787 ;
     RECT  2.268 9.787 4.338 9.815 ;
     RECT  5.076 9.779 8.262 9.815 ;
     RECT  9.072 9.751 9.234 9.851 ;
     RECT  9.144 9.851 9.234 9.931 ;
     RECT  29.415 9.149 33.606 10.075 ;
     RECT  5.115 9.815 8.262 10.085 ;
     RECT  29.415 10.075 33.642 10.165 ;
     RECT  26.715 2.413 26.997 10.291 ;
     RECT  9.144 9.931 9.342 10.319 ;
     RECT  10.515 9.311 10.797 10.327 ;
     RECT  29.376 10.165 33.642 10.411 ;
     RECT  10.515 10.327 10.926 10.463 ;
     RECT  26.715 10.291 27.054 10.499 ;
     RECT  2.304 9.815 4.338 10.555 ;
     RECT  5.115 10.085 8.097 10.555 ;
     RECT  9.144 10.319 9.162 10.661 ;
     RECT  29.376 10.411 33.678 10.903 ;
     RECT  29.376 10.903 33.714 11.011 ;
     RECT  2.304 10.555 8.097 11.039 ;
     RECT  6.696 11.039 8.097 11.083 ;
     RECT  6.696 11.083 8.334 11.129 ;
     RECT  29.016 11.011 33.714 11.129 ;
     RECT  0.216 11.035 0.234 11.165 ;
     RECT  29.415 11.129 33.714 11.237 ;
     RECT  33.624 11.237 33.714 11.261 ;
     RECT  6.696 11.129 8.19 11.309 ;
     RECT  2.304 11.039 5.922 11.435 ;
     RECT  26.715 10.499 26.997 11.443 ;
     RECT  3.996 11.435 5.922 11.821 ;
     RECT  6.696 11.309 8.097 11.821 ;
     RECT  26.715 11.443 27.054 11.849 ;
     RECT  29.415 11.237 32.562 12.043 ;
     RECT  3.996 11.821 8.097 12.119 ;
     RECT  29.415 12.043 32.886 12.181 ;
     RECT  33.624 11.261 33.642 12.181 ;
     RECT  29.415 12.181 33.642 12.221 ;
     RECT  2.304 11.435 3.078 12.253 ;
     RECT  3.996 12.119 5.742 12.253 ;
     RECT  2.304 12.253 5.742 12.353 ;
     RECT  6.732 12.119 8.097 12.353 ;
     RECT  7.815 12.353 8.097 12.361 ;
     RECT  7.815 12.361 8.766 12.479 ;
     RECT  33.624 12.221 33.642 12.559 ;
     RECT  33.624 12.559 33.678 12.701 ;
     RECT  6.732 12.353 7.038 12.901 ;
     RECT  3.456 12.353 5.742 12.991 ;
     RECT  6.588 12.901 7.038 12.991 ;
     RECT  29.415 12.221 32.886 13.003 ;
     RECT  33.624 12.701 33.642 13.003 ;
     RECT  8.928 12.829 9.126 13.019 ;
     RECT  3.456 12.991 7.038 13.055 ;
     RECT  2.304 12.353 2.697 13.171 ;
     RECT  3.456 13.055 6.894 13.171 ;
     RECT  0.54 12.901 0.558 13.181 ;
     RECT  2.304 13.171 6.894 13.289 ;
     RECT  8.928 13.019 9.054 13.289 ;
     RECT  10.515 10.463 10.797 13.297 ;
     RECT  2.304 13.289 6.858 13.361 ;
     RECT  2.304 13.361 2.862 13.405 ;
     RECT  7.815 12.479 8.097 13.441 ;
     RECT  3.636 13.361 6.858 13.469 ;
     RECT  29.415 13.003 33.642 13.483 ;
     RECT  2.268 13.405 2.862 13.517 ;
     RECT  3.636 13.469 6.678 13.595 ;
     RECT  7.704 13.441 8.097 13.603 ;
     RECT  10.515 13.297 10.818 13.667 ;
     RECT  29.415 13.483 33.678 13.819 ;
     RECT  3.636 13.595 6.57 14.009 ;
     RECT  29.415 13.819 34.362 14.071 ;
     RECT  2.304 13.517 2.862 14.215 ;
     RECT  3.636 14.009 6.426 14.215 ;
     RECT  7.704 13.603 8.586 14.251 ;
     RECT  29.376 14.071 34.362 14.279 ;
     RECT  29.376 14.279 33.678 14.333 ;
     RECT  7.56 14.251 8.586 14.369 ;
     RECT  7.74 14.369 8.586 14.441 ;
     RECT  29.376 14.333 33.642 14.639 ;
     RECT  26.715 11.849 26.997 14.683 ;
     RECT  26.715 14.683 27.054 14.819 ;
     RECT  29.415 14.639 33.642 15.115 ;
     RECT  29.415 15.115 33.678 15.259 ;
     RECT  2.304 14.215 6.426 15.331 ;
     RECT  29.415 15.259 34.254 15.485 ;
     RECT  2.304 15.331 6.858 15.763 ;
     RECT  7.74 14.441 8.37 15.763 ;
     RECT  0.252 15.595 0.27 15.773 ;
     RECT  2.304 15.763 8.37 15.871 ;
     RECT  2.304 15.871 8.586 16.105 ;
     RECT  26.715 14.819 26.997 16.231 ;
     RECT  2.304 16.105 9.126 16.331 ;
     RECT  26.715 16.231 27.054 16.439 ;
     RECT  2.304 16.331 8.406 16.529 ;
     RECT  2.304 16.529 8.334 16.637 ;
     RECT  2.304 16.637 7.074 16.747 ;
     RECT  29.415 15.485 33.678 16.747 ;
     RECT  2.268 16.747 7.074 16.835 ;
     RECT  2.268 16.835 3.546 16.907 ;
     RECT  29.415 16.747 33.714 16.943 ;
     RECT  7.815 16.637 8.334 16.979 ;
     RECT  4.32 16.835 7.074 17.069 ;
     RECT  4.392 17.069 7.074 17.105 ;
     RECT  0.54 16.951 0.558 17.117 ;
     RECT  0.216 17.467 0.234 17.597 ;
     RECT  29.415 16.943 33.606 17.707 ;
     RECT  34.344 17.083 34.362 17.707 ;
     RECT  29.415 17.707 34.362 17.761 ;
     RECT  28.872 17.761 34.362 17.789 ;
     RECT  2.304 16.907 3.546 17.851 ;
     RECT  4.392 17.105 6.858 17.851 ;
     RECT  28.872 17.789 33.642 17.879 ;
     RECT  2.304 17.851 6.858 17.959 ;
     RECT  7.815 16.979 8.262 17.959 ;
     RECT  29.304 17.879 33.642 18.077 ;
     RECT  2.304 17.959 8.262 18.149 ;
     RECT  4.392 18.149 8.262 18.193 ;
     RECT  2.304 18.149 3.402 18.379 ;
     RECT  4.392 18.193 8.586 18.419 ;
     RECT  0.216 18.667 0.234 18.797 ;
     RECT  10.515 13.667 10.797 18.841 ;
     RECT  29.304 18.077 32.397 18.859 ;
     RECT  2.268 18.379 3.402 18.893 ;
     RECT  4.392 18.419 6.174 18.967 ;
     RECT  10.515 18.841 10.818 19.103 ;
     RECT  6.984 18.419 8.37 19.139 ;
     RECT  2.304 18.893 3.402 19.345 ;
     RECT  4.284 18.967 6.174 19.345 ;
     RECT  2.304 19.345 6.174 19.471 ;
     RECT  6.984 19.139 8.298 19.471 ;
     RECT  9.54 19.381 9.63 19.499 ;
     RECT  33.552 18.077 33.642 19.543 ;
     RECT  9.612 19.499 9.63 19.571 ;
     RECT  29.304 18.859 32.49 19.615 ;
     RECT  33.552 19.543 33.678 19.615 ;
     RECT  29.304 19.615 33.678 19.709 ;
     RECT  33.552 19.709 33.678 19.769 ;
     RECT  29.304 19.709 32.49 19.949 ;
     RECT  2.304 19.471 8.298 20.075 ;
     RECT  2.34 20.075 8.298 20.309 ;
     RECT  6.84 20.309 8.298 20.429 ;
     RECT  6.84 20.429 8.097 20.489 ;
     RECT  33.624 19.769 33.678 20.491 ;
     RECT  0.216 20.395 0.234 20.525 ;
     RECT  33.624 20.491 33.714 20.623 ;
     RECT  33.588 20.623 33.714 20.687 ;
     RECT  2.34 20.309 6.03 20.765 ;
     RECT  29.304 19.949 32.397 20.779 ;
     RECT  2.34 20.765 5.886 20.885 ;
     RECT  2.34 20.885 5.742 20.971 ;
     RECT  29.304 20.779 32.526 21.115 ;
     RECT  33.588 20.687 33.678 21.115 ;
     RECT  29.304 21.115 33.678 21.191 ;
     RECT  6.984 20.489 8.097 21.235 ;
     RECT  6.948 21.235 8.097 21.271 ;
     RECT  9.144 21.001 9.162 21.271 ;
     RECT  29.304 21.191 33.642 21.271 ;
     RECT  6.948 21.271 8.154 21.361 ;
     RECT  29.124 21.271 33.642 21.389 ;
     RECT  9.144 21.271 9.342 21.469 ;
     RECT  6.804 21.361 8.154 21.505 ;
     RECT  6.768 21.505 8.154 21.569 ;
     RECT  9.144 21.469 9.45 21.569 ;
     RECT  2.304 20.971 5.742 21.811 ;
     RECT  6.768 21.569 8.097 21.811 ;
     RECT  2.304 21.811 5.814 22.009 ;
     RECT  2.304 22.009 5.922 22.072 ;
     RECT  2.268 22.072 5.922 22.081 ;
     RECT  6.66 21.811 8.097 22.081 ;
     RECT  2.268 22.081 8.097 22.109 ;
     RECT  29.415 21.389 33.642 22.109 ;
     RECT  2.304 22.109 8.097 22.199 ;
     RECT  9.144 21.569 9.162 22.243 ;
     RECT  9.108 22.243 9.162 22.315 ;
     RECT  9.108 22.315 9.486 22.379 ;
     RECT  29.415 22.109 33.066 22.441 ;
     RECT  9.396 22.379 9.486 22.469 ;
     RECT  9.432 22.469 9.45 22.649 ;
     RECT  29.088 22.441 33.066 22.649 ;
     RECT  6.984 22.199 8.097 22.739 ;
     RECT  2.304 22.199 6.102 23.009 ;
     RECT  29.415 22.649 33.066 23.189 ;
     RECT  33.588 23.227 33.606 23.371 ;
     RECT  9.36 23.323 9.378 23.549 ;
     RECT  6.84 23.125 6.858 23.701 ;
     RECT  0.396 23.707 0.414 23.885 ;
     RECT  2.304 23.009 5.886 23.899 ;
     RECT  6.732 23.701 6.858 23.971 ;
     RECT  6.732 23.971 6.93 24.061 ;
     RECT  2.304 23.899 5.958 24.089 ;
     RECT  9.288 23.971 9.306 24.089 ;
     RECT  6.732 24.061 6.966 24.091 ;
     RECT  7.815 22.739 8.097 24.091 ;
     RECT  6.732 24.091 8.097 24.131 ;
     RECT  29.415 23.189 32.526 24.187 ;
     RECT  33.588 23.371 33.642 24.187 ;
     RECT  6.732 24.131 6.966 24.233 ;
     RECT  6.732 24.233 6.93 24.269 ;
     RECT  6.732 24.269 6.894 24.511 ;
     RECT  29.415 24.187 33.642 24.557 ;
     RECT  6.624 24.511 6.894 24.809 ;
     RECT  2.304 24.089 5.886 24.859 ;
     RECT  2.268 24.859 5.886 24.935 ;
     RECT  6.624 24.809 6.858 25.079 ;
     RECT  29.415 24.557 33.606 25.205 ;
     RECT  2.304 24.935 5.886 25.285 ;
     RECT  6.624 25.079 6.75 25.285 ;
     RECT  7.815 24.131 8.097 25.291 ;
     RECT  8.964 25.249 8.982 25.291 ;
     RECT  7.815 25.291 8.982 25.321 ;
     RECT  0.252 25.339 0.27 25.469 ;
     RECT  7.815 25.321 9.486 25.547 ;
     RECT  30.528 25.205 33.606 25.675 ;
     RECT  9.468 25.547 9.486 25.709 ;
     RECT  30.528 25.675 33.642 25.819 ;
     RECT  2.304 25.285 6.75 25.861 ;
     RECT  29.415 25.205 29.697 25.861 ;
     RECT  2.304 25.861 6.858 25.889 ;
     RECT  29.124 25.861 29.697 25.951 ;
     RECT  30.528 25.819 33.678 25.951 ;
     RECT  2.304 25.889 5.526 25.963 ;
     RECT  29.124 25.951 33.678 25.979 ;
     RECT  2.268 25.963 5.526 26.087 ;
     RECT  10.515 19.103 10.797 26.221 ;
     RECT  29.268 25.979 33.678 26.357 ;
     RECT  7.815 25.547 8.37 26.401 ;
     RECT  7.815 26.401 8.442 26.519 ;
     RECT  29.268 26.357 33.642 26.591 ;
     RECT  2.268 26.087 5.397 26.825 ;
     RECT  7.815 26.519 8.154 26.905 ;
     RECT  2.304 26.825 5.397 26.941 ;
     RECT  6.264 25.889 6.858 26.941 ;
     RECT  29.268 26.591 33.606 27.103 ;
     RECT  10.515 26.221 11.43 27.131 ;
     RECT  0.252 27.163 0.27 27.293 ;
     RECT  28.908 27.103 33.606 27.329 ;
     RECT  7.668 26.905 8.154 27.598 ;
     RECT  28.908 27.329 33.102 27.599 ;
     RECT  2.304 26.941 6.858 27.679 ;
     RECT  7.668 27.598 8.19 27.679 ;
     RECT  2.304 27.679 8.19 27.743 ;
     RECT  11.988 27.211 12.006 27.743 ;
     RECT  2.304 27.743 6.03 27.869 ;
     RECT  6.804 27.743 8.19 27.869 ;
     RECT  29.415 27.599 33.102 28.049 ;
     RECT  6.804 27.869 8.097 28.139 ;
     RECT  34.344 27.595 34.362 28.247 ;
     RECT  9.144 27.841 9.162 28.409 ;
     RECT  6.876 28.139 8.097 28.829 ;
     RECT  3.852 27.869 5.886 28.831 ;
     RECT  29.415 28.049 32.49 28.891 ;
     RECT  33.588 28.267 33.678 28.891 ;
     RECT  2.304 27.869 2.79 28.921 ;
     RECT  3.852 28.831 6.138 28.921 ;
     RECT  7.815 28.829 8.097 28.921 ;
     RECT  9 28.831 9.018 28.921 ;
     RECT  2.304 28.921 6.138 28.993 ;
     RECT  2.304 28.993 6.858 29.083 ;
     RECT  7.815 28.921 9.018 29.129 ;
     RECT  10.515 27.131 10.797 29.191 ;
     RECT  7.815 29.129 8.946 29.219 ;
     RECT  2.268 29.083 6.858 29.255 ;
     RECT  10.515 29.191 10.818 29.291 ;
     RECT  4.464 29.255 6.858 29.363 ;
     RECT  4.464 29.363 6.066 29.525 ;
     RECT  6.84 29.363 6.858 29.731 ;
     RECT  29.415 28.891 33.678 30.043 ;
     RECT  2.268 29.255 3.546 30.065 ;
     RECT  2.304 30.065 3.546 30.145 ;
     RECT  4.464 29.525 5.886 30.145 ;
     RECT  2.304 30.145 5.886 30.173 ;
     RECT  0.252 30.091 0.27 30.221 ;
     RECT  7.815 29.219 8.586 30.299 ;
     RECT  3.816 30.173 5.886 30.343 ;
     RECT  6.84 29.731 6.966 30.343 ;
     RECT  9.072 30.451 9.09 30.569 ;
     RECT  29.415 30.043 33.714 30.749 ;
     RECT  3.816 30.343 6.966 30.839 ;
     RECT  29.415 30.749 33.642 30.883 ;
     RECT  2.304 30.173 2.97 30.991 ;
     RECT  3.816 30.839 6.03 30.991 ;
     RECT  6.804 30.839 6.966 31.225 ;
     RECT  7.815 30.299 8.097 31.225 ;
     RECT  6.804 31.225 8.097 31.261 ;
     RECT  2.304 30.991 6.03 31.339 ;
     RECT  6.804 31.261 8.154 31.379 ;
     RECT  28.692 30.883 33.642 31.483 ;
     RECT  2.268 31.339 6.03 31.487 ;
     RECT  28.692 31.483 33.678 31.559 ;
     RECT  2.304 31.487 6.03 31.765 ;
     RECT  7.092 31.379 8.154 31.801 ;
     RECT  7.092 31.801 8.406 31.919 ;
     RECT  29.376 31.559 33.642 31.919 ;
     RECT  29.415 31.919 33.642 32.299 ;
     RECT  2.304 31.765 6.102 32.341 ;
     RECT  7.092 31.919 8.334 32.341 ;
     RECT  2.304 32.341 8.334 32.381 ;
     RECT  2.304 32.381 6.894 32.459 ;
     RECT  2.304 32.459 5.85 32.495 ;
     RECT  2.304 32.495 5.814 32.603 ;
     RECT  29.415 32.299 33.678 32.701 ;
     RECT  2.304 32.603 5.706 32.765 ;
     RECT  29.304 32.701 33.678 32.909 ;
     RECT  29.304 32.909 33.642 32.999 ;
     RECT  7.668 32.381 8.334 33.043 ;
     RECT  6.588 32.459 6.894 33.053 ;
     RECT  3.672 32.765 5.706 33.421 ;
     RECT  6.912 33.421 6.93 33.499 ;
     RECT  7.668 33.043 8.406 33.499 ;
     RECT  2.304 32.765 2.862 33.511 ;
     RECT  3.672 33.421 6.138 33.511 ;
     RECT  6.912 33.499 8.406 33.539 ;
     RECT  29.376 32.999 33.642 33.575 ;
     RECT  7.056 33.539 8.406 33.655 ;
     RECT  7.056 33.655 8.658 33.691 ;
     RECT  29.415 33.575 33.642 33.691 ;
     RECT  2.304 33.511 6.138 33.781 ;
     RECT  10.515 29.291 10.797 33.961 ;
     RECT  7.056 33.691 9.09 34.079 ;
     RECT  10.515 33.961 10.818 34.151 ;
     RECT  7.056 34.079 8.334 34.223 ;
     RECT  29.415 33.691 33.678 34.301 ;
     RECT  7.056 34.223 8.097 34.385 ;
     RECT  29.415 34.301 33.642 34.501 ;
     RECT  29.196 34.501 33.642 34.619 ;
     RECT  2.304 33.781 6.246 34.889 ;
     RECT  9.108 34.501 9.126 35.041 ;
     RECT  9.108 35.041 9.198 35.159 ;
     RECT  0.252 35.083 0.27 35.213 ;
     RECT  7.524 34.385 8.097 35.311 ;
     RECT  29.415 34.619 33.642 35.371 ;
     RECT  29.415 35.371 33.678 35.429 ;
     RECT  6.876 35.311 8.097 35.473 ;
     RECT  6.876 35.473 8.622 35.879 ;
     RECT  29.415 35.429 32.49 35.977 ;
     RECT  28.98 35.977 32.49 36.077 ;
     RECT  2.304 34.889 6.138 36.085 ;
     RECT  7.704 35.879 8.622 36.149 ;
     RECT  2.304 36.085 6.858 36.187 ;
     RECT  29.415 36.077 32.49 36.523 ;
     RECT  33.588 35.429 33.678 36.523 ;
     RECT  2.268 36.187 6.858 36.661 ;
     RECT  7.815 36.149 8.622 36.661 ;
     RECT  7.815 36.661 9.306 36.779 ;
     RECT  29.415 36.523 33.678 36.887 ;
     RECT  2.268 36.661 7.074 37.201 ;
     RECT  7.815 36.779 8.37 37.201 ;
     RECT  2.268 37.201 8.37 37.355 ;
     RECT  2.304 37.355 8.37 37.597 ;
     RECT  0.216 36.667 0.234 37.613 ;
     RECT  2.304 37.597 8.586 37.733 ;
     RECT  6.732 37.733 8.586 37.931 ;
     RECT  29.415 36.887 33.642 38.101 ;
     RECT  2.304 37.733 5.886 38.129 ;
     RECT  6.732 37.931 8.19 38.129 ;
     RECT  29.34 38.101 33.642 38.155 ;
     RECT  2.304 38.129 5.706 38.189 ;
     RECT  6.804 38.129 7.002 38.189 ;
     RECT  6.804 38.189 6.858 38.237 ;
     RECT  29.34 38.155 34.362 38.281 ;
     RECT  29.016 38.281 34.362 38.309 ;
     RECT  7.815 38.129 8.19 38.399 ;
     RECT  29.016 38.309 33.642 38.399 ;
     RECT  4.896 38.189 5.706 38.435 ;
     RECT  2.304 38.189 3.942 38.983 ;
     RECT  6.84 38.237 6.858 38.983 ;
     RECT  6.84 38.983 7.002 39.053 ;
     RECT  2.304 38.983 4.014 39.091 ;
     RECT  4.896 38.435 5.454 39.091 ;
     RECT  2.304 39.091 5.454 39.181 ;
     RECT  0.216 39.115 0.234 39.245 ;
     RECT  2.304 39.181 5.634 39.253 ;
     RECT  6.84 39.053 6.894 39.253 ;
     RECT  29.415 38.399 33.642 39.353 ;
     RECT  7.815 38.399 8.097 39.631 ;
     RECT  7.815 39.631 8.19 39.901 ;
     RECT  9.144 39.829 9.162 39.929 ;
     RECT  29.415 39.353 32.49 40.075 ;
     RECT  33.552 39.353 33.642 40.075 ;
     RECT  2.304 39.253 6.894 40.171 ;
     RECT  7.776 39.901 8.19 40.171 ;
     RECT  0.252 40.267 0.27 40.397 ;
     RECT  2.304 40.171 6.966 40.405 ;
     RECT  7.74 40.171 8.19 40.405 ;
     RECT  2.304 40.405 8.19 40.441 ;
     RECT  29.415 40.075 33.642 40.441 ;
     RECT  29.376 40.441 33.642 40.567 ;
     RECT  29.196 40.567 33.642 40.603 ;
     RECT  2.304 40.441 8.586 40.739 ;
     RECT  29.196 40.603 33.678 40.739 ;
     RECT  2.304 40.739 7.074 40.829 ;
     RECT  7.815 40.739 8.586 40.981 ;
     RECT  2.304 40.829 6.93 41.099 ;
     RECT  7.815 40.981 8.73 41.099 ;
     RECT  10.515 34.151 10.797 41.179 ;
     RECT  6.768 41.099 6.93 41.207 ;
     RECT  29.415 40.739 33.678 41.371 ;
     RECT  6.84 41.207 6.93 41.611 ;
     RECT  7.815 41.099 8.097 41.611 ;
     RECT  8.82 41.107 8.91 41.647 ;
     RECT  8.82 41.647 9.27 41.747 ;
     RECT  10.515 41.179 10.926 41.819 ;
     RECT  26.715 16.439 26.997 41.881 ;
     RECT  6.84 41.611 8.097 41.909 ;
     RECT  26.715 41.881 27.054 41.981 ;
     RECT  29.415 41.371 33.714 42.089 ;
     RECT  2.304 41.099 5.922 42.151 ;
     RECT  8.928 41.747 8.946 42.179 ;
     RECT  2.304 42.151 6.282 42.251 ;
     RECT  2.304 42.251 3.51 42.601 ;
     RECT  4.284 42.251 6.282 42.763 ;
     RECT  7.272 41.909 8.097 42.763 ;
     RECT  4.284 42.763 8.097 43.141 ;
     RECT  2.268 42.601 3.51 43.231 ;
     RECT  4.284 43.141 8.514 43.231 ;
     RECT  2.268 43.231 8.514 43.259 ;
     RECT  29.415 42.089 33.678 43.373 ;
     RECT  2.268 43.259 8.097 43.529 ;
     RECT  2.268 43.529 6.066 43.565 ;
     RECT  6.84 43.529 8.097 43.907 ;
     RECT  33.588 43.373 33.678 44.045 ;
     RECT  7.815 43.907 8.097 44.059 ;
     RECT  29.415 43.373 32.397 44.155 ;
     RECT  7.815 44.059 8.406 44.221 ;
     RECT  2.304 43.565 6.066 44.311 ;
     RECT  6.84 43.907 6.858 44.311 ;
     RECT  9.36 44.221 9.378 44.339 ;
     RECT  2.304 44.311 6.858 44.381 ;
     RECT  29.415 44.155 32.49 44.491 ;
     RECT  33.588 44.045 33.642 44.609 ;
     RECT  29.376 44.491 32.49 44.617 ;
     RECT  7.815 44.221 8.586 44.761 ;
     RECT  33.624 44.609 33.642 44.779 ;
     RECT  9.576 44.419 9.594 44.789 ;
     RECT  6.912 44.761 6.93 44.879 ;
     RECT  28.98 44.617 32.49 44.879 ;
     RECT  0.216 44.779 0.234 44.909 ;
     RECT  2.304 44.381 5.922 44.915 ;
     RECT  7.815 44.761 8.694 44.951 ;
     RECT  7.815 44.951 8.226 44.971 ;
     RECT  33.624 44.779 33.678 44.971 ;
     RECT  3.96 44.915 5.922 45.121 ;
     RECT  3.96 45.121 6.354 45.257 ;
     RECT  4.14 45.257 6.354 45.419 ;
     RECT  7.128 44.971 8.226 45.419 ;
     RECT  29.088 44.879 32.49 45.491 ;
     RECT  2.304 44.915 3.186 45.643 ;
     RECT  10.515 41.819 10.797 45.661 ;
     RECT  4.14 45.419 6.21 45.689 ;
     RECT  7.128 45.419 8.154 45.761 ;
     RECT  10.515 45.661 10.926 45.761 ;
     RECT  2.304 45.643 3.402 45.841 ;
     RECT  33.624 44.971 33.714 45.869 ;
     RECT  2.268 45.841 3.402 45.965 ;
     RECT  29.415 45.491 32.49 46.075 ;
     RECT  2.304 45.965 3.402 46.111 ;
     RECT  4.14 45.689 6.066 46.111 ;
     RECT  34.344 45.931 34.362 46.229 ;
     RECT  29.415 46.075 33.138 46.273 ;
     RECT  28.764 46.273 33.138 46.499 ;
     RECT  7.128 45.761 8.118 46.507 ;
     RECT  7.128 46.507 8.298 46.579 ;
     RECT  29.304 46.499 33.138 46.747 ;
     RECT  7.128 46.579 8.586 46.781 ;
     RECT  29.304 46.747 33.606 46.841 ;
     RECT  29.304 46.841 32.526 46.877 ;
     RECT  33.552 46.841 33.606 46.891 ;
     RECT  7.74 46.781 8.586 46.949 ;
     RECT  29.304 46.877 32.49 47.039 ;
     RECT  21.315 2.413 21.597 47.083 ;
     RECT  33.552 46.891 33.642 47.083 ;
     RECT  2.304 46.111 6.066 47.191 ;
     RECT  6.84 47.155 6.858 47.191 ;
     RECT  14.832 47.083 14.85 47.213 ;
     RECT  21.315 47.083 21.69 47.213 ;
     RECT  22.824 47.083 22.842 47.213 ;
     RECT  33.552 47.083 33.678 47.261 ;
     RECT  33.588 47.261 33.678 47.489 ;
     RECT  2.304 47.191 6.858 47.563 ;
     RECT  33.588 47.489 33.642 47.579 ;
     RECT  2.268 47.563 6.858 47.731 ;
     RECT  7.74 46.949 8.097 47.731 ;
     RECT  29.415 47.039 32.49 47.857 ;
     RECT  2.268 47.731 8.097 47.885 ;
     RECT  29.376 47.857 32.49 47.957 ;
     RECT  9.072 47.281 9.09 48.029 ;
     RECT  33.624 47.579 33.642 48.077 ;
     RECT  29.415 47.957 32.49 48.523 ;
     RECT  29.415 48.523 32.886 48.541 ;
     RECT  2.304 47.885 8.097 48.845 ;
     RECT  29.415 48.541 33.102 48.859 ;
     RECT  2.304 48.845 6.102 48.929 ;
     RECT  4.356 48.929 6.102 49.073 ;
     RECT  29.415 48.859 33.642 49.109 ;
     RECT  33.588 49.109 33.642 49.307 ;
     RECT  7.056 48.845 8.097 49.441 ;
     RECT  4.392 49.073 6.102 49.579 ;
     RECT  7.056 49.441 8.262 49.579 ;
     RECT  2.304 48.929 3.618 49.891 ;
     RECT  4.392 49.579 8.262 49.891 ;
     RECT  2.304 49.891 8.442 49.981 ;
     RECT  2.304 49.981 9.162 50.081 ;
     RECT  2.304 50.081 6.462 50.152 ;
     RECT  9.036 50.081 9.162 50.153 ;
     RECT  33.588 49.307 33.606 50.155 ;
     RECT  7.416 50.081 8.262 50.279 ;
     RECT  9.108 50.153 9.162 50.279 ;
     RECT  9.144 50.279 9.162 50.459 ;
     RECT  0.252 50.491 0.27 50.621 ;
     RECT  33.588 50.155 33.678 50.635 ;
     RECT  2.268 50.152 6.462 50.827 ;
     RECT  7.416 50.279 8.154 50.827 ;
     RECT  28.512 50.701 28.53 50.855 ;
     RECT  2.268 50.827 8.154 50.963 ;
     RECT  33.588 50.635 33.75 50.999 ;
     RECT  29.415 49.109 32.49 51.307 ;
     RECT  33.588 50.999 33.714 51.307 ;
     RECT  2.304 50.963 8.154 51.431 ;
     RECT  29.415 51.307 33.714 51.787 ;
     RECT  26.715 41.981 26.997 51.943 ;
     RECT  9.144 51.601 9.162 52.079 ;
     RECT  29.415 51.787 34.362 52.079 ;
     RECT  29.415 52.079 33.678 52.277 ;
     RECT  26.715 51.943 27.054 52.349 ;
     RECT  2.304 51.431 8.097 52.411 ;
     RECT  2.268 52.411 8.097 52.583 ;
     RECT  2.304 52.583 8.097 52.591 ;
     RECT  28.512 52.249 28.53 52.619 ;
     RECT  2.304 52.591 8.334 52.853 ;
     RECT  0.216 52.075 0.234 52.987 ;
     RECT  0.216 52.987 0.27 53.021 ;
     RECT  2.304 52.853 8.19 53.051 ;
     RECT  0.252 53.021 0.27 53.117 ;
     RECT  2.304 53.051 6.03 53.519 ;
     RECT  6.768 53.051 8.19 53.519 ;
     RECT  6.768 53.519 8.097 53.789 ;
     RECT  29.415 52.277 33.642 53.933 ;
     RECT  9 53.869 9.018 53.941 ;
     RECT  2.304 53.519 5.922 54.043 ;
     RECT  6.948 53.789 8.097 54.059 ;
     RECT  9 53.941 9.126 54.059 ;
     RECT  33.588 53.933 33.642 54.077 ;
     RECT  9.072 54.059 9.126 54.131 ;
     RECT  9.108 54.131 9.126 54.175 ;
     RECT  9.108 54.175 9.198 54.329 ;
     RECT  2.268 54.043 5.922 54.365 ;
     RECT  33.624 54.077 33.642 54.379 ;
     RECT  2.304 54.365 5.922 54.409 ;
     RECT  2.304 54.409 6.03 54.571 ;
     RECT  2.304 54.571 6.102 54.643 ;
     RECT  29.415 53.933 32.397 54.715 ;
     RECT  33.624 54.379 33.714 54.779 ;
     RECT  29.415 54.715 32.526 54.859 ;
     RECT  33.624 54.779 33.678 54.859 ;
     RECT  7.128 54.059 8.097 54.949 ;
     RECT  29.415 54.859 33.678 55.013 ;
     RECT  28.512 54.877 28.53 55.183 ;
     RECT  7.128 54.949 8.478 55.255 ;
     RECT  28.512 55.183 28.566 55.283 ;
     RECT  28.512 55.283 28.53 55.319 ;
     RECT  0.54 54.985 0.558 55.373 ;
     RECT  7.128 55.255 8.622 55.445 ;
     RECT  7.128 55.445 8.19 55.489 ;
     RECT  24.015 2.413 24.297 55.489 ;
     RECT  7.056 55.489 8.19 55.613 ;
     RECT  2.304 54.643 6.138 55.751 ;
     RECT  3.636 55.751 6.138 55.831 ;
     RECT  6.948 55.675 6.966 55.831 ;
     RECT  9.216 55.831 9.234 55.949 ;
     RECT  7.815 55.613 8.19 56.057 ;
     RECT  2.304 55.751 2.862 56.155 ;
     RECT  2.268 56.155 2.862 56.255 ;
     RECT  3.636 55.831 6.966 56.371 ;
     RECT  7.815 56.057 8.097 56.371 ;
     RECT  33.624 55.013 33.678 56.491 ;
     RECT  24.015 55.489 24.534 56.561 ;
     RECT  33.588 56.491 33.678 56.635 ;
     RECT  2.304 56.255 2.862 56.641 ;
     RECT  3.636 56.371 8.097 56.641 ;
     RECT  9.108 56.641 9.126 56.831 ;
     RECT  2.304 56.641 8.097 56.911 ;
     RECT  29.415 55.013 32.49 57.115 ;
     RECT  33.588 56.635 33.714 57.115 ;
     RECT  29.415 57.115 33.714 57.173 ;
     RECT  25.092 56.803 25.11 57.209 ;
     RECT  2.304 56.911 8.298 57.299 ;
     RECT  0.252 57.355 0.27 57.485 ;
     RECT  2.304 57.299 8.097 57.485 ;
     RECT  29.415 57.173 33.102 57.685 ;
     RECT  29.268 57.685 33.102 57.983 ;
     RECT  27.936 57.307 27.954 58.109 ;
     RECT  29.268 57.983 32.562 58.109 ;
     RECT  2.304 57.485 6.678 58.217 ;
     RECT  6.156 58.217 6.678 58.225 ;
     RECT  6.156 58.225 6.93 58.423 ;
     RECT  7.815 57.485 8.097 58.423 ;
     RECT  9.36 58.459 9.378 58.649 ;
     RECT  29.415 58.109 32.562 58.747 ;
     RECT  33.588 58.261 33.642 58.747 ;
     RECT  2.304 58.217 5.397 58.891 ;
     RECT  2.268 58.891 5.397 58.963 ;
     RECT  6.156 58.423 8.097 58.963 ;
     RECT  2.268 58.963 8.586 59.071 ;
     RECT  2.268 59.071 8.838 59.099 ;
     RECT  2.304 59.099 8.838 59.189 ;
     RECT  29.415 58.747 33.642 59.227 ;
     RECT  2.304 59.189 8.586 59.567 ;
     RECT  29.415 59.227 33.678 59.567 ;
     RECT  29.415 59.567 32.49 59.809 ;
     RECT  33.588 59.567 33.678 59.999 ;
     RECT  2.304 59.567 8.514 60.179 ;
     RECT  2.304 60.179 8.154 60.413 ;
     RECT  2.304 60.413 3.042 60.523 ;
     RECT  9.36 60.385 9.378 60.583 ;
     RECT  2.268 60.523 3.042 60.683 ;
     RECT  2.304 60.683 3.042 60.809 ;
     RECT  29.376 59.809 32.49 60.853 ;
     RECT  33.624 59.999 33.678 60.859 ;
     RECT  9.144 60.583 9.378 60.881 ;
     RECT  33.624 60.859 33.714 60.889 ;
     RECT  29.088 60.853 32.49 60.925 ;
     RECT  3.996 60.413 8.154 60.961 ;
     RECT  9.144 60.881 9.198 60.961 ;
     RECT  3.996 60.961 9.198 60.989 ;
     RECT  33.624 60.889 33.75 61.037 ;
     RECT  29.016 60.925 32.49 61.079 ;
     RECT  33.624 61.037 33.714 61.151 ;
     RECT  3.996 60.989 7.038 61.231 ;
     RECT  3.816 61.231 7.038 61.259 ;
     RECT  7.815 60.989 9.198 61.349 ;
     RECT  10.515 45.761 10.797 61.357 ;
     RECT  3.816 61.259 5.958 61.531 ;
     RECT  29.415 61.079 32.49 61.531 ;
     RECT  33.624 61.151 33.678 61.531 ;
     RECT  7.815 61.349 9.162 61.691 ;
     RECT  7.815 61.691 8.586 61.727 ;
     RECT  6.804 61.259 7.038 61.735 ;
     RECT  7.815 61.727 8.19 61.735 ;
     RECT  2.304 60.809 2.697 61.771 ;
     RECT  3.492 61.531 5.958 61.771 ;
     RECT  6.804 61.735 8.19 61.889 ;
     RECT  10.515 61.357 11.43 61.961 ;
     RECT  29.415 61.531 33.678 62.011 ;
     RECT  26.715 52.349 26.997 62.131 ;
     RECT  6.804 61.889 7.002 62.311 ;
     RECT  29.415 62.011 33.714 62.401 ;
     RECT  2.304 61.771 5.958 62.509 ;
     RECT  6.768 62.311 7.002 62.509 ;
     RECT  26.715 62.131 27.054 62.609 ;
     RECT  29.232 62.401 33.714 62.609 ;
     RECT  0.252 62.539 0.27 62.669 ;
     RECT  29.232 62.609 33.642 62.671 ;
     RECT  2.304 62.509 7.002 62.699 ;
     RECT  29.16 62.671 33.642 62.807 ;
     RECT  7.815 61.889 8.097 62.851 ;
     RECT  8.82 62.509 8.838 62.851 ;
     RECT  27.972 62.437 27.99 62.879 ;
     RECT  7.2 62.851 8.838 62.969 ;
     RECT  2.304 62.699 6.21 63.112 ;
     RECT  2.268 63.112 6.21 63.239 ;
     RECT  2.304 63.239 6.21 63.739 ;
     RECT  7.2 62.969 8.097 63.739 ;
     RECT  2.304 63.739 8.097 63.931 ;
     RECT  9.54 63.751 9.558 64.049 ;
     RECT  29.415 62.807 33.642 64.123 ;
     RECT  2.304 63.931 8.406 64.201 ;
     RECT  29.415 64.123 34.362 64.229 ;
     RECT  2.304 64.201 8.586 64.267 ;
     RECT  2.268 64.267 8.586 64.427 ;
     RECT  2.304 64.427 8.586 64.697 ;
     RECT  2.304 64.697 8.097 64.859 ;
     RECT  9.432 64.741 9.45 64.931 ;
     RECT  29.415 64.229 33.678 64.967 ;
     RECT  6.228 64.859 8.097 65.129 ;
     RECT  33.588 64.967 33.678 65.129 ;
     RECT  6.264 65.129 8.097 65.237 ;
     RECT  10.515 61.961 10.797 65.281 ;
     RECT  10.515 65.281 10.818 65.399 ;
     RECT  6.444 65.237 8.097 65.669 ;
     RECT  6.624 65.669 8.097 65.911 ;
     RECT  2.304 64.859 5.49 66.055 ;
     RECT  29.415 64.967 32.526 66.235 ;
     RECT  33.624 65.129 33.678 66.235 ;
     RECT  6.624 65.911 8.586 66.281 ;
     RECT  29.415 66.235 33.678 66.317 ;
     RECT  0.252 66.379 0.27 66.509 ;
     RECT  6.624 66.281 8.334 66.515 ;
     RECT  2.304 66.055 5.742 66.631 ;
     RECT  29.415 66.317 33.642 66.659 ;
     RECT  33.588 66.659 33.642 66.749 ;
     RECT  2.304 66.631 5.85 66.901 ;
     RECT  9.684 66.289 9.702 66.901 ;
     RECT  9.108 66.901 9.702 66.929 ;
     RECT  0.216 67.003 0.234 67.133 ;
     RECT  2.304 66.901 5.886 67.135 ;
     RECT  6.624 66.515 6.966 67.135 ;
     RECT  9.108 66.929 9.126 67.289 ;
     RECT  10.515 65.399 10.797 67.369 ;
     RECT  7.74 66.515 8.298 67.441 ;
     RECT  10.515 67.369 10.926 67.469 ;
     RECT  2.304 67.135 6.966 67.531 ;
     RECT  33.624 66.749 33.642 67.531 ;
     RECT  2.268 67.531 6.966 67.703 ;
     RECT  2.304 67.703 6.966 67.711 ;
     RECT  7.74 67.441 8.586 67.711 ;
     RECT  9.468 67.675 9.486 67.829 ;
     RECT  33.588 67.531 33.642 67.829 ;
     RECT  2.304 67.711 8.586 68.405 ;
     RECT  33.624 67.829 33.642 68.635 ;
     RECT  29.415 66.659 32.526 68.719 ;
     RECT  33.588 68.635 33.642 68.719 ;
     RECT  3.528 68.405 8.586 69.061 ;
     RECT  3.528 69.061 8.73 69.089 ;
     RECT  7.815 69.089 8.73 69.179 ;
     RECT  2.304 68.405 2.697 69.211 ;
     RECT  3.528 69.089 7.074 69.421 ;
     RECT  9.612 69.295 9.63 69.449 ;
     RECT  2.304 69.211 2.754 69.565 ;
     RECT  3.492 69.421 7.074 69.565 ;
     RECT  10.515 67.469 10.797 69.727 ;
     RECT  29.415 68.719 33.642 69.787 ;
     RECT  10.515 69.727 10.854 69.899 ;
     RECT  29.415 69.787 33.714 69.899 ;
     RECT  2.304 69.565 7.074 70.025 ;
     RECT  7.815 69.179 8.406 70.033 ;
     RECT  0.54 70.069 0.558 70.157 ;
     RECT  2.34 70.025 7.074 70.219 ;
     RECT  7.815 70.033 8.694 70.219 ;
     RECT  2.34 70.219 8.694 70.259 ;
     RECT  33.624 69.899 33.714 70.403 ;
     RECT  7.815 70.259 8.694 70.439 ;
     RECT  0.252 70.411 0.27 70.589 ;
     RECT  2.34 70.259 6.93 70.747 ;
     RECT  29.415 69.899 32.562 70.747 ;
     RECT  33.624 70.403 33.642 70.747 ;
     RECT  7.815 70.439 8.622 70.799 ;
     RECT  10.515 69.899 10.797 70.807 ;
     RECT  10.515 70.807 10.818 70.907 ;
     RECT  2.304 70.747 6.93 71.185 ;
     RECT  29.415 70.747 33.642 71.227 ;
     RECT  2.304 71.185 7.002 71.323 ;
     RECT  7.815 70.799 8.097 71.323 ;
     RECT  2.304 71.323 8.097 71.717 ;
     RECT  2.304 71.717 3.654 71.789 ;
     RECT  4.392 71.717 8.097 71.789 ;
     RECT  6.768 71.789 8.097 71.879 ;
     RECT  4.392 71.789 5.562 71.915 ;
     RECT  2.304 71.789 2.697 72.379 ;
     RECT  26.715 62.609 26.997 72.427 ;
     RECT  2.268 72.379 2.697 72.527 ;
     RECT  29.415 71.227 33.678 72.563 ;
     RECT  7.272 71.879 8.097 72.571 ;
     RECT  4.428 71.915 5.562 72.667 ;
     RECT  7.272 72.571 8.154 72.667 ;
     RECT  21.315 47.213 21.597 72.667 ;
     RECT  6.948 72.667 8.19 72.725 ;
     RECT  26.715 72.427 27.054 72.761 ;
     RECT  14.832 72.667 14.85 72.797 ;
     RECT  21.315 72.667 21.69 72.797 ;
     RECT  22.824 72.667 22.842 72.797 ;
     RECT  3.42 71.789 3.654 72.841 ;
     RECT  4.428 72.667 5.886 72.841 ;
     RECT  29.415 72.563 33.606 72.893 ;
     RECT  7.092 72.725 8.19 72.959 ;
     RECT  3.42 72.841 5.886 72.995 ;
     RECT  2.304 72.527 2.697 73.003 ;
     RECT  3.42 72.995 4.05 73.003 ;
     RECT  5.076 72.995 5.886 73.031 ;
     RECT  7.2 72.959 8.19 73.111 ;
     RECT  5.115 73.031 5.886 73.201 ;
     RECT  33.588 72.893 33.606 73.339 ;
     RECT  7.2 73.111 8.694 73.373 ;
     RECT  29.415 72.893 32.526 73.651 ;
     RECT  33.588 73.339 33.642 73.651 ;
     RECT  7.2 73.373 8.622 73.769 ;
     RECT  2.304 73.003 4.05 73.771 ;
     RECT  5.115 73.201 6.102 73.771 ;
     RECT  7.2 73.769 8.406 73.885 ;
     RECT  6.912 73.885 8.406 74.011 ;
     RECT  2.304 73.771 6.102 74.083 ;
     RECT  6.84 74.011 8.406 74.083 ;
     RECT  29.415 73.651 33.642 74.299 ;
     RECT  2.304 74.083 8.406 74.417 ;
     RECT  28.512 74.083 28.53 74.489 ;
     RECT  7.815 74.417 8.406 74.551 ;
     RECT  0.252 74.491 0.27 74.621 ;
     RECT  2.304 74.417 6.93 74.669 ;
     RECT  7.815 74.551 8.586 74.849 ;
     RECT  9.324 74.857 9.342 74.957 ;
     RECT  29.415 74.299 33.678 75.115 ;
     RECT  2.304 74.669 6.786 75.227 ;
     RECT  9.36 75.001 9.378 75.299 ;
     RECT  29.415 75.115 33.714 75.497 ;
     RECT  3.708 75.227 6.786 75.541 ;
     RECT  3.708 75.541 6.966 75.811 ;
     RECT  7.815 74.849 8.097 75.811 ;
     RECT  3.708 75.811 8.298 76.045 ;
     RECT  3.708 76.045 8.73 76.109 ;
     RECT  3.708 76.109 6.03 76.199 ;
     RECT  2.304 75.227 2.934 76.219 ;
     RECT  3.708 76.199 5.958 76.219 ;
     RECT  0.252 76.123 0.27 76.253 ;
     RECT  29.415 75.497 33.642 76.379 ;
     RECT  2.304 76.219 5.958 76.397 ;
     RECT  29.415 76.379 32.49 76.441 ;
     RECT  6.948 76.109 8.73 76.541 ;
     RECT  2.304 76.397 5.922 76.603 ;
     RECT  6.948 76.541 8.622 76.649 ;
     RECT  29.304 76.441 32.49 76.739 ;
     RECT  2.268 76.603 5.922 76.775 ;
     RECT  6.948 76.649 8.586 76.981 ;
     RECT  33.588 76.379 33.642 77.083 ;
     RECT  2.304 76.775 5.922 77.125 ;
     RECT  2.304 77.125 6.03 77.161 ;
     RECT  6.84 76.981 8.586 77.161 ;
     RECT  29.415 76.739 32.49 77.161 ;
     RECT  33.588 77.083 33.714 77.161 ;
     RECT  29.415 77.161 33.714 77.261 ;
     RECT  33.624 77.261 33.714 77.657 ;
     RECT  33.624 77.657 33.678 77.693 ;
     RECT  2.304 77.161 8.586 77.819 ;
     RECT  7.164 77.819 8.586 77.827 ;
     RECT  33.624 77.693 33.642 77.999 ;
     RECT  29.415 77.261 32.49 78.043 ;
     RECT  7.164 77.827 9.198 78.221 ;
     RECT  29.415 78.043 32.526 78.235 ;
     RECT  13.215 2.413 13.497 78.331 ;
     RECT  21.315 72.797 21.597 78.331 ;
     RECT  26.715 72.761 26.997 78.331 ;
     RECT  9.108 78.221 9.198 78.359 ;
     RECT  13.104 78.331 13.497 78.368 ;
     RECT  21.204 78.331 21.597 78.368 ;
     RECT  29.415 78.235 32.886 78.379 ;
     RECT  14.832 78.331 14.85 78.461 ;
     RECT  26.676 78.331 26.997 78.461 ;
     RECT  2.304 77.819 6.39 78.629 ;
     RECT  7.164 78.221 8.37 78.637 ;
     RECT  0.216 78.523 0.234 78.653 ;
     RECT  29.415 78.379 33.102 78.859 ;
     RECT  0.252 78.859 0.27 78.989 ;
     RECT  29.415 78.859 33.642 79.003 ;
     RECT  6.768 78.637 8.37 79.079 ;
     RECT  2.304 78.629 5.958 79.169 ;
     RECT  7.74 79.079 8.37 79.169 ;
     RECT  7.74 79.169 8.19 79.205 ;
     RECT  29.415 79.003 33.678 79.241 ;
     RECT  2.304 79.169 5.922 79.325 ;
     RECT  29.415 79.241 32.526 79.373 ;
     RECT  9.324 79.321 9.414 79.439 ;
     RECT  29.415 79.373 32.397 79.555 ;
     RECT  6.768 79.079 7.002 79.619 ;
     RECT  29.34 79.555 32.397 79.709 ;
     RECT  6.876 79.619 7.002 79.852 ;
     RECT  7.74 79.205 8.097 79.852 ;
     RECT  6.876 79.852 8.097 79.979 ;
     RECT  7.02 79.979 8.097 80.123 ;
     RECT  29.415 79.709 32.397 80.155 ;
     RECT  33.588 79.241 33.678 80.155 ;
     RECT  0.216 80.155 0.234 80.285 ;
     RECT  2.304 79.325 5.814 80.347 ;
     RECT  29.415 80.155 33.678 80.347 ;
     RECT  29.415 80.347 33.714 80.357 ;
     RECT  2.304 80.347 6.03 80.491 ;
     RECT  2.268 80.491 6.03 80.555 ;
     RECT  7.056 80.123 8.097 80.563 ;
     RECT  8.82 80.131 8.838 80.563 ;
     RECT  33.588 80.357 33.714 80.591 ;
     RECT  7.056 80.563 8.838 80.699 ;
     RECT  2.268 80.555 2.697 80.825 ;
     RECT  3.528 80.555 6.03 80.869 ;
     RECT  33.588 80.591 33.678 81.005 ;
     RECT  33.588 81.005 33.642 81.203 ;
     RECT  3.528 80.869 6.282 81.211 ;
     RECT  7.056 80.699 8.19 81.211 ;
     RECT  29.415 80.357 32.397 81.307 ;
     RECT  33.588 81.203 33.606 81.329 ;
     RECT  2.304 80.825 2.697 81.373 ;
     RECT  3.528 81.211 8.19 81.373 ;
     RECT  24.015 56.561 24.297 81.409 ;
     RECT  29.415 81.307 32.49 81.409 ;
     RECT  2.304 81.373 8.19 81.481 ;
     RECT  2.304 81.481 8.37 81.485 ;
     RECT  29.415 81.409 32.562 81.485 ;
     RECT  6.876 81.485 8.37 81.509 ;
     RECT  24.015 81.409 24.534 81.779 ;
     RECT  2.304 81.485 5.922 81.821 ;
     RECT  7.815 81.509 8.37 82.021 ;
     RECT  6.876 81.509 6.966 82.139 ;
     RECT  6.948 82.139 6.966 82.291 ;
     RECT  7.815 82.021 8.586 82.291 ;
     RECT  29.415 81.485 32.526 82.489 ;
     RECT  33.624 81.931 33.642 82.489 ;
     RECT  6.948 82.291 8.586 82.553 ;
     RECT  7.815 82.553 8.586 82.561 ;
     RECT  0.216 82.507 0.234 82.637 ;
     RECT  10.515 70.907 10.797 82.687 ;
     RECT  28.764 82.489 32.526 82.759 ;
     RECT  28.512 82.759 32.526 82.787 ;
     RECT  2.304 81.821 5.814 82.831 ;
     RECT  7.815 82.561 8.946 82.921 ;
     RECT  33.624 82.489 33.678 82.939 ;
     RECT  33.588 82.939 33.678 83.083 ;
     RECT  7.815 82.921 8.982 83.101 ;
     RECT  28.512 82.787 28.53 83.291 ;
     RECT  7.815 83.101 9.27 83.497 ;
     RECT  29.415 82.787 32.526 83.605 ;
     RECT  33.588 83.083 34.362 83.605 ;
     RECT  2.304 82.831 6.03 83.611 ;
     RECT  6.84 82.987 6.858 83.611 ;
     RECT  7.815 83.497 9.45 83.641 ;
     RECT  10.515 82.687 10.854 83.669 ;
     RECT  7.632 83.641 9.45 83.911 ;
     RECT  29.415 83.605 34.362 83.939 ;
     RECT  7.632 83.911 9.522 84.029 ;
     RECT  7.632 84.029 8.91 84.101 ;
     RECT  2.304 83.611 6.858 84.139 ;
     RECT  7.632 84.101 8.097 84.139 ;
     RECT  26.715 78.461 26.997 84.139 ;
     RECT  33.624 83.939 34.362 84.209 ;
     RECT  13.215 78.368 13.497 84.271 ;
     RECT  21.315 78.368 21.597 84.271 ;
     RECT  2.304 84.139 8.097 84.299 ;
     RECT  26.676 84.139 26.997 84.299 ;
     RECT  14.832 84.139 14.85 84.317 ;
     RECT  21.204 84.271 21.597 84.317 ;
     RECT  13.104 84.271 13.497 84.343 ;
     RECT  8.892 84.101 8.91 84.371 ;
     RECT  6.912 84.299 8.097 84.479 ;
     RECT  12.564 84.343 13.497 84.479 ;
     RECT  29.415 83.939 32.49 84.541 ;
     RECT  29.196 84.541 32.49 84.713 ;
     RECT  29.376 84.713 32.49 84.839 ;
     RECT  33.624 84.209 33.678 85.051 ;
     RECT  33.624 85.051 33.714 85.217 ;
     RECT  2.304 84.299 5.922 85.225 ;
     RECT  25.128 85.153 25.146 85.289 ;
     RECT  2.304 85.225 6.354 85.339 ;
     RECT  2.268 85.339 6.354 85.351 ;
     RECT  7.092 84.479 8.097 85.351 ;
     RECT  2.268 85.351 8.097 85.421 ;
     RECT  29.415 84.839 32.49 85.675 ;
     RECT  33.624 85.217 33.678 85.675 ;
     RECT  2.268 85.421 3.222 85.685 ;
     RECT  3.996 85.421 8.097 85.729 ;
     RECT  29.415 85.675 33.678 85.793 ;
     RECT  3.996 85.729 8.19 85.801 ;
     RECT  3.996 85.801 8.334 85.919 ;
     RECT  0.216 85.819 0.234 85.949 ;
     RECT  10.515 83.669 10.797 85.963 ;
     RECT  33.588 85.793 33.678 86.011 ;
     RECT  10.515 85.963 10.818 86.063 ;
     RECT  33.588 86.011 34.362 86.099 ;
     RECT  33.588 86.099 33.642 86.297 ;
     RECT  2.304 85.685 3.222 86.305 ;
     RECT  3.996 85.919 8.154 86.305 ;
     RECT  2.304 86.305 8.154 86.459 ;
     RECT  7.704 86.459 8.154 86.477 ;
     RECT  3.888 86.459 6.966 86.639 ;
     RECT  7.815 86.477 8.154 86.971 ;
     RECT  33.588 86.297 33.606 86.971 ;
     RECT  0.252 86.971 0.27 87.101 ;
     RECT  33.552 86.971 33.606 87.115 ;
     RECT  7.815 86.971 8.262 87.269 ;
     RECT  25.092 86.737 25.11 87.277 ;
     RECT  25.092 87.277 25.146 87.376 ;
     RECT  2.304 86.459 3.114 87.421 ;
     RECT  3.888 86.639 6.642 87.421 ;
     RECT  29.415 85.793 32.526 87.451 ;
     RECT  33.552 87.115 33.642 87.451 ;
     RECT  2.304 87.421 7.002 87.511 ;
     RECT  7.815 87.269 8.154 87.511 ;
     RECT  2.304 87.511 8.154 87.581 ;
     RECT  3.636 87.581 8.154 87.611 ;
     RECT  8.892 87.385 8.982 87.611 ;
     RECT  3.636 87.611 6.822 87.809 ;
     RECT  9.432 87.691 9.45 87.809 ;
     RECT  28.512 87.151 28.53 87.989 ;
     RECT  29.415 87.451 33.642 88.051 ;
     RECT  7.632 87.611 8.154 88.079 ;
     RECT  3.636 87.809 6.462 88.115 ;
     RECT  7.668 88.079 8.154 88.195 ;
     RECT  3.636 88.115 6.282 88.321 ;
     RECT  7.668 88.195 8.298 88.349 ;
     RECT  28.908 88.051 33.642 88.349 ;
     RECT  7.668 88.349 8.154 88.397 ;
     RECT  2.304 87.581 2.697 88.735 ;
     RECT  3.42 88.321 6.282 88.735 ;
     RECT  7.668 88.397 8.097 88.861 ;
     RECT  25.092 87.376 25.182 88.889 ;
     RECT  7.524 88.861 8.097 88.897 ;
     RECT  25.164 88.889 25.182 88.925 ;
     RECT  10.515 86.063 10.797 89.005 ;
     RECT  10.515 89.005 10.818 89.159 ;
     RECT  29.415 88.349 33.642 89.159 ;
     RECT  2.304 88.735 6.282 89.203 ;
     RECT  7.488 88.897 8.097 89.203 ;
     RECT  33.588 89.159 33.642 89.303 ;
     RECT  29.415 89.159 32.526 89.311 ;
     RECT  2.304 89.203 8.097 89.509 ;
     RECT  2.304 89.509 8.802 89.581 ;
     RECT  2.304 89.581 9.054 89.699 ;
     RECT  28.512 89.401 28.53 89.707 ;
     RECT  29.34 89.311 32.526 89.707 ;
     RECT  2.304 89.699 8.097 89.741 ;
     RECT  9.036 89.699 9.054 89.851 ;
     RECT  28.512 89.707 32.526 89.879 ;
     RECT  28.908 89.879 32.526 89.899 ;
     RECT  33.588 89.303 33.606 89.899 ;
     RECT  4.392 89.741 8.097 89.969 ;
     RECT  9.036 89.851 9.162 89.969 ;
     RECT  28.908 89.899 33.606 89.969 ;
     RECT  29.415 89.969 33.606 90.043 ;
     RECT  4.392 89.969 7.038 90.557 ;
     RECT  2.304 89.741 3.546 90.589 ;
     RECT  4.392 90.557 6.426 90.589 ;
     RECT  2.304 90.589 6.426 90.617 ;
     RECT  7.815 89.969 8.097 90.661 ;
     RECT  29.415 90.043 33.642 90.661 ;
     RECT  2.304 90.617 6.354 90.715 ;
     RECT  7.815 90.661 8.406 90.779 ;
     RECT  2.268 90.715 6.354 90.923 ;
     RECT  7.815 90.779 8.097 90.931 ;
     RECT  2.304 90.923 6.354 91.049 ;
     RECT  29.415 90.661 33.714 91.085 ;
     RECT  6.336 91.049 6.354 91.121 ;
     RECT  6.588 91.435 6.606 91.471 ;
     RECT  7.416 90.931 8.097 91.471 ;
     RECT  6.588 91.471 8.097 91.561 ;
     RECT  9.504 91.471 9.522 91.589 ;
     RECT  2.304 91.049 5.598 91.625 ;
     RECT  6.588 91.561 8.478 91.661 ;
     RECT  10.515 89.159 10.797 91.669 ;
     RECT  6.588 91.661 8.298 91.709 ;
     RECT  10.515 91.669 10.818 91.769 ;
     RECT  29.415 91.085 33.642 91.819 ;
     RECT  6.588 91.709 8.097 91.867 ;
     RECT  4.14 91.625 5.598 91.975 ;
     RECT  6.408 91.867 8.097 91.975 ;
     RECT  4.14 91.975 8.097 92.039 ;
     RECT  4.14 92.039 6.93 92.273 ;
     RECT  2.304 91.625 3.366 92.347 ;
     RECT  4.14 92.273 5.922 92.347 ;
     RECT  0.252 91.531 0.27 92.477 ;
     RECT  2.304 92.347 5.922 92.477 ;
     RECT  2.304 92.477 5.85 92.827 ;
     RECT  29.415 91.819 33.678 92.827 ;
     RECT  29.415 92.827 34.362 92.849 ;
     RECT  6.84 92.273 6.93 92.923 ;
     RECT  7.776 92.039 8.097 92.923 ;
     RECT  26.715 84.299 26.997 93.019 ;
     RECT  34.344 92.849 34.362 93.083 ;
     RECT  6.84 92.923 8.097 93.091 ;
     RECT  2.268 92.827 5.85 93.211 ;
     RECT  0.216 93.115 0.234 93.245 ;
     RECT  6.84 93.091 8.37 93.281 ;
     RECT  26.715 93.019 27.054 93.389 ;
     RECT  9.072 93.361 9.09 93.479 ;
     RECT  2.268 93.211 6.03 93.515 ;
     RECT  6.84 93.281 8.097 93.523 ;
     RECT  2.304 93.515 6.03 93.533 ;
     RECT  2.304 93.533 4.086 93.785 ;
     RECT  4.932 93.533 6.03 93.829 ;
     RECT  6.804 93.523 8.097 93.829 ;
     RECT  2.304 93.785 3.978 94.055 ;
     RECT  29.415 92.849 33.606 94.099 ;
     RECT  0.216 94.027 0.234 94.157 ;
     RECT  4.932 93.829 8.097 94.171 ;
     RECT  4.932 94.171 8.514 94.267 ;
     RECT  29.415 94.099 33.642 94.459 ;
     RECT  4.824 94.267 8.514 94.469 ;
     RECT  4.824 94.469 8.442 94.531 ;
     RECT  4.716 94.531 8.442 94.631 ;
     RECT  0.252 94.603 0.27 94.733 ;
     RECT  29.415 94.459 33.678 94.781 ;
     RECT  2.304 94.055 3.942 94.945 ;
     RECT  4.716 94.631 8.097 94.945 ;
     RECT  2.304 94.945 8.097 95.083 ;
     RECT  2.268 95.083 8.097 95.171 ;
     RECT  2.268 95.171 3.186 95.207 ;
     RECT  33.588 94.781 33.678 95.227 ;
     RECT  9.18 95.215 9.198 95.369 ;
     RECT  4.212 95.171 8.097 95.611 ;
     RECT  4.212 95.611 9.126 95.747 ;
     RECT  33.588 95.227 33.714 95.819 ;
     RECT  26.715 93.389 26.997 95.881 ;
     RECT  7.74 95.747 8.586 95.909 ;
     RECT  33.588 95.819 33.642 95.933 ;
     RECT  29.415 94.781 32.49 96.025 ;
     RECT  2.304 95.207 3.186 96.043 ;
     RECT  2.268 96.043 3.186 96.061 ;
     RECT  26.715 95.881 27.054 96.089 ;
     RECT  4.212 95.747 6.966 96.179 ;
     RECT  7.74 95.909 8.118 96.179 ;
     RECT  2.268 96.061 3.366 96.187 ;
     RECT  4.212 96.179 6.498 96.187 ;
     RECT  2.268 96.187 6.498 96.269 ;
     RECT  7.815 96.179 8.118 96.323 ;
     RECT  3.564 96.269 6.498 96.449 ;
     RECT  2.268 96.269 2.826 96.461 ;
     RECT  2.268 96.461 2.697 96.485 ;
     RECT  9.036 96.529 9.054 96.601 ;
     RECT  9.036 96.601 9.126 96.629 ;
     RECT  29.415 96.025 33.102 96.715 ;
     RECT  9.108 96.629 9.126 96.719 ;
     RECT  29.415 96.715 33.606 96.859 ;
     RECT  29.415 96.859 33.642 97.051 ;
     RECT  3.708 96.449 6.498 97.141 ;
     RECT  7.815 96.323 8.097 97.141 ;
     RECT  3.708 97.141 6.93 97.195 ;
     RECT  7.815 97.141 8.37 97.195 ;
     RECT  3.708 97.195 8.37 97.259 ;
     RECT  2.304 96.485 2.697 97.291 ;
     RECT  0.252 97.195 0.27 97.325 ;
     RECT  29.415 97.051 33.678 97.439 ;
     RECT  6.804 97.259 8.37 97.529 ;
     RECT  33.624 97.439 33.678 97.531 ;
     RECT  33.624 97.531 33.714 97.867 ;
     RECT  6.804 97.529 8.298 98.045 ;
     RECT  2.304 97.291 2.97 98.059 ;
     RECT  3.708 97.259 5.814 98.059 ;
     RECT  7.815 98.045 8.298 98.069 ;
     RECT  33.624 97.867 33.75 98.155 ;
     RECT  2.304 98.059 5.814 98.221 ;
     RECT  6.804 98.045 7.074 98.221 ;
     RECT  29.415 97.439 32.397 98.347 ;
     RECT  33.624 98.155 33.786 98.347 ;
     RECT  29.415 98.347 33.786 98.519 ;
     RECT  2.304 98.221 7.074 98.609 ;
     RECT  29.415 98.519 33.678 98.609 ;
     RECT  9.108 98.653 9.126 98.761 ;
     RECT  6.804 98.609 7.074 98.765 ;
     RECT  2.304 98.609 6.066 98.827 ;
     RECT  8.928 98.761 9.126 98.879 ;
     RECT  6.912 98.765 7.074 99.031 ;
     RECT  7.815 98.069 8.097 99.031 ;
     RECT  2.268 98.827 6.066 99.391 ;
     RECT  2.268 99.391 6.138 99.535 ;
     RECT  6.912 99.031 8.097 99.535 ;
     RECT  9.036 98.879 9.126 99.599 ;
     RECT  29.415 98.609 32.526 99.643 ;
     RECT  33.588 98.609 33.678 99.643 ;
     RECT  2.268 99.535 8.097 99.689 ;
     RECT  9.036 99.599 9.054 99.689 ;
     RECT  28.008 99.463 28.026 99.697 ;
     RECT  6.552 99.689 8.097 99.761 ;
     RECT  27.936 99.697 28.026 99.761 ;
     RECT  6.768 99.761 8.097 99.773 ;
     RECT  29.415 99.643 33.678 99.967 ;
     RECT  2.268 99.689 5.742 100.103 ;
     RECT  27.936 99.761 27.99 100.103 ;
     RECT  27.936 100.103 27.954 100.139 ;
     RECT  10.515 91.769 10.797 100.345 ;
     RECT  29.34 99.967 33.678 100.499 ;
     RECT  2.304 100.103 5.742 100.507 ;
     RECT  10.515 100.345 10.854 100.607 ;
     RECT  7.668 99.773 8.097 100.679 ;
     RECT  2.304 100.507 5.85 100.741 ;
     RECT  6.768 99.773 6.786 100.741 ;
     RECT  7.776 100.679 8.097 100.769 ;
     RECT  29.415 100.499 33.678 100.781 ;
     RECT  29.415 100.781 32.49 100.877 ;
     RECT  2.304 100.741 6.93 100.921 ;
     RECT  2.304 100.921 6.966 101.039 ;
     RECT  7.815 100.769 8.097 101.047 ;
     RECT  7.815 101.047 8.154 101.219 ;
     RECT  2.304 101.039 6.822 101.563 ;
     RECT  7.815 101.219 8.097 101.695 ;
     RECT  29.415 100.877 32.454 101.755 ;
     RECT  33.588 100.781 33.678 101.755 ;
     RECT  2.268 101.563 6.822 101.885 ;
     RECT  2.304 101.885 6.822 101.893 ;
     RECT  7.596 101.695 8.097 101.893 ;
     RECT  2.304 101.893 8.097 102.029 ;
     RECT  0.216 102.043 0.234 102.173 ;
     RECT  29.415 101.755 33.678 102.227 ;
     RECT  29.415 102.227 33.642 102.541 ;
     RECT  29.376 102.541 33.642 102.659 ;
     RECT  2.304 102.029 6.534 102.811 ;
     RECT  7.38 102.029 8.097 102.811 ;
     RECT  9.108 102.811 9.198 102.929 ;
     RECT  10.515 100.607 10.797 103.009 ;
     RECT  29.415 102.659 33.642 103.195 ;
     RECT  10.515 103.009 10.818 103.739 ;
     RECT  2.304 102.811 8.097 103.819 ;
     RECT  29.415 103.195 33.678 103.883 ;
     RECT  33.588 103.883 33.678 104.081 ;
     RECT  2.304 103.819 8.622 104.279 ;
     RECT  6.804 104.279 8.622 104.431 ;
     RECT  6.804 104.431 8.982 104.521 ;
     RECT  29.415 103.883 32.49 104.635 ;
     RECT  33.588 104.081 33.642 104.635 ;
     RECT  6.804 104.521 9.054 104.819 ;
     RECT  2.304 104.279 6.066 105.125 ;
     RECT  4.356 105.125 6.066 105.241 ;
     RECT  6.804 104.819 8.37 105.241 ;
     RECT  9.288 105.241 9.378 105.359 ;
     RECT  9.36 105.359 9.378 105.431 ;
     RECT  0.252 105.307 0.27 105.437 ;
     RECT  29.415 104.635 33.642 105.451 ;
     RECT  29.415 105.451 33.714 105.511 ;
     RECT  28.872 105.511 33.714 105.629 ;
     RECT  4.356 105.241 8.37 105.737 ;
     RECT  29.415 105.629 33.714 105.773 ;
     RECT  29.415 105.773 33.642 105.809 ;
     RECT  2.304 105.125 3.366 105.907 ;
     RECT  4.356 105.737 6.93 105.907 ;
     RECT  10.515 103.739 10.797 106.051 ;
     RECT  10.515 106.051 10.854 106.321 ;
     RECT  25.164 106.177 25.182 106.321 ;
     RECT  25.092 106.321 25.182 106.349 ;
     RECT  10.515 106.321 10.926 106.439 ;
     RECT  25.092 106.349 25.11 106.511 ;
     RECT  7.668 105.737 8.37 106.519 ;
     RECT  2.304 105.907 6.93 106.603 ;
     RECT  7.668 106.519 8.586 106.603 ;
     RECT  2.304 106.603 8.586 106.619 ;
     RECT  2.304 106.619 8.154 106.637 ;
     RECT  6.804 106.637 8.154 106.709 ;
     RECT  2.304 106.637 5.994 106.939 ;
     RECT  29.415 105.809 33.138 106.939 ;
     RECT  2.268 106.939 5.994 106.979 ;
     RECT  6.84 106.709 8.154 106.979 ;
     RECT  24.015 81.779 24.297 106.987 ;
     RECT  7.056 106.979 8.154 107.015 ;
     RECT  29.415 106.939 33.606 107.083 ;
     RECT  2.268 106.979 5.85 107.285 ;
     RECT  24.015 106.987 24.534 107.293 ;
     RECT  24.015 107.293 25.146 107.321 ;
     RECT  0.252 107.419 0.27 107.549 ;
     RECT  7.128 107.015 8.154 107.671 ;
     RECT  2.304 107.285 5.85 107.761 ;
     RECT  7.128 107.671 8.622 107.761 ;
     RECT  2.304 107.761 8.622 107.825 ;
     RECT  7.668 107.825 8.622 107.861 ;
     RECT  2.304 107.825 6.858 107.933 ;
     RECT  2.304 107.933 6.678 108.043 ;
     RECT  9.252 108.031 9.27 108.139 ;
     RECT  9.252 108.139 9.306 108.203 ;
     RECT  0.216 108.139 0.234 108.269 ;
     RECT  2.268 108.043 6.678 108.365 ;
     RECT  9.288 108.203 9.306 108.437 ;
     RECT  7.668 107.861 8.478 108.599 ;
     RECT  25.092 107.321 25.146 108.671 ;
     RECT  29.415 107.083 33.642 108.671 ;
     RECT  7.668 108.599 8.298 108.715 ;
     RECT  33.552 108.671 33.642 108.715 ;
     RECT  25.128 108.671 25.146 108.743 ;
     RECT  7.596 108.715 8.298 108.841 ;
     RECT  7.416 108.841 8.298 108.869 ;
     RECT  2.304 108.365 6.678 108.985 ;
     RECT  7.416 108.869 8.097 108.985 ;
     RECT  33.552 108.715 34.362 109.049 ;
     RECT  29.415 108.671 32.526 109.147 ;
     RECT  33.552 109.049 33.642 109.319 ;
     RECT  2.304 108.985 8.097 109.409 ;
     RECT  9.144 109.291 9.162 109.525 ;
     RECT  29.124 109.147 32.526 109.723 ;
     RECT  2.304 109.409 6.822 109.751 ;
     RECT  9.036 109.525 9.162 109.751 ;
     RECT  0.54 109.831 0.558 109.867 ;
     RECT  33.588 109.319 33.642 109.901 ;
     RECT  0.252 109.867 0.558 109.997 ;
     RECT  0.54 109.997 0.558 110.045 ;
     RECT  33.588 109.901 33.606 110.045 ;
     RECT  9.036 109.751 9.126 110.093 ;
     RECT  28.764 109.723 32.526 110.219 ;
     RECT  2.304 109.751 6.786 110.291 ;
     RECT  6.516 110.291 6.786 110.491 ;
     RECT  7.815 109.409 8.097 110.491 ;
     RECT  6.516 110.491 8.097 110.641 ;
     RECT  6.516 110.641 8.262 110.759 ;
     RECT  9.072 110.093 9.126 110.767 ;
     RECT  9.072 110.767 9.198 110.831 ;
     RECT  9.18 110.831 9.198 110.903 ;
     RECT  6.516 110.759 8.097 110.939 ;
     RECT  29.415 110.219 32.526 110.971 ;
     RECT  2.304 110.291 5.67 111.163 ;
     RECT  6.768 110.939 8.097 111.299 ;
     RECT  33.624 110.827 33.642 111.307 ;
     RECT  0.252 111.451 0.27 111.629 ;
     RECT  33.624 111.307 33.678 111.643 ;
     RECT  33.624 111.643 33.714 111.979 ;
     RECT  29.415 110.971 32.886 112.123 ;
     RECT  33.624 111.979 33.786 112.123 ;
     RECT  29.415 112.123 33.786 112.217 ;
     RECT  2.268 111.163 5.67 112.261 ;
     RECT  6.804 111.299 8.097 112.261 ;
     RECT  9.036 111.685 9.054 112.261 ;
     RECT  8.928 112.261 9.054 112.523 ;
     RECT  2.268 112.261 8.097 112.685 ;
     RECT  2.304 112.685 8.097 112.793 ;
     RECT  2.304 112.793 3.006 112.955 ;
     RECT  3.744 112.793 8.097 112.963 ;
     RECT  29.415 112.217 33.714 112.991 ;
     RECT  3.744 112.963 8.838 113.225 ;
     RECT  3.924 113.225 8.838 113.333 ;
     RECT  2.304 112.955 2.826 113.419 ;
     RECT  2.268 113.419 2.826 113.567 ;
     RECT  25.092 112.963 25.11 113.909 ;
     RECT  29.415 112.991 33.678 113.909 ;
     RECT  9 113.881 9.414 113.947 ;
     RECT  3.924 113.333 8.154 113.971 ;
     RECT  9 113.947 9.486 113.999 ;
     RECT  3.672 113.971 8.154 114.241 ;
     RECT  2.304 113.567 2.826 114.571 ;
     RECT  3.672 114.241 8.694 114.571 ;
     RECT  2.304 114.571 8.694 114.781 ;
     RECT  2.304 114.781 8.73 114.809 ;
     RECT  29.415 113.909 32.49 114.859 ;
     RECT  33.588 113.909 33.678 114.859 ;
     RECT  7.704 114.809 8.73 114.889 ;
     RECT  2.304 114.809 6.966 114.917 ;
     RECT  29.415 114.859 33.678 114.917 ;
     RECT  7.704 114.889 8.802 114.961 ;
     RECT  9.54 114.925 9.558 114.961 ;
     RECT  7.704 114.961 9.558 114.989 ;
     RECT  25.128 114.889 25.146 114.989 ;
     RECT  0.216 114.115 0.234 115.085 ;
     RECT  9.468 114.989 9.558 115.195 ;
     RECT  9.468 115.195 9.594 115.349 ;
     RECT  10.515 106.439 10.797 115.465 ;
     RECT  34.344 115.051 34.362 115.529 ;
     RECT  7.704 114.989 8.478 115.619 ;
     RECT  10.515 115.465 10.854 115.619 ;
     RECT  0.252 115.531 0.27 115.661 ;
     RECT  29.415 114.917 33.606 115.675 ;
     RECT  29.415 115.675 33.642 115.691 ;
     RECT  2.304 114.917 6.93 115.771 ;
     RECT  2.304 115.771 7.002 115.997 ;
     RECT  7.815 115.619 8.478 116.069 ;
     RECT  9.108 116.131 9.126 116.303 ;
     RECT  33.588 115.691 33.642 116.338 ;
     RECT  2.304 115.997 6.858 116.683 ;
     RECT  33.588 116.338 33.678 116.683 ;
     RECT  2.268 116.683 6.858 116.717 ;
     RECT  7.815 116.069 8.37 116.743 ;
     RECT  2.268 116.717 6.534 116.771 ;
     RECT  2.268 116.771 6.354 116.813 ;
     RECT  7.38 116.743 8.37 116.815 ;
     RECT  29.415 115.691 32.49 116.827 ;
     RECT  33.552 116.683 33.678 116.827 ;
     RECT  29.415 116.827 33.678 116.879 ;
     RECT  2.268 116.813 6.282 116.969 ;
     RECT  10.515 115.619 10.797 117.013 ;
     RECT  7.38 116.815 8.406 117.121 ;
     RECT  10.515 117.013 10.818 117.149 ;
     RECT  29.415 116.879 33.642 117.643 ;
     RECT  7.38 117.121 9.018 117.661 ;
     RECT  29.415 117.643 33.678 117.689 ;
     RECT  7.056 117.661 9.018 117.779 ;
     RECT  2.268 116.969 5.886 117.815 ;
     RECT  33.624 117.689 33.678 118.123 ;
     RECT  2.304 117.815 5.886 118.165 ;
     RECT  7.056 117.779 8.874 118.165 ;
     RECT  29.415 117.689 32.49 118.165 ;
     RECT  2.304 118.165 8.874 118.319 ;
     RECT  2.304 118.319 8.262 118.427 ;
     RECT  29.16 118.165 32.49 118.589 ;
     RECT  33.624 118.123 33.714 118.603 ;
     RECT  2.304 118.427 8.226 118.661 ;
     RECT  33.588 118.603 33.714 118.697 ;
     RECT  33.588 118.697 33.678 118.859 ;
     RECT  0.252 118.747 0.27 118.925 ;
     RECT  29.415 118.589 32.49 118.987 ;
     RECT  33.624 118.859 33.678 119.039 ;
     RECT  7.815 118.661 8.226 119.209 ;
     RECT  7.815 119.209 8.73 119.443 ;
     RECT  29.415 118.987 32.526 119.515 ;
     RECT  7.815 119.443 8.802 119.579 ;
     RECT  7.815 119.579 8.766 119.669 ;
     RECT  2.304 118.661 7.038 119.677 ;
     RECT  29.415 119.515 32.886 119.899 ;
     RECT  33.624 119.039 33.642 119.899 ;
     RECT  2.304 119.677 7.074 119.983 ;
     RECT  7.815 119.669 8.097 119.983 ;
     RECT  0.396 119.899 0.414 120.043 ;
     RECT  0.216 120.043 0.414 120.077 ;
     RECT  0.216 120.077 0.234 120.173 ;
     RECT  2.304 119.983 8.097 120.245 ;
     RECT  2.304 120.245 3.546 120.361 ;
     RECT  2.268 120.361 3.546 120.413 ;
     RECT  29.415 119.899 33.642 120.571 ;
     RECT  4.392 120.245 8.097 120.631 ;
     RECT  4.392 120.631 8.262 120.749 ;
     RECT  29.415 120.571 33.678 120.821 ;
     RECT  10.515 117.149 10.797 120.991 ;
     RECT  9.036 120.901 9.054 121.019 ;
     RECT  4.392 120.749 8.097 121.027 ;
     RECT  10.515 120.991 10.818 121.091 ;
     RECT  2.304 120.413 3.546 121.171 ;
     RECT  4.32 121.027 8.097 121.171 ;
     RECT  0.216 121.195 0.234 121.325 ;
     RECT  2.304 121.171 8.097 121.531 ;
     RECT  2.268 121.531 8.097 121.595 ;
     RECT  2.268 121.595 2.754 121.703 ;
     RECT  9.108 121.369 9.378 121.703 ;
     RECT  3.636 121.595 8.097 121.739 ;
     RECT  3.708 121.739 8.097 121.865 ;
     RECT  9.108 121.703 9.126 121.937 ;
     RECT  3.78 121.865 8.097 121.945 ;
     RECT  29.415 120.821 33.642 121.981 ;
     RECT  3.78 121.945 9.054 122.099 ;
     RECT  29.415 121.981 33.678 122.107 ;
     RECT  3.78 122.099 6.03 122.135 ;
     RECT  7.344 122.099 9.054 122.171 ;
     RECT  29.412 122.107 33.678 122.279 ;
     RECT  2.304 121.703 2.754 122.521 ;
     RECT  10.515 121.091 10.797 122.755 ;
     RECT  29.415 122.279 33.678 122.861 ;
     RECT  10.515 122.755 10.854 122.909 ;
     RECT  7.344 122.171 8.802 122.953 ;
     RECT  33.588 122.861 33.678 122.971 ;
     RECT  7.344 122.953 9.126 123.053 ;
     RECT  2.304 122.521 2.862 123.163 ;
     RECT  7.344 123.053 8.802 123.179 ;
     RECT  3.996 122.135 6.03 123.187 ;
     RECT  2.268 123.163 2.862 123.215 ;
     RECT  2.304 123.215 2.862 123.331 ;
     RECT  3.996 123.187 6.282 123.331 ;
     RECT  2.304 123.331 6.282 123.449 ;
     RECT  33.588 122.971 33.714 123.451 ;
     RECT  3.78 123.449 6.282 123.521 ;
     RECT  3.996 123.521 6.282 123.565 ;
     RECT  7.344 123.179 8.097 123.565 ;
     RECT  3.996 123.565 8.097 123.719 ;
     RECT  26.715 96.089 26.997 123.763 ;
     RECT  29.415 122.861 32.526 123.787 ;
     RECT  33.588 123.451 34.362 123.787 ;
     RECT  3.996 123.719 6.93 123.899 ;
     RECT  3.996 123.899 6.858 123.989 ;
     RECT  29.415 123.787 34.362 124.097 ;
     RECT  7.815 123.719 8.097 124.105 ;
     RECT  9.108 124.033 9.126 124.105 ;
     RECT  7.815 124.105 9.126 124.169 ;
     RECT  26.715 123.763 27.054 124.169 ;
     RECT  7.815 124.169 8.406 124.259 ;
     RECT  29.415 124.097 34.326 124.259 ;
     RECT  2.304 123.449 2.97 124.411 ;
     RECT  3.996 123.989 6.786 124.411 ;
     RECT  29.415 124.259 33.57 124.645 ;
     RECT  7.815 124.259 8.226 124.709 ;
     RECT  34.308 124.259 34.326 124.709 ;
     RECT  0.252 124.651 0.27 124.781 ;
     RECT  29.16 124.645 33.57 124.799 ;
     RECT  9.504 124.915 9.522 125.069 ;
     RECT  29.415 124.799 33.57 125.083 ;
     RECT  2.304 124.411 6.786 125.185 ;
     RECT  2.304 125.185 6.858 125.213 ;
     RECT  7.815 124.709 8.154 125.323 ;
     RECT  4.392 125.213 6.858 125.563 ;
     RECT  7.704 125.323 8.154 125.563 ;
     RECT  29.415 125.083 33.606 125.563 ;
     RECT  10.515 122.909 10.797 125.617 ;
     RECT  29.415 125.563 34.326 125.659 ;
     RECT  29.415 125.659 34.398 125.693 ;
     RECT  4.392 125.563 8.154 125.761 ;
     RECT  8.892 125.491 9.054 125.761 ;
     RECT  10.515 125.617 10.854 125.789 ;
     RECT  4.392 125.761 9.054 125.879 ;
     RECT  29.415 125.693 33.606 125.879 ;
     RECT  2.304 125.213 3.618 126.031 ;
     RECT  4.392 125.879 8.694 126.031 ;
     RECT  34.344 125.693 34.398 126.059 ;
     RECT  2.304 126.031 8.694 126.149 ;
     RECT  2.304 126.149 8.622 126.379 ;
     RECT  2.268 126.379 8.622 126.455 ;
     RECT  29.415 125.879 32.886 126.715 ;
     RECT  10.515 125.789 10.797 126.733 ;
     RECT  10.515 126.733 10.818 126.833 ;
     RECT  2.304 126.455 8.622 126.959 ;
     RECT  29.415 126.715 33.066 127.051 ;
     RECT  7.815 126.959 8.622 127.111 ;
     RECT  2.304 126.959 6.75 127.229 ;
     RECT  2.304 127.229 2.898 127.265 ;
     RECT  2.34 127.265 2.898 127.373 ;
     RECT  29.415 127.051 33.606 127.409 ;
     RECT  33.552 127.409 33.606 127.499 ;
     RECT  0.216 127.387 0.234 127.565 ;
     RECT  29.415 127.409 32.778 127.769 ;
     RECT  3.78 127.229 6.75 127.805 ;
     RECT  2.415 127.373 2.898 127.877 ;
     RECT  3.78 127.805 3.834 127.913 ;
     RECT  4.608 127.805 6.75 127.921 ;
     RECT  4.608 127.921 6.93 128.039 ;
     RECT  29.415 127.769 32.49 128.039 ;
     RECT  4.608 128.039 5.397 128.075 ;
     RECT  6.444 128.039 6.858 128.111 ;
     RECT  7.815 127.111 8.658 128.111 ;
     RECT  3.816 127.913 3.834 128.183 ;
     RECT  6.444 128.111 6.462 128.219 ;
     RECT  7.815 128.111 8.586 128.309 ;
     RECT  29.415 128.039 30.762 128.309 ;
     RECT  34.38 126.059 34.398 128.309 ;
     RECT  31.5 128.039 32.49 128.489 ;
     RECT  33.552 127.499 33.57 128.579 ;
     RECT  30.528 128.309 30.762 128.615 ;
     RECT  31.5 128.489 32.454 128.849 ;
     RECT  31.5 128.849 32.397 128.885 ;
     RECT  7.815 128.309 8.226 129.029 ;
     RECT  30.528 128.615 30.726 129.119 ;
     RECT  2.415 127.877 2.697 129.347 ;
     RECT  5.115 128.075 5.397 129.347 ;
     RECT  7.815 129.029 8.097 129.347 ;
     RECT  10.515 126.833 10.797 129.347 ;
     RECT  13.215 84.479 13.497 129.347 ;
     RECT  15.915 2.413 16.197 129.347 ;
     RECT  18.615 2.413 18.897 129.347 ;
     RECT  21.315 84.317 21.597 129.347 ;
     RECT  24.015 107.321 24.297 129.347 ;
     RECT  26.715 124.169 26.997 129.347 ;
     RECT  29.415 128.309 29.697 129.347 ;
     RECT  32.115 128.885 32.397 129.347 ;
     RECT  2.415 129.347 2.505 129.617 ;
     RECT  5.115 129.347 5.205 129.617 ;
     RECT  7.815 129.347 7.905 129.617 ;
     RECT  10.515 129.347 10.605 129.617 ;
     RECT  13.215 129.347 13.305 129.617 ;
     RECT  15.915 129.347 16.005 129.617 ;
     RECT  18.615 129.347 18.705 129.617 ;
     RECT  21.315 129.347 21.405 129.617 ;
     RECT  24.015 129.347 24.105 129.617 ;
     RECT  26.715 129.347 26.805 129.617 ;
     RECT  29.415 129.347 29.505 129.617 ;
     RECT  32.115 129.347 32.205 129.617 ;
     RECT  17.1 131.628 17.118 131.645 ;
    LAYER M4 ;
     RECT  0.156 4.416 0.205 127.416 ;
     RECT  0.205 4.416 2.408 127.56 ;
     RECT  2.408 2.148 2.512 129.612 ;
     RECT  2.512 2.418 2.704 129.342 ;
     RECT  2.704 8.448 2.765 8.52 ;
     RECT  2.704 20.16 2.765 20.424 ;
     RECT  2.704 38.976 2.765 41.4 ;
     RECT  2.704 49.344 2.765 50.76 ;
     RECT  2.704 59.232 2.765 60.072 ;
     RECT  2.704 69.216 2.765 71.352 ;
     RECT  2.704 72.336 2.765 73.368 ;
     RECT  2.704 114.048 2.765 117.432 ;
     RECT  2.704 118.56 2.765 121.704 ;
     RECT  2.704 123.456 2.765 125.448 ;
     RECT  2.704 9.552 2.801 11.736 ;
     RECT  2.704 106.656 2.801 108.888 ;
     RECT  2.765 114.576 2.801 117.432 ;
     RECT  2.765 123.456 2.801 125.304 ;
     RECT  2.704 42.432 2.867 47.352 ;
     RECT  2.704 51.984 2.873 57.816 ;
     RECT  2.704 64.896 2.873 67.704 ;
     RECT  2.704 94.992 2.873 103.752 ;
     RECT  2.704 127.536 2.873 127.56 ;
     RECT  2.704 23.808 2.909 25.464 ;
     RECT  2.704 87.072 2.909 93.816 ;
     RECT  2.801 123.984 2.909 125.304 ;
     RECT  2.704 29.616 2.981 30.12 ;
     RECT  2.873 67.104 2.981 67.128 ;
     RECT  2.765 118.56 2.981 120.264 ;
     RECT  2.909 123.984 2.981 124.008 ;
     RECT  2.704 27.168 3.017 27.192 ;
     RECT  2.909 91.296 3.017 93.816 ;
     RECT  2.704 109.968 3.017 111.624 ;
     RECT  2.704 112.752 3.017 112.776 ;
     RECT  2.704 61.536 3.089 62.568 ;
     RECT  2.704 13.968 3.197 19.032 ;
     RECT  2.765 20.208 3.197 20.424 ;
     RECT  2.704 37.584 3.197 37.608 ;
     RECT  2.801 108.144 3.197 108.888 ;
     RECT  3.197 16.512 3.203 19.032 ;
     RECT  3.203 16.512 3.233 17.64 ;
     RECT  2.801 9.552 3.269 11.256 ;
     RECT  2.704 31.104 3.269 35.976 ;
     RECT  3.017 92.352 3.269 93.816 ;
     RECT  2.801 117.312 3.299 117.432 ;
     RECT  3.203 19.008 3.305 19.032 ;
     RECT  2.704 74.592 3.305 74.616 ;
     RECT  3.017 110.496 3.305 111.624 ;
     RECT  2.981 119.664 3.305 120.264 ;
     RECT  2.981 118.56 3.313 118.584 ;
     RECT  3.233 17.616 3.341 17.64 ;
     RECT  2.704 104.832 3.377 105.432 ;
     RECT  2.704 21.552 3.395 21.672 ;
     RECT  2.704 22.752 3.395 22.776 ;
     RECT  2.909 23.808 3.436 24.648 ;
     RECT  2.765 8.496 3.443 8.52 ;
     RECT  2.765 39.216 3.443 41.064 ;
     RECT  2.873 103.728 3.443 103.752 ;
     RECT  3.305 110.496 3.491 111.048 ;
     RECT  3.269 31.104 3.521 34.536 ;
     RECT  2.867 42.432 3.539 42.456 ;
     RECT  2.867 43.536 3.539 47.352 ;
     RECT  2.873 64.896 3.539 65.688 ;
     RECT  2.801 114.576 3.539 116.28 ;
     RECT  3.197 13.968 3.565 14.856 ;
     RECT  3.521 33.072 3.635 34.536 ;
     RECT  2.801 106.656 3.683 106.68 ;
     RECT  3.197 108.576 3.683 108.888 ;
     RECT  3.233 16.512 3.701 16.536 ;
     RECT  3.269 35.952 3.733 35.976 ;
     RECT  2.765 50.592 3.733 50.76 ;
     RECT  2.873 51.984 3.733 52.536 ;
     RECT  2.873 53.568 3.733 57.816 ;
     RECT  3.539 46.224 3.737 47.352 ;
     RECT  3.521 31.104 3.74 31.896 ;
     RECT  2.765 49.344 3.74 49.512 ;
     RECT  3.733 50.592 3.74 52.536 ;
     RECT  2.765 121.296 3.74 121.32 ;
     RECT  3.269 93.552 3.743 93.816 ;
     RECT  2.873 94.992 3.743 102.696 ;
     RECT  3.737 46.272 3.769 47.352 ;
     RECT  3.74 49.344 3.781 52.536 ;
     RECT  3.565 13.968 3.805 14.664 ;
     RECT  2.765 69.84 3.805 71.352 ;
     RECT  3.781 73.488 3.805 73.512 ;
     RECT  3.733 53.568 3.827 58.152 ;
     RECT  3.305 119.664 3.827 119.688 ;
     RECT  3.74 121.2 3.827 121.32 ;
     RECT  2.909 125.28 3.827 125.304 ;
     RECT  2.704 76.224 3.829 76.776 ;
     RECT  3.377 104.832 3.829 104.904 ;
     RECT  3.539 64.896 3.836 65.016 ;
     RECT  3.443 40.176 3.841 41.064 ;
     RECT  3.805 69.504 3.845 71.352 ;
     RECT  3.74 30.72 3.868 31.896 ;
     RECT  3.805 73.488 3.868 74.136 ;
     RECT  3.743 93.552 3.875 102.696 ;
     RECT  3.436 23.808 3.881 23.832 ;
     RECT  3.805 38.736 3.889 38.76 ;
     RECT  3.733 35.952 3.913 36.456 ;
     RECT  3.836 62.592 3.913 62.616 ;
     RECT  3.269 10.176 3.925 11.256 ;
     RECT  3.877 27.216 3.925 27.24 ;
     RECT  3.913 35.952 3.925 36.504 ;
     RECT  3.913 126.48 3.925 126.504 ;
     RECT  2.704 84.288 3.949 86.04 ;
     RECT  2.909 87.072 3.949 90.264 ;
     RECT  3.925 35.952 3.953 37.512 ;
     RECT  3.829 76.176 3.953 76.776 ;
     RECT  3.829 104.112 3.953 104.904 ;
     RECT  3.953 36.432 3.971 37.512 ;
     RECT  3.197 20.208 3.973 20.232 ;
     RECT  2.765 59.232 3.98 59.304 ;
     RECT  3.539 115.536 3.98 116.28 ;
     RECT  3.395 21.648 3.989 21.672 ;
     RECT  3.491 110.592 3.989 111.048 ;
     RECT  3.925 126.48 3.997 127.128 ;
     RECT  2.704 77.856 4.019 83.304 ;
     RECT  3.539 43.536 4.021 44.376 ;
     RECT  3.997 126.576 4.025 127.128 ;
     RECT  2.704 5.664 4.061 5.688 ;
     RECT  4.019 77.856 4.061 80.568 ;
     RECT  3.98 59.232 4.067 60.168 ;
     RECT  3.877 113.088 4.067 113.112 ;
     RECT  3.98 115.536 4.067 117.192 ;
     RECT  3.805 13.056 4.069 14.664 ;
     RECT  3.635 33.072 4.097 33.624 ;
     RECT  3.913 62.592 4.097 62.712 ;
     RECT  3.953 76.368 4.097 76.776 ;
     RECT  4.019 81.6 4.097 83.304 ;
     RECT  4.069 12.528 4.115 14.664 ;
     RECT  3.971 36.48 4.133 37.512 ;
     RECT  3.925 27.216 4.201 27.768 ;
     RECT  3.841 40.176 4.201 41.16 ;
     RECT  3.683 108.576 4.201 108.792 ;
     RECT  4.097 81.648 4.213 83.304 ;
     RECT  3.949 84.288 4.213 90.264 ;
     RECT  3.769 46.272 4.309 47.4 ;
     RECT  3.781 48.48 4.309 52.536 ;
     RECT  3.017 91.296 4.309 91.32 ;
     RECT  3.269 92.352 4.309 92.376 ;
     RECT  4.021 121.344 4.309 121.848 ;
     RECT  3.925 10.176 4.412 11.448 ;
     RECT  4.115 12.528 4.412 13.656 ;
     RECT  4.213 81.648 4.412 90.264 ;
     RECT  4.309 91.296 4.412 92.376 ;
     RECT  3.875 93.552 4.412 101.256 ;
     RECT  2.765 72.336 4.417 72.36 ;
     RECT  4.129 112.272 4.417 112.296 ;
     RECT  3.868 73.776 4.453 74.136 ;
     RECT  4.412 81.648 4.453 92.376 ;
     RECT  4.412 93.504 4.453 101.256 ;
     RECT  3.875 102.384 4.453 102.696 ;
     RECT  4.021 43.296 4.501 44.376 ;
     RECT  3.973 19.632 4.508 20.232 ;
     RECT  3.953 104.256 4.508 104.904 ;
     RECT  4.508 19.152 4.517 20.232 ;
     RECT  2.704 7.392 4.525 7.416 ;
     RECT  4.501 43.104 4.525 44.376 ;
     RECT  4.097 76.752 4.525 76.776 ;
     RECT  4.061 77.856 4.525 80.472 ;
     RECT  3.98 114.432 4.525 114.456 ;
     RECT  2.981 29.616 4.549 29.64 ;
     RECT  3.868 30.72 4.549 30.84 ;
     RECT  3.836 64.272 4.549 65.016 ;
     RECT  4.508 104.256 4.549 105.336 ;
     RECT  4.067 59.232 4.561 59.784 ;
     RECT  4.549 64.224 4.561 65.544 ;
     RECT  3.845 69.504 4.561 69.528 ;
     RECT  4.453 73.776 4.597 74.664 ;
     RECT  3.089 61.536 4.604 61.56 ;
     RECT  4.525 6.24 4.633 6.264 ;
     RECT  4.525 7.392 4.633 7.992 ;
     RECT  4.115 14.64 4.633 14.664 ;
     RECT  4.133 37.056 4.633 37.512 ;
     RECT  4.604 61.536 4.645 62.184 ;
     RECT  4.525 9.12 4.741 9.144 ;
     RECT  4.412 10.176 4.741 13.656 ;
     RECT  3.845 70.56 4.741 71.352 ;
     RECT  4.417 72.336 4.741 72.648 ;
     RECT  4.561 64.224 4.796 66.12 ;
     RECT  4.652 25.056 4.813 25.08 ;
     RECT  4.561 68.928 4.844 69.528 ;
     RECT  4.741 70.56 4.844 72.648 ;
     RECT  4.633 37.056 4.885 38.184 ;
     RECT  4.201 40.176 4.885 42.072 ;
     RECT  4.669 24.048 4.921 24.072 ;
     RECT  3.973 22.8 4.933 22.824 ;
     RECT  4.921 23.952 4.933 24.072 ;
     RECT  4.813 25.056 4.949 25.752 ;
     RECT  4.201 27.216 4.949 28.536 ;
     RECT  4.517 19.152 4.981 21.144 ;
     RECT  4.949 25.056 4.981 28.536 ;
     RECT  4.549 29.616 4.981 30.84 ;
     RECT  4.453 81.648 4.981 101.256 ;
     RECT  4.453 102.384 4.981 103.176 ;
     RECT  4.237 16.8 5.029 16.824 ;
     RECT  4.981 18.192 5.029 21.144 ;
     RECT  3.989 110.592 5.029 110.616 ;
     RECT  4.633 6.24 5.108 7.992 ;
     RECT  4.741 9.12 5.108 13.656 ;
     RECT  4.633 14.64 5.108 14.856 ;
     RECT  5.029 16.8 5.108 21.144 ;
     RECT  4.933 22.8 5.108 24.072 ;
     RECT  4.981 25.056 5.108 30.84 ;
     RECT  3.868 31.872 5.108 31.896 ;
     RECT  4.097 33.12 5.108 33.624 ;
     RECT  4.885 37.056 5.108 42.072 ;
     RECT  4.525 43.104 5.108 44.472 ;
     RECT  4.309 46.272 5.108 52.536 ;
     RECT  3.827 53.568 5.108 57.672 ;
     RECT  4.561 58.704 5.108 59.784 ;
     RECT  4.645 60.96 5.108 62.184 ;
     RECT  4.796 64.224 5.108 66.168 ;
     RECT  4.525 67.248 5.108 67.272 ;
     RECT  4.844 68.928 5.108 72.648 ;
     RECT  4.597 73.776 5.108 74.76 ;
     RECT  4.525 76.752 5.108 80.472 ;
     RECT  4.981 81.648 5.108 103.176 ;
     RECT  4.549 104.256 5.108 105.912 ;
     RECT  4.201 108.24 5.108 108.792 ;
     RECT  5.029 110.592 5.108 110.904 ;
     RECT  4.417 111.984 5.108 112.296 ;
     RECT  4.525 113.952 5.108 114.456 ;
     RECT  4.067 115.584 5.108 117.192 ;
     RECT  4.645 118.272 5.108 118.296 ;
     RECT  4.949 120.288 5.108 120.312 ;
     RECT  4.309 121.344 5.108 122.52 ;
     RECT  4.309 124.224 5.108 124.248 ;
     RECT  4.025 126.576 5.108 126.6 ;
     RECT  5.108 2.148 5.212 129.612 ;
     RECT  5.212 2.418 5.404 129.342 ;
     RECT  5.404 14.64 5.465 19.128 ;
     RECT  5.404 45.408 5.501 56.376 ;
     RECT  5.404 9.648 5.555 13.08 ;
     RECT  5.404 27.84 5.555 29.352 ;
     RECT  5.404 43.296 5.555 44.376 ;
     RECT  5.404 74.064 5.555 95.736 ;
     RECT  5.404 116.784 5.555 118.104 ;
     RECT  5.555 12.192 5.596 13.08 ;
     RECT  5.501 56.352 5.603 56.376 ;
     RECT  5.404 104.016 5.603 107.16 ;
     RECT  5.404 123.408 5.603 125.64 ;
     RECT  5.555 74.064 5.609 94.056 ;
     RECT  5.404 114.816 5.609 114.84 ;
     RECT  5.404 119.712 5.609 120.264 ;
     RECT  5.501 46.704 5.616 55.272 ;
     RECT  5.609 120.096 5.644 120.264 ;
     RECT  5.465 14.784 5.651 19.128 ;
     RECT  5.404 31.776 5.681 33.672 ;
     RECT  5.404 110.88 5.681 113.448 ;
     RECT  5.404 61.008 5.689 61.128 ;
     RECT  5.404 58.128 5.692 59.976 ;
     RECT  5.651 16.752 5.699 19.128 ;
     RECT  5.404 21.792 5.699 24.312 ;
     RECT  5.609 74.064 5.717 84.408 ;
     RECT  5.596 12.528 5.753 13.08 ;
     RECT  5.609 85.488 5.753 94.056 ;
     RECT  5.555 116.784 5.753 117.48 ;
     RECT  5.753 89.424 5.789 94.056 ;
     RECT  5.692 59.76 5.825 59.976 ;
     RECT  5.717 74.064 5.825 84.312 ;
     RECT  5.555 43.776 5.891 44.376 ;
     RECT  5.555 27.84 5.897 28.488 ;
     RECT  5.616 49.008 5.897 55.272 ;
     RECT  5.825 74.064 5.897 79.32 ;
     RECT  5.689 61.008 5.925 61.032 ;
     RECT  5.404 62.256 5.932 62.808 ;
     RECT  5.897 53.088 5.933 55.272 ;
     RECT  5.603 123.408 5.933 125.352 ;
     RECT  5.897 27.84 5.939 27.864 ;
     RECT  5.404 66.72 5.939 71.256 ;
     RECT  5.933 125.232 5.939 125.352 ;
     RECT  5.699 22.608 5.941 23.448 ;
     RECT  5.933 53.088 5.941 53.112 ;
     RECT  5.603 104.016 5.987 104.424 ;
     RECT  5.753 85.488 6.005 88.44 ;
     RECT  5.404 126.672 6.005 127.128 ;
     RECT  5.897 79.296 6.035 79.32 ;
     RECT  5.404 20.304 6.041 20.76 ;
     RECT  5.941 22.608 6.041 22.632 ;
     RECT  5.933 54.096 6.041 55.272 ;
     RECT  5.825 80.352 6.041 84.312 ;
     RECT  5.897 74.064 6.076 78.12 ;
     RECT  5.789 89.424 6.076 93.336 ;
     RECT  5.644 120.096 6.076 120.12 ;
     RECT  5.404 122.352 6.076 122.376 ;
     RECT  5.897 49.008 6.113 51.912 ;
     RECT  5.404 30.576 6.131 30.6 ;
     RECT  5.681 31.776 6.131 31.8 ;
     RECT  5.681 32.976 6.149 33.672 ;
     RECT  5.616 46.704 6.149 47.928 ;
     RECT  5.501 45.408 6.179 45.672 ;
     RECT  5.939 68.928 6.179 69.96 ;
     RECT  5.404 25.296 6.221 25.32 ;
     RECT  6.179 45.408 6.221 45.432 ;
     RECT  6.076 89.424 6.221 92.376 ;
     RECT  5.404 101.856 6.221 101.88 ;
     RECT  5.699 16.752 6.227 18.168 ;
     RECT  6.113 51.888 6.257 51.912 ;
     RECT  5.933 123.408 6.257 123.96 ;
     RECT  5.404 39.024 6.275 41.784 ;
     RECT  6.221 91.632 6.275 92.376 ;
     RECT  6.257 123.408 6.293 123.432 ;
     RECT  5.651 14.784 6.323 15.48 ;
     RECT  5.603 105.456 6.323 107.16 ;
     RECT  5.404 108.192 6.323 109.416 ;
     RECT  5.681 112.272 6.323 113.448 ;
     RECT  5.555 95.184 6.329 95.736 ;
     RECT  6.113 49.008 6.365 50.664 ;
     RECT  5.753 116.784 6.365 116.808 ;
     RECT  6.275 40.752 6.371 41.784 ;
     RECT  6.076 74.064 6.371 76.776 ;
     RECT  6.371 74.064 6.373 75.288 ;
     RECT  6.076 78.096 6.401 78.12 ;
     RECT  6.323 112.896 6.401 113.448 ;
     RECT  6.323 14.784 6.437 14.808 ;
     RECT  5.404 96.96 6.437 99.528 ;
     RECT  6.005 85.488 6.467 88.248 ;
     RECT  6.221 89.424 6.467 90.552 ;
     RECT  5.404 35.424 6.473 37.608 ;
     RECT  6.365 50.544 6.473 50.664 ;
     RECT  5.692 58.128 6.505 58.536 ;
     RECT  6.467 88.08 6.508 88.248 ;
     RECT  6.467 85.488 6.545 86.616 ;
     RECT  6.005 127.104 6.581 127.128 ;
     RECT  6.365 49.008 6.613 49.464 ;
     RECT  5.939 66.72 6.613 67.848 ;
     RECT  6.227 16.752 6.617 17.64 ;
     RECT  6.505 118.56 6.659 118.584 ;
     RECT  6.437 97.104 6.661 99.528 ;
     RECT  6.041 55.2 6.685 55.272 ;
     RECT  5.404 6.768 6.689 6.792 ;
     RECT  6.401 112.896 6.689 112.92 ;
     RECT  6.613 116.688 6.7 116.712 ;
     RECT  5.932 62.4 6.721 62.808 ;
     RECT  5.404 64.704 6.721 64.728 ;
     RECT  6.323 105.456 6.748 106.632 ;
     RECT  6.613 66.528 6.757 67.848 ;
     RECT  6.473 35.424 6.761 37.032 ;
     RECT  6.661 97.104 6.797 100.488 ;
     RECT  5.987 104.016 6.797 104.184 ;
     RECT  6.721 62.4 6.803 64.968 ;
     RECT  6.757 66.336 6.833 67.848 ;
     RECT  6.86 29.76 6.901 29.784 ;
     RECT  6.275 39.024 6.901 39.768 ;
     RECT  6.893 42.768 6.908 42.792 ;
     RECT  6.685 55.2 7.004 55.896 ;
     RECT  6.505 57.6 7.004 58.536 ;
     RECT  6.149 32.976 7.045 33.048 ;
     RECT  6.793 21.408 7.117 21.432 ;
     RECT  5.891 44.352 7.117 44.376 ;
     RECT  6.179 69.504 7.117 69.96 ;
     RECT  5.939 125.328 7.117 125.352 ;
     RECT  6.041 54.096 7.141 54.12 ;
     RECT  7.045 32.352 7.148 33.048 ;
     RECT  7.045 34.224 7.148 34.248 ;
     RECT  6.803 62.4 7.153 62.712 ;
     RECT  7.109 110.496 7.153 110.52 ;
     RECT  6.901 29.04 7.189 29.784 ;
     RECT  6.761 35.424 7.189 35.592 ;
     RECT  6.901 68.304 7.196 68.328 ;
     RECT  7.117 69.504 7.196 70.248 ;
     RECT  5.939 71.232 7.237 71.256 ;
     RECT  6.908 42.768 7.261 43.32 ;
     RECT  5.404 72.672 7.261 72.792 ;
     RECT  6.323 108.192 7.261 109.368 ;
     RECT  6.275 91.632 7.333 92.328 ;
     RECT  6.373 74.064 7.34 74.664 ;
     RECT  6.901 94.08 7.34 94.104 ;
     RECT  6.901 38.16 7.369 39.768 ;
     RECT  6.371 40.752 7.369 40.776 ;
     RECT  7.369 38.16 7.381 40.776 ;
     RECT  7.261 42.192 7.381 43.32 ;
     RECT  7.261 72.336 7.381 72.792 ;
     RECT  7.34 73.776 7.381 74.664 ;
     RECT  6.329 95.184 7.381 95.4 ;
     RECT  7.297 121.968 7.381 121.992 ;
     RECT  7.153 61.776 7.477 62.712 ;
     RECT  7.004 55.2 7.573 58.536 ;
     RECT  6.041 20.304 7.585 20.328 ;
     RECT  7.381 38.16 7.669 43.32 ;
     RECT  7.117 44.352 7.669 45 ;
     RECT  6.149 46.704 7.669 47.304 ;
     RECT  6.613 48.816 7.669 49.464 ;
     RECT  7.513 78.624 7.669 78.648 ;
     RECT  7.628 79.92 7.669 79.944 ;
     RECT  7.441 104.208 7.669 104.232 ;
     RECT  6.748 105.456 7.669 105.48 ;
     RECT  6.812 11.808 7.801 11.832 ;
     RECT  7.369 5.568 7.808 5.592 ;
     RECT  5.555 9.648 7.808 10.488 ;
     RECT  7.801 11.808 7.808 12.072 ;
     RECT  5.753 13.056 7.808 13.08 ;
     RECT  7.729 14.928 7.808 14.952 ;
     RECT  6.853 16.512 7.808 16.536 ;
     RECT  6.617 17.616 7.808 17.64 ;
     RECT  6.853 18.96 7.808 18.984 ;
     RECT  7.585 20.304 7.808 20.424 ;
     RECT  7.117 21.408 7.808 22.248 ;
     RECT  7.436 24.096 7.808 24.12 ;
     RECT  7.477 25.296 7.808 25.32 ;
     RECT  6.829 26.784 7.808 26.808 ;
     RECT  7.189 28.8 7.808 29.784 ;
     RECT  7.148 32.352 7.808 34.248 ;
     RECT  7.189 35.328 7.808 35.592 ;
     RECT  6.761 37.008 7.808 37.032 ;
     RECT  7.669 38.16 7.808 45 ;
     RECT  7.669 46.704 7.808 49.464 ;
     RECT  6.473 50.544 7.808 50.568 ;
     RECT  7.333 51.888 7.808 51.912 ;
     RECT  7.141 53.952 7.808 54.12 ;
     RECT  7.573 55.2 7.808 58.824 ;
     RECT  5.825 59.952 7.808 59.976 ;
     RECT  7.477 60.96 7.808 62.712 ;
     RECT  6.803 63.744 7.808 64.968 ;
     RECT  6.833 66.336 7.808 67.176 ;
     RECT  7.196 68.304 7.808 70.248 ;
     RECT  7.237 71.232 7.808 71.352 ;
     RECT  7.381 72.336 7.808 74.664 ;
     RECT  6.371 76.704 7.808 76.776 ;
     RECT  7.669 78.624 7.808 79.944 ;
     RECT  6.041 81.12 7.808 84.312 ;
     RECT  6.545 86.016 7.808 86.616 ;
     RECT  6.508 88.224 7.808 88.248 ;
     RECT  6.467 89.472 7.808 90.552 ;
     RECT  7.333 91.632 7.808 92.952 ;
     RECT  7.34 94.032 7.808 94.104 ;
     RECT  7.381 95.184 7.808 95.688 ;
     RECT  6.797 97.104 7.808 100.104 ;
     RECT  7.669 104.208 7.808 105.48 ;
     RECT  6.748 106.608 7.808 106.632 ;
     RECT  7.261 107.76 7.808 109.368 ;
     RECT  7.153 110.496 7.808 111.192 ;
     RECT  7.441 117.504 7.808 117.528 ;
     RECT  7.189 118.512 7.808 118.536 ;
     RECT  7.189 120.768 7.808 120.888 ;
     RECT  7.381 121.968 7.808 122.808 ;
     RECT  7.117 125.328 7.808 125.592 ;
     RECT  7.808 2.148 7.912 129.612 ;
     RECT  7.912 2.418 8.104 129.342 ;
     RECT  8.104 67.152 8.165 67.176 ;
     RECT  8.104 82.512 8.165 84.36 ;
     RECT  8.104 72.672 8.201 72.792 ;
     RECT  8.104 78.192 8.201 79.032 ;
     RECT  8.165 82.512 8.201 82.536 ;
     RECT  8.104 5.568 8.237 6.264 ;
     RECT  8.104 11.088 8.243 12.552 ;
     RECT  8.104 14.928 8.243 14.952 ;
     RECT  8.165 83.616 8.243 84.36 ;
     RECT  8.104 86.016 8.243 86.616 ;
     RECT  8.104 88.368 8.243 88.392 ;
     RECT  8.104 89.808 8.243 89.832 ;
     RECT  8.104 113.856 8.243 114.84 ;
     RECT  8.104 117.504 8.243 117.528 ;
     RECT  8.104 18.96 8.309 18.984 ;
     RECT  8.104 20.4 8.309 20.424 ;
     RECT  8.243 83.616 8.309 84.168 ;
     RECT  8.104 91.632 8.309 91.704 ;
     RECT  8.104 108.336 8.309 108.36 ;
     RECT  8.237 6.24 8.339 6.264 ;
     RECT  8.104 7.968 8.339 7.992 ;
     RECT  8.104 25.296 8.339 26.808 ;
     RECT  8.104 27.888 8.339 27.912 ;
     RECT  8.339 25.296 8.381 26.088 ;
     RECT  8.104 104.928 8.381 104.952 ;
     RECT  8.104 9.072 8.387 9.768 ;
     RECT  8.243 11.088 8.387 12.072 ;
     RECT  8.104 44.064 8.417 44.376 ;
     RECT  8.309 91.632 8.489 91.656 ;
     RECT  8.417 44.352 8.597 44.376 ;
     RECT  8.243 113.952 9.497 113.976 ;
     RECT  8.104 47.184 10.508 47.208 ;
     RECT  8.104 50.544 10.508 50.568 ;
     RECT  8.201 72.672 10.508 72.696 ;
     RECT  8.201 78.192 10.508 78.216 ;
     RECT  8.104 81.12 10.508 81.144 ;
     RECT  8.309 84.144 10.508 84.168 ;
     RECT  8.104 97.104 10.508 97.128 ;
     RECT  8.104 98.88 10.508 98.904 ;
     RECT  10.508 2.148 10.612 129.612 ;
     RECT  10.612 2.418 10.804 129.342 ;
     RECT  10.804 47.184 13.208 47.208 ;
     RECT  10.804 50.544 13.208 50.568 ;
     RECT  10.804 72.672 13.208 72.696 ;
     RECT  10.804 78.336 13.208 78.36 ;
     RECT  10.804 81.12 13.208 81.144 ;
     RECT  10.804 84.288 13.208 84.312 ;
     RECT  10.804 97.104 13.208 97.128 ;
     RECT  10.804 98.88 13.208 98.904 ;
     RECT  13.208 2.148 13.312 129.612 ;
     RECT  13.312 2.418 13.504 129.342 ;
     RECT  13.504 47.184 14.821 47.208 ;
     RECT  13.504 72.672 14.821 72.696 ;
     RECT  13.504 78.336 14.821 78.36 ;
     RECT  13.504 84.288 14.821 84.312 ;
     RECT  14.821 47.088 14.861 47.208 ;
     RECT  14.821 72.672 14.861 72.792 ;
     RECT  14.821 78.336 14.861 78.456 ;
     RECT  14.821 84.144 14.861 84.312 ;
     RECT  14.861 47.088 15.908 47.112 ;
     RECT  13.504 50.544 15.908 50.568 ;
     RECT  14.861 72.768 15.908 72.792 ;
     RECT  14.861 78.432 15.908 78.456 ;
     RECT  13.504 81.12 15.908 81.144 ;
     RECT  14.861 84.144 15.908 84.168 ;
     RECT  13.504 97.104 15.908 97.128 ;
     RECT  13.504 98.88 15.908 98.904 ;
     RECT  15.908 2.148 16.012 129.612 ;
     RECT  16.012 2.418 16.204 129.342 ;
     RECT  5.653 131.616 17.089 131.64 ;
     RECT  17.089 131.52 17.129 131.64 ;
     RECT  17.129 131.52 17.309 131.544 ;
     RECT  16.204 47.088 18.608 47.112 ;
     RECT  16.204 50.544 18.608 50.568 ;
     RECT  16.204 72.768 18.608 72.792 ;
     RECT  16.204 78.432 18.608 78.456 ;
     RECT  16.204 81.12 18.608 81.144 ;
     RECT  16.204 84.144 18.608 84.168 ;
     RECT  16.204 97.104 18.608 97.128 ;
     RECT  16.204 98.88 18.608 98.904 ;
     RECT  18.608 2.148 18.712 129.612 ;
     RECT  18.712 2.418 18.904 129.342 ;
     RECT  18.904 47.088 21.308 47.112 ;
     RECT  18.904 50.544 21.308 50.568 ;
     RECT  18.904 72.768 21.308 72.792 ;
     RECT  18.904 78.336 21.308 78.36 ;
     RECT  18.904 81.12 21.308 81.144 ;
     RECT  18.904 84.288 21.308 84.312 ;
     RECT  18.904 97.104 21.308 97.128 ;
     RECT  18.904 98.88 21.308 98.904 ;
     RECT  21.308 2.148 21.412 129.612 ;
     RECT  21.412 2.418 21.604 129.342 ;
     RECT  21.604 47.088 21.701 47.208 ;
     RECT  21.604 72.672 21.701 72.792 ;
     RECT  21.701 47.184 22.813 47.208 ;
     RECT  21.701 72.672 22.813 72.696 ;
     RECT  22.813 47.088 22.853 47.208 ;
     RECT  22.813 72.672 22.853 72.792 ;
     RECT  21.604 78.336 23.893 78.36 ;
     RECT  21.604 84.288 23.893 84.312 ;
     RECT  22.853 47.088 24.008 47.112 ;
     RECT  21.604 50.544 24.008 50.568 ;
     RECT  22.853 72.768 24.008 72.792 ;
     RECT  23.893 78.336 24.008 78.456 ;
     RECT  21.604 81.12 24.008 81.144 ;
     RECT  23.893 84.144 24.008 84.312 ;
     RECT  21.604 97.104 24.008 97.128 ;
     RECT  21.604 98.88 24.008 98.904 ;
     RECT  24.008 2.148 24.112 129.612 ;
     RECT  24.112 2.418 24.304 129.342 ;
     RECT  24.304 47.088 26.708 47.112 ;
     RECT  24.304 50.544 26.708 50.568 ;
     RECT  24.304 72.768 26.708 72.792 ;
     RECT  24.304 78.432 26.708 78.456 ;
     RECT  24.304 81.12 26.708 81.144 ;
     RECT  24.304 84.144 26.708 84.168 ;
     RECT  24.304 97.104 26.708 97.128 ;
     RECT  24.304 98.88 26.708 98.904 ;
     RECT  26.708 2.148 26.812 129.612 ;
     RECT  26.812 2.418 27.004 129.342 ;
     RECT  27.004 47.088 29.408 47.112 ;
     RECT  27.004 50.544 29.408 50.568 ;
     RECT  27.004 72.768 29.408 72.792 ;
     RECT  27.004 78.432 29.408 78.456 ;
     RECT  27.004 81.12 29.408 81.144 ;
     RECT  27.004 84.336 29.408 84.36 ;
     RECT  27.004 97.104 29.408 97.128 ;
     RECT  27.004 98.88 29.408 98.904 ;
     RECT  29.408 2.148 29.512 129.612 ;
     RECT  29.512 2.418 29.704 129.342 ;
     RECT  29.704 98.592 29.765 98.904 ;
     RECT  29.704 84.336 29.801 84.36 ;
     RECT  29.704 72.192 30.125 72.792 ;
     RECT  29.704 95.472 30.125 97.128 ;
     RECT  29.704 114.816 30.197 114.84 ;
     RECT  29.704 68.928 30.269 69.192 ;
     RECT  29.704 20.544 30.305 20.568 ;
     RECT  29.704 7.056 30.341 7.896 ;
     RECT  29.704 79.536 30.629 81.144 ;
     RECT  29.704 63.024 30.701 63.816 ;
     RECT  30.125 72.24 30.701 72.792 ;
     RECT  29.704 78.432 30.733 78.456 ;
     RECT  29.765 98.592 30.733 98.616 ;
     RECT  29.704 105.984 30.733 106.008 ;
     RECT  29.704 116.112 30.733 116.136 ;
     RECT  29.704 118.608 30.737 120.792 ;
     RECT  30.341 7.824 30.769 7.896 ;
     RECT  29.704 47.088 30.769 47.64 ;
     RECT  30.733 75.552 30.769 75.576 ;
     RECT  29.704 82.128 30.769 82.2 ;
     RECT  30.769 7.824 30.773 7.992 ;
     RECT  30.701 63.696 30.773 63.816 ;
     RECT  29.704 122.256 30.773 123.192 ;
     RECT  30.769 19.536 30.805 19.56 ;
     RECT  30.769 47.088 30.805 48.408 ;
     RECT  29.704 49.44 30.805 49.56 ;
     RECT  30.629 80.592 30.805 81.144 ;
     RECT  30.769 82.128 30.805 82.488 ;
     RECT  30.773 63.792 30.809 63.816 ;
     RECT  30.269 69.12 30.809 69.192 ;
     RECT  29.704 30.144 30.841 30.6 ;
     RECT  30.769 85.44 30.841 85.464 ;
     RECT  29.704 113.472 30.841 113.496 ;
     RECT  29.704 42.096 30.845 43.752 ;
     RECT  30.733 60.912 30.845 60.936 ;
     RECT  30.737 118.608 30.845 119.544 ;
     RECT  29.704 58.128 30.877 58.152 ;
     RECT  29.704 28.128 30.881 28.152 ;
     RECT  30.769 102.576 30.881 102.6 ;
     RECT  29.704 39.072 30.913 39.096 ;
     RECT  30.769 52.608 30.913 52.632 ;
     RECT  29.704 54.96 30.913 54.984 ;
     RECT  30.805 80.592 30.917 82.488 ;
     RECT  30.841 29.52 30.953 30.744 ;
     RECT  30.841 112.704 30.985 113.496 ;
     RECT  30.697 114.576 30.985 114.6 ;
     RECT  30.733 115.632 30.989 116.136 ;
     RECT  30.805 47.088 31.021 49.56 ;
     RECT  30.773 7.872 31.025 7.992 ;
     RECT  29.704 11.76 31.025 11.784 ;
     RECT  30.769 93.024 31.061 93.864 ;
     RECT  30.733 77.856 31.093 78.456 ;
     RECT  30.989 115.632 31.097 115.656 ;
     RECT  30.805 19.536 31.133 19.848 ;
     RECT  30.913 38.64 31.165 39.096 ;
     RECT  30.125 95.472 31.165 96.216 ;
     RECT  31.061 93.024 31.201 93.816 ;
     RECT  31.165 37.872 31.237 39.096 ;
     RECT  30.733 97.92 31.237 98.616 ;
     RECT  31.201 66.576 31.273 66.6 ;
     RECT  30.841 84.624 31.309 85.464 ;
     RECT  31.093 77.856 31.345 79.272 ;
     RECT  30.733 105.984 31.345 106.536 ;
     RECT  30.697 56.832 31.489 56.856 ;
     RECT  30.877 57.888 31.489 58.152 ;
     RECT  30.769 70.416 31.489 70.44 ;
     RECT  30.913 54.96 31.741 55.224 ;
     RECT  31.201 18.72 31.921 18.744 ;
     RECT  30.953 29.52 31.921 30.168 ;
     RECT  30.845 42.528 31.921 43.752 ;
     RECT  31.273 66.576 31.921 66.648 ;
     RECT  30.701 72.432 31.921 72.792 ;
     RECT  30.769 75.216 31.921 75.816 ;
     RECT  30.917 80.592 31.921 81.432 ;
     RECT  30.917 82.464 31.921 82.488 ;
     RECT  30.985 89.472 31.921 89.496 ;
     RECT  31.669 110.496 31.921 110.52 ;
     RECT  31.921 42.528 31.957 43.848 ;
     RECT  31.345 45.216 31.957 45.24 ;
     RECT  31.957 22.56 31.993 22.584 ;
     RECT  31.453 6.816 32.108 6.84 ;
     RECT  31.025 7.968 32.108 7.992 ;
     RECT  30.805 10.608 32.108 10.632 ;
     RECT  31.309 15.504 32.108 15.528 ;
     RECT  30.949 17.04 32.108 17.064 ;
     RECT  31.921 18.528 32.108 18.744 ;
     RECT  31.133 19.824 32.108 19.848 ;
     RECT  31.993 22.272 32.108 22.584 ;
     RECT  32.065 23.568 32.108 23.592 ;
     RECT  32.029 24.672 32.108 24.696 ;
     RECT  31.921 26.64 32.108 26.664 ;
     RECT  31.921 29.52 32.108 30.888 ;
     RECT  31.237 37.584 32.108 39.096 ;
     RECT  30.877 40.896 32.108 40.92 ;
     RECT  31.957 42.528 32.108 45.24 ;
     RECT  31.021 46.32 32.108 49.56 ;
     RECT  29.704 50.544 32.108 50.568 ;
     RECT  30.913 51.936 32.108 52.632 ;
     RECT  31.741 54.96 32.108 55.512 ;
     RECT  31.489 56.832 32.108 58.152 ;
     RECT  31.957 60 32.108 60.024 ;
     RECT  31.201 62.544 32.108 62.568 ;
     RECT  31.921 65.232 32.108 65.256 ;
     RECT  31.921 66.528 32.108 66.648 ;
     RECT  30.809 69.168 32.108 69.192 ;
     RECT  31.489 70.224 32.108 70.44 ;
     RECT  31.921 71.424 32.108 72.792 ;
     RECT  31.921 74.64 32.108 75.816 ;
     RECT  31.345 77.568 32.108 79.272 ;
     RECT  31.921 80.592 32.108 82.488 ;
     RECT  31.309 84.624 32.108 85.8 ;
     RECT  29.704 87.6 32.108 87.624 ;
     RECT  31.921 89.232 32.108 90.552 ;
     RECT  31.201 92.784 32.108 93.816 ;
     RECT  31.165 95.424 32.108 96.216 ;
     RECT  31.237 97.92 32.108 99.144 ;
     RECT  31.921 101.952 32.108 101.976 ;
     RECT  31.345 104.832 32.108 104.856 ;
     RECT  31.345 105.984 32.108 107.304 ;
     RECT  31.849 109.2 32.108 109.224 ;
     RECT  31.921 110.352 32.108 110.52 ;
     RECT  30.985 112.704 32.108 114.6 ;
     RECT  30.949 117.792 32.108 117.816 ;
     RECT  30.845 118.848 32.108 119.544 ;
     RECT  30.737 120.72 32.108 120.792 ;
     RECT  30.773 122.544 32.108 123.192 ;
     RECT  32.108 2.148 32.212 129.612 ;
     RECT  32.212 2.418 32.404 129.342 ;
     RECT  32.404 4.416 33.613 50.328 ;
     RECT  32.404 51.312 33.613 97.224 ;
     RECT  32.404 98.352 33.613 127.416 ;
     RECT  33.613 4.416 34.38 127.416 ;
     RECT  34.38 125.664 34.409 125.688 ;
    LAYER M5 ;
     RECT  2.4 2.137 2.52 2.151 ;
     RECT  5.1 2.137 5.22 2.151 ;
     RECT  7.8 2.137 7.92 2.151 ;
     RECT  10.5 2.137 10.62 2.151 ;
     RECT  13.2 2.137 13.32 2.151 ;
     RECT  15.9 2.137 16.02 2.151 ;
     RECT  18.6 2.137 18.72 2.151 ;
     RECT  21.3 2.137 21.42 2.151 ;
     RECT  24 2.137 24.12 2.151 ;
     RECT  26.7 2.137 26.82 2.151 ;
     RECT  29.4 2.137 29.52 2.151 ;
     RECT  32.1 2.137 32.22 2.151 ;
     RECT  7.8 2.151 8.112 6.229 ;
     RECT  5.1 2.151 5.412 6.709 ;
     RECT  4.752 6.709 5.412 7.619 ;
     RECT  7.8 6.229 8.328 8.003 ;
     RECT  2.4 2.151 2.712 8.485 ;
     RECT  7.8 8.003 8.112 9.061 ;
     RECT  5.1 7.619 5.412 9.109 ;
     RECT  7.8 9.061 8.376 9.637 ;
     RECT  2.4 8.485 3.432 10.165 ;
     RECT  4.752 9.109 5.412 10.165 ;
     RECT  2.4 10.165 5.412 10.355 ;
     RECT  3.936 10.355 5.412 11.221 ;
     RECT  3.936 11.221 5.544 11.459 ;
     RECT  6.864 9.637 8.376 12.083 ;
     RECT  4.464 11.459 5.544 12.227 ;
     RECT  5.1 12.227 5.544 12.517 ;
     RECT  6.864 12.083 8.232 13.091 ;
     RECT  2.4 10.355 2.712 13.957 ;
     RECT  4.08 12.517 4.104 13.957 ;
     RECT  2.4 13.957 4.104 14.675 ;
     RECT  5.1 12.517 5.64 14.773 ;
     RECT  2.4 14.675 3.528 14.867 ;
     RECT  7.8 13.091 8.232 14.963 ;
     RECT  2.4 14.867 2.712 16.501 ;
     RECT  5.1 14.773 6.312 16.501 ;
     RECT  7.8 14.963 8.112 16.501 ;
     RECT  5.1 16.501 8.112 18.179 ;
     RECT  5.1 18.179 5.688 18.181 ;
     RECT  6.864 18.179 8.112 18.995 ;
     RECT  4.992 18.181 5.688 19.141 ;
     RECT  2.4 16.501 3.192 19.621 ;
     RECT  4.56 19.141 5.688 19.621 ;
     RECT  2.4 19.621 5.688 20.243 ;
     RECT  3.984 20.243 5.688 20.725 ;
     RECT  2.4 20.243 2.712 21.541 ;
     RECT  3.984 20.725 5.928 21.541 ;
     RECT  7.8 18.995 8.112 22.213 ;
     RECT  2.4 21.541 5.928 22.835 ;
     RECT  4.8 22.835 5.928 23.459 ;
     RECT  0.288 23.653 0.312 23.891 ;
     RECT  4.8 23.459 5.688 24.323 ;
     RECT  2.4 22.835 3.384 24.659 ;
     RECT  4.8 24.323 5.412 25.045 ;
     RECT  4.704 25.045 5.412 25.285 ;
     RECT  7.488 22.213 8.112 25.331 ;
     RECT  7.8 25.331 8.112 26.053 ;
     RECT  4.704 25.285 5.928 27.205 ;
     RECT  3.936 27.205 5.928 27.875 ;
     RECT  7.8 26.053 8.328 27.923 ;
     RECT  7.8 27.923 8.112 28.789 ;
     RECT  7.2 28.789 8.112 29.029 ;
     RECT  3.936 27.875 5.784 29.651 ;
     RECT  6.912 29.029 8.112 29.795 ;
     RECT  4.56 29.651 5.784 30.565 ;
     RECT  4.56 30.565 6.12 30.851 ;
     RECT  3.792 30.901 3.816 31.907 ;
     RECT  0.192 31.093 0.216 32.195 ;
     RECT  4.8 30.851 6.12 32.341 ;
     RECT  7.2 29.795 8.112 32.341 ;
     RECT  2.4 24.659 2.712 32.437 ;
     RECT  2.4 32.437 3.432 33.107 ;
     RECT  4.8 32.341 8.112 33.635 ;
     RECT  2.4 33.107 2.712 34.501 ;
     RECT  2.4 34.501 3.624 35.987 ;
     RECT  3.936 36.421 3.96 37.091 ;
     RECT  4.944 33.635 8.112 39.013 ;
     RECT  2.4 35.987 2.712 39.301 ;
     RECT  3.84 38.725 3.864 39.301 ;
     RECT  4.896 39.013 8.112 39.779 ;
     RECT  2.4 39.301 3.864 40.165 ;
     RECT  4.896 39.779 6.264 40.165 ;
     RECT  2.4 40.165 6.264 40.307 ;
     RECT  3.84 40.307 6.264 40.741 ;
     RECT  7.392 39.779 8.112 40.741 ;
     RECT  3.84 40.741 8.112 41.075 ;
     RECT  2.4 40.307 2.712 42.421 ;
     RECT  4.128 41.075 8.112 42.421 ;
     RECT  2.4 42.421 8.112 43.955 ;
     RECT  2.4 43.955 4.056 46.259 ;
     RECT  4.032 46.259 4.056 46.787 ;
     RECT  3.984 47.269 4.008 48.469 ;
     RECT  3.792 48.469 4.008 48.997 ;
     RECT  5.1 43.955 8.112 48.997 ;
     RECT  3.792 48.997 8.112 52.019 ;
     RECT  4.704 52.019 8.112 53.557 ;
     RECT  3.936 53.557 8.112 54.613 ;
     RECT  3.744 54.613 8.112 55.955 ;
     RECT  2.4 46.259 2.712 57.013 ;
     RECT  3.888 55.955 8.112 57.013 ;
     RECT  2.4 57.013 8.112 57.635 ;
     RECT  2.4 57.635 3.816 57.827 ;
     RECT  3.792 57.827 3.816 59.221 ;
     RECT  4.848 57.635 8.112 59.221 ;
     RECT  3.792 59.221 8.112 59.267 ;
     RECT  4.032 59.267 8.112 61.571 ;
     RECT  4.656 61.571 8.112 62.581 ;
     RECT  3.888 62.581 8.112 63.779 ;
     RECT  3.888 63.779 6.264 64.307 ;
     RECT  7.488 63.779 8.112 64.307 ;
     RECT  2.4 57.827 2.712 64.981 ;
     RECT  4.56 64.307 6.264 65.555 ;
     RECT  2.4 64.981 3.528 65.699 ;
     RECT  4.848 65.555 6.264 66.179 ;
     RECT  5.1 66.179 6.264 66.517 ;
     RECT  5.1 66.517 6.648 67.141 ;
     RECT  7.8 64.307 8.112 67.141 ;
     RECT  5.1 67.141 8.112 67.571 ;
     RECT  5.1 67.571 6.264 68.917 ;
     RECT  2.4 65.699 2.712 69.829 ;
     RECT  4.896 68.917 6.264 71.221 ;
     RECT  7.248 67.571 8.112 71.221 ;
     RECT  2.4 69.829 3.432 71.363 ;
     RECT  4.56 71.221 8.112 72.325 ;
     RECT  3.792 72.325 8.112 72.707 ;
     RECT  3.792 72.707 6.36 73.523 ;
     RECT  3.84 73.523 6.36 74.629 ;
     RECT  7.392 72.707 8.112 74.629 ;
     RECT  3.84 74.629 8.112 74.771 ;
     RECT  3.84 74.771 3.864 76.211 ;
     RECT  5.1 74.771 8.112 76.739 ;
     RECT  5.1 76.739 6.36 77.413 ;
     RECT  4.656 77.413 6.36 78.131 ;
     RECT  24 2.151 24.312 78.325 ;
     RECT  23.904 78.325 24.312 78.467 ;
     RECT  4.656 78.131 6.264 78.613 ;
     RECT  7.8 76.739 8.112 78.613 ;
     RECT  2.4 71.363 2.712 79.717 ;
     RECT  7.68 78.613 8.112 79.955 ;
     RECT  2.4 79.717 2.856 80.579 ;
     RECT  3.984 78.613 6.264 81.635 ;
     RECT  2.4 80.579 2.712 82.597 ;
     RECT  4.464 81.635 6.264 82.597 ;
     RECT  7.8 79.955 8.112 83.749 ;
     RECT  2.4 82.597 6.264 83.843 ;
     RECT  4.56 83.843 6.264 84.037 ;
     RECT  7.8 83.749 8.232 84.037 ;
     RECT  24 78.467 24.312 84.133 ;
     RECT  4.56 84.037 8.232 84.179 ;
     RECT  23.904 84.133 24.312 84.323 ;
     RECT  4.56 84.179 6.264 85.523 ;
     RECT  4.992 85.523 6.264 87.157 ;
     RECT  2.4 83.843 3.528 87.973 ;
     RECT  4.512 87.157 6.456 87.973 ;
     RECT  2.4 87.973 6.456 89.461 ;
     RECT  7.8 84.179 8.232 89.461 ;
     RECT  2.4 89.461 8.232 89.843 ;
     RECT  2.4 89.843 8.112 91.331 ;
     RECT  3.936 91.331 8.112 94.115 ;
     RECT  3.936 94.115 6.024 94.213 ;
     RECT  3.792 94.213 6.024 94.307 ;
     RECT  34.272 94.597 34.296 94.739 ;
     RECT  5.1 94.307 6.024 95.411 ;
     RECT  5.1 95.411 5.976 96.181 ;
     RECT  4.896 96.181 5.976 97.139 ;
     RECT  3.792 94.307 3.816 97.283 ;
     RECT  5.1 97.139 5.976 97.957 ;
     RECT  5.1 97.957 6.312 98.005 ;
     RECT  7.392 94.115 8.112 98.005 ;
     RECT  5.1 98.005 8.112 98.485 ;
     RECT  2.4 91.331 2.712 98.533 ;
     RECT  2.4 98.533 3.432 98.915 ;
     RECT  4.608 98.485 8.112 99.157 ;
     RECT  4.416 99.157 8.112 99.779 ;
     RECT  4.416 99.779 6.696 100.499 ;
     RECT  4.416 100.499 5.976 101.989 ;
     RECT  2.4 98.915 2.712 102.277 ;
     RECT  3.84 101.989 5.976 102.277 ;
     RECT  2.4 102.277 5.976 102.707 ;
     RECT  2.4 102.707 2.712 103.717 ;
     RECT  3.84 102.707 5.976 103.717 ;
     RECT  2.4 103.717 5.976 104.149 ;
     RECT  2.4 104.149 6.648 105.445 ;
     RECT  2.4 105.445 6.696 105.923 ;
     RECT  5.1 105.923 6.696 106.403 ;
     RECT  5.1 106.403 6.648 108.325 ;
     RECT  7.68 99.779 8.112 108.325 ;
     RECT  2.4 105.923 3.672 108.613 ;
     RECT  5.1 108.325 8.112 108.613 ;
     RECT  2.4 108.613 8.112 108.899 ;
     RECT  2.4 108.899 2.712 110.485 ;
     RECT  4.56 108.899 8.112 110.531 ;
     RECT  4.56 110.531 6.312 112.931 ;
     RECT  2.4 110.485 3.48 113.077 ;
     RECT  4.56 112.931 5.688 113.077 ;
     RECT  7.8 110.531 8.112 113.845 ;
     RECT  2.4 113.077 5.688 116.677 ;
     RECT  7.8 113.845 8.232 117.539 ;
     RECT  2.4 116.677 6.648 118.501 ;
     RECT  7.8 117.539 8.112 118.501 ;
     RECT  2.4 118.501 8.112 118.595 ;
     RECT  4.032 118.595 5.688 119.653 ;
     RECT  3.792 119.653 5.688 120.085 ;
     RECT  3.792 120.085 6.024 120.323 ;
     RECT  7.2 118.595 8.112 120.899 ;
     RECT  3.792 120.323 4.056 121.333 ;
     RECT  5.1 120.323 6.024 121.333 ;
     RECT  7.8 120.899 8.112 121.957 ;
     RECT  3.792 121.333 6.024 123.971 ;
     RECT  3.792 123.971 5.688 125.221 ;
     RECT  3.792 125.221 5.928 125.315 ;
     RECT  7.392 121.957 8.112 125.603 ;
     RECT  4.512 125.315 5.928 126.469 ;
     RECT  3.936 126.469 5.928 126.611 ;
     RECT  5.1 126.611 5.928 126.707 ;
     RECT  3.936 126.611 3.96 127.139 ;
     RECT  2.4 118.595 2.712 129.609 ;
     RECT  7.8 125.603 8.112 129.609 ;
     RECT  10.5 2.151 10.812 129.609 ;
     RECT  13.2 2.151 13.512 129.609 ;
     RECT  15.9 2.151 16.212 129.609 ;
     RECT  18.6 2.151 18.912 129.609 ;
     RECT  21.3 2.151 21.612 129.609 ;
     RECT  24 84.323 24.312 129.609 ;
     RECT  26.7 2.151 27.012 129.609 ;
     RECT  29.4 2.151 29.712 129.609 ;
     RECT  32.1 2.151 32.412 129.609 ;
     RECT  2.4 129.609 2.52 129.623 ;
     RECT  5.1 126.707 5.688 129.623 ;
     RECT  7.8 129.609 7.92 129.623 ;
     RECT  10.5 129.609 10.62 129.623 ;
     RECT  13.2 129.609 13.32 129.623 ;
     RECT  15.9 129.609 16.02 129.623 ;
     RECT  18.6 129.609 18.72 129.623 ;
     RECT  21.3 129.609 21.42 129.623 ;
     RECT  24 129.609 24.12 129.623 ;
     RECT  26.7 129.609 26.82 129.623 ;
     RECT  29.4 129.609 29.52 129.623 ;
     RECT  32.1 129.609 32.22 129.623 ;
     RECT  5.664 129.623 5.688 131.651 ;
     RECT  4.752 7.619 5.1 8.485 ;
     RECT  8.112 8.003 8.328 9.061 ;
     RECT  3.432 8.485 5.1 9.109 ;
     RECT  3.432 9.109 4.752 10.165 ;
     RECT  5.412 9.637 6.864 11.221 ;
     RECT  2.712 10.355 3.936 11.459 ;
     RECT  5.544 11.221 6.864 12.517 ;
     RECT  2.712 11.459 4.464 12.227 ;
     RECT  2.712 12.227 5.1 12.517 ;
     RECT  2.712 12.517 4.08 13.957 ;
     RECT  4.104 12.517 5.1 14.675 ;
     RECT  5.64 12.517 6.864 13.091 ;
     RECT  6.312 14.773 7.8 16.501 ;
     RECT  5.688 18.179 6.864 18.995 ;
     RECT  3.192 19.141 4.56 19.621 ;
     RECT  2.712 20.243 3.984 21.541 ;
     RECT  3.384 22.835 4.8 24.659 ;
     RECT  5.412 24.323 5.688 25.285 ;
     RECT  4.704 24.659 4.8 25.045 ;
     RECT  2.712 27.205 3.936 29.651 ;
     RECT  5.784 27.875 5.928 28.789 ;
     RECT  5.784 28.789 7.2 29.029 ;
     RECT  5.784 29.029 6.912 29.795 ;
     RECT  2.712 29.651 4.56 30.851 ;
     RECT  5.784 29.795 7.2 30.565 ;
     RECT  6.12 30.565 7.2 32.341 ;
     RECT  2.712 30.851 4.8 30.901 ;
     RECT  2.712 30.901 3.792 31.907 ;
     RECT  3.816 30.901 4.8 31.907 ;
     RECT  2.712 31.907 4.8 32.437 ;
     RECT  3.432 32.437 4.8 33.107 ;
     RECT  2.712 33.107 4.8 33.635 ;
     RECT  2.712 33.635 4.944 34.501 ;
     RECT  3.624 34.501 4.944 35.987 ;
     RECT  2.712 35.987 4.944 36.421 ;
     RECT  2.712 36.421 3.936 37.091 ;
     RECT  3.96 36.421 4.944 37.091 ;
     RECT  2.712 38.725 3.84 39.301 ;
     RECT  3.864 38.725 4.944 39.013 ;
     RECT  3.864 39.013 4.896 40.165 ;
     RECT  6.264 39.779 7.392 40.741 ;
     RECT  2.712 40.307 3.84 41.075 ;
     RECT  2.712 41.075 4.128 42.421 ;
     RECT  4.056 43.955 5.1 46.787 ;
     RECT  2.712 46.259 4.032 46.787 ;
     RECT  2.712 46.787 5.1 47.269 ;
     RECT  2.712 47.269 3.984 48.469 ;
     RECT  4.008 47.269 5.1 48.997 ;
     RECT  2.712 48.469 3.792 52.019 ;
     RECT  2.712 53.557 3.936 54.613 ;
     RECT  2.712 54.613 3.744 55.955 ;
     RECT  2.712 55.955 3.888 57.013 ;
     RECT  3.816 57.635 4.848 59.221 ;
     RECT  2.712 57.827 3.792 59.267 ;
     RECT  2.712 59.267 4.032 61.571 ;
     RECT  2.712 61.571 4.656 62.581 ;
     RECT  2.712 62.581 3.888 64.307 ;
     RECT  6.264 63.779 7.488 64.307 ;
     RECT  2.712 64.307 4.56 64.981 ;
     RECT  3.528 64.981 4.56 65.555 ;
     RECT  3.528 65.555 4.848 65.699 ;
     RECT  6.648 66.517 7.8 67.141 ;
     RECT  6.264 67.571 7.248 71.221 ;
     RECT  3.432 69.829 4.896 71.221 ;
     RECT  3.432 71.221 4.56 71.363 ;
     RECT  2.712 71.363 4.56 72.325 ;
     RECT  2.712 72.325 3.792 73.523 ;
     RECT  6.36 72.707 7.392 74.629 ;
     RECT  2.712 73.523 3.84 76.211 ;
     RECT  3.864 74.771 5.1 76.211 ;
     RECT  4.656 76.211 5.1 77.413 ;
     RECT  6.36 76.739 7.8 78.131 ;
     RECT  6.264 78.131 7.8 78.613 ;
     RECT  2.712 78.613 3.984 79.717 ;
     RECT  6.264 78.613 7.68 79.955 ;
     RECT  2.856 79.717 3.984 80.579 ;
     RECT  2.712 80.579 3.984 81.635 ;
     RECT  2.712 81.635 4.464 82.597 ;
     RECT  3.528 83.843 4.56 85.523 ;
     RECT  3.528 85.523 4.992 87.157 ;
     RECT  3.528 87.157 4.512 87.973 ;
     RECT  6.456 87.157 7.8 89.461 ;
     RECT  2.712 91.331 3.936 94.213 ;
     RECT  6.024 94.115 7.392 95.411 ;
     RECT  2.712 94.213 3.792 97.283 ;
     RECT  3.816 94.307 5.1 96.181 ;
     RECT  5.976 95.411 7.392 97.957 ;
     RECT  3.816 96.181 4.896 97.139 ;
     RECT  3.816 97.139 5.1 97.283 ;
     RECT  2.712 97.283 5.1 98.485 ;
     RECT  6.312 97.957 7.392 98.005 ;
     RECT  2.712 98.485 4.608 98.533 ;
     RECT  3.432 98.533 4.608 98.915 ;
     RECT  4.416 98.915 4.608 99.157 ;
     RECT  6.696 99.779 7.68 100.499 ;
     RECT  2.712 101.989 3.84 102.277 ;
     RECT  2.712 102.707 3.84 103.717 ;
     RECT  6.648 104.149 7.68 105.445 ;
     RECT  6.696 105.445 7.68 106.403 ;
     RECT  3.672 105.923 5.1 108.613 ;
     RECT  6.648 106.403 7.68 108.325 ;
     RECT  3.48 110.485 4.56 113.077 ;
     RECT  6.312 110.531 7.8 112.931 ;
     RECT  6.648 116.677 7.8 118.501 ;
     RECT  2.712 118.595 4.032 119.653 ;
     RECT  5.688 118.595 7.2 120.085 ;
     RECT  2.712 119.653 3.792 125.315 ;
     RECT  6.024 120.085 7.2 120.899 ;
     RECT  4.056 120.323 5.1 121.333 ;
     RECT  6.024 120.899 7.8 121.957 ;
     RECT  6.024 121.957 7.392 123.971 ;
     RECT  5.688 123.971 7.392 125.221 ;
     RECT  5.928 125.221 7.392 125.603 ;
     RECT  2.712 125.315 4.512 126.469 ;
     RECT  2.712 126.469 3.936 127.139 ;
     RECT  3.96 126.611 5.1 127.139 ;
  END
END dsfd_hstnh_759
END LIBRARY
